VERSION 5.8 ;
BUSBITCHARS "[]" ;
DIVIDERCHAR "/" ;
UNITS
    DATABASE MICRONS 1000 ;
END UNITS

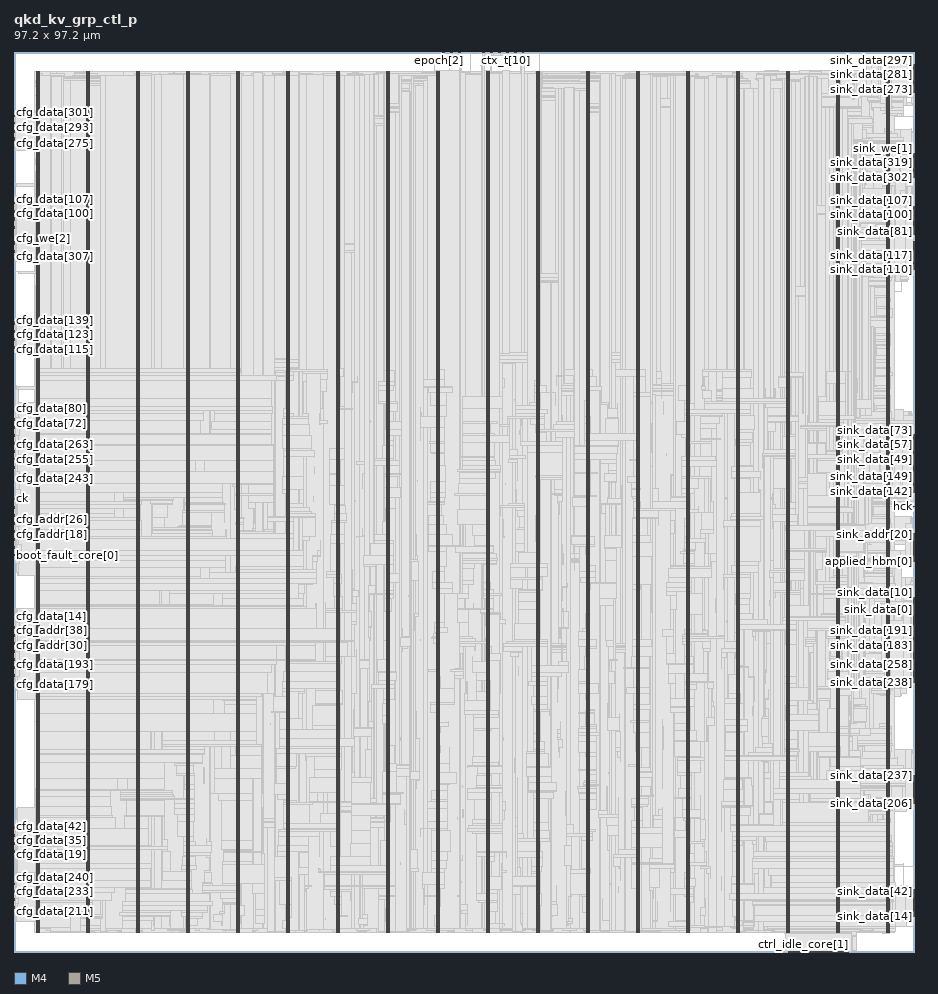
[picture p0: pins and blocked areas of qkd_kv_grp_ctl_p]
MACRO qkd_kv_grp_ctl_p
  FOREIGN qkd_kv_grp_ctl_p 0 0 ;
  CLASS BLOCK ;
  SIZE 97.2 BY 97.2 ;
  PIN applied_hbm[0]
    DIRECTION OUTPUT ;
    USE SIGNAL ;
    PORT
      LAYER M4 ;
        RECT  97.116 42.192 97.2 42.216 ;
    END
  END applied_hbm[0]
  PIN applied_hbm[1]
    DIRECTION OUTPUT ;
    USE SIGNAL ;
    PORT
      LAYER M4 ;
        RECT  97.116 42.288 97.2 42.312 ;
    END
  END applied_hbm[1]
  PIN applied_hbm[2]
    DIRECTION OUTPUT ;
    USE SIGNAL ;
    PORT
      LAYER M4 ;
        RECT  97.116 42.384 97.2 42.408 ;
    END
  END applied_hbm[2]
  PIN applied_hbm[3]
    DIRECTION OUTPUT ;
    USE SIGNAL ;
    PORT
      LAYER M4 ;
        RECT  97.116 42.48 97.2 42.504 ;
    END
  END applied_hbm[3]
  PIN applied_hbm[4]
    DIRECTION OUTPUT ;
    USE SIGNAL ;
    PORT
      LAYER M4 ;
        RECT  97.116 42.576 97.2 42.6 ;
    END
  END applied_hbm[4]
  PIN boot_fault_core[0]
    DIRECTION OUTPUT ;
    USE SIGNAL ;
    PORT
      LAYER M4 ;
        RECT  0 42.864 0.084 42.888 ;
    END
  END boot_fault_core[0]
  PIN boot_fault_core[1]
    DIRECTION OUTPUT ;
    USE SIGNAL ;
    PORT
      LAYER M4 ;
        RECT  0 42.96 0.084 42.984 ;
    END
  END boot_fault_core[1]
  PIN boot_fault_core[2]
    DIRECTION OUTPUT ;
    USE SIGNAL ;
    PORT
      LAYER M4 ;
        RECT  0 43.056 0.084 43.08 ;
    END
  END boot_fault_core[2]
  PIN boot_fault_core[3]
    DIRECTION OUTPUT ;
    USE SIGNAL ;
    PORT
      LAYER M4 ;
        RECT  0 43.152 0.084 43.176 ;
    END
  END boot_fault_core[3]
  PIN boot_fault_core[4]
    DIRECTION OUTPUT ;
    USE SIGNAL ;
    PORT
      LAYER M4 ;
        RECT  0 43.248 0.084 43.272 ;
    END
  END boot_fault_core[4]
  PIN boot_fault_hbm[0]
    DIRECTION OUTPUT ;
    USE SIGNAL ;
    PORT
      LAYER M4 ;
        RECT  97.116 42.672 97.2 42.696 ;
    END
  END boot_fault_hbm[0]
  PIN boot_fault_hbm[1]
    DIRECTION OUTPUT ;
    USE SIGNAL ;
    PORT
      LAYER M4 ;
        RECT  97.116 42.768 97.2 42.792 ;
    END
  END boot_fault_hbm[1]
  PIN boot_fault_hbm[2]
    DIRECTION OUTPUT ;
    USE SIGNAL ;
    PORT
      LAYER M4 ;
        RECT  97.116 42.864 97.2 42.888 ;
    END
  END boot_fault_hbm[2]
  PIN boot_fault_hbm[3]
    DIRECTION OUTPUT ;
    USE SIGNAL ;
    PORT
      LAYER M4 ;
        RECT  97.116 42.96 97.2 42.984 ;
    END
  END boot_fault_hbm[3]
  PIN boot_fault_hbm[4]
    DIRECTION OUTPUT ;
    USE SIGNAL ;
    PORT
      LAYER M4 ;
        RECT  97.116 43.056 97.2 43.08 ;
    END
  END boot_fault_hbm[4]
  PIN cfg_addr[0]
    DIRECTION INPUT ;
    USE SIGNAL ;
    PORT
      LAYER M4 ;
        RECT  0 43.344 0.084 43.368 ;
    END
  END cfg_addr[0]
  PIN cfg_addr[10]
    DIRECTION INPUT ;
    USE SIGNAL ;
    PORT
      LAYER M4 ;
        RECT  0 44.304 0.084 44.328 ;
    END
  END cfg_addr[10]
  PIN cfg_addr[11]
    DIRECTION INPUT ;
    USE SIGNAL ;
    PORT
      LAYER M4 ;
        RECT  0 44.4 0.084 44.424 ;
    END
  END cfg_addr[11]
  PIN cfg_addr[12]
    DIRECTION INPUT ;
    USE SIGNAL ;
    PORT
      LAYER M4 ;
        RECT  0 44.496 0.084 44.52 ;
    END
  END cfg_addr[12]
  PIN cfg_addr[13]
    DIRECTION INPUT ;
    USE SIGNAL ;
    PORT
      LAYER M4 ;
        RECT  0 44.592 0.084 44.616 ;
    END
  END cfg_addr[13]
  PIN cfg_addr[14]
    DIRECTION INPUT ;
    USE SIGNAL ;
    PORT
      LAYER M4 ;
        RECT  0 44.688 0.084 44.712 ;
    END
  END cfg_addr[14]
  PIN cfg_addr[15]
    DIRECTION INPUT ;
    USE SIGNAL ;
    PORT
      LAYER M4 ;
        RECT  0 44.784 0.084 44.808 ;
    END
  END cfg_addr[15]
  PIN cfg_addr[16]
    DIRECTION INPUT ;
    USE SIGNAL ;
    PORT
      LAYER M4 ;
        RECT  0 44.88 0.084 44.904 ;
    END
  END cfg_addr[16]
  PIN cfg_addr[17]
    DIRECTION INPUT ;
    USE SIGNAL ;
    PORT
      LAYER M4 ;
        RECT  0 44.976 0.084 45 ;
    END
  END cfg_addr[17]
  PIN cfg_addr[18]
    DIRECTION INPUT ;
    USE SIGNAL ;
    PORT
      LAYER M4 ;
        RECT  0 45.072 0.084 45.096 ;
    END
  END cfg_addr[18]
  PIN cfg_addr[19]
    DIRECTION INPUT ;
    USE SIGNAL ;
    PORT
      LAYER M4 ;
        RECT  0 45.168 0.084 45.192 ;
    END
  END cfg_addr[19]
  PIN cfg_addr[1]
    DIRECTION INPUT ;
    USE SIGNAL ;
    PORT
      LAYER M4 ;
        RECT  0 43.44 0.084 43.464 ;
    END
  END cfg_addr[1]
  PIN cfg_addr[20]
    DIRECTION INPUT ;
    USE SIGNAL ;
    PORT
      LAYER M4 ;
        RECT  0 45.264 0.084 45.288 ;
    END
  END cfg_addr[20]
  PIN cfg_addr[21]
    DIRECTION INPUT ;
    USE SIGNAL ;
    PORT
      LAYER M4 ;
        RECT  0 45.36 0.084 45.384 ;
    END
  END cfg_addr[21]
  PIN cfg_addr[22]
    DIRECTION INPUT ;
    USE SIGNAL ;
    PORT
      LAYER M4 ;
        RECT  0 45.456 0.084 45.48 ;
    END
  END cfg_addr[22]
  PIN cfg_addr[23]
    DIRECTION INPUT ;
    USE SIGNAL ;
    PORT
      LAYER M4 ;
        RECT  0 45.552 0.084 45.576 ;
    END
  END cfg_addr[23]
  PIN cfg_addr[24]
    DIRECTION INPUT ;
    USE SIGNAL ;
    PORT
      LAYER M4 ;
        RECT  0 45.648 0.084 45.672 ;
    END
  END cfg_addr[24]
  PIN cfg_addr[25]
    DIRECTION INPUT ;
    USE SIGNAL ;
    PORT
      LAYER M4 ;
        RECT  0 45.744 0.084 45.768 ;
    END
  END cfg_addr[25]
  PIN cfg_addr[26]
    DIRECTION INPUT ;
    USE SIGNAL ;
    PORT
      LAYER M4 ;
        RECT  0 45.84 0.084 45.864 ;
    END
  END cfg_addr[26]
  PIN cfg_addr[27]
    DIRECTION INPUT ;
    USE SIGNAL ;
    PORT
      LAYER M4 ;
        RECT  0 32.784 0.084 32.808 ;
    END
  END cfg_addr[27]
  PIN cfg_addr[28]
    DIRECTION INPUT ;
    USE SIGNAL ;
    PORT
      LAYER M4 ;
        RECT  0 32.88 0.084 32.904 ;
    END
  END cfg_addr[28]
  PIN cfg_addr[29]
    DIRECTION INPUT ;
    USE SIGNAL ;
    PORT
      LAYER M4 ;
        RECT  0 32.976 0.084 33 ;
    END
  END cfg_addr[29]
  PIN cfg_addr[2]
    DIRECTION INPUT ;
    USE SIGNAL ;
    PORT
      LAYER M4 ;
        RECT  0 43.536 0.084 43.56 ;
    END
  END cfg_addr[2]
  PIN cfg_addr[30]
    DIRECTION INPUT ;
    USE SIGNAL ;
    PORT
      LAYER M4 ;
        RECT  0 33.072 0.084 33.096 ;
    END
  END cfg_addr[30]
  PIN cfg_addr[31]
    DIRECTION INPUT ;
    USE SIGNAL ;
    PORT
      LAYER M4 ;
        RECT  0 33.168 0.084 33.192 ;
    END
  END cfg_addr[31]
  PIN cfg_addr[32]
    DIRECTION INPUT ;
    USE SIGNAL ;
    PORT
      LAYER M4 ;
        RECT  0 33.264 0.084 33.288 ;
    END
  END cfg_addr[32]
  PIN cfg_addr[33]
    DIRECTION INPUT ;
    USE SIGNAL ;
    PORT
      LAYER M4 ;
        RECT  0 33.36 0.084 33.384 ;
    END
  END cfg_addr[33]
  PIN cfg_addr[34]
    DIRECTION INPUT ;
    USE SIGNAL ;
    PORT
      LAYER M4 ;
        RECT  0 33.456 0.084 33.48 ;
    END
  END cfg_addr[34]
  PIN cfg_addr[35]
    DIRECTION INPUT ;
    USE SIGNAL ;
    PORT
      LAYER M4 ;
        RECT  0 33.552 0.084 33.576 ;
    END
  END cfg_addr[35]
  PIN cfg_addr[36]
    DIRECTION INPUT ;
    USE SIGNAL ;
    PORT
      LAYER M4 ;
        RECT  0 33.648 0.084 33.672 ;
    END
  END cfg_addr[36]
  PIN cfg_addr[37]
    DIRECTION INPUT ;
    USE SIGNAL ;
    PORT
      LAYER M4 ;
        RECT  0 33.744 0.084 33.768 ;
    END
  END cfg_addr[37]
  PIN cfg_addr[38]
    DIRECTION INPUT ;
    USE SIGNAL ;
    PORT
      LAYER M4 ;
        RECT  0 33.84 0.084 33.864 ;
    END
  END cfg_addr[38]
  PIN cfg_addr[39]
    DIRECTION INPUT ;
    USE SIGNAL ;
    PORT
      LAYER M4 ;
        RECT  0 33.936 0.084 33.96 ;
    END
  END cfg_addr[39]
  PIN cfg_addr[3]
    DIRECTION INPUT ;
    USE SIGNAL ;
    PORT
      LAYER M4 ;
        RECT  0 43.632 0.084 43.656 ;
    END
  END cfg_addr[3]
  PIN cfg_addr[4]
    DIRECTION INPUT ;
    USE SIGNAL ;
    PORT
      LAYER M4 ;
        RECT  0 43.728 0.084 43.752 ;
    END
  END cfg_addr[4]
  PIN cfg_addr[5]
    DIRECTION INPUT ;
    USE SIGNAL ;
    PORT
      LAYER M4 ;
        RECT  0 43.824 0.084 43.848 ;
    END
  END cfg_addr[5]
  PIN cfg_addr[6]
    DIRECTION INPUT ;
    USE SIGNAL ;
    PORT
      LAYER M4 ;
        RECT  0 43.92 0.084 43.944 ;
    END
  END cfg_addr[6]
  PIN cfg_addr[7]
    DIRECTION INPUT ;
    USE SIGNAL ;
    PORT
      LAYER M4 ;
        RECT  0 44.016 0.084 44.04 ;
    END
  END cfg_addr[7]
  PIN cfg_addr[8]
    DIRECTION INPUT ;
    USE SIGNAL ;
    PORT
      LAYER M4 ;
        RECT  0 44.112 0.084 44.136 ;
    END
  END cfg_addr[8]
  PIN cfg_addr[9]
    DIRECTION INPUT ;
    USE SIGNAL ;
    PORT
      LAYER M4 ;
        RECT  0 44.208 0.084 44.232 ;
    END
  END cfg_addr[9]
  PIN cfg_data[0]
    DIRECTION INPUT ;
    USE SIGNAL ;
    PORT
      LAYER M4 ;
        RECT  0 34.032 0.084 34.056 ;
    END
  END cfg_data[0]
  PIN cfg_data[100]
    DIRECTION INPUT ;
    USE SIGNAL ;
    PORT
      LAYER M4 ;
        RECT  0 79.728 0.084 79.752 ;
    END
  END cfg_data[100]
  PIN cfg_data[101]
    DIRECTION INPUT ;
    USE SIGNAL ;
    PORT
      LAYER M4 ;
        RECT  0 79.824 0.084 79.848 ;
    END
  END cfg_data[101]
  PIN cfg_data[102]
    DIRECTION INPUT ;
    USE SIGNAL ;
    PORT
      LAYER M4 ;
        RECT  0 79.92 0.084 79.944 ;
    END
  END cfg_data[102]
  PIN cfg_data[103]
    DIRECTION INPUT ;
    USE SIGNAL ;
    PORT
      LAYER M4 ;
        RECT  0 80.016 0.084 80.04 ;
    END
  END cfg_data[103]
  PIN cfg_data[104]
    DIRECTION INPUT ;
    USE SIGNAL ;
    PORT
      LAYER M4 ;
        RECT  0 80.112 0.084 80.136 ;
    END
  END cfg_data[104]
  PIN cfg_data[105]
    DIRECTION INPUT ;
    USE SIGNAL ;
    PORT
      LAYER M4 ;
        RECT  0 80.208 0.084 80.232 ;
    END
  END cfg_data[105]
  PIN cfg_data[106]
    DIRECTION INPUT ;
    USE SIGNAL ;
    PORT
      LAYER M4 ;
        RECT  0 80.304 0.084 80.328 ;
    END
  END cfg_data[106]
  PIN cfg_data[107]
    DIRECTION INPUT ;
    USE SIGNAL ;
    PORT
      LAYER M4 ;
        RECT  0 80.4 0.084 80.424 ;
    END
  END cfg_data[107]
  PIN cfg_data[108]
    DIRECTION INPUT ;
    USE SIGNAL ;
    PORT
      LAYER M4 ;
        RECT  0 80.496 0.084 80.52 ;
    END
  END cfg_data[108]
  PIN cfg_data[109]
    DIRECTION INPUT ;
    USE SIGNAL ;
    PORT
      LAYER M4 ;
        RECT  0 80.592 0.084 80.616 ;
    END
  END cfg_data[109]
  PIN cfg_data[10]
    DIRECTION INPUT ;
    USE SIGNAL ;
    PORT
      LAYER M4 ;
        RECT  0 34.992 0.084 35.016 ;
    END
  END cfg_data[10]
  PIN cfg_data[110]
    DIRECTION INPUT ;
    USE SIGNAL ;
    PORT
      LAYER M4 ;
        RECT  0 80.688 0.084 80.712 ;
    END
  END cfg_data[110]
  PIN cfg_data[111]
    DIRECTION INPUT ;
    USE SIGNAL ;
    PORT
      LAYER M4 ;
        RECT  0 80.784 0.084 80.808 ;
    END
  END cfg_data[111]
  PIN cfg_data[112]
    DIRECTION INPUT ;
    USE SIGNAL ;
    PORT
      LAYER M4 ;
        RECT  0 80.88 0.084 80.904 ;
    END
  END cfg_data[112]
  PIN cfg_data[113]
    DIRECTION INPUT ;
    USE SIGNAL ;
    PORT
      LAYER M4 ;
        RECT  0 80.976 0.084 81 ;
    END
  END cfg_data[113]
  PIN cfg_data[114]
    DIRECTION INPUT ;
    USE SIGNAL ;
    PORT
      LAYER M4 ;
        RECT  0 81.072 0.084 81.096 ;
    END
  END cfg_data[114]
  PIN cfg_data[115]
    DIRECTION INPUT ;
    USE SIGNAL ;
    PORT
      LAYER M4 ;
        RECT  0 65.04 0.084 65.064 ;
    END
  END cfg_data[115]
  PIN cfg_data[116]
    DIRECTION INPUT ;
    USE SIGNAL ;
    PORT
      LAYER M4 ;
        RECT  0 65.136 0.084 65.16 ;
    END
  END cfg_data[116]
  PIN cfg_data[117]
    DIRECTION INPUT ;
    USE SIGNAL ;
    PORT
      LAYER M4 ;
        RECT  0 65.232 0.084 65.256 ;
    END
  END cfg_data[117]
  PIN cfg_data[118]
    DIRECTION INPUT ;
    USE SIGNAL ;
    PORT
      LAYER M4 ;
        RECT  0 65.328 0.084 65.352 ;
    END
  END cfg_data[118]
  PIN cfg_data[119]
    DIRECTION INPUT ;
    USE SIGNAL ;
    PORT
      LAYER M4 ;
        RECT  0 65.424 0.084 65.448 ;
    END
  END cfg_data[119]
  PIN cfg_data[11]
    DIRECTION INPUT ;
    USE SIGNAL ;
    PORT
      LAYER M4 ;
        RECT  0 35.088 0.084 35.112 ;
    END
  END cfg_data[11]
  PIN cfg_data[120]
    DIRECTION INPUT ;
    USE SIGNAL ;
    PORT
      LAYER M4 ;
        RECT  0 65.52 0.084 65.544 ;
    END
  END cfg_data[120]
  PIN cfg_data[121]
    DIRECTION INPUT ;
    USE SIGNAL ;
    PORT
      LAYER M4 ;
        RECT  0 65.616 0.084 65.64 ;
    END
  END cfg_data[121]
  PIN cfg_data[122]
    DIRECTION INPUT ;
    USE SIGNAL ;
    PORT
      LAYER M4 ;
        RECT  0 65.712 0.084 65.736 ;
    END
  END cfg_data[122]
  PIN cfg_data[123]
    DIRECTION INPUT ;
    USE SIGNAL ;
    PORT
      LAYER M4 ;
        RECT  0 65.808 0.084 65.832 ;
    END
  END cfg_data[123]
  PIN cfg_data[124]
    DIRECTION INPUT ;
    USE SIGNAL ;
    PORT
      LAYER M4 ;
        RECT  0 65.904 0.084 65.928 ;
    END
  END cfg_data[124]
  PIN cfg_data[125]
    DIRECTION INPUT ;
    USE SIGNAL ;
    PORT
      LAYER M4 ;
        RECT  0 66 0.084 66.024 ;
    END
  END cfg_data[125]
  PIN cfg_data[126]
    DIRECTION INPUT ;
    USE SIGNAL ;
    PORT
      LAYER M4 ;
        RECT  0 66.096 0.084 66.12 ;
    END
  END cfg_data[126]
  PIN cfg_data[127]
    DIRECTION INPUT ;
    USE SIGNAL ;
    PORT
      LAYER M4 ;
        RECT  0 66.192 0.084 66.216 ;
    END
  END cfg_data[127]
  PIN cfg_data[128]
    DIRECTION INPUT ;
    USE SIGNAL ;
    PORT
      LAYER M4 ;
        RECT  0 66.288 0.084 66.312 ;
    END
  END cfg_data[128]
  PIN cfg_data[129]
    DIRECTION INPUT ;
    USE SIGNAL ;
    PORT
      LAYER M4 ;
        RECT  0 66.384 0.084 66.408 ;
    END
  END cfg_data[129]
  PIN cfg_data[12]
    DIRECTION INPUT ;
    USE SIGNAL ;
    PORT
      LAYER M4 ;
        RECT  0 35.184 0.084 35.208 ;
    END
  END cfg_data[12]
  PIN cfg_data[130]
    DIRECTION INPUT ;
    USE SIGNAL ;
    PORT
      LAYER M4 ;
        RECT  0 66.48 0.084 66.504 ;
    END
  END cfg_data[130]
  PIN cfg_data[131]
    DIRECTION INPUT ;
    USE SIGNAL ;
    PORT
      LAYER M4 ;
        RECT  0 66.576 0.084 66.6 ;
    END
  END cfg_data[131]
  PIN cfg_data[132]
    DIRECTION INPUT ;
    USE SIGNAL ;
    PORT
      LAYER M4 ;
        RECT  0 66.672 0.084 66.696 ;
    END
  END cfg_data[132]
  PIN cfg_data[133]
    DIRECTION INPUT ;
    USE SIGNAL ;
    PORT
      LAYER M4 ;
        RECT  0 66.768 0.084 66.792 ;
    END
  END cfg_data[133]
  PIN cfg_data[134]
    DIRECTION INPUT ;
    USE SIGNAL ;
    PORT
      LAYER M4 ;
        RECT  0 66.864 0.084 66.888 ;
    END
  END cfg_data[134]
  PIN cfg_data[135]
    DIRECTION INPUT ;
    USE SIGNAL ;
    PORT
      LAYER M4 ;
        RECT  0 66.96 0.084 66.984 ;
    END
  END cfg_data[135]
  PIN cfg_data[136]
    DIRECTION INPUT ;
    USE SIGNAL ;
    PORT
      LAYER M4 ;
        RECT  0 67.056 0.084 67.08 ;
    END
  END cfg_data[136]
  PIN cfg_data[137]
    DIRECTION INPUT ;
    USE SIGNAL ;
    PORT
      LAYER M4 ;
        RECT  0 67.152 0.084 67.176 ;
    END
  END cfg_data[137]
  PIN cfg_data[138]
    DIRECTION INPUT ;
    USE SIGNAL ;
    PORT
      LAYER M4 ;
        RECT  0 67.248 0.084 67.272 ;
    END
  END cfg_data[138]
  PIN cfg_data[139]
    DIRECTION INPUT ;
    USE SIGNAL ;
    PORT
      LAYER M4 ;
        RECT  0 67.344 0.084 67.368 ;
    END
  END cfg_data[139]
  PIN cfg_data[13]
    DIRECTION INPUT ;
    USE SIGNAL ;
    PORT
      LAYER M4 ;
        RECT  0 35.28 0.084 35.304 ;
    END
  END cfg_data[13]
  PIN cfg_data[140]
    DIRECTION INPUT ;
    USE SIGNAL ;
    PORT
      LAYER M4 ;
        RECT  0 67.44 0.084 67.464 ;
    END
  END cfg_data[140]
  PIN cfg_data[141]
    DIRECTION INPUT ;
    USE SIGNAL ;
    PORT
      LAYER M4 ;
        RECT  0 67.536 0.084 67.56 ;
    END
  END cfg_data[141]
  PIN cfg_data[142]
    DIRECTION INPUT ;
    USE SIGNAL ;
    PORT
      LAYER M4 ;
        RECT  0 67.632 0.084 67.656 ;
    END
  END cfg_data[142]
  PIN cfg_data[143]
    DIRECTION INPUT ;
    USE SIGNAL ;
    PORT
      LAYER M4 ;
        RECT  0 67.728 0.084 67.752 ;
    END
  END cfg_data[143]
  PIN cfg_data[144]
    DIRECTION INPUT ;
    USE SIGNAL ;
    PORT
      LAYER M4 ;
        RECT  0 67.824 0.084 67.848 ;
    END
  END cfg_data[144]
  PIN cfg_data[145]
    DIRECTION INPUT ;
    USE SIGNAL ;
    PORT
      LAYER M4 ;
        RECT  0 67.92 0.084 67.944 ;
    END
  END cfg_data[145]
  PIN cfg_data[146]
    DIRECTION INPUT ;
    USE SIGNAL ;
    PORT
      LAYER M4 ;
        RECT  0 68.016 0.084 68.04 ;
    END
  END cfg_data[146]
  PIN cfg_data[147]
    DIRECTION INPUT ;
    USE SIGNAL ;
    PORT
      LAYER M4 ;
        RECT  0 45.936 0.084 45.96 ;
    END
  END cfg_data[147]
  PIN cfg_data[148]
    DIRECTION INPUT ;
    USE SIGNAL ;
    PORT
      LAYER M4 ;
        RECT  0 46.032 0.084 46.056 ;
    END
  END cfg_data[148]
  PIN cfg_data[149]
    DIRECTION INPUT ;
    USE SIGNAL ;
    PORT
      LAYER M4 ;
        RECT  0 46.128 0.084 46.152 ;
    END
  END cfg_data[149]
  PIN cfg_data[14]
    DIRECTION INPUT ;
    USE SIGNAL ;
    PORT
      LAYER M4 ;
        RECT  0 35.376 0.084 35.4 ;
    END
  END cfg_data[14]
  PIN cfg_data[150]
    DIRECTION INPUT ;
    USE SIGNAL ;
    PORT
      LAYER M4 ;
        RECT  0 46.224 0.084 46.248 ;
    END
  END cfg_data[150]
  PIN cfg_data[151]
    DIRECTION INPUT ;
    USE SIGNAL ;
    PORT
      LAYER M4 ;
        RECT  0 46.32 0.084 46.344 ;
    END
  END cfg_data[151]
  PIN cfg_data[152]
    DIRECTION INPUT ;
    USE SIGNAL ;
    PORT
      LAYER M4 ;
        RECT  0 46.416 0.084 46.44 ;
    END
  END cfg_data[152]
  PIN cfg_data[153]
    DIRECTION INPUT ;
    USE SIGNAL ;
    PORT
      LAYER M4 ;
        RECT  0 46.512 0.084 46.536 ;
    END
  END cfg_data[153]
  PIN cfg_data[154]
    DIRECTION INPUT ;
    USE SIGNAL ;
    PORT
      LAYER M4 ;
        RECT  0 46.608 0.084 46.632 ;
    END
  END cfg_data[154]
  PIN cfg_data[155]
    DIRECTION INPUT ;
    USE SIGNAL ;
    PORT
      LAYER M4 ;
        RECT  0 46.704 0.084 46.728 ;
    END
  END cfg_data[155]
  PIN cfg_data[156]
    DIRECTION INPUT ;
    USE SIGNAL ;
    PORT
      LAYER M4 ;
        RECT  0 46.8 0.084 46.824 ;
    END
  END cfg_data[156]
  PIN cfg_data[157]
    DIRECTION INPUT ;
    USE SIGNAL ;
    PORT
      LAYER M4 ;
        RECT  0 46.896 0.084 46.92 ;
    END
  END cfg_data[157]
  PIN cfg_data[158]
    DIRECTION INPUT ;
    USE SIGNAL ;
    PORT
      LAYER M4 ;
        RECT  0 46.992 0.084 47.016 ;
    END
  END cfg_data[158]
  PIN cfg_data[159]
    DIRECTION INPUT ;
    USE SIGNAL ;
    PORT
      LAYER M4 ;
        RECT  0 47.088 0.084 47.112 ;
    END
  END cfg_data[159]
  PIN cfg_data[15]
    DIRECTION INPUT ;
    USE SIGNAL ;
    PORT
      LAYER M4 ;
        RECT  0 35.472 0.084 35.496 ;
    END
  END cfg_data[15]
  PIN cfg_data[160]
    DIRECTION INPUT ;
    USE SIGNAL ;
    PORT
      LAYER M4 ;
        RECT  0 47.184 0.084 47.208 ;
    END
  END cfg_data[160]
  PIN cfg_data[161]
    DIRECTION INPUT ;
    USE SIGNAL ;
    PORT
      LAYER M4 ;
        RECT  0 47.28 0.084 47.304 ;
    END
  END cfg_data[161]
  PIN cfg_data[162]
    DIRECTION INPUT ;
    USE SIGNAL ;
    PORT
      LAYER M4 ;
        RECT  0 47.376 0.084 47.4 ;
    END
  END cfg_data[162]
  PIN cfg_data[163]
    DIRECTION INPUT ;
    USE SIGNAL ;
    PORT
      LAYER M4 ;
        RECT  0 47.472 0.084 47.496 ;
    END
  END cfg_data[163]
  PIN cfg_data[164]
    DIRECTION INPUT ;
    USE SIGNAL ;
    PORT
      LAYER M4 ;
        RECT  0 47.568 0.084 47.592 ;
    END
  END cfg_data[164]
  PIN cfg_data[165]
    DIRECTION INPUT ;
    USE SIGNAL ;
    PORT
      LAYER M4 ;
        RECT  0 47.664 0.084 47.688 ;
    END
  END cfg_data[165]
  PIN cfg_data[166]
    DIRECTION INPUT ;
    USE SIGNAL ;
    PORT
      LAYER M4 ;
        RECT  0 47.76 0.084 47.784 ;
    END
  END cfg_data[166]
  PIN cfg_data[167]
    DIRECTION INPUT ;
    USE SIGNAL ;
    PORT
      LAYER M4 ;
        RECT  0 47.856 0.084 47.88 ;
    END
  END cfg_data[167]
  PIN cfg_data[168]
    DIRECTION INPUT ;
    USE SIGNAL ;
    PORT
      LAYER M4 ;
        RECT  0 47.952 0.084 47.976 ;
    END
  END cfg_data[168]
  PIN cfg_data[169]
    DIRECTION INPUT ;
    USE SIGNAL ;
    PORT
      LAYER M4 ;
        RECT  0 48.048 0.084 48.072 ;
    END
  END cfg_data[169]
  PIN cfg_data[16]
    DIRECTION INPUT ;
    USE SIGNAL ;
    PORT
      LAYER M4 ;
        RECT  0 35.568 0.084 35.592 ;
    END
  END cfg_data[16]
  PIN cfg_data[170]
    DIRECTION INPUT ;
    USE SIGNAL ;
    PORT
      LAYER M4 ;
        RECT  0 48.144 0.084 48.168 ;
    END
  END cfg_data[170]
  PIN cfg_data[171]
    DIRECTION INPUT ;
    USE SIGNAL ;
    PORT
      LAYER M4 ;
        RECT  0 48.24 0.084 48.264 ;
    END
  END cfg_data[171]
  PIN cfg_data[172]
    DIRECTION INPUT ;
    USE SIGNAL ;
    PORT
      LAYER M4 ;
        RECT  0 48.336 0.084 48.36 ;
    END
  END cfg_data[172]
  PIN cfg_data[173]
    DIRECTION INPUT ;
    USE SIGNAL ;
    PORT
      LAYER M4 ;
        RECT  0 48.432 0.084 48.456 ;
    END
  END cfg_data[173]
  PIN cfg_data[174]
    DIRECTION INPUT ;
    USE SIGNAL ;
    PORT
      LAYER M4 ;
        RECT  0 48.528 0.084 48.552 ;
    END
  END cfg_data[174]
  PIN cfg_data[175]
    DIRECTION INPUT ;
    USE SIGNAL ;
    PORT
      LAYER M4 ;
        RECT  0 48.624 0.084 48.648 ;
    END
  END cfg_data[175]
  PIN cfg_data[176]
    DIRECTION INPUT ;
    USE SIGNAL ;
    PORT
      LAYER M4 ;
        RECT  0 48.72 0.084 48.744 ;
    END
  END cfg_data[176]
  PIN cfg_data[177]
    DIRECTION INPUT ;
    USE SIGNAL ;
    PORT
      LAYER M4 ;
        RECT  0 48.816 0.084 48.84 ;
    END
  END cfg_data[177]
  PIN cfg_data[178]
    DIRECTION INPUT ;
    USE SIGNAL ;
    PORT
      LAYER M4 ;
        RECT  0 48.912 0.084 48.936 ;
    END
  END cfg_data[178]
  PIN cfg_data[179]
    DIRECTION INPUT ;
    USE SIGNAL ;
    PORT
      LAYER M4 ;
        RECT  0 29.712 0.084 29.736 ;
    END
  END cfg_data[179]
  PIN cfg_data[17]
    DIRECTION INPUT ;
    USE SIGNAL ;
    PORT
      LAYER M4 ;
        RECT  0 35.664 0.084 35.688 ;
    END
  END cfg_data[17]
  PIN cfg_data[180]
    DIRECTION INPUT ;
    USE SIGNAL ;
    PORT
      LAYER M4 ;
        RECT  0 29.808 0.084 29.832 ;
    END
  END cfg_data[180]
  PIN cfg_data[181]
    DIRECTION INPUT ;
    USE SIGNAL ;
    PORT
      LAYER M4 ;
        RECT  0 29.904 0.084 29.928 ;
    END
  END cfg_data[181]
  PIN cfg_data[182]
    DIRECTION INPUT ;
    USE SIGNAL ;
    PORT
      LAYER M4 ;
        RECT  0 30 0.084 30.024 ;
    END
  END cfg_data[182]
  PIN cfg_data[183]
    DIRECTION INPUT ;
    USE SIGNAL ;
    PORT
      LAYER M4 ;
        RECT  0 30.096 0.084 30.12 ;
    END
  END cfg_data[183]
  PIN cfg_data[184]
    DIRECTION INPUT ;
    USE SIGNAL ;
    PORT
      LAYER M4 ;
        RECT  0 30.192 0.084 30.216 ;
    END
  END cfg_data[184]
  PIN cfg_data[185]
    DIRECTION INPUT ;
    USE SIGNAL ;
    PORT
      LAYER M4 ;
        RECT  0 30.288 0.084 30.312 ;
    END
  END cfg_data[185]
  PIN cfg_data[186]
    DIRECTION INPUT ;
    USE SIGNAL ;
    PORT
      LAYER M4 ;
        RECT  0 30.384 0.084 30.408 ;
    END
  END cfg_data[186]
  PIN cfg_data[187]
    DIRECTION INPUT ;
    USE SIGNAL ;
    PORT
      LAYER M4 ;
        RECT  0 30.48 0.084 30.504 ;
    END
  END cfg_data[187]
  PIN cfg_data[188]
    DIRECTION INPUT ;
    USE SIGNAL ;
    PORT
      LAYER M4 ;
        RECT  0 30.576 0.084 30.6 ;
    END
  END cfg_data[188]
  PIN cfg_data[189]
    DIRECTION INPUT ;
    USE SIGNAL ;
    PORT
      LAYER M4 ;
        RECT  0 30.672 0.084 30.696 ;
    END
  END cfg_data[189]
  PIN cfg_data[18]
    DIRECTION INPUT ;
    USE SIGNAL ;
    PORT
      LAYER M4 ;
        RECT  0 35.76 0.084 35.784 ;
    END
  END cfg_data[18]
  PIN cfg_data[190]
    DIRECTION INPUT ;
    USE SIGNAL ;
    PORT
      LAYER M4 ;
        RECT  0 30.768 0.084 30.792 ;
    END
  END cfg_data[190]
  PIN cfg_data[191]
    DIRECTION INPUT ;
    USE SIGNAL ;
    PORT
      LAYER M4 ;
        RECT  0 30.864 0.084 30.888 ;
    END
  END cfg_data[191]
  PIN cfg_data[192]
    DIRECTION INPUT ;
    USE SIGNAL ;
    PORT
      LAYER M4 ;
        RECT  0 30.96 0.084 30.984 ;
    END
  END cfg_data[192]
  PIN cfg_data[193]
    DIRECTION INPUT ;
    USE SIGNAL ;
    PORT
      LAYER M4 ;
        RECT  0 31.056 0.084 31.08 ;
    END
  END cfg_data[193]
  PIN cfg_data[194]
    DIRECTION INPUT ;
    USE SIGNAL ;
    PORT
      LAYER M4 ;
        RECT  0 31.152 0.084 31.176 ;
    END
  END cfg_data[194]
  PIN cfg_data[195]
    DIRECTION INPUT ;
    USE SIGNAL ;
    PORT
      LAYER M4 ;
        RECT  0 31.248 0.084 31.272 ;
    END
  END cfg_data[195]
  PIN cfg_data[196]
    DIRECTION INPUT ;
    USE SIGNAL ;
    PORT
      LAYER M4 ;
        RECT  0 31.344 0.084 31.368 ;
    END
  END cfg_data[196]
  PIN cfg_data[197]
    DIRECTION INPUT ;
    USE SIGNAL ;
    PORT
      LAYER M4 ;
        RECT  0 31.44 0.084 31.464 ;
    END
  END cfg_data[197]
  PIN cfg_data[198]
    DIRECTION INPUT ;
    USE SIGNAL ;
    PORT
      LAYER M4 ;
        RECT  0 31.536 0.084 31.56 ;
    END
  END cfg_data[198]
  PIN cfg_data[199]
    DIRECTION INPUT ;
    USE SIGNAL ;
    PORT
      LAYER M4 ;
        RECT  0 31.632 0.084 31.656 ;
    END
  END cfg_data[199]
  PIN cfg_data[19]
    DIRECTION INPUT ;
    USE SIGNAL ;
    PORT
      LAYER M4 ;
        RECT  0 10.512 0.084 10.536 ;
    END
  END cfg_data[19]
  PIN cfg_data[1]
    DIRECTION INPUT ;
    USE SIGNAL ;
    PORT
      LAYER M4 ;
        RECT  0 34.128 0.084 34.152 ;
    END
  END cfg_data[1]
  PIN cfg_data[200]
    DIRECTION INPUT ;
    USE SIGNAL ;
    PORT
      LAYER M4 ;
        RECT  0 31.728 0.084 31.752 ;
    END
  END cfg_data[200]
  PIN cfg_data[201]
    DIRECTION INPUT ;
    USE SIGNAL ;
    PORT
      LAYER M4 ;
        RECT  0 31.824 0.084 31.848 ;
    END
  END cfg_data[201]
  PIN cfg_data[202]
    DIRECTION INPUT ;
    USE SIGNAL ;
    PORT
      LAYER M4 ;
        RECT  0 31.92 0.084 31.944 ;
    END
  END cfg_data[202]
  PIN cfg_data[203]
    DIRECTION INPUT ;
    USE SIGNAL ;
    PORT
      LAYER M4 ;
        RECT  0 32.016 0.084 32.04 ;
    END
  END cfg_data[203]
  PIN cfg_data[204]
    DIRECTION INPUT ;
    USE SIGNAL ;
    PORT
      LAYER M4 ;
        RECT  0 32.112 0.084 32.136 ;
    END
  END cfg_data[204]
  PIN cfg_data[205]
    DIRECTION INPUT ;
    USE SIGNAL ;
    PORT
      LAYER M4 ;
        RECT  0 32.208 0.084 32.232 ;
    END
  END cfg_data[205]
  PIN cfg_data[206]
    DIRECTION INPUT ;
    USE SIGNAL ;
    PORT
      LAYER M4 ;
        RECT  0 32.304 0.084 32.328 ;
    END
  END cfg_data[206]
  PIN cfg_data[207]
    DIRECTION INPUT ;
    USE SIGNAL ;
    PORT
      LAYER M4 ;
        RECT  0 32.4 0.084 32.424 ;
    END
  END cfg_data[207]
  PIN cfg_data[208]
    DIRECTION INPUT ;
    USE SIGNAL ;
    PORT
      LAYER M4 ;
        RECT  0 32.496 0.084 32.52 ;
    END
  END cfg_data[208]
  PIN cfg_data[209]
    DIRECTION INPUT ;
    USE SIGNAL ;
    PORT
      LAYER M4 ;
        RECT  0 32.592 0.084 32.616 ;
    END
  END cfg_data[209]
  PIN cfg_data[20]
    DIRECTION INPUT ;
    USE SIGNAL ;
    PORT
      LAYER M4 ;
        RECT  0 10.608 0.084 10.632 ;
    END
  END cfg_data[20]
  PIN cfg_data[210]
    DIRECTION INPUT ;
    USE SIGNAL ;
    PORT
      LAYER M4 ;
        RECT  0 32.688 0.084 32.712 ;
    END
  END cfg_data[210]
  PIN cfg_data[211]
    DIRECTION INPUT ;
    USE SIGNAL ;
    PORT
      LAYER M4 ;
        RECT  0 4.368 0.084 4.392 ;
    END
  END cfg_data[211]
  PIN cfg_data[212]
    DIRECTION INPUT ;
    USE SIGNAL ;
    PORT
      LAYER M4 ;
        RECT  0 4.464 0.084 4.488 ;
    END
  END cfg_data[212]
  PIN cfg_data[213]
    DIRECTION INPUT ;
    USE SIGNAL ;
    PORT
      LAYER M4 ;
        RECT  0 4.56 0.084 4.584 ;
    END
  END cfg_data[213]
  PIN cfg_data[214]
    DIRECTION INPUT ;
    USE SIGNAL ;
    PORT
      LAYER M4 ;
        RECT  0 4.656 0.084 4.68 ;
    END
  END cfg_data[214]
  PIN cfg_data[215]
    DIRECTION INPUT ;
    USE SIGNAL ;
    PORT
      LAYER M4 ;
        RECT  0 4.752 0.084 4.776 ;
    END
  END cfg_data[215]
  PIN cfg_data[216]
    DIRECTION INPUT ;
    USE SIGNAL ;
    PORT
      LAYER M4 ;
        RECT  0 4.848 0.084 4.872 ;
    END
  END cfg_data[216]
  PIN cfg_data[217]
    DIRECTION INPUT ;
    USE SIGNAL ;
    PORT
      LAYER M4 ;
        RECT  0 4.944 0.084 4.968 ;
    END
  END cfg_data[217]
  PIN cfg_data[218]
    DIRECTION INPUT ;
    USE SIGNAL ;
    PORT
      LAYER M4 ;
        RECT  0 5.04 0.084 5.064 ;
    END
  END cfg_data[218]
  PIN cfg_data[219]
    DIRECTION INPUT ;
    USE SIGNAL ;
    PORT
      LAYER M4 ;
        RECT  0 5.136 0.084 5.16 ;
    END
  END cfg_data[219]
  PIN cfg_data[21]
    DIRECTION INPUT ;
    USE SIGNAL ;
    PORT
      LAYER M4 ;
        RECT  0 10.704 0.084 10.728 ;
    END
  END cfg_data[21]
  PIN cfg_data[220]
    DIRECTION INPUT ;
    USE SIGNAL ;
    PORT
      LAYER M4 ;
        RECT  0 5.232 0.084 5.256 ;
    END
  END cfg_data[220]
  PIN cfg_data[221]
    DIRECTION INPUT ;
    USE SIGNAL ;
    PORT
      LAYER M4 ;
        RECT  0 5.328 0.084 5.352 ;
    END
  END cfg_data[221]
  PIN cfg_data[222]
    DIRECTION INPUT ;
    USE SIGNAL ;
    PORT
      LAYER M4 ;
        RECT  0 5.424 0.084 5.448 ;
    END
  END cfg_data[222]
  PIN cfg_data[223]
    DIRECTION INPUT ;
    USE SIGNAL ;
    PORT
      LAYER M4 ;
        RECT  0 5.52 0.084 5.544 ;
    END
  END cfg_data[223]
  PIN cfg_data[224]
    DIRECTION INPUT ;
    USE SIGNAL ;
    PORT
      LAYER M4 ;
        RECT  0 5.616 0.084 5.64 ;
    END
  END cfg_data[224]
  PIN cfg_data[225]
    DIRECTION INPUT ;
    USE SIGNAL ;
    PORT
      LAYER M4 ;
        RECT  0 5.712 0.084 5.736 ;
    END
  END cfg_data[225]
  PIN cfg_data[226]
    DIRECTION INPUT ;
    USE SIGNAL ;
    PORT
      LAYER M4 ;
        RECT  0 5.808 0.084 5.832 ;
    END
  END cfg_data[226]
  PIN cfg_data[227]
    DIRECTION INPUT ;
    USE SIGNAL ;
    PORT
      LAYER M4 ;
        RECT  0 5.904 0.084 5.928 ;
    END
  END cfg_data[227]
  PIN cfg_data[228]
    DIRECTION INPUT ;
    USE SIGNAL ;
    PORT
      LAYER M4 ;
        RECT  0 6 0.084 6.024 ;
    END
  END cfg_data[228]
  PIN cfg_data[229]
    DIRECTION INPUT ;
    USE SIGNAL ;
    PORT
      LAYER M4 ;
        RECT  0 6.096 0.084 6.12 ;
    END
  END cfg_data[229]
  PIN cfg_data[22]
    DIRECTION INPUT ;
    USE SIGNAL ;
    PORT
      LAYER M4 ;
        RECT  0 10.8 0.084 10.824 ;
    END
  END cfg_data[22]
  PIN cfg_data[230]
    DIRECTION INPUT ;
    USE SIGNAL ;
    PORT
      LAYER M4 ;
        RECT  0 6.192 0.084 6.216 ;
    END
  END cfg_data[230]
  PIN cfg_data[231]
    DIRECTION INPUT ;
    USE SIGNAL ;
    PORT
      LAYER M4 ;
        RECT  0 6.288 0.084 6.312 ;
    END
  END cfg_data[231]
  PIN cfg_data[232]
    DIRECTION INPUT ;
    USE SIGNAL ;
    PORT
      LAYER M4 ;
        RECT  0 6.384 0.084 6.408 ;
    END
  END cfg_data[232]
  PIN cfg_data[233]
    DIRECTION INPUT ;
    USE SIGNAL ;
    PORT
      LAYER M4 ;
        RECT  0 6.48 0.084 6.504 ;
    END
  END cfg_data[233]
  PIN cfg_data[234]
    DIRECTION INPUT ;
    USE SIGNAL ;
    PORT
      LAYER M4 ;
        RECT  0 6.576 0.084 6.6 ;
    END
  END cfg_data[234]
  PIN cfg_data[235]
    DIRECTION INPUT ;
    USE SIGNAL ;
    PORT
      LAYER M4 ;
        RECT  0 6.672 0.084 6.696 ;
    END
  END cfg_data[235]
  PIN cfg_data[236]
    DIRECTION INPUT ;
    USE SIGNAL ;
    PORT
      LAYER M4 ;
        RECT  0 6.768 0.084 6.792 ;
    END
  END cfg_data[236]
  PIN cfg_data[237]
    DIRECTION INPUT ;
    USE SIGNAL ;
    PORT
      LAYER M4 ;
        RECT  0 6.864 0.084 6.888 ;
    END
  END cfg_data[237]
  PIN cfg_data[238]
    DIRECTION INPUT ;
    USE SIGNAL ;
    PORT
      LAYER M4 ;
        RECT  0 6.96 0.084 6.984 ;
    END
  END cfg_data[238]
  PIN cfg_data[239]
    DIRECTION INPUT ;
    USE SIGNAL ;
    PORT
      LAYER M4 ;
        RECT  0 7.056 0.084 7.08 ;
    END
  END cfg_data[239]
  PIN cfg_data[23]
    DIRECTION INPUT ;
    USE SIGNAL ;
    PORT
      LAYER M4 ;
        RECT  0 10.896 0.084 10.92 ;
    END
  END cfg_data[23]
  PIN cfg_data[240]
    DIRECTION INPUT ;
    USE SIGNAL ;
    PORT
      LAYER M4 ;
        RECT  0 7.152 0.084 7.176 ;
    END
  END cfg_data[240]
  PIN cfg_data[241]
    DIRECTION INPUT ;
    USE SIGNAL ;
    PORT
      LAYER M4 ;
        RECT  0 7.248 0.084 7.272 ;
    END
  END cfg_data[241]
  PIN cfg_data[242]
    DIRECTION INPUT ;
    USE SIGNAL ;
    PORT
      LAYER M4 ;
        RECT  0 7.344 0.084 7.368 ;
    END
  END cfg_data[242]
  PIN cfg_data[243]
    DIRECTION INPUT ;
    USE SIGNAL ;
    PORT
      LAYER M4 ;
        RECT  0 51.984 0.084 52.008 ;
    END
  END cfg_data[243]
  PIN cfg_data[244]
    DIRECTION INPUT ;
    USE SIGNAL ;
    PORT
      LAYER M4 ;
        RECT  0 52.08 0.084 52.104 ;
    END
  END cfg_data[244]
  PIN cfg_data[245]
    DIRECTION INPUT ;
    USE SIGNAL ;
    PORT
      LAYER M4 ;
        RECT  0 52.176 0.084 52.2 ;
    END
  END cfg_data[245]
  PIN cfg_data[246]
    DIRECTION INPUT ;
    USE SIGNAL ;
    PORT
      LAYER M4 ;
        RECT  0 52.272 0.084 52.296 ;
    END
  END cfg_data[246]
  PIN cfg_data[247]
    DIRECTION INPUT ;
    USE SIGNAL ;
    PORT
      LAYER M4 ;
        RECT  0 52.368 0.084 52.392 ;
    END
  END cfg_data[247]
  PIN cfg_data[248]
    DIRECTION INPUT ;
    USE SIGNAL ;
    PORT
      LAYER M4 ;
        RECT  0 52.464 0.084 52.488 ;
    END
  END cfg_data[248]
  PIN cfg_data[249]
    DIRECTION INPUT ;
    USE SIGNAL ;
    PORT
      LAYER M4 ;
        RECT  0 52.56 0.084 52.584 ;
    END
  END cfg_data[249]
  PIN cfg_data[24]
    DIRECTION INPUT ;
    USE SIGNAL ;
    PORT
      LAYER M4 ;
        RECT  0 10.992 0.084 11.016 ;
    END
  END cfg_data[24]
  PIN cfg_data[250]
    DIRECTION INPUT ;
    USE SIGNAL ;
    PORT
      LAYER M4 ;
        RECT  0 52.656 0.084 52.68 ;
    END
  END cfg_data[250]
  PIN cfg_data[251]
    DIRECTION INPUT ;
    USE SIGNAL ;
    PORT
      LAYER M4 ;
        RECT  0 52.752 0.084 52.776 ;
    END
  END cfg_data[251]
  PIN cfg_data[252]
    DIRECTION INPUT ;
    USE SIGNAL ;
    PORT
      LAYER M4 ;
        RECT  0 52.848 0.084 52.872 ;
    END
  END cfg_data[252]
  PIN cfg_data[253]
    DIRECTION INPUT ;
    USE SIGNAL ;
    PORT
      LAYER M4 ;
        RECT  0 52.944 0.084 52.968 ;
    END
  END cfg_data[253]
  PIN cfg_data[254]
    DIRECTION INPUT ;
    USE SIGNAL ;
    PORT
      LAYER M4 ;
        RECT  0 53.04 0.084 53.064 ;
    END
  END cfg_data[254]
  PIN cfg_data[255]
    DIRECTION INPUT ;
    USE SIGNAL ;
    PORT
      LAYER M4 ;
        RECT  0 53.136 0.084 53.16 ;
    END
  END cfg_data[255]
  PIN cfg_data[256]
    DIRECTION INPUT ;
    USE SIGNAL ;
    PORT
      LAYER M4 ;
        RECT  0 53.232 0.084 53.256 ;
    END
  END cfg_data[256]
  PIN cfg_data[257]
    DIRECTION INPUT ;
    USE SIGNAL ;
    PORT
      LAYER M4 ;
        RECT  0 53.328 0.084 53.352 ;
    END
  END cfg_data[257]
  PIN cfg_data[258]
    DIRECTION INPUT ;
    USE SIGNAL ;
    PORT
      LAYER M4 ;
        RECT  0 53.424 0.084 53.448 ;
    END
  END cfg_data[258]
  PIN cfg_data[259]
    DIRECTION INPUT ;
    USE SIGNAL ;
    PORT
      LAYER M4 ;
        RECT  0 53.52 0.084 53.544 ;
    END
  END cfg_data[259]
  PIN cfg_data[25]
    DIRECTION INPUT ;
    USE SIGNAL ;
    PORT
      LAYER M4 ;
        RECT  0 11.088 0.084 11.112 ;
    END
  END cfg_data[25]
  PIN cfg_data[260]
    DIRECTION INPUT ;
    USE SIGNAL ;
    PORT
      LAYER M4 ;
        RECT  0 53.616 0.084 53.64 ;
    END
  END cfg_data[260]
  PIN cfg_data[261]
    DIRECTION INPUT ;
    USE SIGNAL ;
    PORT
      LAYER M4 ;
        RECT  0 53.712 0.084 53.736 ;
    END
  END cfg_data[261]
  PIN cfg_data[262]
    DIRECTION INPUT ;
    USE SIGNAL ;
    PORT
      LAYER M4 ;
        RECT  0 53.808 0.084 53.832 ;
    END
  END cfg_data[262]
  PIN cfg_data[263]
    DIRECTION INPUT ;
    USE SIGNAL ;
    PORT
      LAYER M4 ;
        RECT  0 53.904 0.084 53.928 ;
    END
  END cfg_data[263]
  PIN cfg_data[264]
    DIRECTION INPUT ;
    USE SIGNAL ;
    PORT
      LAYER M4 ;
        RECT  0 54 0.084 54.024 ;
    END
  END cfg_data[264]
  PIN cfg_data[265]
    DIRECTION INPUT ;
    USE SIGNAL ;
    PORT
      LAYER M4 ;
        RECT  0 54.096 0.084 54.12 ;
    END
  END cfg_data[265]
  PIN cfg_data[266]
    DIRECTION INPUT ;
    USE SIGNAL ;
    PORT
      LAYER M4 ;
        RECT  0 54.192 0.084 54.216 ;
    END
  END cfg_data[266]
  PIN cfg_data[267]
    DIRECTION INPUT ;
    USE SIGNAL ;
    PORT
      LAYER M4 ;
        RECT  0 54.288 0.084 54.312 ;
    END
  END cfg_data[267]
  PIN cfg_data[268]
    DIRECTION INPUT ;
    USE SIGNAL ;
    PORT
      LAYER M4 ;
        RECT  0 54.384 0.084 54.408 ;
    END
  END cfg_data[268]
  PIN cfg_data[269]
    DIRECTION INPUT ;
    USE SIGNAL ;
    PORT
      LAYER M4 ;
        RECT  0 54.48 0.084 54.504 ;
    END
  END cfg_data[269]
  PIN cfg_data[26]
    DIRECTION INPUT ;
    USE SIGNAL ;
    PORT
      LAYER M4 ;
        RECT  0 11.184 0.084 11.208 ;
    END
  END cfg_data[26]
  PIN cfg_data[270]
    DIRECTION INPUT ;
    USE SIGNAL ;
    PORT
      LAYER M4 ;
        RECT  0 54.576 0.084 54.6 ;
    END
  END cfg_data[270]
  PIN cfg_data[271]
    DIRECTION INPUT ;
    USE SIGNAL ;
    PORT
      LAYER M4 ;
        RECT  0 54.672 0.084 54.696 ;
    END
  END cfg_data[271]
  PIN cfg_data[272]
    DIRECTION INPUT ;
    USE SIGNAL ;
    PORT
      LAYER M4 ;
        RECT  0 54.768 0.084 54.792 ;
    END
  END cfg_data[272]
  PIN cfg_data[273]
    DIRECTION INPUT ;
    USE SIGNAL ;
    PORT
      LAYER M4 ;
        RECT  0 54.864 0.084 54.888 ;
    END
  END cfg_data[273]
  PIN cfg_data[274]
    DIRECTION INPUT ;
    USE SIGNAL ;
    PORT
      LAYER M4 ;
        RECT  0 54.96 0.084 54.984 ;
    END
  END cfg_data[274]
  PIN cfg_data[275]
    DIRECTION INPUT ;
    USE SIGNAL ;
    PORT
      LAYER M4 ;
        RECT  0 87.312 0.084 87.336 ;
    END
  END cfg_data[275]
  PIN cfg_data[276]
    DIRECTION INPUT ;
    USE SIGNAL ;
    PORT
      LAYER M4 ;
        RECT  0 87.408 0.084 87.432 ;
    END
  END cfg_data[276]
  PIN cfg_data[277]
    DIRECTION INPUT ;
    USE SIGNAL ;
    PORT
      LAYER M4 ;
        RECT  0 87.504 0.084 87.528 ;
    END
  END cfg_data[277]
  PIN cfg_data[278]
    DIRECTION INPUT ;
    USE SIGNAL ;
    PORT
      LAYER M4 ;
        RECT  0 87.6 0.084 87.624 ;
    END
  END cfg_data[278]
  PIN cfg_data[279]
    DIRECTION INPUT ;
    USE SIGNAL ;
    PORT
      LAYER M4 ;
        RECT  0 87.696 0.084 87.72 ;
    END
  END cfg_data[279]
  PIN cfg_data[27]
    DIRECTION INPUT ;
    USE SIGNAL ;
    PORT
      LAYER M4 ;
        RECT  0 11.28 0.084 11.304 ;
    END
  END cfg_data[27]
  PIN cfg_data[280]
    DIRECTION INPUT ;
    USE SIGNAL ;
    PORT
      LAYER M4 ;
        RECT  0 87.792 0.084 87.816 ;
    END
  END cfg_data[280]
  PIN cfg_data[281]
    DIRECTION INPUT ;
    USE SIGNAL ;
    PORT
      LAYER M4 ;
        RECT  0 87.888 0.084 87.912 ;
    END
  END cfg_data[281]
  PIN cfg_data[282]
    DIRECTION INPUT ;
    USE SIGNAL ;
    PORT
      LAYER M4 ;
        RECT  0 87.984 0.084 88.008 ;
    END
  END cfg_data[282]
  PIN cfg_data[283]
    DIRECTION INPUT ;
    USE SIGNAL ;
    PORT
      LAYER M4 ;
        RECT  0 88.08 0.084 88.104 ;
    END
  END cfg_data[283]
  PIN cfg_data[284]
    DIRECTION INPUT ;
    USE SIGNAL ;
    PORT
      LAYER M4 ;
        RECT  0 88.176 0.084 88.2 ;
    END
  END cfg_data[284]
  PIN cfg_data[285]
    DIRECTION INPUT ;
    USE SIGNAL ;
    PORT
      LAYER M4 ;
        RECT  0 88.272 0.084 88.296 ;
    END
  END cfg_data[285]
  PIN cfg_data[286]
    DIRECTION INPUT ;
    USE SIGNAL ;
    PORT
      LAYER M4 ;
        RECT  0 88.368 0.084 88.392 ;
    END
  END cfg_data[286]
  PIN cfg_data[287]
    DIRECTION INPUT ;
    USE SIGNAL ;
    PORT
      LAYER M4 ;
        RECT  0 88.464 0.084 88.488 ;
    END
  END cfg_data[287]
  PIN cfg_data[288]
    DIRECTION INPUT ;
    USE SIGNAL ;
    PORT
      LAYER M4 ;
        RECT  0 88.56 0.084 88.584 ;
    END
  END cfg_data[288]
  PIN cfg_data[289]
    DIRECTION INPUT ;
    USE SIGNAL ;
    PORT
      LAYER M4 ;
        RECT  0 88.656 0.084 88.68 ;
    END
  END cfg_data[289]
  PIN cfg_data[28]
    DIRECTION INPUT ;
    USE SIGNAL ;
    PORT
      LAYER M4 ;
        RECT  0 11.376 0.084 11.4 ;
    END
  END cfg_data[28]
  PIN cfg_data[290]
    DIRECTION INPUT ;
    USE SIGNAL ;
    PORT
      LAYER M4 ;
        RECT  0 88.752 0.084 88.776 ;
    END
  END cfg_data[290]
  PIN cfg_data[291]
    DIRECTION INPUT ;
    USE SIGNAL ;
    PORT
      LAYER M4 ;
        RECT  0 88.848 0.084 88.872 ;
    END
  END cfg_data[291]
  PIN cfg_data[292]
    DIRECTION INPUT ;
    USE SIGNAL ;
    PORT
      LAYER M4 ;
        RECT  0 88.944 0.084 88.968 ;
    END
  END cfg_data[292]
  PIN cfg_data[293]
    DIRECTION INPUT ;
    USE SIGNAL ;
    PORT
      LAYER M4 ;
        RECT  0 89.04 0.084 89.064 ;
    END
  END cfg_data[293]
  PIN cfg_data[294]
    DIRECTION INPUT ;
    USE SIGNAL ;
    PORT
      LAYER M4 ;
        RECT  0 89.136 0.084 89.16 ;
    END
  END cfg_data[294]
  PIN cfg_data[295]
    DIRECTION INPUT ;
    USE SIGNAL ;
    PORT
      LAYER M4 ;
        RECT  0 89.232 0.084 89.256 ;
    END
  END cfg_data[295]
  PIN cfg_data[296]
    DIRECTION INPUT ;
    USE SIGNAL ;
    PORT
      LAYER M4 ;
        RECT  0 89.328 0.084 89.352 ;
    END
  END cfg_data[296]
  PIN cfg_data[297]
    DIRECTION INPUT ;
    USE SIGNAL ;
    PORT
      LAYER M4 ;
        RECT  0 89.424 0.084 89.448 ;
    END
  END cfg_data[297]
  PIN cfg_data[298]
    DIRECTION INPUT ;
    USE SIGNAL ;
    PORT
      LAYER M4 ;
        RECT  0 89.52 0.084 89.544 ;
    END
  END cfg_data[298]
  PIN cfg_data[299]
    DIRECTION INPUT ;
    USE SIGNAL ;
    PORT
      LAYER M4 ;
        RECT  0 89.616 0.084 89.64 ;
    END
  END cfg_data[299]
  PIN cfg_data[29]
    DIRECTION INPUT ;
    USE SIGNAL ;
    PORT
      LAYER M4 ;
        RECT  0 11.472 0.084 11.496 ;
    END
  END cfg_data[29]
  PIN cfg_data[2]
    DIRECTION INPUT ;
    USE SIGNAL ;
    PORT
      LAYER M4 ;
        RECT  0 34.224 0.084 34.248 ;
    END
  END cfg_data[2]
  PIN cfg_data[300]
    DIRECTION INPUT ;
    USE SIGNAL ;
    PORT
      LAYER M4 ;
        RECT  0 89.712 0.084 89.736 ;
    END
  END cfg_data[300]
  PIN cfg_data[301]
    DIRECTION INPUT ;
    USE SIGNAL ;
    PORT
      LAYER M4 ;
        RECT  0 89.808 0.084 89.832 ;
    END
  END cfg_data[301]
  PIN cfg_data[302]
    DIRECTION INPUT ;
    USE SIGNAL ;
    PORT
      LAYER M4 ;
        RECT  0 89.904 0.084 89.928 ;
    END
  END cfg_data[302]
  PIN cfg_data[303]
    DIRECTION INPUT ;
    USE SIGNAL ;
    PORT
      LAYER M4 ;
        RECT  0 90 0.084 90.024 ;
    END
  END cfg_data[303]
  PIN cfg_data[304]
    DIRECTION INPUT ;
    USE SIGNAL ;
    PORT
      LAYER M4 ;
        RECT  0 90.096 0.084 90.12 ;
    END
  END cfg_data[304]
  PIN cfg_data[305]
    DIRECTION INPUT ;
    USE SIGNAL ;
    PORT
      LAYER M4 ;
        RECT  0 90.192 0.084 90.216 ;
    END
  END cfg_data[305]
  PIN cfg_data[306]
    DIRECTION INPUT ;
    USE SIGNAL ;
    PORT
      LAYER M4 ;
        RECT  0 90.288 0.084 90.312 ;
    END
  END cfg_data[306]
  PIN cfg_data[307]
    DIRECTION INPUT ;
    USE SIGNAL ;
    PORT
      LAYER M4 ;
        RECT  0 75.12 0.084 75.144 ;
    END
  END cfg_data[307]
  PIN cfg_data[308]
    DIRECTION INPUT ;
    USE SIGNAL ;
    PORT
      LAYER M4 ;
        RECT  0 75.216 0.084 75.24 ;
    END
  END cfg_data[308]
  PIN cfg_data[309]
    DIRECTION INPUT ;
    USE SIGNAL ;
    PORT
      LAYER M4 ;
        RECT  0 75.312 0.084 75.336 ;
    END
  END cfg_data[309]
  PIN cfg_data[30]
    DIRECTION INPUT ;
    USE SIGNAL ;
    PORT
      LAYER M4 ;
        RECT  0 11.568 0.084 11.592 ;
    END
  END cfg_data[30]
  PIN cfg_data[310]
    DIRECTION INPUT ;
    USE SIGNAL ;
    PORT
      LAYER M4 ;
        RECT  0 75.408 0.084 75.432 ;
    END
  END cfg_data[310]
  PIN cfg_data[311]
    DIRECTION INPUT ;
    USE SIGNAL ;
    PORT
      LAYER M4 ;
        RECT  0 75.504 0.084 75.528 ;
    END
  END cfg_data[311]
  PIN cfg_data[312]
    DIRECTION INPUT ;
    USE SIGNAL ;
    PORT
      LAYER M4 ;
        RECT  0 75.6 0.084 75.624 ;
    END
  END cfg_data[312]
  PIN cfg_data[313]
    DIRECTION INPUT ;
    USE SIGNAL ;
    PORT
      LAYER M4 ;
        RECT  0 75.696 0.084 75.72 ;
    END
  END cfg_data[313]
  PIN cfg_data[314]
    DIRECTION INPUT ;
    USE SIGNAL ;
    PORT
      LAYER M4 ;
        RECT  0 75.792 0.084 75.816 ;
    END
  END cfg_data[314]
  PIN cfg_data[315]
    DIRECTION INPUT ;
    USE SIGNAL ;
    PORT
      LAYER M4 ;
        RECT  0 75.888 0.084 75.912 ;
    END
  END cfg_data[315]
  PIN cfg_data[316]
    DIRECTION INPUT ;
    USE SIGNAL ;
    PORT
      LAYER M4 ;
        RECT  0 75.984 0.084 76.008 ;
    END
  END cfg_data[316]
  PIN cfg_data[317]
    DIRECTION INPUT ;
    USE SIGNAL ;
    PORT
      LAYER M4 ;
        RECT  0 76.08 0.084 76.104 ;
    END
  END cfg_data[317]
  PIN cfg_data[318]
    DIRECTION INPUT ;
    USE SIGNAL ;
    PORT
      LAYER M4 ;
        RECT  0 76.176 0.084 76.2 ;
    END
  END cfg_data[318]
  PIN cfg_data[319]
    DIRECTION INPUT ;
    USE SIGNAL ;
    PORT
      LAYER M4 ;
        RECT  0 76.272 0.084 76.296 ;
    END
  END cfg_data[319]
  PIN cfg_data[31]
    DIRECTION INPUT ;
    USE SIGNAL ;
    PORT
      LAYER M4 ;
        RECT  0 11.664 0.084 11.688 ;
    END
  END cfg_data[31]
  PIN cfg_data[32]
    DIRECTION INPUT ;
    USE SIGNAL ;
    PORT
      LAYER M4 ;
        RECT  0 11.76 0.084 11.784 ;
    END
  END cfg_data[32]
  PIN cfg_data[33]
    DIRECTION INPUT ;
    USE SIGNAL ;
    PORT
      LAYER M4 ;
        RECT  0 11.856 0.084 11.88 ;
    END
  END cfg_data[33]
  PIN cfg_data[34]
    DIRECTION INPUT ;
    USE SIGNAL ;
    PORT
      LAYER M4 ;
        RECT  0 11.952 0.084 11.976 ;
    END
  END cfg_data[34]
  PIN cfg_data[35]
    DIRECTION INPUT ;
    USE SIGNAL ;
    PORT
      LAYER M4 ;
        RECT  0 12.048 0.084 12.072 ;
    END
  END cfg_data[35]
  PIN cfg_data[36]
    DIRECTION INPUT ;
    USE SIGNAL ;
    PORT
      LAYER M4 ;
        RECT  0 12.144 0.084 12.168 ;
    END
  END cfg_data[36]
  PIN cfg_data[37]
    DIRECTION INPUT ;
    USE SIGNAL ;
    PORT
      LAYER M4 ;
        RECT  0 12.24 0.084 12.264 ;
    END
  END cfg_data[37]
  PIN cfg_data[38]
    DIRECTION INPUT ;
    USE SIGNAL ;
    PORT
      LAYER M4 ;
        RECT  0 12.336 0.084 12.36 ;
    END
  END cfg_data[38]
  PIN cfg_data[39]
    DIRECTION INPUT ;
    USE SIGNAL ;
    PORT
      LAYER M4 ;
        RECT  0 12.432 0.084 12.456 ;
    END
  END cfg_data[39]
  PIN cfg_data[3]
    DIRECTION INPUT ;
    USE SIGNAL ;
    PORT
      LAYER M4 ;
        RECT  0 34.32 0.084 34.344 ;
    END
  END cfg_data[3]
  PIN cfg_data[40]
    DIRECTION INPUT ;
    USE SIGNAL ;
    PORT
      LAYER M4 ;
        RECT  0 12.528 0.084 12.552 ;
    END
  END cfg_data[40]
  PIN cfg_data[41]
    DIRECTION INPUT ;
    USE SIGNAL ;
    PORT
      LAYER M4 ;
        RECT  0 12.624 0.084 12.648 ;
    END
  END cfg_data[41]
  PIN cfg_data[42]
    DIRECTION INPUT ;
    USE SIGNAL ;
    PORT
      LAYER M4 ;
        RECT  0 12.72 0.084 12.744 ;
    END
  END cfg_data[42]
  PIN cfg_data[43]
    DIRECTION INPUT ;
    USE SIGNAL ;
    PORT
      LAYER M4 ;
        RECT  0 12.816 0.084 12.84 ;
    END
  END cfg_data[43]
  PIN cfg_data[44]
    DIRECTION INPUT ;
    USE SIGNAL ;
    PORT
      LAYER M4 ;
        RECT  0 12.912 0.084 12.936 ;
    END
  END cfg_data[44]
  PIN cfg_data[45]
    DIRECTION INPUT ;
    USE SIGNAL ;
    PORT
      LAYER M4 ;
        RECT  0 13.008 0.084 13.032 ;
    END
  END cfg_data[45]
  PIN cfg_data[46]
    DIRECTION INPUT ;
    USE SIGNAL ;
    PORT
      LAYER M4 ;
        RECT  0 13.104 0.084 13.128 ;
    END
  END cfg_data[46]
  PIN cfg_data[47]
    DIRECTION INPUT ;
    USE SIGNAL ;
    PORT
      LAYER M4 ;
        RECT  0 13.2 0.084 13.224 ;
    END
  END cfg_data[47]
  PIN cfg_data[48]
    DIRECTION INPUT ;
    USE SIGNAL ;
    PORT
      LAYER M4 ;
        RECT  0 13.296 0.084 13.32 ;
    END
  END cfg_data[48]
  PIN cfg_data[49]
    DIRECTION INPUT ;
    USE SIGNAL ;
    PORT
      LAYER M4 ;
        RECT  0 13.392 0.084 13.416 ;
    END
  END cfg_data[49]
  PIN cfg_data[4]
    DIRECTION INPUT ;
    USE SIGNAL ;
    PORT
      LAYER M4 ;
        RECT  0 34.416 0.084 34.44 ;
    END
  END cfg_data[4]
  PIN cfg_data[50]
    DIRECTION INPUT ;
    USE SIGNAL ;
    PORT
      LAYER M4 ;
        RECT  0 13.488 0.084 13.512 ;
    END
  END cfg_data[50]
  PIN cfg_data[51]
    DIRECTION INPUT ;
    USE SIGNAL ;
    PORT
      LAYER M4 ;
        RECT  0 55.056 0.084 55.08 ;
    END
  END cfg_data[51]
  PIN cfg_data[52]
    DIRECTION INPUT ;
    USE SIGNAL ;
    PORT
      LAYER M4 ;
        RECT  0 55.152 0.084 55.176 ;
    END
  END cfg_data[52]
  PIN cfg_data[53]
    DIRECTION INPUT ;
    USE SIGNAL ;
    PORT
      LAYER M4 ;
        RECT  0 55.248 0.084 55.272 ;
    END
  END cfg_data[53]
  PIN cfg_data[54]
    DIRECTION INPUT ;
    USE SIGNAL ;
    PORT
      LAYER M4 ;
        RECT  0 55.344 0.084 55.368 ;
    END
  END cfg_data[54]
  PIN cfg_data[55]
    DIRECTION INPUT ;
    USE SIGNAL ;
    PORT
      LAYER M4 ;
        RECT  0 55.44 0.084 55.464 ;
    END
  END cfg_data[55]
  PIN cfg_data[56]
    DIRECTION INPUT ;
    USE SIGNAL ;
    PORT
      LAYER M4 ;
        RECT  0 55.536 0.084 55.56 ;
    END
  END cfg_data[56]
  PIN cfg_data[57]
    DIRECTION INPUT ;
    USE SIGNAL ;
    PORT
      LAYER M4 ;
        RECT  0 55.632 0.084 55.656 ;
    END
  END cfg_data[57]
  PIN cfg_data[58]
    DIRECTION INPUT ;
    USE SIGNAL ;
    PORT
      LAYER M4 ;
        RECT  0 55.728 0.084 55.752 ;
    END
  END cfg_data[58]
  PIN cfg_data[59]
    DIRECTION INPUT ;
    USE SIGNAL ;
    PORT
      LAYER M4 ;
        RECT  0 55.824 0.084 55.848 ;
    END
  END cfg_data[59]
  PIN cfg_data[5]
    DIRECTION INPUT ;
    USE SIGNAL ;
    PORT
      LAYER M4 ;
        RECT  0 34.512 0.084 34.536 ;
    END
  END cfg_data[5]
  PIN cfg_data[60]
    DIRECTION INPUT ;
    USE SIGNAL ;
    PORT
      LAYER M4 ;
        RECT  0 55.92 0.084 55.944 ;
    END
  END cfg_data[60]
  PIN cfg_data[61]
    DIRECTION INPUT ;
    USE SIGNAL ;
    PORT
      LAYER M4 ;
        RECT  0 56.016 0.084 56.04 ;
    END
  END cfg_data[61]
  PIN cfg_data[62]
    DIRECTION INPUT ;
    USE SIGNAL ;
    PORT
      LAYER M4 ;
        RECT  0 56.112 0.084 56.136 ;
    END
  END cfg_data[62]
  PIN cfg_data[63]
    DIRECTION INPUT ;
    USE SIGNAL ;
    PORT
      LAYER M4 ;
        RECT  0 56.208 0.084 56.232 ;
    END
  END cfg_data[63]
  PIN cfg_data[64]
    DIRECTION INPUT ;
    USE SIGNAL ;
    PORT
      LAYER M4 ;
        RECT  0 56.304 0.084 56.328 ;
    END
  END cfg_data[64]
  PIN cfg_data[65]
    DIRECTION INPUT ;
    USE SIGNAL ;
    PORT
      LAYER M4 ;
        RECT  0 56.4 0.084 56.424 ;
    END
  END cfg_data[65]
  PIN cfg_data[66]
    DIRECTION INPUT ;
    USE SIGNAL ;
    PORT
      LAYER M4 ;
        RECT  0 56.496 0.084 56.52 ;
    END
  END cfg_data[66]
  PIN cfg_data[67]
    DIRECTION INPUT ;
    USE SIGNAL ;
    PORT
      LAYER M4 ;
        RECT  0 56.592 0.084 56.616 ;
    END
  END cfg_data[67]
  PIN cfg_data[68]
    DIRECTION INPUT ;
    USE SIGNAL ;
    PORT
      LAYER M4 ;
        RECT  0 56.688 0.084 56.712 ;
    END
  END cfg_data[68]
  PIN cfg_data[69]
    DIRECTION INPUT ;
    USE SIGNAL ;
    PORT
      LAYER M4 ;
        RECT  0 56.784 0.084 56.808 ;
    END
  END cfg_data[69]
  PIN cfg_data[6]
    DIRECTION INPUT ;
    USE SIGNAL ;
    PORT
      LAYER M4 ;
        RECT  0 34.608 0.084 34.632 ;
    END
  END cfg_data[6]
  PIN cfg_data[70]
    DIRECTION INPUT ;
    USE SIGNAL ;
    PORT
      LAYER M4 ;
        RECT  0 56.88 0.084 56.904 ;
    END
  END cfg_data[70]
  PIN cfg_data[71]
    DIRECTION INPUT ;
    USE SIGNAL ;
    PORT
      LAYER M4 ;
        RECT  0 56.976 0.084 57 ;
    END
  END cfg_data[71]
  PIN cfg_data[72]
    DIRECTION INPUT ;
    USE SIGNAL ;
    PORT
      LAYER M4 ;
        RECT  0 57.072 0.084 57.096 ;
    END
  END cfg_data[72]
  PIN cfg_data[73]
    DIRECTION INPUT ;
    USE SIGNAL ;
    PORT
      LAYER M4 ;
        RECT  0 57.168 0.084 57.192 ;
    END
  END cfg_data[73]
  PIN cfg_data[74]
    DIRECTION INPUT ;
    USE SIGNAL ;
    PORT
      LAYER M4 ;
        RECT  0 57.264 0.084 57.288 ;
    END
  END cfg_data[74]
  PIN cfg_data[75]
    DIRECTION INPUT ;
    USE SIGNAL ;
    PORT
      LAYER M4 ;
        RECT  0 57.36 0.084 57.384 ;
    END
  END cfg_data[75]
  PIN cfg_data[76]
    DIRECTION INPUT ;
    USE SIGNAL ;
    PORT
      LAYER M4 ;
        RECT  0 57.456 0.084 57.48 ;
    END
  END cfg_data[76]
  PIN cfg_data[77]
    DIRECTION INPUT ;
    USE SIGNAL ;
    PORT
      LAYER M4 ;
        RECT  0 57.552 0.084 57.576 ;
    END
  END cfg_data[77]
  PIN cfg_data[78]
    DIRECTION INPUT ;
    USE SIGNAL ;
    PORT
      LAYER M4 ;
        RECT  0 57.648 0.084 57.672 ;
    END
  END cfg_data[78]
  PIN cfg_data[79]
    DIRECTION INPUT ;
    USE SIGNAL ;
    PORT
      LAYER M4 ;
        RECT  0 57.744 0.084 57.768 ;
    END
  END cfg_data[79]
  PIN cfg_data[7]
    DIRECTION INPUT ;
    USE SIGNAL ;
    PORT
      LAYER M4 ;
        RECT  0 34.704 0.084 34.728 ;
    END
  END cfg_data[7]
  PIN cfg_data[80]
    DIRECTION INPUT ;
    USE SIGNAL ;
    PORT
      LAYER M4 ;
        RECT  0 57.84 0.084 57.864 ;
    END
  END cfg_data[80]
  PIN cfg_data[81]
    DIRECTION INPUT ;
    USE SIGNAL ;
    PORT
      LAYER M4 ;
        RECT  0 57.936 0.084 57.96 ;
    END
  END cfg_data[81]
  PIN cfg_data[82]
    DIRECTION INPUT ;
    USE SIGNAL ;
    PORT
      LAYER M4 ;
        RECT  0 58.032 0.084 58.056 ;
    END
  END cfg_data[82]
  PIN cfg_data[83]
    DIRECTION INPUT ;
    USE SIGNAL ;
    PORT
      LAYER M4 ;
        RECT  0 78.096 0.084 78.12 ;
    END
  END cfg_data[83]
  PIN cfg_data[84]
    DIRECTION INPUT ;
    USE SIGNAL ;
    PORT
      LAYER M4 ;
        RECT  0 78.192 0.084 78.216 ;
    END
  END cfg_data[84]
  PIN cfg_data[85]
    DIRECTION INPUT ;
    USE SIGNAL ;
    PORT
      LAYER M4 ;
        RECT  0 78.288 0.084 78.312 ;
    END
  END cfg_data[85]
  PIN cfg_data[86]
    DIRECTION INPUT ;
    USE SIGNAL ;
    PORT
      LAYER M4 ;
        RECT  0 78.384 0.084 78.408 ;
    END
  END cfg_data[86]
  PIN cfg_data[87]
    DIRECTION INPUT ;
    USE SIGNAL ;
    PORT
      LAYER M4 ;
        RECT  0 78.48 0.084 78.504 ;
    END
  END cfg_data[87]
  PIN cfg_data[88]
    DIRECTION INPUT ;
    USE SIGNAL ;
    PORT
      LAYER M4 ;
        RECT  0 78.576 0.084 78.6 ;
    END
  END cfg_data[88]
  PIN cfg_data[89]
    DIRECTION INPUT ;
    USE SIGNAL ;
    PORT
      LAYER M4 ;
        RECT  0 78.672 0.084 78.696 ;
    END
  END cfg_data[89]
  PIN cfg_data[8]
    DIRECTION INPUT ;
    USE SIGNAL ;
    PORT
      LAYER M4 ;
        RECT  0 34.8 0.084 34.824 ;
    END
  END cfg_data[8]
  PIN cfg_data[90]
    DIRECTION INPUT ;
    USE SIGNAL ;
    PORT
      LAYER M4 ;
        RECT  0 78.768 0.084 78.792 ;
    END
  END cfg_data[90]
  PIN cfg_data[91]
    DIRECTION INPUT ;
    USE SIGNAL ;
    PORT
      LAYER M4 ;
        RECT  0 78.864 0.084 78.888 ;
    END
  END cfg_data[91]
  PIN cfg_data[92]
    DIRECTION INPUT ;
    USE SIGNAL ;
    PORT
      LAYER M4 ;
        RECT  0 78.96 0.084 78.984 ;
    END
  END cfg_data[92]
  PIN cfg_data[93]
    DIRECTION INPUT ;
    USE SIGNAL ;
    PORT
      LAYER M4 ;
        RECT  0 79.056 0.084 79.08 ;
    END
  END cfg_data[93]
  PIN cfg_data[94]
    DIRECTION INPUT ;
    USE SIGNAL ;
    PORT
      LAYER M4 ;
        RECT  0 79.152 0.084 79.176 ;
    END
  END cfg_data[94]
  PIN cfg_data[95]
    DIRECTION INPUT ;
    USE SIGNAL ;
    PORT
      LAYER M4 ;
        RECT  0 79.248 0.084 79.272 ;
    END
  END cfg_data[95]
  PIN cfg_data[96]
    DIRECTION INPUT ;
    USE SIGNAL ;
    PORT
      LAYER M4 ;
        RECT  0 79.344 0.084 79.368 ;
    END
  END cfg_data[96]
  PIN cfg_data[97]
    DIRECTION INPUT ;
    USE SIGNAL ;
    PORT
      LAYER M4 ;
        RECT  0 79.44 0.084 79.464 ;
    END
  END cfg_data[97]
  PIN cfg_data[98]
    DIRECTION INPUT ;
    USE SIGNAL ;
    PORT
      LAYER M4 ;
        RECT  0 79.536 0.084 79.56 ;
    END
  END cfg_data[98]
  PIN cfg_data[99]
    DIRECTION INPUT ;
    USE SIGNAL ;
    PORT
      LAYER M4 ;
        RECT  0 79.632 0.084 79.656 ;
    END
  END cfg_data[99]
  PIN cfg_data[9]
    DIRECTION INPUT ;
    USE SIGNAL ;
    PORT
      LAYER M4 ;
        RECT  0 34.896 0.084 34.92 ;
    END
  END cfg_data[9]
  PIN cfg_last[0]
    DIRECTION INPUT ;
    USE SIGNAL ;
    PORT
      LAYER M4 ;
        RECT  0 76.368 0.084 76.392 ;
    END
  END cfg_last[0]
  PIN cfg_last[1]
    DIRECTION INPUT ;
    USE SIGNAL ;
    PORT
      LAYER M4 ;
        RECT  0 76.464 0.084 76.488 ;
    END
  END cfg_last[1]
  PIN cfg_last[2]
    DIRECTION INPUT ;
    USE SIGNAL ;
    PORT
      LAYER M4 ;
        RECT  0 76.56 0.084 76.584 ;
    END
  END cfg_last[2]
  PIN cfg_last[3]
    DIRECTION INPUT ;
    USE SIGNAL ;
    PORT
      LAYER M4 ;
        RECT  0 76.656 0.084 76.68 ;
    END
  END cfg_last[3]
  PIN cfg_last[4]
    DIRECTION INPUT ;
    USE SIGNAL ;
    PORT
      LAYER M4 ;
        RECT  0 76.752 0.084 76.776 ;
    END
  END cfg_last[4]
  PIN cfg_we[0]
    DIRECTION INPUT ;
    USE SIGNAL ;
    PORT
      LAYER M4 ;
        RECT  0 76.848 0.084 76.872 ;
    END
  END cfg_we[0]
  PIN cfg_we[1]
    DIRECTION INPUT ;
    USE SIGNAL ;
    PORT
      LAYER M4 ;
        RECT  0 76.944 0.084 76.968 ;
    END
  END cfg_we[1]
  PIN cfg_we[2]
    DIRECTION INPUT ;
    USE SIGNAL ;
    PORT
      LAYER M4 ;
        RECT  0 77.04 0.084 77.064 ;
    END
  END cfg_we[2]
  PIN cfg_we[3]
    DIRECTION INPUT ;
    USE SIGNAL ;
    PORT
      LAYER M4 ;
        RECT  0 77.136 0.084 77.16 ;
    END
  END cfg_we[3]
  PIN cfg_we[4]
    DIRECTION INPUT ;
    USE SIGNAL ;
    PORT
      LAYER M4 ;
        RECT  0 77.232 0.084 77.256 ;
    END
  END cfg_we[4]
  PIN ck
    DIRECTION INPUT ;
    USE SIGNAL ;
    PORT
      LAYER M4 ;
        RECT  0 49.008 0.084 49.032 ;
    END
  END ck
  PIN ctrl_calendar_fault_hbm[0]
    DIRECTION INPUT ;
    USE SIGNAL ;
    PORT
      LAYER M5 ;
        RECT  83.664 0 83.688 0.084 ;
    END
  END ctrl_calendar_fault_hbm[0]
  PIN ctrl_calendar_fault_hbm[1]
    DIRECTION INPUT ;
    USE SIGNAL ;
    PORT
      LAYER M5 ;
        RECT  83.76 0 83.784 0.084 ;
    END
  END ctrl_calendar_fault_hbm[1]
  PIN ctrl_calendar_fault_hbm[2]
    DIRECTION INPUT ;
    USE SIGNAL ;
    PORT
      LAYER M5 ;
        RECT  83.856 0 83.88 0.084 ;
    END
  END ctrl_calendar_fault_hbm[2]
  PIN ctrl_calendar_fault_hbm[3]
    DIRECTION INPUT ;
    USE SIGNAL ;
    PORT
      LAYER M5 ;
        RECT  83.952 0 83.976 0.084 ;
    END
  END ctrl_calendar_fault_hbm[3]
  PIN ctrl_completion_fault_core[0]
    DIRECTION INPUT ;
    USE SIGNAL ;
    PORT
      LAYER M5 ;
        RECT  84.048 0 84.072 0.084 ;
    END
  END ctrl_completion_fault_core[0]
  PIN ctrl_completion_fault_core[1]
    DIRECTION INPUT ;
    USE SIGNAL ;
    PORT
      LAYER M5 ;
        RECT  84.144 0 84.168 0.084 ;
    END
  END ctrl_completion_fault_core[1]
  PIN ctrl_completion_fault_core[2]
    DIRECTION INPUT ;
    USE SIGNAL ;
    PORT
      LAYER M5 ;
        RECT  84.24 0 84.264 0.084 ;
    END
  END ctrl_completion_fault_core[2]
  PIN ctrl_completion_fault_core[3]
    DIRECTION INPUT ;
    USE SIGNAL ;
    PORT
      LAYER M5 ;
        RECT  84.336 0 84.36 0.084 ;
    END
  END ctrl_completion_fault_core[3]
  PIN ctrl_fault_core[0]
    DIRECTION INPUT ;
    USE SIGNAL ;
    PORT
      LAYER M5 ;
        RECT  84.432 0 84.456 0.084 ;
    END
  END ctrl_fault_core[0]
  PIN ctrl_fault_core[1]
    DIRECTION INPUT ;
    USE SIGNAL ;
    PORT
      LAYER M5 ;
        RECT  84.528 0 84.552 0.084 ;
    END
  END ctrl_fault_core[1]
  PIN ctrl_fault_core[2]
    DIRECTION INPUT ;
    USE SIGNAL ;
    PORT
      LAYER M5 ;
        RECT  84.624 0 84.648 0.084 ;
    END
  END ctrl_fault_core[2]
  PIN ctrl_fault_core[3]
    DIRECTION INPUT ;
    USE SIGNAL ;
    PORT
      LAYER M5 ;
        RECT  84.72 0 84.744 0.084 ;
    END
  END ctrl_fault_core[3]
  PIN ctrl_fault_hbm[0]
    DIRECTION INPUT ;
    USE SIGNAL ;
    PORT
      LAYER M5 ;
        RECT  84.816 0 84.84 0.084 ;
    END
  END ctrl_fault_hbm[0]
  PIN ctrl_fault_hbm[1]
    DIRECTION INPUT ;
    USE SIGNAL ;
    PORT
      LAYER M5 ;
        RECT  84.912 0 84.936 0.084 ;
    END
  END ctrl_fault_hbm[1]
  PIN ctrl_fault_hbm[2]
    DIRECTION INPUT ;
    USE SIGNAL ;
    PORT
      LAYER M5 ;
        RECT  85.008 0 85.032 0.084 ;
    END
  END ctrl_fault_hbm[2]
  PIN ctrl_fault_hbm[3]
    DIRECTION INPUT ;
    USE SIGNAL ;
    PORT
      LAYER M5 ;
        RECT  85.104 0 85.128 0.084 ;
    END
  END ctrl_fault_hbm[3]
  PIN ctrl_go
    DIRECTION INPUT ;
    USE SIGNAL ;
    PORT
      LAYER M5 ;
        RECT  51.984 97.116 52.008 97.2 ;
    END
  END ctrl_go
  PIN ctrl_go_h
    DIRECTION OUTPUT ;
    USE SIGNAL ;
    PORT
      LAYER M5 ;
        RECT  52.08 97.116 52.104 97.2 ;
    END
  END ctrl_go_h
  PIN ctrl_idle_core[0]
    DIRECTION INPUT ;
    USE SIGNAL ;
    PORT
      LAYER M5 ;
        RECT  85.2 0 85.224 0.084 ;
    END
  END ctrl_idle_core[0]
  PIN ctrl_idle_core[1]
    DIRECTION INPUT ;
    USE SIGNAL ;
    PORT
      LAYER M5 ;
        RECT  85.296 0 85.32 0.084 ;
    END
  END ctrl_idle_core[1]
  PIN ctrl_idle_core[2]
    DIRECTION INPUT ;
    USE SIGNAL ;
    PORT
      LAYER M5 ;
        RECT  85.392 0 85.416 0.084 ;
    END
  END ctrl_idle_core[2]
  PIN ctrl_idle_core[3]
    DIRECTION INPUT ;
    USE SIGNAL ;
    PORT
      LAYER M5 ;
        RECT  85.488 0 85.512 0.084 ;
    END
  END ctrl_idle_core[3]
  PIN ctrl_idle_hbm[0]
    DIRECTION INPUT ;
    USE SIGNAL ;
    PORT
      LAYER M5 ;
        RECT  85.584 0 85.608 0.084 ;
    END
  END ctrl_idle_hbm[0]
  PIN ctrl_idle_hbm[1]
    DIRECTION INPUT ;
    USE SIGNAL ;
    PORT
      LAYER M5 ;
        RECT  85.68 0 85.704 0.084 ;
    END
  END ctrl_idle_hbm[1]
  PIN ctrl_idle_hbm[2]
    DIRECTION INPUT ;
    USE SIGNAL ;
    PORT
      LAYER M5 ;
        RECT  85.776 0 85.8 0.084 ;
    END
  END ctrl_idle_hbm[2]
  PIN ctrl_idle_hbm[3]
    DIRECTION INPUT ;
    USE SIGNAL ;
    PORT
      LAYER M5 ;
        RECT  85.872 0 85.896 0.084 ;
    END
  END ctrl_idle_hbm[3]
  PIN ctrl_intake_fault_core[0]
    DIRECTION INPUT ;
    USE SIGNAL ;
    PORT
      LAYER M5 ;
        RECT  85.968 0 85.992 0.084 ;
    END
  END ctrl_intake_fault_core[0]
  PIN ctrl_intake_fault_core[1]
    DIRECTION INPUT ;
    USE SIGNAL ;
    PORT
      LAYER M5 ;
        RECT  86.064 0 86.088 0.084 ;
    END
  END ctrl_intake_fault_core[1]
  PIN ctrl_intake_fault_core[2]
    DIRECTION INPUT ;
    USE SIGNAL ;
    PORT
      LAYER M5 ;
        RECT  86.16 0 86.184 0.084 ;
    END
  END ctrl_intake_fault_core[2]
  PIN ctrl_intake_fault_core[3]
    DIRECTION INPUT ;
    USE SIGNAL ;
    PORT
      LAYER M5 ;
        RECT  86.256 0 86.28 0.084 ;
    END
  END ctrl_intake_fault_core[3]
  PIN ctrl_output_fault_hbm[0]
    DIRECTION INPUT ;
    USE SIGNAL ;
    PORT
      LAYER M5 ;
        RECT  86.352 0 86.376 0.084 ;
    END
  END ctrl_output_fault_hbm[0]
  PIN ctrl_output_fault_hbm[1]
    DIRECTION INPUT ;
    USE SIGNAL ;
    PORT
      LAYER M5 ;
        RECT  86.448 0 86.472 0.084 ;
    END
  END ctrl_output_fault_hbm[1]
  PIN ctrl_output_fault_hbm[2]
    DIRECTION INPUT ;
    USE SIGNAL ;
    PORT
      LAYER M5 ;
        RECT  86.544 0 86.568 0.084 ;
    END
  END ctrl_output_fault_hbm[2]
  PIN ctrl_output_fault_hbm[3]
    DIRECTION INPUT ;
    USE SIGNAL ;
    PORT
      LAYER M5 ;
        RECT  86.64 0 86.664 0.084 ;
    END
  END ctrl_output_fault_hbm[3]
  PIN ctx_t[0]
    DIRECTION INPUT ;
    USE SIGNAL ;
    PORT
      LAYER M5 ;
        RECT  52.176 97.116 52.2 97.2 ;
    END
  END ctx_t[0]
  PIN ctx_t[10]
    DIRECTION INPUT ;
    USE SIGNAL ;
    PORT
      LAYER M5 ;
        RECT  53.136 97.116 53.16 97.2 ;
    END
  END ctx_t[10]
  PIN ctx_t[11]
    DIRECTION INPUT ;
    USE SIGNAL ;
    PORT
      LAYER M5 ;
        RECT  53.232 97.116 53.256 97.2 ;
    END
  END ctx_t[11]
  PIN ctx_t[12]
    DIRECTION INPUT ;
    USE SIGNAL ;
    PORT
      LAYER M5 ;
        RECT  53.328 97.116 53.352 97.2 ;
    END
  END ctx_t[12]
  PIN ctx_t[13]
    DIRECTION INPUT ;
    USE SIGNAL ;
    PORT
      LAYER M5 ;
        RECT  53.424 97.116 53.448 97.2 ;
    END
  END ctx_t[13]
  PIN ctx_t[1]
    DIRECTION INPUT ;
    USE SIGNAL ;
    PORT
      LAYER M5 ;
        RECT  52.272 97.116 52.296 97.2 ;
    END
  END ctx_t[1]
  PIN ctx_t[2]
    DIRECTION INPUT ;
    USE SIGNAL ;
    PORT
      LAYER M5 ;
        RECT  52.368 97.116 52.392 97.2 ;
    END
  END ctx_t[2]
  PIN ctx_t[3]
    DIRECTION INPUT ;
    USE SIGNAL ;
    PORT
      LAYER M5 ;
        RECT  52.464 97.116 52.488 97.2 ;
    END
  END ctx_t[3]
  PIN ctx_t[4]
    DIRECTION INPUT ;
    USE SIGNAL ;
    PORT
      LAYER M5 ;
        RECT  52.56 97.116 52.584 97.2 ;
    END
  END ctx_t[4]
  PIN ctx_t[5]
    DIRECTION INPUT ;
    USE SIGNAL ;
    PORT
      LAYER M5 ;
        RECT  52.656 97.116 52.68 97.2 ;
    END
  END ctx_t[5]
  PIN ctx_t[6]
    DIRECTION INPUT ;
    USE SIGNAL ;
    PORT
      LAYER M5 ;
        RECT  52.752 97.116 52.776 97.2 ;
    END
  END ctx_t[6]
  PIN ctx_t[7]
    DIRECTION INPUT ;
    USE SIGNAL ;
    PORT
      LAYER M5 ;
        RECT  52.848 97.116 52.872 97.2 ;
    END
  END ctx_t[7]
  PIN ctx_t[8]
    DIRECTION INPUT ;
    USE SIGNAL ;
    PORT
      LAYER M5 ;
        RECT  52.944 97.116 52.968 97.2 ;
    END
  END ctx_t[8]
  PIN ctx_t[9]
    DIRECTION INPUT ;
    USE SIGNAL ;
    PORT
      LAYER M5 ;
        RECT  53.04 97.116 53.064 97.2 ;
    END
  END ctx_t[9]
  PIN ctx_t_h[0]
    DIRECTION OUTPUT ;
    USE SIGNAL ;
    PORT
      LAYER M5 ;
        RECT  53.52 97.116 53.544 97.2 ;
    END
  END ctx_t_h[0]
  PIN ctx_t_h[10]
    DIRECTION OUTPUT ;
    USE SIGNAL ;
    PORT
      LAYER M5 ;
        RECT  54.48 97.116 54.504 97.2 ;
    END
  END ctx_t_h[10]
  PIN ctx_t_h[11]
    DIRECTION OUTPUT ;
    USE SIGNAL ;
    PORT
      LAYER M5 ;
        RECT  54.576 97.116 54.6 97.2 ;
    END
  END ctx_t_h[11]
  PIN ctx_t_h[12]
    DIRECTION OUTPUT ;
    USE SIGNAL ;
    PORT
      LAYER M5 ;
        RECT  54.672 97.116 54.696 97.2 ;
    END
  END ctx_t_h[12]
  PIN ctx_t_h[13]
    DIRECTION OUTPUT ;
    USE SIGNAL ;
    PORT
      LAYER M5 ;
        RECT  54.768 97.116 54.792 97.2 ;
    END
  END ctx_t_h[13]
  PIN ctx_t_h[1]
    DIRECTION OUTPUT ;
    USE SIGNAL ;
    PORT
      LAYER M5 ;
        RECT  53.616 97.116 53.64 97.2 ;
    END
  END ctx_t_h[1]
  PIN ctx_t_h[2]
    DIRECTION OUTPUT ;
    USE SIGNAL ;
    PORT
      LAYER M5 ;
        RECT  53.712 97.116 53.736 97.2 ;
    END
  END ctx_t_h[2]
  PIN ctx_t_h[3]
    DIRECTION OUTPUT ;
    USE SIGNAL ;
    PORT
      LAYER M5 ;
        RECT  53.808 97.116 53.832 97.2 ;
    END
  END ctx_t_h[3]
  PIN ctx_t_h[4]
    DIRECTION OUTPUT ;
    USE SIGNAL ;
    PORT
      LAYER M5 ;
        RECT  53.904 97.116 53.928 97.2 ;
    END
  END ctx_t_h[4]
  PIN ctx_t_h[5]
    DIRECTION OUTPUT ;
    USE SIGNAL ;
    PORT
      LAYER M5 ;
        RECT  54 97.116 54.024 97.2 ;
    END
  END ctx_t_h[5]
  PIN ctx_t_h[6]
    DIRECTION OUTPUT ;
    USE SIGNAL ;
    PORT
      LAYER M5 ;
        RECT  54.096 97.116 54.12 97.2 ;
    END
  END ctx_t_h[6]
  PIN ctx_t_h[7]
    DIRECTION OUTPUT ;
    USE SIGNAL ;
    PORT
      LAYER M5 ;
        RECT  54.192 97.116 54.216 97.2 ;
    END
  END ctx_t_h[7]
  PIN ctx_t_h[8]
    DIRECTION OUTPUT ;
    USE SIGNAL ;
    PORT
      LAYER M5 ;
        RECT  54.288 97.116 54.312 97.2 ;
    END
  END ctx_t_h[8]
  PIN ctx_t_h[9]
    DIRECTION OUTPUT ;
    USE SIGNAL ;
    PORT
      LAYER M5 ;
        RECT  54.384 97.116 54.408 97.2 ;
    END
  END ctx_t_h[9]
  PIN drain_fault
    DIRECTION OUTPUT ;
    USE SIGNAL ;
    PORT
      LAYER M5 ;
        RECT  86.736 0 86.76 0.084 ;
    END
  END drain_fault
  PIN drained
    DIRECTION OUTPUT ;
    USE SIGNAL ;
    PORT
      LAYER M5 ;
        RECT  86.832 0 86.856 0.084 ;
    END
  END drained
  PIN epoch[0]
    DIRECTION INPUT ;
    USE SIGNAL ;
    PORT
      LAYER M5 ;
        RECT  54.864 97.116 54.888 97.2 ;
    END
  END epoch[0]
  PIN epoch[10]
    DIRECTION INPUT ;
    USE SIGNAL ;
    PORT
      LAYER M5 ;
        RECT  46.608 97.116 46.632 97.2 ;
    END
  END epoch[10]
  PIN epoch[11]
    DIRECTION INPUT ;
    USE SIGNAL ;
    PORT
      LAYER M5 ;
        RECT  46.704 97.116 46.728 97.2 ;
    END
  END epoch[11]
  PIN epoch[12]
    DIRECTION INPUT ;
    USE SIGNAL ;
    PORT
      LAYER M5 ;
        RECT  46.8 97.116 46.824 97.2 ;
    END
  END epoch[12]
  PIN epoch[13]
    DIRECTION INPUT ;
    USE SIGNAL ;
    PORT
      LAYER M5 ;
        RECT  46.896 97.116 46.92 97.2 ;
    END
  END epoch[13]
  PIN epoch[14]
    DIRECTION INPUT ;
    USE SIGNAL ;
    PORT
      LAYER M5 ;
        RECT  46.992 97.116 47.016 97.2 ;
    END
  END epoch[14]
  PIN epoch[15]
    DIRECTION INPUT ;
    USE SIGNAL ;
    PORT
      LAYER M5 ;
        RECT  47.088 97.116 47.112 97.2 ;
    END
  END epoch[15]
  PIN epoch[1]
    DIRECTION INPUT ;
    USE SIGNAL ;
    PORT
      LAYER M5 ;
        RECT  54.96 97.116 54.984 97.2 ;
    END
  END epoch[1]
  PIN epoch[2]
    DIRECTION INPUT ;
    USE SIGNAL ;
    PORT
      LAYER M5 ;
        RECT  45.84 97.116 45.864 97.2 ;
    END
  END epoch[2]
  PIN epoch[3]
    DIRECTION INPUT ;
    USE SIGNAL ;
    PORT
      LAYER M5 ;
        RECT  45.936 97.116 45.96 97.2 ;
    END
  END epoch[3]
  PIN epoch[4]
    DIRECTION INPUT ;
    USE SIGNAL ;
    PORT
      LAYER M5 ;
        RECT  46.032 97.116 46.056 97.2 ;
    END
  END epoch[4]
  PIN epoch[5]
    DIRECTION INPUT ;
    USE SIGNAL ;
    PORT
      LAYER M5 ;
        RECT  46.128 97.116 46.152 97.2 ;
    END
  END epoch[5]
  PIN epoch[6]
    DIRECTION INPUT ;
    USE SIGNAL ;
    PORT
      LAYER M5 ;
        RECT  46.224 97.116 46.248 97.2 ;
    END
  END epoch[6]
  PIN epoch[7]
    DIRECTION INPUT ;
    USE SIGNAL ;
    PORT
      LAYER M5 ;
        RECT  46.32 97.116 46.344 97.2 ;
    END
  END epoch[7]
  PIN epoch[8]
    DIRECTION INPUT ;
    USE SIGNAL ;
    PORT
      LAYER M5 ;
        RECT  46.416 97.116 46.44 97.2 ;
    END
  END epoch[8]
  PIN epoch[9]
    DIRECTION INPUT ;
    USE SIGNAL ;
    PORT
      LAYER M5 ;
        RECT  46.512 97.116 46.536 97.2 ;
    END
  END epoch[9]
  PIN epoch_h[0]
    DIRECTION OUTPUT ;
    USE SIGNAL ;
    PORT
      LAYER M5 ;
        RECT  47.184 97.116 47.208 97.2 ;
    END
  END epoch_h[0]
  PIN epoch_h[10]
    DIRECTION OUTPUT ;
    USE SIGNAL ;
    PORT
      LAYER M5 ;
        RECT  48.144 97.116 48.168 97.2 ;
    END
  END epoch_h[10]
  PIN epoch_h[11]
    DIRECTION OUTPUT ;
    USE SIGNAL ;
    PORT
      LAYER M5 ;
        RECT  48.24 97.116 48.264 97.2 ;
    END
  END epoch_h[11]
  PIN epoch_h[12]
    DIRECTION OUTPUT ;
    USE SIGNAL ;
    PORT
      LAYER M5 ;
        RECT  48.336 97.116 48.36 97.2 ;
    END
  END epoch_h[12]
  PIN epoch_h[13]
    DIRECTION OUTPUT ;
    USE SIGNAL ;
    PORT
      LAYER M5 ;
        RECT  48.432 97.116 48.456 97.2 ;
    END
  END epoch_h[13]
  PIN epoch_h[14]
    DIRECTION OUTPUT ;
    USE SIGNAL ;
    PORT
      LAYER M5 ;
        RECT  48.528 97.116 48.552 97.2 ;
    END
  END epoch_h[14]
  PIN epoch_h[15]
    DIRECTION OUTPUT ;
    USE SIGNAL ;
    PORT
      LAYER M5 ;
        RECT  48.624 97.116 48.648 97.2 ;
    END
  END epoch_h[15]
  PIN epoch_h[1]
    DIRECTION OUTPUT ;
    USE SIGNAL ;
    PORT
      LAYER M5 ;
        RECT  47.28 97.116 47.304 97.2 ;
    END
  END epoch_h[1]
  PIN epoch_h[2]
    DIRECTION OUTPUT ;
    USE SIGNAL ;
    PORT
      LAYER M5 ;
        RECT  47.376 97.116 47.4 97.2 ;
    END
  END epoch_h[2]
  PIN epoch_h[3]
    DIRECTION OUTPUT ;
    USE SIGNAL ;
    PORT
      LAYER M5 ;
        RECT  47.472 97.116 47.496 97.2 ;
    END
  END epoch_h[3]
  PIN epoch_h[4]
    DIRECTION OUTPUT ;
    USE SIGNAL ;
    PORT
      LAYER M5 ;
        RECT  47.568 97.116 47.592 97.2 ;
    END
  END epoch_h[4]
  PIN epoch_h[5]
    DIRECTION OUTPUT ;
    USE SIGNAL ;
    PORT
      LAYER M5 ;
        RECT  47.664 97.116 47.688 97.2 ;
    END
  END epoch_h[5]
  PIN epoch_h[6]
    DIRECTION OUTPUT ;
    USE SIGNAL ;
    PORT
      LAYER M5 ;
        RECT  47.76 97.116 47.784 97.2 ;
    END
  END epoch_h[6]
  PIN epoch_h[7]
    DIRECTION OUTPUT ;
    USE SIGNAL ;
    PORT
      LAYER M5 ;
        RECT  47.856 97.116 47.88 97.2 ;
    END
  END epoch_h[7]
  PIN epoch_h[8]
    DIRECTION OUTPUT ;
    USE SIGNAL ;
    PORT
      LAYER M5 ;
        RECT  47.952 97.116 47.976 97.2 ;
    END
  END epoch_h[8]
  PIN epoch_h[9]
    DIRECTION OUTPUT ;
    USE SIGNAL ;
    PORT
      LAYER M5 ;
        RECT  48.048 97.116 48.072 97.2 ;
    END
  END epoch_h[9]
  PIN front_fault_go_hbm[0]
    DIRECTION INPUT ;
    USE SIGNAL ;
    PORT
      LAYER M5 ;
        RECT  86.928 0 86.952 0.084 ;
    END
  END front_fault_go_hbm[0]
  PIN front_fault_go_hbm[1]
    DIRECTION INPUT ;
    USE SIGNAL ;
    PORT
      LAYER M5 ;
        RECT  87.024 0 87.048 0.084 ;
    END
  END front_fault_go_hbm[1]
  PIN front_fault_go_hbm[2]
    DIRECTION INPUT ;
    USE SIGNAL ;
    PORT
      LAYER M5 ;
        RECT  87.12 0 87.144 0.084 ;
    END
  END front_fault_go_hbm[2]
  PIN front_fault_go_hbm[3]
    DIRECTION INPUT ;
    USE SIGNAL ;
    PORT
      LAYER M5 ;
        RECT  87.216 0 87.24 0.084 ;
    END
  END front_fault_go_hbm[3]
  PIN front_fault_overflow_hbm[0]
    DIRECTION INPUT ;
    USE SIGNAL ;
    PORT
      LAYER M5 ;
        RECT  87.312 0 87.336 0.084 ;
    END
  END front_fault_overflow_hbm[0]
  PIN front_fault_overflow_hbm[1]
    DIRECTION INPUT ;
    USE SIGNAL ;
    PORT
      LAYER M5 ;
        RECT  87.408 0 87.432 0.084 ;
    END
  END front_fault_overflow_hbm[1]
  PIN front_fault_overflow_hbm[2]
    DIRECTION INPUT ;
    USE SIGNAL ;
    PORT
      LAYER M5 ;
        RECT  87.504 0 87.528 0.084 ;
    END
  END front_fault_overflow_hbm[2]
  PIN front_fault_overflow_hbm[3]
    DIRECTION INPUT ;
    USE SIGNAL ;
    PORT
      LAYER M5 ;
        RECT  87.6 0 87.624 0.084 ;
    END
  END front_fault_overflow_hbm[3]
  PIN front_hold_hbm[0]
    DIRECTION INPUT ;
    USE SIGNAL ;
    PORT
      LAYER M5 ;
        RECT  87.696 0 87.72 0.084 ;
    END
  END front_hold_hbm[0]
  PIN front_hold_hbm[1]
    DIRECTION INPUT ;
    USE SIGNAL ;
    PORT
      LAYER M5 ;
        RECT  87.792 0 87.816 0.084 ;
    END
  END front_hold_hbm[1]
  PIN front_hold_hbm[2]
    DIRECTION INPUT ;
    USE SIGNAL ;
    PORT
      LAYER M5 ;
        RECT  87.888 0 87.912 0.084 ;
    END
  END front_hold_hbm[2]
  PIN front_hold_hbm[3]
    DIRECTION INPUT ;
    USE SIGNAL ;
    PORT
      LAYER M5 ;
        RECT  87.984 0 88.008 0.084 ;
    END
  END front_hold_hbm[3]
  PIN front_idle_hbm[0]
    DIRECTION INPUT ;
    USE SIGNAL ;
    PORT
      LAYER M5 ;
        RECT  88.08 0 88.104 0.084 ;
    END
  END front_idle_hbm[0]
  PIN front_idle_hbm[1]
    DIRECTION INPUT ;
    USE SIGNAL ;
    PORT
      LAYER M5 ;
        RECT  88.176 0 88.2 0.084 ;
    END
  END front_idle_hbm[1]
  PIN front_idle_hbm[2]
    DIRECTION INPUT ;
    USE SIGNAL ;
    PORT
      LAYER M5 ;
        RECT  88.272 0 88.296 0.084 ;
    END
  END front_idle_hbm[2]
  PIN front_idle_hbm[3]
    DIRECTION INPUT ;
    USE SIGNAL ;
    PORT
      LAYER M5 ;
        RECT  88.368 0 88.392 0.084 ;
    END
  END front_idle_hbm[3]
  PIN hck
    DIRECTION INPUT ;
    USE SIGNAL ;
    PORT
      LAYER M4 ;
        RECT  97.116 48.144 97.2 48.168 ;
    END
  END hck
  PIN hrst_n
    DIRECTION INPUT ;
    USE SIGNAL ;
    PORT
      LAYER M4 ;
        RECT  97.116 49.68 97.2 49.704 ;
    END
  END hrst_n
  PIN kgo
    DIRECTION INPUT ;
    USE SIGNAL ;
    PORT
      LAYER M5 ;
        RECT  48.72 97.116 48.744 97.2 ;
    END
  END kgo
  PIN kgo_h
    DIRECTION OUTPUT ;
    USE SIGNAL ;
    PORT
      LAYER M5 ;
        RECT  48.816 97.116 48.84 97.2 ;
    END
  END kgo_h
  PIN layer[0]
    DIRECTION INPUT ;
    USE SIGNAL ;
    PORT
      LAYER M5 ;
        RECT  50.256 97.116 50.28 97.2 ;
    END
  END layer[0]
  PIN layer[1]
    DIRECTION INPUT ;
    USE SIGNAL ;
    PORT
      LAYER M5 ;
        RECT  50.352 97.116 50.376 97.2 ;
    END
  END layer[1]
  PIN layer[2]
    DIRECTION INPUT ;
    USE SIGNAL ;
    PORT
      LAYER M5 ;
        RECT  50.448 97.116 50.472 97.2 ;
    END
  END layer[2]
  PIN layer[3]
    DIRECTION INPUT ;
    USE SIGNAL ;
    PORT
      LAYER M5 ;
        RECT  50.544 97.116 50.568 97.2 ;
    END
  END layer[3]
  PIN layer[4]
    DIRECTION INPUT ;
    USE SIGNAL ;
    PORT
      LAYER M5 ;
        RECT  50.64 97.116 50.664 97.2 ;
    END
  END layer[4]
  PIN layer[5]
    DIRECTION INPUT ;
    USE SIGNAL ;
    PORT
      LAYER M5 ;
        RECT  50.736 97.116 50.76 97.2 ;
    END
  END layer[5]
  PIN layer_h[0]
    DIRECTION OUTPUT ;
    USE SIGNAL ;
    PORT
      LAYER M5 ;
        RECT  50.832 97.116 50.856 97.2 ;
    END
  END layer_h[0]
  PIN layer_h[1]
    DIRECTION OUTPUT ;
    USE SIGNAL ;
    PORT
      LAYER M5 ;
        RECT  50.928 97.116 50.952 97.2 ;
    END
  END layer_h[1]
  PIN layer_h[2]
    DIRECTION OUTPUT ;
    USE SIGNAL ;
    PORT
      LAYER M5 ;
        RECT  51.024 97.116 51.048 97.2 ;
    END
  END layer_h[2]
  PIN layer_h[3]
    DIRECTION OUTPUT ;
    USE SIGNAL ;
    PORT
      LAYER M5 ;
        RECT  51.12 97.116 51.144 97.2 ;
    END
  END layer_h[3]
  PIN layer_h[4]
    DIRECTION OUTPUT ;
    USE SIGNAL ;
    PORT
      LAYER M5 ;
        RECT  51.216 97.116 51.24 97.2 ;
    END
  END layer_h[4]
  PIN layer_h[5]
    DIRECTION OUTPUT ;
    USE SIGNAL ;
    PORT
      LAYER M5 ;
        RECT  51.312 97.116 51.336 97.2 ;
    END
  END layer_h[5]
  PIN ph_fault_core
    DIRECTION OUTPUT ;
    USE SIGNAL ;
    PORT
      LAYER M5 ;
        RECT  51.408 97.116 51.432 97.2 ;
    END
  END ph_fault_core
  PIN ph_fault_hbm
    DIRECTION OUTPUT ;
    USE SIGNAL ;
    PORT
      LAYER M5 ;
        RECT  51.504 97.116 51.528 97.2 ;
    END
  END ph_fault_hbm
  PIN ph_idle_core
    DIRECTION OUTPUT ;
    USE SIGNAL ;
    PORT
      LAYER M5 ;
        RECT  51.6 97.116 51.624 97.2 ;
    END
  END ph_idle_core
  PIN ph_idle_hbm
    DIRECTION OUTPUT ;
    USE SIGNAL ;
    PORT
      LAYER M5 ;
        RECT  51.696 97.116 51.72 97.2 ;
    END
  END ph_idle_hbm
  PIN ring_fault_core[0]
    DIRECTION INPUT ;
    USE SIGNAL ;
    PORT
      LAYER M5 ;
        RECT  88.464 0 88.488 0.084 ;
    END
  END ring_fault_core[0]
  PIN ring_fault_core[1]
    DIRECTION INPUT ;
    USE SIGNAL ;
    PORT
      LAYER M5 ;
        RECT  88.56 0 88.584 0.084 ;
    END
  END ring_fault_core[1]
  PIN ring_fault_core[2]
    DIRECTION INPUT ;
    USE SIGNAL ;
    PORT
      LAYER M5 ;
        RECT  88.656 0 88.68 0.084 ;
    END
  END ring_fault_core[2]
  PIN ring_fault_core[3]
    DIRECTION INPUT ;
    USE SIGNAL ;
    PORT
      LAYER M5 ;
        RECT  88.752 0 88.776 0.084 ;
    END
  END ring_fault_core[3]
  PIN ring_fault_hbm[0]
    DIRECTION INPUT ;
    USE SIGNAL ;
    PORT
      LAYER M5 ;
        RECT  88.848 0 88.872 0.084 ;
    END
  END ring_fault_hbm[0]
  PIN ring_fault_hbm[1]
    DIRECTION INPUT ;
    USE SIGNAL ;
    PORT
      LAYER M5 ;
        RECT  88.944 0 88.968 0.084 ;
    END
  END ring_fault_hbm[1]
  PIN ring_fault_hbm[2]
    DIRECTION INPUT ;
    USE SIGNAL ;
    PORT
      LAYER M5 ;
        RECT  89.04 0 89.064 0.084 ;
    END
  END ring_fault_hbm[2]
  PIN ring_fault_hbm[3]
    DIRECTION INPUT ;
    USE SIGNAL ;
    PORT
      LAYER M5 ;
        RECT  89.136 0 89.16 0.084 ;
    END
  END ring_fault_hbm[3]
  PIN ring_idle_core[0]
    DIRECTION INPUT ;
    USE SIGNAL ;
    PORT
      LAYER M5 ;
        RECT  89.232 0 89.256 0.084 ;
    END
  END ring_idle_core[0]
  PIN ring_idle_core[1]
    DIRECTION INPUT ;
    USE SIGNAL ;
    PORT
      LAYER M5 ;
        RECT  89.328 0 89.352 0.084 ;
    END
  END ring_idle_core[1]
  PIN ring_idle_core[2]
    DIRECTION INPUT ;
    USE SIGNAL ;
    PORT
      LAYER M5 ;
        RECT  89.424 0 89.448 0.084 ;
    END
  END ring_idle_core[2]
  PIN ring_idle_core[3]
    DIRECTION INPUT ;
    USE SIGNAL ;
    PORT
      LAYER M5 ;
        RECT  89.52 0 89.544 0.084 ;
    END
  END ring_idle_core[3]
  PIN ring_idle_hbm[0]
    DIRECTION INPUT ;
    USE SIGNAL ;
    PORT
      LAYER M5 ;
        RECT  89.616 0 89.64 0.084 ;
    END
  END ring_idle_hbm[0]
  PIN ring_idle_hbm[1]
    DIRECTION INPUT ;
    USE SIGNAL ;
    PORT
      LAYER M5 ;
        RECT  89.712 0 89.736 0.084 ;
    END
  END ring_idle_hbm[1]
  PIN ring_idle_hbm[2]
    DIRECTION INPUT ;
    USE SIGNAL ;
    PORT
      LAYER M5 ;
        RECT  89.808 0 89.832 0.084 ;
    END
  END ring_idle_hbm[2]
  PIN ring_idle_hbm[3]
    DIRECTION INPUT ;
    USE SIGNAL ;
    PORT
      LAYER M5 ;
        RECT  89.904 0 89.928 0.084 ;
    END
  END ring_idle_hbm[3]
  PIN rst_n
    DIRECTION INPUT ;
    USE SIGNAL ;
    PORT
      LAYER M4 ;
        RECT  0 50.352 0.084 50.376 ;
    END
  END rst_n
  PIN sink_addr[0]
    DIRECTION OUTPUT ;
    USE SIGNAL ;
    PORT
      LAYER M4 ;
        RECT  97.116 43.152 97.2 43.176 ;
    END
  END sink_addr[0]
  PIN sink_addr[10]
    DIRECTION OUTPUT ;
    USE SIGNAL ;
    PORT
      LAYER M4 ;
        RECT  97.116 44.112 97.2 44.136 ;
    END
  END sink_addr[10]
  PIN sink_addr[11]
    DIRECTION OUTPUT ;
    USE SIGNAL ;
    PORT
      LAYER M4 ;
        RECT  97.116 44.208 97.2 44.232 ;
    END
  END sink_addr[11]
  PIN sink_addr[12]
    DIRECTION OUTPUT ;
    USE SIGNAL ;
    PORT
      LAYER M4 ;
        RECT  97.116 44.304 97.2 44.328 ;
    END
  END sink_addr[12]
  PIN sink_addr[13]
    DIRECTION OUTPUT ;
    USE SIGNAL ;
    PORT
      LAYER M4 ;
        RECT  97.116 44.4 97.2 44.424 ;
    END
  END sink_addr[13]
  PIN sink_addr[14]
    DIRECTION OUTPUT ;
    USE SIGNAL ;
    PORT
      LAYER M4 ;
        RECT  97.116 44.496 97.2 44.52 ;
    END
  END sink_addr[14]
  PIN sink_addr[15]
    DIRECTION OUTPUT ;
    USE SIGNAL ;
    PORT
      LAYER M4 ;
        RECT  97.116 44.592 97.2 44.616 ;
    END
  END sink_addr[15]
  PIN sink_addr[16]
    DIRECTION OUTPUT ;
    USE SIGNAL ;
    PORT
      LAYER M4 ;
        RECT  97.116 44.688 97.2 44.712 ;
    END
  END sink_addr[16]
  PIN sink_addr[17]
    DIRECTION OUTPUT ;
    USE SIGNAL ;
    PORT
      LAYER M4 ;
        RECT  97.116 44.784 97.2 44.808 ;
    END
  END sink_addr[17]
  PIN sink_addr[18]
    DIRECTION OUTPUT ;
    USE SIGNAL ;
    PORT
      LAYER M4 ;
        RECT  97.116 44.88 97.2 44.904 ;
    END
  END sink_addr[18]
  PIN sink_addr[19]
    DIRECTION OUTPUT ;
    USE SIGNAL ;
    PORT
      LAYER M4 ;
        RECT  97.116 44.976 97.2 45 ;
    END
  END sink_addr[19]
  PIN sink_addr[1]
    DIRECTION OUTPUT ;
    USE SIGNAL ;
    PORT
      LAYER M4 ;
        RECT  97.116 43.248 97.2 43.272 ;
    END
  END sink_addr[1]
  PIN sink_addr[20]
    DIRECTION OUTPUT ;
    USE SIGNAL ;
    PORT
      LAYER M4 ;
        RECT  97.116 45.072 97.2 45.096 ;
    END
  END sink_addr[20]
  PIN sink_addr[21]
    DIRECTION OUTPUT ;
    USE SIGNAL ;
    PORT
      LAYER M4 ;
        RECT  97.116 45.168 97.2 45.192 ;
    END
  END sink_addr[21]
  PIN sink_addr[22]
    DIRECTION OUTPUT ;
    USE SIGNAL ;
    PORT
      LAYER M4 ;
        RECT  97.116 35.28 97.2 35.304 ;
    END
  END sink_addr[22]
  PIN sink_addr[23]
    DIRECTION OUTPUT ;
    USE SIGNAL ;
    PORT
      LAYER M4 ;
        RECT  97.116 35.376 97.2 35.4 ;
    END
  END sink_addr[23]
  PIN sink_addr[24]
    DIRECTION OUTPUT ;
    USE SIGNAL ;
    PORT
      LAYER M4 ;
        RECT  97.116 35.472 97.2 35.496 ;
    END
  END sink_addr[24]
  PIN sink_addr[25]
    DIRECTION OUTPUT ;
    USE SIGNAL ;
    PORT
      LAYER M4 ;
        RECT  97.116 35.568 97.2 35.592 ;
    END
  END sink_addr[25]
  PIN sink_addr[26]
    DIRECTION OUTPUT ;
    USE SIGNAL ;
    PORT
      LAYER M4 ;
        RECT  97.116 35.664 97.2 35.688 ;
    END
  END sink_addr[26]
  PIN sink_addr[27]
    DIRECTION OUTPUT ;
    USE SIGNAL ;
    PORT
      LAYER M4 ;
        RECT  97.116 35.76 97.2 35.784 ;
    END
  END sink_addr[27]
  PIN sink_addr[28]
    DIRECTION OUTPUT ;
    USE SIGNAL ;
    PORT
      LAYER M4 ;
        RECT  97.116 35.856 97.2 35.88 ;
    END
  END sink_addr[28]
  PIN sink_addr[29]
    DIRECTION OUTPUT ;
    USE SIGNAL ;
    PORT
      LAYER M4 ;
        RECT  97.116 35.952 97.2 35.976 ;
    END
  END sink_addr[29]
  PIN sink_addr[2]
    DIRECTION OUTPUT ;
    USE SIGNAL ;
    PORT
      LAYER M4 ;
        RECT  97.116 43.344 97.2 43.368 ;
    END
  END sink_addr[2]
  PIN sink_addr[30]
    DIRECTION OUTPUT ;
    USE SIGNAL ;
    PORT
      LAYER M4 ;
        RECT  97.116 36.048 97.2 36.072 ;
    END
  END sink_addr[30]
  PIN sink_addr[31]
    DIRECTION OUTPUT ;
    USE SIGNAL ;
    PORT
      LAYER M4 ;
        RECT  97.116 36.144 97.2 36.168 ;
    END
  END sink_addr[31]
  PIN sink_addr[32]
    DIRECTION OUTPUT ;
    USE SIGNAL ;
    PORT
      LAYER M4 ;
        RECT  97.116 36.24 97.2 36.264 ;
    END
  END sink_addr[32]
  PIN sink_addr[33]
    DIRECTION OUTPUT ;
    USE SIGNAL ;
    PORT
      LAYER M4 ;
        RECT  97.116 36.336 97.2 36.36 ;
    END
  END sink_addr[33]
  PIN sink_addr[34]
    DIRECTION OUTPUT ;
    USE SIGNAL ;
    PORT
      LAYER M4 ;
        RECT  97.116 36.432 97.2 36.456 ;
    END
  END sink_addr[34]
  PIN sink_addr[35]
    DIRECTION OUTPUT ;
    USE SIGNAL ;
    PORT
      LAYER M4 ;
        RECT  97.116 36.528 97.2 36.552 ;
    END
  END sink_addr[35]
  PIN sink_addr[36]
    DIRECTION OUTPUT ;
    USE SIGNAL ;
    PORT
      LAYER M4 ;
        RECT  97.116 36.624 97.2 36.648 ;
    END
  END sink_addr[36]
  PIN sink_addr[37]
    DIRECTION OUTPUT ;
    USE SIGNAL ;
    PORT
      LAYER M4 ;
        RECT  97.116 36.72 97.2 36.744 ;
    END
  END sink_addr[37]
  PIN sink_addr[38]
    DIRECTION OUTPUT ;
    USE SIGNAL ;
    PORT
      LAYER M4 ;
        RECT  97.116 36.816 97.2 36.84 ;
    END
  END sink_addr[38]
  PIN sink_addr[39]
    DIRECTION OUTPUT ;
    USE SIGNAL ;
    PORT
      LAYER M4 ;
        RECT  97.116 36.912 97.2 36.936 ;
    END
  END sink_addr[39]
  PIN sink_addr[3]
    DIRECTION OUTPUT ;
    USE SIGNAL ;
    PORT
      LAYER M4 ;
        RECT  97.116 43.44 97.2 43.464 ;
    END
  END sink_addr[3]
  PIN sink_addr[4]
    DIRECTION OUTPUT ;
    USE SIGNAL ;
    PORT
      LAYER M4 ;
        RECT  97.116 43.536 97.2 43.56 ;
    END
  END sink_addr[4]
  PIN sink_addr[5]
    DIRECTION OUTPUT ;
    USE SIGNAL ;
    PORT
      LAYER M4 ;
        RECT  97.116 43.632 97.2 43.656 ;
    END
  END sink_addr[5]
  PIN sink_addr[6]
    DIRECTION OUTPUT ;
    USE SIGNAL ;
    PORT
      LAYER M4 ;
        RECT  97.116 43.728 97.2 43.752 ;
    END
  END sink_addr[6]
  PIN sink_addr[7]
    DIRECTION OUTPUT ;
    USE SIGNAL ;
    PORT
      LAYER M4 ;
        RECT  97.116 43.824 97.2 43.848 ;
    END
  END sink_addr[7]
  PIN sink_addr[8]
    DIRECTION OUTPUT ;
    USE SIGNAL ;
    PORT
      LAYER M4 ;
        RECT  97.116 43.92 97.2 43.944 ;
    END
  END sink_addr[8]
  PIN sink_addr[9]
    DIRECTION OUTPUT ;
    USE SIGNAL ;
    PORT
      LAYER M4 ;
        RECT  97.116 44.016 97.2 44.04 ;
    END
  END sink_addr[9]
  PIN sink_data[0]
    DIRECTION OUTPUT ;
    USE SIGNAL ;
    PORT
      LAYER M4 ;
        RECT  97.116 37.008 97.2 37.032 ;
    END
  END sink_data[0]
  PIN sink_data[100]
    DIRECTION OUTPUT ;
    USE SIGNAL ;
    PORT
      LAYER M4 ;
        RECT  97.116 79.632 97.2 79.656 ;
    END
  END sink_data[100]
  PIN sink_data[101]
    DIRECTION OUTPUT ;
    USE SIGNAL ;
    PORT
      LAYER M4 ;
        RECT  97.116 79.728 97.2 79.752 ;
    END
  END sink_data[101]
  PIN sink_data[102]
    DIRECTION OUTPUT ;
    USE SIGNAL ;
    PORT
      LAYER M4 ;
        RECT  97.116 79.824 97.2 79.848 ;
    END
  END sink_data[102]
  PIN sink_data[103]
    DIRECTION OUTPUT ;
    USE SIGNAL ;
    PORT
      LAYER M4 ;
        RECT  97.116 79.92 97.2 79.944 ;
    END
  END sink_data[103]
  PIN sink_data[104]
    DIRECTION OUTPUT ;
    USE SIGNAL ;
    PORT
      LAYER M4 ;
        RECT  97.116 80.016 97.2 80.04 ;
    END
  END sink_data[104]
  PIN sink_data[105]
    DIRECTION OUTPUT ;
    USE SIGNAL ;
    PORT
      LAYER M4 ;
        RECT  97.116 80.112 97.2 80.136 ;
    END
  END sink_data[105]
  PIN sink_data[106]
    DIRECTION OUTPUT ;
    USE SIGNAL ;
    PORT
      LAYER M4 ;
        RECT  97.116 80.208 97.2 80.232 ;
    END
  END sink_data[106]
  PIN sink_data[107]
    DIRECTION OUTPUT ;
    USE SIGNAL ;
    PORT
      LAYER M4 ;
        RECT  97.116 80.304 97.2 80.328 ;
    END
  END sink_data[107]
  PIN sink_data[108]
    DIRECTION OUTPUT ;
    USE SIGNAL ;
    PORT
      LAYER M4 ;
        RECT  97.116 80.4 97.2 80.424 ;
    END
  END sink_data[108]
  PIN sink_data[109]
    DIRECTION OUTPUT ;
    USE SIGNAL ;
    PORT
      LAYER M4 ;
        RECT  97.116 80.496 97.2 80.52 ;
    END
  END sink_data[109]
  PIN sink_data[10]
    DIRECTION OUTPUT ;
    USE SIGNAL ;
    PORT
      LAYER M4 ;
        RECT  97.116 37.968 97.2 37.992 ;
    END
  END sink_data[10]
  PIN sink_data[110]
    DIRECTION OUTPUT ;
    USE SIGNAL ;
    PORT
      LAYER M4 ;
        RECT  97.116 73.68 97.2 73.704 ;
    END
  END sink_data[110]
  PIN sink_data[111]
    DIRECTION OUTPUT ;
    USE SIGNAL ;
    PORT
      LAYER M4 ;
        RECT  97.116 73.776 97.2 73.8 ;
    END
  END sink_data[111]
  PIN sink_data[112]
    DIRECTION OUTPUT ;
    USE SIGNAL ;
    PORT
      LAYER M4 ;
        RECT  97.116 73.872 97.2 73.896 ;
    END
  END sink_data[112]
  PIN sink_data[113]
    DIRECTION OUTPUT ;
    USE SIGNAL ;
    PORT
      LAYER M4 ;
        RECT  97.116 73.968 97.2 73.992 ;
    END
  END sink_data[113]
  PIN sink_data[114]
    DIRECTION OUTPUT ;
    USE SIGNAL ;
    PORT
      LAYER M4 ;
        RECT  97.116 74.064 97.2 74.088 ;
    END
  END sink_data[114]
  PIN sink_data[115]
    DIRECTION OUTPUT ;
    USE SIGNAL ;
    PORT
      LAYER M4 ;
        RECT  97.116 74.16 97.2 74.184 ;
    END
  END sink_data[115]
  PIN sink_data[116]
    DIRECTION OUTPUT ;
    USE SIGNAL ;
    PORT
      LAYER M4 ;
        RECT  97.116 74.256 97.2 74.28 ;
    END
  END sink_data[116]
  PIN sink_data[117]
    DIRECTION OUTPUT ;
    USE SIGNAL ;
    PORT
      LAYER M4 ;
        RECT  97.116 74.352 97.2 74.376 ;
    END
  END sink_data[117]
  PIN sink_data[118]
    DIRECTION OUTPUT ;
    USE SIGNAL ;
    PORT
      LAYER M4 ;
        RECT  97.116 74.448 97.2 74.472 ;
    END
  END sink_data[118]
  PIN sink_data[119]
    DIRECTION OUTPUT ;
    USE SIGNAL ;
    PORT
      LAYER M4 ;
        RECT  97.116 74.544 97.2 74.568 ;
    END
  END sink_data[119]
  PIN sink_data[11]
    DIRECTION OUTPUT ;
    USE SIGNAL ;
    PORT
      LAYER M4 ;
        RECT  97.116 38.064 97.2 38.088 ;
    END
  END sink_data[11]
  PIN sink_data[120]
    DIRECTION OUTPUT ;
    USE SIGNAL ;
    PORT
      LAYER M4 ;
        RECT  97.116 74.64 97.2 74.664 ;
    END
  END sink_data[120]
  PIN sink_data[121]
    DIRECTION OUTPUT ;
    USE SIGNAL ;
    PORT
      LAYER M4 ;
        RECT  97.116 74.736 97.2 74.76 ;
    END
  END sink_data[121]
  PIN sink_data[122]
    DIRECTION OUTPUT ;
    USE SIGNAL ;
    PORT
      LAYER M4 ;
        RECT  97.116 74.832 97.2 74.856 ;
    END
  END sink_data[122]
  PIN sink_data[123]
    DIRECTION OUTPUT ;
    USE SIGNAL ;
    PORT
      LAYER M4 ;
        RECT  97.116 74.928 97.2 74.952 ;
    END
  END sink_data[123]
  PIN sink_data[124]
    DIRECTION OUTPUT ;
    USE SIGNAL ;
    PORT
      LAYER M4 ;
        RECT  97.116 75.024 97.2 75.048 ;
    END
  END sink_data[124]
  PIN sink_data[125]
    DIRECTION OUTPUT ;
    USE SIGNAL ;
    PORT
      LAYER M4 ;
        RECT  97.116 75.12 97.2 75.144 ;
    END
  END sink_data[125]
  PIN sink_data[126]
    DIRECTION OUTPUT ;
    USE SIGNAL ;
    PORT
      LAYER M4 ;
        RECT  97.116 75.216 97.2 75.24 ;
    END
  END sink_data[126]
  PIN sink_data[127]
    DIRECTION OUTPUT ;
    USE SIGNAL ;
    PORT
      LAYER M4 ;
        RECT  97.116 75.312 97.2 75.336 ;
    END
  END sink_data[127]
  PIN sink_data[128]
    DIRECTION OUTPUT ;
    USE SIGNAL ;
    PORT
      LAYER M4 ;
        RECT  97.116 75.408 97.2 75.432 ;
    END
  END sink_data[128]
  PIN sink_data[129]
    DIRECTION OUTPUT ;
    USE SIGNAL ;
    PORT
      LAYER M4 ;
        RECT  97.116 75.504 97.2 75.528 ;
    END
  END sink_data[129]
  PIN sink_data[12]
    DIRECTION OUTPUT ;
    USE SIGNAL ;
    PORT
      LAYER M4 ;
        RECT  97.116 38.16 97.2 38.184 ;
    END
  END sink_data[12]
  PIN sink_data[130]
    DIRECTION OUTPUT ;
    USE SIGNAL ;
    PORT
      LAYER M4 ;
        RECT  97.116 75.6 97.2 75.624 ;
    END
  END sink_data[130]
  PIN sink_data[131]
    DIRECTION OUTPUT ;
    USE SIGNAL ;
    PORT
      LAYER M4 ;
        RECT  97.116 75.696 97.2 75.72 ;
    END
  END sink_data[131]
  PIN sink_data[132]
    DIRECTION OUTPUT ;
    USE SIGNAL ;
    PORT
      LAYER M4 ;
        RECT  97.116 75.792 97.2 75.816 ;
    END
  END sink_data[132]
  PIN sink_data[133]
    DIRECTION OUTPUT ;
    USE SIGNAL ;
    PORT
      LAYER M4 ;
        RECT  97.116 75.888 97.2 75.912 ;
    END
  END sink_data[133]
  PIN sink_data[134]
    DIRECTION OUTPUT ;
    USE SIGNAL ;
    PORT
      LAYER M4 ;
        RECT  97.116 75.984 97.2 76.008 ;
    END
  END sink_data[134]
  PIN sink_data[135]
    DIRECTION OUTPUT ;
    USE SIGNAL ;
    PORT
      LAYER M4 ;
        RECT  97.116 76.08 97.2 76.104 ;
    END
  END sink_data[135]
  PIN sink_data[136]
    DIRECTION OUTPUT ;
    USE SIGNAL ;
    PORT
      LAYER M4 ;
        RECT  97.116 76.176 97.2 76.2 ;
    END
  END sink_data[136]
  PIN sink_data[137]
    DIRECTION OUTPUT ;
    USE SIGNAL ;
    PORT
      LAYER M4 ;
        RECT  97.116 76.272 97.2 76.296 ;
    END
  END sink_data[137]
  PIN sink_data[138]
    DIRECTION OUTPUT ;
    USE SIGNAL ;
    PORT
      LAYER M4 ;
        RECT  97.116 76.368 97.2 76.392 ;
    END
  END sink_data[138]
  PIN sink_data[139]
    DIRECTION OUTPUT ;
    USE SIGNAL ;
    PORT
      LAYER M4 ;
        RECT  97.116 76.464 97.2 76.488 ;
    END
  END sink_data[139]
  PIN sink_data[13]
    DIRECTION OUTPUT ;
    USE SIGNAL ;
    PORT
      LAYER M4 ;
        RECT  97.116 38.256 97.2 38.28 ;
    END
  END sink_data[13]
  PIN sink_data[140]
    DIRECTION OUTPUT ;
    USE SIGNAL ;
    PORT
      LAYER M4 ;
        RECT  97.116 76.56 97.2 76.584 ;
    END
  END sink_data[140]
  PIN sink_data[141]
    DIRECTION OUTPUT ;
    USE SIGNAL ;
    PORT
      LAYER M4 ;
        RECT  97.116 76.656 97.2 76.68 ;
    END
  END sink_data[141]
  PIN sink_data[142]
    DIRECTION OUTPUT ;
    USE SIGNAL ;
    PORT
      LAYER M4 ;
        RECT  97.116 49.776 97.2 49.8 ;
    END
  END sink_data[142]
  PIN sink_data[143]
    DIRECTION OUTPUT ;
    USE SIGNAL ;
    PORT
      LAYER M4 ;
        RECT  97.116 49.872 97.2 49.896 ;
    END
  END sink_data[143]
  PIN sink_data[144]
    DIRECTION OUTPUT ;
    USE SIGNAL ;
    PORT
      LAYER M4 ;
        RECT  97.116 49.968 97.2 49.992 ;
    END
  END sink_data[144]
  PIN sink_data[145]
    DIRECTION OUTPUT ;
    USE SIGNAL ;
    PORT
      LAYER M4 ;
        RECT  97.116 50.064 97.2 50.088 ;
    END
  END sink_data[145]
  PIN sink_data[146]
    DIRECTION OUTPUT ;
    USE SIGNAL ;
    PORT
      LAYER M4 ;
        RECT  97.116 50.16 97.2 50.184 ;
    END
  END sink_data[146]
  PIN sink_data[147]
    DIRECTION OUTPUT ;
    USE SIGNAL ;
    PORT
      LAYER M4 ;
        RECT  97.116 50.256 97.2 50.28 ;
    END
  END sink_data[147]
  PIN sink_data[148]
    DIRECTION OUTPUT ;
    USE SIGNAL ;
    PORT
      LAYER M4 ;
        RECT  97.116 50.352 97.2 50.376 ;
    END
  END sink_data[148]
  PIN sink_data[149]
    DIRECTION OUTPUT ;
    USE SIGNAL ;
    PORT
      LAYER M4 ;
        RECT  97.116 50.448 97.2 50.472 ;
    END
  END sink_data[149]
  PIN sink_data[14]
    DIRECTION OUTPUT ;
    USE SIGNAL ;
    PORT
      LAYER M4 ;
        RECT  97.116 3.792 97.2 3.816 ;
    END
  END sink_data[14]
  PIN sink_data[150]
    DIRECTION OUTPUT ;
    USE SIGNAL ;
    PORT
      LAYER M4 ;
        RECT  97.116 50.544 97.2 50.568 ;
    END
  END sink_data[150]
  PIN sink_data[151]
    DIRECTION OUTPUT ;
    USE SIGNAL ;
    PORT
      LAYER M4 ;
        RECT  97.116 50.64 97.2 50.664 ;
    END
  END sink_data[151]
  PIN sink_data[152]
    DIRECTION OUTPUT ;
    USE SIGNAL ;
    PORT
      LAYER M4 ;
        RECT  97.116 50.736 97.2 50.76 ;
    END
  END sink_data[152]
  PIN sink_data[153]
    DIRECTION OUTPUT ;
    USE SIGNAL ;
    PORT
      LAYER M4 ;
        RECT  97.116 50.832 97.2 50.856 ;
    END
  END sink_data[153]
  PIN sink_data[154]
    DIRECTION OUTPUT ;
    USE SIGNAL ;
    PORT
      LAYER M4 ;
        RECT  97.116 50.928 97.2 50.952 ;
    END
  END sink_data[154]
  PIN sink_data[155]
    DIRECTION OUTPUT ;
    USE SIGNAL ;
    PORT
      LAYER M4 ;
        RECT  97.116 51.024 97.2 51.048 ;
    END
  END sink_data[155]
  PIN sink_data[156]
    DIRECTION OUTPUT ;
    USE SIGNAL ;
    PORT
      LAYER M4 ;
        RECT  97.116 51.12 97.2 51.144 ;
    END
  END sink_data[156]
  PIN sink_data[157]
    DIRECTION OUTPUT ;
    USE SIGNAL ;
    PORT
      LAYER M4 ;
        RECT  97.116 51.216 97.2 51.24 ;
    END
  END sink_data[157]
  PIN sink_data[158]
    DIRECTION OUTPUT ;
    USE SIGNAL ;
    PORT
      LAYER M4 ;
        RECT  97.116 51.312 97.2 51.336 ;
    END
  END sink_data[158]
  PIN sink_data[159]
    DIRECTION OUTPUT ;
    USE SIGNAL ;
    PORT
      LAYER M4 ;
        RECT  97.116 51.408 97.2 51.432 ;
    END
  END sink_data[159]
  PIN sink_data[15]
    DIRECTION OUTPUT ;
    USE SIGNAL ;
    PORT
      LAYER M4 ;
        RECT  97.116 3.888 97.2 3.912 ;
    END
  END sink_data[15]
  PIN sink_data[160]
    DIRECTION OUTPUT ;
    USE SIGNAL ;
    PORT
      LAYER M4 ;
        RECT  97.116 51.504 97.2 51.528 ;
    END
  END sink_data[160]
  PIN sink_data[161]
    DIRECTION OUTPUT ;
    USE SIGNAL ;
    PORT
      LAYER M4 ;
        RECT  97.116 51.6 97.2 51.624 ;
    END
  END sink_data[161]
  PIN sink_data[162]
    DIRECTION OUTPUT ;
    USE SIGNAL ;
    PORT
      LAYER M4 ;
        RECT  97.116 51.696 97.2 51.72 ;
    END
  END sink_data[162]
  PIN sink_data[163]
    DIRECTION OUTPUT ;
    USE SIGNAL ;
    PORT
      LAYER M4 ;
        RECT  97.116 51.792 97.2 51.816 ;
    END
  END sink_data[163]
  PIN sink_data[164]
    DIRECTION OUTPUT ;
    USE SIGNAL ;
    PORT
      LAYER M4 ;
        RECT  97.116 51.888 97.2 51.912 ;
    END
  END sink_data[164]
  PIN sink_data[165]
    DIRECTION OUTPUT ;
    USE SIGNAL ;
    PORT
      LAYER M4 ;
        RECT  97.116 51.984 97.2 52.008 ;
    END
  END sink_data[165]
  PIN sink_data[166]
    DIRECTION OUTPUT ;
    USE SIGNAL ;
    PORT
      LAYER M4 ;
        RECT  97.116 52.08 97.2 52.104 ;
    END
  END sink_data[166]
  PIN sink_data[167]
    DIRECTION OUTPUT ;
    USE SIGNAL ;
    PORT
      LAYER M4 ;
        RECT  97.116 52.176 97.2 52.2 ;
    END
  END sink_data[167]
  PIN sink_data[168]
    DIRECTION OUTPUT ;
    USE SIGNAL ;
    PORT
      LAYER M4 ;
        RECT  97.116 52.272 97.2 52.296 ;
    END
  END sink_data[168]
  PIN sink_data[169]
    DIRECTION OUTPUT ;
    USE SIGNAL ;
    PORT
      LAYER M4 ;
        RECT  97.116 52.368 97.2 52.392 ;
    END
  END sink_data[169]
  PIN sink_data[16]
    DIRECTION OUTPUT ;
    USE SIGNAL ;
    PORT
      LAYER M4 ;
        RECT  97.116 3.984 97.2 4.008 ;
    END
  END sink_data[16]
  PIN sink_data[170]
    DIRECTION OUTPUT ;
    USE SIGNAL ;
    PORT
      LAYER M4 ;
        RECT  97.116 52.464 97.2 52.488 ;
    END
  END sink_data[170]
  PIN sink_data[171]
    DIRECTION OUTPUT ;
    USE SIGNAL ;
    PORT
      LAYER M4 ;
        RECT  97.116 52.56 97.2 52.584 ;
    END
  END sink_data[171]
  PIN sink_data[172]
    DIRECTION OUTPUT ;
    USE SIGNAL ;
    PORT
      LAYER M4 ;
        RECT  97.116 52.656 97.2 52.68 ;
    END
  END sink_data[172]
  PIN sink_data[173]
    DIRECTION OUTPUT ;
    USE SIGNAL ;
    PORT
      LAYER M4 ;
        RECT  97.116 52.752 97.2 52.776 ;
    END
  END sink_data[173]
  PIN sink_data[174]
    DIRECTION OUTPUT ;
    USE SIGNAL ;
    PORT
      LAYER M4 ;
        RECT  97.116 32.208 97.2 32.232 ;
    END
  END sink_data[174]
  PIN sink_data[175]
    DIRECTION OUTPUT ;
    USE SIGNAL ;
    PORT
      LAYER M4 ;
        RECT  97.116 32.304 97.2 32.328 ;
    END
  END sink_data[175]
  PIN sink_data[176]
    DIRECTION OUTPUT ;
    USE SIGNAL ;
    PORT
      LAYER M4 ;
        RECT  97.116 32.4 97.2 32.424 ;
    END
  END sink_data[176]
  PIN sink_data[177]
    DIRECTION OUTPUT ;
    USE SIGNAL ;
    PORT
      LAYER M4 ;
        RECT  97.116 32.496 97.2 32.52 ;
    END
  END sink_data[177]
  PIN sink_data[178]
    DIRECTION OUTPUT ;
    USE SIGNAL ;
    PORT
      LAYER M4 ;
        RECT  97.116 32.592 97.2 32.616 ;
    END
  END sink_data[178]
  PIN sink_data[179]
    DIRECTION OUTPUT ;
    USE SIGNAL ;
    PORT
      LAYER M4 ;
        RECT  97.116 32.688 97.2 32.712 ;
    END
  END sink_data[179]
  PIN sink_data[17]
    DIRECTION OUTPUT ;
    USE SIGNAL ;
    PORT
      LAYER M4 ;
        RECT  97.116 4.08 97.2 4.104 ;
    END
  END sink_data[17]
  PIN sink_data[180]
    DIRECTION OUTPUT ;
    USE SIGNAL ;
    PORT
      LAYER M4 ;
        RECT  97.116 32.784 97.2 32.808 ;
    END
  END sink_data[180]
  PIN sink_data[181]
    DIRECTION OUTPUT ;
    USE SIGNAL ;
    PORT
      LAYER M4 ;
        RECT  97.116 32.88 97.2 32.904 ;
    END
  END sink_data[181]
  PIN sink_data[182]
    DIRECTION OUTPUT ;
    USE SIGNAL ;
    PORT
      LAYER M4 ;
        RECT  97.116 32.976 97.2 33 ;
    END
  END sink_data[182]
  PIN sink_data[183]
    DIRECTION OUTPUT ;
    USE SIGNAL ;
    PORT
      LAYER M4 ;
        RECT  97.116 33.072 97.2 33.096 ;
    END
  END sink_data[183]
  PIN sink_data[184]
    DIRECTION OUTPUT ;
    USE SIGNAL ;
    PORT
      LAYER M4 ;
        RECT  97.116 33.168 97.2 33.192 ;
    END
  END sink_data[184]
  PIN sink_data[185]
    DIRECTION OUTPUT ;
    USE SIGNAL ;
    PORT
      LAYER M4 ;
        RECT  97.116 33.264 97.2 33.288 ;
    END
  END sink_data[185]
  PIN sink_data[186]
    DIRECTION OUTPUT ;
    USE SIGNAL ;
    PORT
      LAYER M4 ;
        RECT  97.116 33.36 97.2 33.384 ;
    END
  END sink_data[186]
  PIN sink_data[187]
    DIRECTION OUTPUT ;
    USE SIGNAL ;
    PORT
      LAYER M4 ;
        RECT  97.116 33.456 97.2 33.48 ;
    END
  END sink_data[187]
  PIN sink_data[188]
    DIRECTION OUTPUT ;
    USE SIGNAL ;
    PORT
      LAYER M4 ;
        RECT  97.116 33.552 97.2 33.576 ;
    END
  END sink_data[188]
  PIN sink_data[189]
    DIRECTION OUTPUT ;
    USE SIGNAL ;
    PORT
      LAYER M4 ;
        RECT  97.116 33.648 97.2 33.672 ;
    END
  END sink_data[189]
  PIN sink_data[18]
    DIRECTION OUTPUT ;
    USE SIGNAL ;
    PORT
      LAYER M4 ;
        RECT  97.116 4.176 97.2 4.2 ;
    END
  END sink_data[18]
  PIN sink_data[190]
    DIRECTION OUTPUT ;
    USE SIGNAL ;
    PORT
      LAYER M4 ;
        RECT  97.116 33.744 97.2 33.768 ;
    END
  END sink_data[190]
  PIN sink_data[191]
    DIRECTION OUTPUT ;
    USE SIGNAL ;
    PORT
      LAYER M4 ;
        RECT  97.116 33.84 97.2 33.864 ;
    END
  END sink_data[191]
  PIN sink_data[192]
    DIRECTION OUTPUT ;
    USE SIGNAL ;
    PORT
      LAYER M4 ;
        RECT  97.116 33.936 97.2 33.96 ;
    END
  END sink_data[192]
  PIN sink_data[193]
    DIRECTION OUTPUT ;
    USE SIGNAL ;
    PORT
      LAYER M4 ;
        RECT  97.116 34.032 97.2 34.056 ;
    END
  END sink_data[193]
  PIN sink_data[194]
    DIRECTION OUTPUT ;
    USE SIGNAL ;
    PORT
      LAYER M4 ;
        RECT  97.116 34.128 97.2 34.152 ;
    END
  END sink_data[194]
  PIN sink_data[195]
    DIRECTION OUTPUT ;
    USE SIGNAL ;
    PORT
      LAYER M4 ;
        RECT  97.116 34.224 97.2 34.248 ;
    END
  END sink_data[195]
  PIN sink_data[196]
    DIRECTION OUTPUT ;
    USE SIGNAL ;
    PORT
      LAYER M4 ;
        RECT  97.116 34.32 97.2 34.344 ;
    END
  END sink_data[196]
  PIN sink_data[197]
    DIRECTION OUTPUT ;
    USE SIGNAL ;
    PORT
      LAYER M4 ;
        RECT  97.116 34.416 97.2 34.44 ;
    END
  END sink_data[197]
  PIN sink_data[198]
    DIRECTION OUTPUT ;
    USE SIGNAL ;
    PORT
      LAYER M4 ;
        RECT  97.116 34.512 97.2 34.536 ;
    END
  END sink_data[198]
  PIN sink_data[199]
    DIRECTION OUTPUT ;
    USE SIGNAL ;
    PORT
      LAYER M4 ;
        RECT  97.116 34.608 97.2 34.632 ;
    END
  END sink_data[199]
  PIN sink_data[19]
    DIRECTION OUTPUT ;
    USE SIGNAL ;
    PORT
      LAYER M4 ;
        RECT  97.116 4.272 97.2 4.296 ;
    END
  END sink_data[19]
  PIN sink_data[1]
    DIRECTION OUTPUT ;
    USE SIGNAL ;
    PORT
      LAYER M4 ;
        RECT  97.116 37.104 97.2 37.128 ;
    END
  END sink_data[1]
  PIN sink_data[200]
    DIRECTION OUTPUT ;
    USE SIGNAL ;
    PORT
      LAYER M4 ;
        RECT  97.116 34.704 97.2 34.728 ;
    END
  END sink_data[200]
  PIN sink_data[201]
    DIRECTION OUTPUT ;
    USE SIGNAL ;
    PORT
      LAYER M4 ;
        RECT  97.116 34.8 97.2 34.824 ;
    END
  END sink_data[201]
  PIN sink_data[202]
    DIRECTION OUTPUT ;
    USE SIGNAL ;
    PORT
      LAYER M4 ;
        RECT  97.116 34.896 97.2 34.92 ;
    END
  END sink_data[202]
  PIN sink_data[203]
    DIRECTION OUTPUT ;
    USE SIGNAL ;
    PORT
      LAYER M4 ;
        RECT  97.116 34.992 97.2 35.016 ;
    END
  END sink_data[203]
  PIN sink_data[204]
    DIRECTION OUTPUT ;
    USE SIGNAL ;
    PORT
      LAYER M4 ;
        RECT  97.116 35.088 97.2 35.112 ;
    END
  END sink_data[204]
  PIN sink_data[205]
    DIRECTION OUTPUT ;
    USE SIGNAL ;
    PORT
      LAYER M4 ;
        RECT  97.116 35.184 97.2 35.208 ;
    END
  END sink_data[205]
  PIN sink_data[206]
    DIRECTION OUTPUT ;
    USE SIGNAL ;
    PORT
      LAYER M4 ;
        RECT  97.116 16.08 97.2 16.104 ;
    END
  END sink_data[206]
  PIN sink_data[207]
    DIRECTION OUTPUT ;
    USE SIGNAL ;
    PORT
      LAYER M4 ;
        RECT  97.116 16.176 97.2 16.2 ;
    END
  END sink_data[207]
  PIN sink_data[208]
    DIRECTION OUTPUT ;
    USE SIGNAL ;
    PORT
      LAYER M4 ;
        RECT  97.116 16.272 97.2 16.296 ;
    END
  END sink_data[208]
  PIN sink_data[209]
    DIRECTION OUTPUT ;
    USE SIGNAL ;
    PORT
      LAYER M4 ;
        RECT  97.116 16.368 97.2 16.392 ;
    END
  END sink_data[209]
  PIN sink_data[20]
    DIRECTION OUTPUT ;
    USE SIGNAL ;
    PORT
      LAYER M4 ;
        RECT  97.116 4.368 97.2 4.392 ;
    END
  END sink_data[20]
  PIN sink_data[210]
    DIRECTION OUTPUT ;
    USE SIGNAL ;
    PORT
      LAYER M4 ;
        RECT  97.116 16.464 97.2 16.488 ;
    END
  END sink_data[210]
  PIN sink_data[211]
    DIRECTION OUTPUT ;
    USE SIGNAL ;
    PORT
      LAYER M4 ;
        RECT  97.116 16.56 97.2 16.584 ;
    END
  END sink_data[211]
  PIN sink_data[212]
    DIRECTION OUTPUT ;
    USE SIGNAL ;
    PORT
      LAYER M4 ;
        RECT  97.116 16.656 97.2 16.68 ;
    END
  END sink_data[212]
  PIN sink_data[213]
    DIRECTION OUTPUT ;
    USE SIGNAL ;
    PORT
      LAYER M4 ;
        RECT  97.116 16.752 97.2 16.776 ;
    END
  END sink_data[213]
  PIN sink_data[214]
    DIRECTION OUTPUT ;
    USE SIGNAL ;
    PORT
      LAYER M4 ;
        RECT  97.116 16.848 97.2 16.872 ;
    END
  END sink_data[214]
  PIN sink_data[215]
    DIRECTION OUTPUT ;
    USE SIGNAL ;
    PORT
      LAYER M4 ;
        RECT  97.116 16.944 97.2 16.968 ;
    END
  END sink_data[215]
  PIN sink_data[216]
    DIRECTION OUTPUT ;
    USE SIGNAL ;
    PORT
      LAYER M4 ;
        RECT  97.116 17.04 97.2 17.064 ;
    END
  END sink_data[216]
  PIN sink_data[217]
    DIRECTION OUTPUT ;
    USE SIGNAL ;
    PORT
      LAYER M4 ;
        RECT  97.116 17.136 97.2 17.16 ;
    END
  END sink_data[217]
  PIN sink_data[218]
    DIRECTION OUTPUT ;
    USE SIGNAL ;
    PORT
      LAYER M4 ;
        RECT  97.116 17.232 97.2 17.256 ;
    END
  END sink_data[218]
  PIN sink_data[219]
    DIRECTION OUTPUT ;
    USE SIGNAL ;
    PORT
      LAYER M4 ;
        RECT  97.116 17.328 97.2 17.352 ;
    END
  END sink_data[219]
  PIN sink_data[21]
    DIRECTION OUTPUT ;
    USE SIGNAL ;
    PORT
      LAYER M4 ;
        RECT  97.116 4.464 97.2 4.488 ;
    END
  END sink_data[21]
  PIN sink_data[220]
    DIRECTION OUTPUT ;
    USE SIGNAL ;
    PORT
      LAYER M4 ;
        RECT  97.116 17.424 97.2 17.448 ;
    END
  END sink_data[220]
  PIN sink_data[221]
    DIRECTION OUTPUT ;
    USE SIGNAL ;
    PORT
      LAYER M4 ;
        RECT  97.116 17.52 97.2 17.544 ;
    END
  END sink_data[221]
  PIN sink_data[222]
    DIRECTION OUTPUT ;
    USE SIGNAL ;
    PORT
      LAYER M4 ;
        RECT  97.116 17.616 97.2 17.64 ;
    END
  END sink_data[222]
  PIN sink_data[223]
    DIRECTION OUTPUT ;
    USE SIGNAL ;
    PORT
      LAYER M4 ;
        RECT  97.116 17.712 97.2 17.736 ;
    END
  END sink_data[223]
  PIN sink_data[224]
    DIRECTION OUTPUT ;
    USE SIGNAL ;
    PORT
      LAYER M4 ;
        RECT  97.116 17.808 97.2 17.832 ;
    END
  END sink_data[224]
  PIN sink_data[225]
    DIRECTION OUTPUT ;
    USE SIGNAL ;
    PORT
      LAYER M4 ;
        RECT  97.116 17.904 97.2 17.928 ;
    END
  END sink_data[225]
  PIN sink_data[226]
    DIRECTION OUTPUT ;
    USE SIGNAL ;
    PORT
      LAYER M4 ;
        RECT  97.116 18 97.2 18.024 ;
    END
  END sink_data[226]
  PIN sink_data[227]
    DIRECTION OUTPUT ;
    USE SIGNAL ;
    PORT
      LAYER M4 ;
        RECT  97.116 18.096 97.2 18.12 ;
    END
  END sink_data[227]
  PIN sink_data[228]
    DIRECTION OUTPUT ;
    USE SIGNAL ;
    PORT
      LAYER M4 ;
        RECT  97.116 18.192 97.2 18.216 ;
    END
  END sink_data[228]
  PIN sink_data[229]
    DIRECTION OUTPUT ;
    USE SIGNAL ;
    PORT
      LAYER M4 ;
        RECT  97.116 18.288 97.2 18.312 ;
    END
  END sink_data[229]
  PIN sink_data[22]
    DIRECTION OUTPUT ;
    USE SIGNAL ;
    PORT
      LAYER M4 ;
        RECT  97.116 4.56 97.2 4.584 ;
    END
  END sink_data[22]
  PIN sink_data[230]
    DIRECTION OUTPUT ;
    USE SIGNAL ;
    PORT
      LAYER M4 ;
        RECT  97.116 18.384 97.2 18.408 ;
    END
  END sink_data[230]
  PIN sink_data[231]
    DIRECTION OUTPUT ;
    USE SIGNAL ;
    PORT
      LAYER M4 ;
        RECT  97.116 18.48 97.2 18.504 ;
    END
  END sink_data[231]
  PIN sink_data[232]
    DIRECTION OUTPUT ;
    USE SIGNAL ;
    PORT
      LAYER M4 ;
        RECT  97.116 18.576 97.2 18.6 ;
    END
  END sink_data[232]
  PIN sink_data[233]
    DIRECTION OUTPUT ;
    USE SIGNAL ;
    PORT
      LAYER M4 ;
        RECT  97.116 18.672 97.2 18.696 ;
    END
  END sink_data[233]
  PIN sink_data[234]
    DIRECTION OUTPUT ;
    USE SIGNAL ;
    PORT
      LAYER M4 ;
        RECT  97.116 18.768 97.2 18.792 ;
    END
  END sink_data[234]
  PIN sink_data[235]
    DIRECTION OUTPUT ;
    USE SIGNAL ;
    PORT
      LAYER M4 ;
        RECT  97.116 18.864 97.2 18.888 ;
    END
  END sink_data[235]
  PIN sink_data[236]
    DIRECTION OUTPUT ;
    USE SIGNAL ;
    PORT
      LAYER M4 ;
        RECT  97.116 18.96 97.2 18.984 ;
    END
  END sink_data[236]
  PIN sink_data[237]
    DIRECTION OUTPUT ;
    USE SIGNAL ;
    PORT
      LAYER M4 ;
        RECT  97.116 19.056 97.2 19.08 ;
    END
  END sink_data[237]
  PIN sink_data[238]
    DIRECTION OUTPUT ;
    USE SIGNAL ;
    PORT
      LAYER M4 ;
        RECT  97.116 29.136 97.2 29.16 ;
    END
  END sink_data[238]
  PIN sink_data[239]
    DIRECTION OUTPUT ;
    USE SIGNAL ;
    PORT
      LAYER M4 ;
        RECT  97.116 29.232 97.2 29.256 ;
    END
  END sink_data[239]
  PIN sink_data[23]
    DIRECTION OUTPUT ;
    USE SIGNAL ;
    PORT
      LAYER M4 ;
        RECT  97.116 4.656 97.2 4.68 ;
    END
  END sink_data[23]
  PIN sink_data[240]
    DIRECTION OUTPUT ;
    USE SIGNAL ;
    PORT
      LAYER M4 ;
        RECT  97.116 29.328 97.2 29.352 ;
    END
  END sink_data[240]
  PIN sink_data[241]
    DIRECTION OUTPUT ;
    USE SIGNAL ;
    PORT
      LAYER M4 ;
        RECT  97.116 29.424 97.2 29.448 ;
    END
  END sink_data[241]
  PIN sink_data[242]
    DIRECTION OUTPUT ;
    USE SIGNAL ;
    PORT
      LAYER M4 ;
        RECT  97.116 29.52 97.2 29.544 ;
    END
  END sink_data[242]
  PIN sink_data[243]
    DIRECTION OUTPUT ;
    USE SIGNAL ;
    PORT
      LAYER M4 ;
        RECT  97.116 29.616 97.2 29.64 ;
    END
  END sink_data[243]
  PIN sink_data[244]
    DIRECTION OUTPUT ;
    USE SIGNAL ;
    PORT
      LAYER M4 ;
        RECT  97.116 29.712 97.2 29.736 ;
    END
  END sink_data[244]
  PIN sink_data[245]
    DIRECTION OUTPUT ;
    USE SIGNAL ;
    PORT
      LAYER M4 ;
        RECT  97.116 29.808 97.2 29.832 ;
    END
  END sink_data[245]
  PIN sink_data[246]
    DIRECTION OUTPUT ;
    USE SIGNAL ;
    PORT
      LAYER M4 ;
        RECT  97.116 29.904 97.2 29.928 ;
    END
  END sink_data[246]
  PIN sink_data[247]
    DIRECTION OUTPUT ;
    USE SIGNAL ;
    PORT
      LAYER M4 ;
        RECT  97.116 30 97.2 30.024 ;
    END
  END sink_data[247]
  PIN sink_data[248]
    DIRECTION OUTPUT ;
    USE SIGNAL ;
    PORT
      LAYER M4 ;
        RECT  97.116 30.096 97.2 30.12 ;
    END
  END sink_data[248]
  PIN sink_data[249]
    DIRECTION OUTPUT ;
    USE SIGNAL ;
    PORT
      LAYER M4 ;
        RECT  97.116 30.192 97.2 30.216 ;
    END
  END sink_data[249]
  PIN sink_data[24]
    DIRECTION OUTPUT ;
    USE SIGNAL ;
    PORT
      LAYER M4 ;
        RECT  97.116 4.752 97.2 4.776 ;
    END
  END sink_data[24]
  PIN sink_data[250]
    DIRECTION OUTPUT ;
    USE SIGNAL ;
    PORT
      LAYER M4 ;
        RECT  97.116 30.288 97.2 30.312 ;
    END
  END sink_data[250]
  PIN sink_data[251]
    DIRECTION OUTPUT ;
    USE SIGNAL ;
    PORT
      LAYER M4 ;
        RECT  97.116 30.384 97.2 30.408 ;
    END
  END sink_data[251]
  PIN sink_data[252]
    DIRECTION OUTPUT ;
    USE SIGNAL ;
    PORT
      LAYER M4 ;
        RECT  97.116 30.48 97.2 30.504 ;
    END
  END sink_data[252]
  PIN sink_data[253]
    DIRECTION OUTPUT ;
    USE SIGNAL ;
    PORT
      LAYER M4 ;
        RECT  97.116 30.576 97.2 30.6 ;
    END
  END sink_data[253]
  PIN sink_data[254]
    DIRECTION OUTPUT ;
    USE SIGNAL ;
    PORT
      LAYER M4 ;
        RECT  97.116 30.672 97.2 30.696 ;
    END
  END sink_data[254]
  PIN sink_data[255]
    DIRECTION OUTPUT ;
    USE SIGNAL ;
    PORT
      LAYER M4 ;
        RECT  97.116 30.768 97.2 30.792 ;
    END
  END sink_data[255]
  PIN sink_data[256]
    DIRECTION OUTPUT ;
    USE SIGNAL ;
    PORT
      LAYER M4 ;
        RECT  97.116 30.864 97.2 30.888 ;
    END
  END sink_data[256]
  PIN sink_data[257]
    DIRECTION OUTPUT ;
    USE SIGNAL ;
    PORT
      LAYER M4 ;
        RECT  97.116 30.96 97.2 30.984 ;
    END
  END sink_data[257]
  PIN sink_data[258]
    DIRECTION OUTPUT ;
    USE SIGNAL ;
    PORT
      LAYER M4 ;
        RECT  97.116 31.056 97.2 31.08 ;
    END
  END sink_data[258]
  PIN sink_data[259]
    DIRECTION OUTPUT ;
    USE SIGNAL ;
    PORT
      LAYER M4 ;
        RECT  97.116 31.152 97.2 31.176 ;
    END
  END sink_data[259]
  PIN sink_data[25]
    DIRECTION OUTPUT ;
    USE SIGNAL ;
    PORT
      LAYER M4 ;
        RECT  97.116 4.848 97.2 4.872 ;
    END
  END sink_data[25]
  PIN sink_data[260]
    DIRECTION OUTPUT ;
    USE SIGNAL ;
    PORT
      LAYER M4 ;
        RECT  97.116 31.248 97.2 31.272 ;
    END
  END sink_data[260]
  PIN sink_data[261]
    DIRECTION OUTPUT ;
    USE SIGNAL ;
    PORT
      LAYER M4 ;
        RECT  97.116 31.344 97.2 31.368 ;
    END
  END sink_data[261]
  PIN sink_data[262]
    DIRECTION OUTPUT ;
    USE SIGNAL ;
    PORT
      LAYER M4 ;
        RECT  97.116 31.44 97.2 31.464 ;
    END
  END sink_data[262]
  PIN sink_data[263]
    DIRECTION OUTPUT ;
    USE SIGNAL ;
    PORT
      LAYER M4 ;
        RECT  97.116 31.536 97.2 31.56 ;
    END
  END sink_data[263]
  PIN sink_data[264]
    DIRECTION OUTPUT ;
    USE SIGNAL ;
    PORT
      LAYER M4 ;
        RECT  97.116 31.632 97.2 31.656 ;
    END
  END sink_data[264]
  PIN sink_data[265]
    DIRECTION OUTPUT ;
    USE SIGNAL ;
    PORT
      LAYER M4 ;
        RECT  97.116 31.728 97.2 31.752 ;
    END
  END sink_data[265]
  PIN sink_data[266]
    DIRECTION OUTPUT ;
    USE SIGNAL ;
    PORT
      LAYER M4 ;
        RECT  97.116 31.824 97.2 31.848 ;
    END
  END sink_data[266]
  PIN sink_data[267]
    DIRECTION OUTPUT ;
    USE SIGNAL ;
    PORT
      LAYER M4 ;
        RECT  97.116 31.92 97.2 31.944 ;
    END
  END sink_data[267]
  PIN sink_data[268]
    DIRECTION OUTPUT ;
    USE SIGNAL ;
    PORT
      LAYER M4 ;
        RECT  97.116 32.016 97.2 32.04 ;
    END
  END sink_data[268]
  PIN sink_data[269]
    DIRECTION OUTPUT ;
    USE SIGNAL ;
    PORT
      LAYER M4 ;
        RECT  97.116 32.112 97.2 32.136 ;
    END
  END sink_data[269]
  PIN sink_data[26]
    DIRECTION OUTPUT ;
    USE SIGNAL ;
    PORT
      LAYER M4 ;
        RECT  97.116 4.944 97.2 4.968 ;
    END
  END sink_data[26]
  PIN sink_data[270]
    DIRECTION OUTPUT ;
    USE SIGNAL ;
    PORT
      LAYER M4 ;
        RECT  97.116 92.88 97.2 92.904 ;
    END
  END sink_data[270]
  PIN sink_data[271]
    DIRECTION OUTPUT ;
    USE SIGNAL ;
    PORT
      LAYER M4 ;
        RECT  97.116 92.976 97.2 93 ;
    END
  END sink_data[271]
  PIN sink_data[272]
    DIRECTION OUTPUT ;
    USE SIGNAL ;
    PORT
      LAYER M4 ;
        RECT  97.116 93.072 97.2 93.096 ;
    END
  END sink_data[272]
  PIN sink_data[273]
    DIRECTION OUTPUT ;
    USE SIGNAL ;
    PORT
      LAYER M4 ;
        RECT  97.116 93.168 97.2 93.192 ;
    END
  END sink_data[273]
  PIN sink_data[274]
    DIRECTION OUTPUT ;
    USE SIGNAL ;
    PORT
      LAYER M4 ;
        RECT  97.116 93.264 97.2 93.288 ;
    END
  END sink_data[274]
  PIN sink_data[275]
    DIRECTION OUTPUT ;
    USE SIGNAL ;
    PORT
      LAYER M4 ;
        RECT  97.116 93.36 97.2 93.384 ;
    END
  END sink_data[275]
  PIN sink_data[276]
    DIRECTION OUTPUT ;
    USE SIGNAL ;
    PORT
      LAYER M4 ;
        RECT  97.116 93.456 97.2 93.48 ;
    END
  END sink_data[276]
  PIN sink_data[277]
    DIRECTION OUTPUT ;
    USE SIGNAL ;
    PORT
      LAYER M4 ;
        RECT  97.116 93.552 97.2 93.576 ;
    END
  END sink_data[277]
  PIN sink_data[278]
    DIRECTION OUTPUT ;
    USE SIGNAL ;
    PORT
      LAYER M4 ;
        RECT  97.116 93.648 97.2 93.672 ;
    END
  END sink_data[278]
  PIN sink_data[279]
    DIRECTION OUTPUT ;
    USE SIGNAL ;
    PORT
      LAYER M4 ;
        RECT  97.116 93.744 97.2 93.768 ;
    END
  END sink_data[279]
  PIN sink_data[27]
    DIRECTION OUTPUT ;
    USE SIGNAL ;
    PORT
      LAYER M4 ;
        RECT  97.116 5.04 97.2 5.064 ;
    END
  END sink_data[27]
  PIN sink_data[280]
    DIRECTION OUTPUT ;
    USE SIGNAL ;
    PORT
      LAYER M4 ;
        RECT  97.116 93.84 97.2 93.864 ;
    END
  END sink_data[280]
  PIN sink_data[281]
    DIRECTION OUTPUT ;
    USE SIGNAL ;
    PORT
      LAYER M4 ;
        RECT  97.116 93.936 97.2 93.96 ;
    END
  END sink_data[281]
  PIN sink_data[282]
    DIRECTION OUTPUT ;
    USE SIGNAL ;
    PORT
      LAYER M4 ;
        RECT  97.116 94.032 97.2 94.056 ;
    END
  END sink_data[282]
  PIN sink_data[283]
    DIRECTION OUTPUT ;
    USE SIGNAL ;
    PORT
      LAYER M4 ;
        RECT  97.116 94.128 97.2 94.152 ;
    END
  END sink_data[283]
  PIN sink_data[284]
    DIRECTION OUTPUT ;
    USE SIGNAL ;
    PORT
      LAYER M4 ;
        RECT  97.116 94.224 97.2 94.248 ;
    END
  END sink_data[284]
  PIN sink_data[285]
    DIRECTION OUTPUT ;
    USE SIGNAL ;
    PORT
      LAYER M4 ;
        RECT  97.116 94.32 97.2 94.344 ;
    END
  END sink_data[285]
  PIN sink_data[286]
    DIRECTION OUTPUT ;
    USE SIGNAL ;
    PORT
      LAYER M4 ;
        RECT  97.116 94.416 97.2 94.44 ;
    END
  END sink_data[286]
  PIN sink_data[287]
    DIRECTION OUTPUT ;
    USE SIGNAL ;
    PORT
      LAYER M4 ;
        RECT  97.116 94.512 97.2 94.536 ;
    END
  END sink_data[287]
  PIN sink_data[288]
    DIRECTION OUTPUT ;
    USE SIGNAL ;
    PORT
      LAYER M4 ;
        RECT  97.116 94.608 97.2 94.632 ;
    END
  END sink_data[288]
  PIN sink_data[289]
    DIRECTION OUTPUT ;
    USE SIGNAL ;
    PORT
      LAYER M4 ;
        RECT  97.116 94.704 97.2 94.728 ;
    END
  END sink_data[289]
  PIN sink_data[28]
    DIRECTION OUTPUT ;
    USE SIGNAL ;
    PORT
      LAYER M4 ;
        RECT  97.116 5.136 97.2 5.16 ;
    END
  END sink_data[28]
  PIN sink_data[290]
    DIRECTION OUTPUT ;
    USE SIGNAL ;
    PORT
      LAYER M4 ;
        RECT  97.116 94.8 97.2 94.824 ;
    END
  END sink_data[290]
  PIN sink_data[291]
    DIRECTION OUTPUT ;
    USE SIGNAL ;
    PORT
      LAYER M4 ;
        RECT  97.116 94.896 97.2 94.92 ;
    END
  END sink_data[291]
  PIN sink_data[292]
    DIRECTION OUTPUT ;
    USE SIGNAL ;
    PORT
      LAYER M4 ;
        RECT  97.116 94.992 97.2 95.016 ;
    END
  END sink_data[292]
  PIN sink_data[293]
    DIRECTION OUTPUT ;
    USE SIGNAL ;
    PORT
      LAYER M4 ;
        RECT  97.116 95.088 97.2 95.112 ;
    END
  END sink_data[293]
  PIN sink_data[294]
    DIRECTION OUTPUT ;
    USE SIGNAL ;
    PORT
      LAYER M4 ;
        RECT  97.116 95.184 97.2 95.208 ;
    END
  END sink_data[294]
  PIN sink_data[295]
    DIRECTION OUTPUT ;
    USE SIGNAL ;
    PORT
      LAYER M4 ;
        RECT  97.116 95.28 97.2 95.304 ;
    END
  END sink_data[295]
  PIN sink_data[296]
    DIRECTION OUTPUT ;
    USE SIGNAL ;
    PORT
      LAYER M4 ;
        RECT  97.116 95.376 97.2 95.4 ;
    END
  END sink_data[296]
  PIN sink_data[297]
    DIRECTION OUTPUT ;
    USE SIGNAL ;
    PORT
      LAYER M4 ;
        RECT  97.116 95.472 97.2 95.496 ;
    END
  END sink_data[297]
  PIN sink_data[298]
    DIRECTION OUTPUT ;
    USE SIGNAL ;
    PORT
      LAYER M4 ;
        RECT  97.116 95.568 97.2 95.592 ;
    END
  END sink_data[298]
  PIN sink_data[299]
    DIRECTION OUTPUT ;
    USE SIGNAL ;
    PORT
      LAYER M4 ;
        RECT  97.116 95.664 97.2 95.688 ;
    END
  END sink_data[299]
  PIN sink_data[29]
    DIRECTION OUTPUT ;
    USE SIGNAL ;
    PORT
      LAYER M4 ;
        RECT  97.116 5.232 97.2 5.256 ;
    END
  END sink_data[29]
  PIN sink_data[2]
    DIRECTION OUTPUT ;
    USE SIGNAL ;
    PORT
      LAYER M4 ;
        RECT  97.116 37.2 97.2 37.224 ;
    END
  END sink_data[2]
  PIN sink_data[300]
    DIRECTION OUTPUT ;
    USE SIGNAL ;
    PORT
      LAYER M4 ;
        RECT  97.116 95.76 97.2 95.784 ;
    END
  END sink_data[300]
  PIN sink_data[301]
    DIRECTION OUTPUT ;
    USE SIGNAL ;
    PORT
      LAYER M4 ;
        RECT  97.116 95.856 97.2 95.88 ;
    END
  END sink_data[301]
  PIN sink_data[302]
    DIRECTION OUTPUT ;
    USE SIGNAL ;
    PORT
      LAYER M4 ;
        RECT  97.116 83.664 97.2 83.688 ;
    END
  END sink_data[302]
  PIN sink_data[303]
    DIRECTION OUTPUT ;
    USE SIGNAL ;
    PORT
      LAYER M4 ;
        RECT  97.116 83.76 97.2 83.784 ;
    END
  END sink_data[303]
  PIN sink_data[304]
    DIRECTION OUTPUT ;
    USE SIGNAL ;
    PORT
      LAYER M4 ;
        RECT  97.116 83.856 97.2 83.88 ;
    END
  END sink_data[304]
  PIN sink_data[305]
    DIRECTION OUTPUT ;
    USE SIGNAL ;
    PORT
      LAYER M4 ;
        RECT  97.116 83.952 97.2 83.976 ;
    END
  END sink_data[305]
  PIN sink_data[306]
    DIRECTION OUTPUT ;
    USE SIGNAL ;
    PORT
      LAYER M4 ;
        RECT  97.116 84.048 97.2 84.072 ;
    END
  END sink_data[306]
  PIN sink_data[307]
    DIRECTION OUTPUT ;
    USE SIGNAL ;
    PORT
      LAYER M4 ;
        RECT  97.116 84.144 97.2 84.168 ;
    END
  END sink_data[307]
  PIN sink_data[308]
    DIRECTION OUTPUT ;
    USE SIGNAL ;
    PORT
      LAYER M4 ;
        RECT  97.116 84.24 97.2 84.264 ;
    END
  END sink_data[308]
  PIN sink_data[309]
    DIRECTION OUTPUT ;
    USE SIGNAL ;
    PORT
      LAYER M4 ;
        RECT  97.116 84.336 97.2 84.36 ;
    END
  END sink_data[309]
  PIN sink_data[30]
    DIRECTION OUTPUT ;
    USE SIGNAL ;
    PORT
      LAYER M4 ;
        RECT  97.116 5.328 97.2 5.352 ;
    END
  END sink_data[30]
  PIN sink_data[310]
    DIRECTION OUTPUT ;
    USE SIGNAL ;
    PORT
      LAYER M4 ;
        RECT  97.116 84.432 97.2 84.456 ;
    END
  END sink_data[310]
  PIN sink_data[311]
    DIRECTION OUTPUT ;
    USE SIGNAL ;
    PORT
      LAYER M4 ;
        RECT  97.116 84.528 97.2 84.552 ;
    END
  END sink_data[311]
  PIN sink_data[312]
    DIRECTION OUTPUT ;
    USE SIGNAL ;
    PORT
      LAYER M4 ;
        RECT  97.116 84.624 97.2 84.648 ;
    END
  END sink_data[312]
  PIN sink_data[313]
    DIRECTION OUTPUT ;
    USE SIGNAL ;
    PORT
      LAYER M4 ;
        RECT  97.116 84.72 97.2 84.744 ;
    END
  END sink_data[313]
  PIN sink_data[314]
    DIRECTION OUTPUT ;
    USE SIGNAL ;
    PORT
      LAYER M4 ;
        RECT  97.116 84.816 97.2 84.84 ;
    END
  END sink_data[314]
  PIN sink_data[315]
    DIRECTION OUTPUT ;
    USE SIGNAL ;
    PORT
      LAYER M4 ;
        RECT  97.116 84.912 97.2 84.936 ;
    END
  END sink_data[315]
  PIN sink_data[316]
    DIRECTION OUTPUT ;
    USE SIGNAL ;
    PORT
      LAYER M4 ;
        RECT  97.116 85.008 97.2 85.032 ;
    END
  END sink_data[316]
  PIN sink_data[317]
    DIRECTION OUTPUT ;
    USE SIGNAL ;
    PORT
      LAYER M4 ;
        RECT  97.116 85.104 97.2 85.128 ;
    END
  END sink_data[317]
  PIN sink_data[318]
    DIRECTION OUTPUT ;
    USE SIGNAL ;
    PORT
      LAYER M4 ;
        RECT  97.116 85.2 97.2 85.224 ;
    END
  END sink_data[318]
  PIN sink_data[319]
    DIRECTION OUTPUT ;
    USE SIGNAL ;
    PORT
      LAYER M4 ;
        RECT  97.116 85.296 97.2 85.32 ;
    END
  END sink_data[319]
  PIN sink_data[31]
    DIRECTION OUTPUT ;
    USE SIGNAL ;
    PORT
      LAYER M4 ;
        RECT  97.116 5.424 97.2 5.448 ;
    END
  END sink_data[31]
  PIN sink_data[32]
    DIRECTION OUTPUT ;
    USE SIGNAL ;
    PORT
      LAYER M4 ;
        RECT  97.116 5.52 97.2 5.544 ;
    END
  END sink_data[32]
  PIN sink_data[33]
    DIRECTION OUTPUT ;
    USE SIGNAL ;
    PORT
      LAYER M4 ;
        RECT  97.116 5.616 97.2 5.64 ;
    END
  END sink_data[33]
  PIN sink_data[34]
    DIRECTION OUTPUT ;
    USE SIGNAL ;
    PORT
      LAYER M4 ;
        RECT  97.116 5.712 97.2 5.736 ;
    END
  END sink_data[34]
  PIN sink_data[35]
    DIRECTION OUTPUT ;
    USE SIGNAL ;
    PORT
      LAYER M4 ;
        RECT  97.116 5.808 97.2 5.832 ;
    END
  END sink_data[35]
  PIN sink_data[36]
    DIRECTION OUTPUT ;
    USE SIGNAL ;
    PORT
      LAYER M4 ;
        RECT  97.116 5.904 97.2 5.928 ;
    END
  END sink_data[36]
  PIN sink_data[37]
    DIRECTION OUTPUT ;
    USE SIGNAL ;
    PORT
      LAYER M4 ;
        RECT  97.116 6 97.2 6.024 ;
    END
  END sink_data[37]
  PIN sink_data[38]
    DIRECTION OUTPUT ;
    USE SIGNAL ;
    PORT
      LAYER M4 ;
        RECT  97.116 6.096 97.2 6.12 ;
    END
  END sink_data[38]
  PIN sink_data[39]
    DIRECTION OUTPUT ;
    USE SIGNAL ;
    PORT
      LAYER M4 ;
        RECT  97.116 6.192 97.2 6.216 ;
    END
  END sink_data[39]
  PIN sink_data[3]
    DIRECTION OUTPUT ;
    USE SIGNAL ;
    PORT
      LAYER M4 ;
        RECT  97.116 37.296 97.2 37.32 ;
    END
  END sink_data[3]
  PIN sink_data[40]
    DIRECTION OUTPUT ;
    USE SIGNAL ;
    PORT
      LAYER M4 ;
        RECT  97.116 6.288 97.2 6.312 ;
    END
  END sink_data[40]
  PIN sink_data[41]
    DIRECTION OUTPUT ;
    USE SIGNAL ;
    PORT
      LAYER M4 ;
        RECT  97.116 6.384 97.2 6.408 ;
    END
  END sink_data[41]
  PIN sink_data[42]
    DIRECTION OUTPUT ;
    USE SIGNAL ;
    PORT
      LAYER M4 ;
        RECT  97.116 6.48 97.2 6.504 ;
    END
  END sink_data[42]
  PIN sink_data[43]
    DIRECTION OUTPUT ;
    USE SIGNAL ;
    PORT
      LAYER M4 ;
        RECT  97.116 6.576 97.2 6.6 ;
    END
  END sink_data[43]
  PIN sink_data[44]
    DIRECTION OUTPUT ;
    USE SIGNAL ;
    PORT
      LAYER M4 ;
        RECT  97.116 6.672 97.2 6.696 ;
    END
  END sink_data[44]
  PIN sink_data[45]
    DIRECTION OUTPUT ;
    USE SIGNAL ;
    PORT
      LAYER M4 ;
        RECT  97.116 6.768 97.2 6.792 ;
    END
  END sink_data[45]
  PIN sink_data[46]
    DIRECTION OUTPUT ;
    USE SIGNAL ;
    PORT
      LAYER M4 ;
        RECT  97.116 52.848 97.2 52.872 ;
    END
  END sink_data[46]
  PIN sink_data[47]
    DIRECTION OUTPUT ;
    USE SIGNAL ;
    PORT
      LAYER M4 ;
        RECT  97.116 52.944 97.2 52.968 ;
    END
  END sink_data[47]
  PIN sink_data[48]
    DIRECTION OUTPUT ;
    USE SIGNAL ;
    PORT
      LAYER M4 ;
        RECT  97.116 53.04 97.2 53.064 ;
    END
  END sink_data[48]
  PIN sink_data[49]
    DIRECTION OUTPUT ;
    USE SIGNAL ;
    PORT
      LAYER M4 ;
        RECT  97.116 53.136 97.2 53.16 ;
    END
  END sink_data[49]
  PIN sink_data[4]
    DIRECTION OUTPUT ;
    USE SIGNAL ;
    PORT
      LAYER M4 ;
        RECT  97.116 37.392 97.2 37.416 ;
    END
  END sink_data[4]
  PIN sink_data[50]
    DIRECTION OUTPUT ;
    USE SIGNAL ;
    PORT
      LAYER M4 ;
        RECT  97.116 53.232 97.2 53.256 ;
    END
  END sink_data[50]
  PIN sink_data[51]
    DIRECTION OUTPUT ;
    USE SIGNAL ;
    PORT
      LAYER M4 ;
        RECT  97.116 53.328 97.2 53.352 ;
    END
  END sink_data[51]
  PIN sink_data[52]
    DIRECTION OUTPUT ;
    USE SIGNAL ;
    PORT
      LAYER M4 ;
        RECT  97.116 53.424 97.2 53.448 ;
    END
  END sink_data[52]
  PIN sink_data[53]
    DIRECTION OUTPUT ;
    USE SIGNAL ;
    PORT
      LAYER M4 ;
        RECT  97.116 53.52 97.2 53.544 ;
    END
  END sink_data[53]
  PIN sink_data[54]
    DIRECTION OUTPUT ;
    USE SIGNAL ;
    PORT
      LAYER M4 ;
        RECT  97.116 53.616 97.2 53.64 ;
    END
  END sink_data[54]
  PIN sink_data[55]
    DIRECTION OUTPUT ;
    USE SIGNAL ;
    PORT
      LAYER M4 ;
        RECT  97.116 53.712 97.2 53.736 ;
    END
  END sink_data[55]
  PIN sink_data[56]
    DIRECTION OUTPUT ;
    USE SIGNAL ;
    PORT
      LAYER M4 ;
        RECT  97.116 53.808 97.2 53.832 ;
    END
  END sink_data[56]
  PIN sink_data[57]
    DIRECTION OUTPUT ;
    USE SIGNAL ;
    PORT
      LAYER M4 ;
        RECT  97.116 53.904 97.2 53.928 ;
    END
  END sink_data[57]
  PIN sink_data[58]
    DIRECTION OUTPUT ;
    USE SIGNAL ;
    PORT
      LAYER M4 ;
        RECT  97.116 54 97.2 54.024 ;
    END
  END sink_data[58]
  PIN sink_data[59]
    DIRECTION OUTPUT ;
    USE SIGNAL ;
    PORT
      LAYER M4 ;
        RECT  97.116 54.096 97.2 54.12 ;
    END
  END sink_data[59]
  PIN sink_data[5]
    DIRECTION OUTPUT ;
    USE SIGNAL ;
    PORT
      LAYER M4 ;
        RECT  97.116 37.488 97.2 37.512 ;
    END
  END sink_data[5]
  PIN sink_data[60]
    DIRECTION OUTPUT ;
    USE SIGNAL ;
    PORT
      LAYER M4 ;
        RECT  97.116 54.192 97.2 54.216 ;
    END
  END sink_data[60]
  PIN sink_data[61]
    DIRECTION OUTPUT ;
    USE SIGNAL ;
    PORT
      LAYER M4 ;
        RECT  97.116 54.288 97.2 54.312 ;
    END
  END sink_data[61]
  PIN sink_data[62]
    DIRECTION OUTPUT ;
    USE SIGNAL ;
    PORT
      LAYER M4 ;
        RECT  97.116 54.384 97.2 54.408 ;
    END
  END sink_data[62]
  PIN sink_data[63]
    DIRECTION OUTPUT ;
    USE SIGNAL ;
    PORT
      LAYER M4 ;
        RECT  97.116 54.48 97.2 54.504 ;
    END
  END sink_data[63]
  PIN sink_data[64]
    DIRECTION OUTPUT ;
    USE SIGNAL ;
    PORT
      LAYER M4 ;
        RECT  97.116 54.576 97.2 54.6 ;
    END
  END sink_data[64]
  PIN sink_data[65]
    DIRECTION OUTPUT ;
    USE SIGNAL ;
    PORT
      LAYER M4 ;
        RECT  97.116 54.672 97.2 54.696 ;
    END
  END sink_data[65]
  PIN sink_data[66]
    DIRECTION OUTPUT ;
    USE SIGNAL ;
    PORT
      LAYER M4 ;
        RECT  97.116 54.768 97.2 54.792 ;
    END
  END sink_data[66]
  PIN sink_data[67]
    DIRECTION OUTPUT ;
    USE SIGNAL ;
    PORT
      LAYER M4 ;
        RECT  97.116 54.864 97.2 54.888 ;
    END
  END sink_data[67]
  PIN sink_data[68]
    DIRECTION OUTPUT ;
    USE SIGNAL ;
    PORT
      LAYER M4 ;
        RECT  97.116 54.96 97.2 54.984 ;
    END
  END sink_data[68]
  PIN sink_data[69]
    DIRECTION OUTPUT ;
    USE SIGNAL ;
    PORT
      LAYER M4 ;
        RECT  97.116 55.056 97.2 55.08 ;
    END
  END sink_data[69]
  PIN sink_data[6]
    DIRECTION OUTPUT ;
    USE SIGNAL ;
    PORT
      LAYER M4 ;
        RECT  97.116 37.584 97.2 37.608 ;
    END
  END sink_data[6]
  PIN sink_data[70]
    DIRECTION OUTPUT ;
    USE SIGNAL ;
    PORT
      LAYER M4 ;
        RECT  97.116 55.152 97.2 55.176 ;
    END
  END sink_data[70]
  PIN sink_data[71]
    DIRECTION OUTPUT ;
    USE SIGNAL ;
    PORT
      LAYER M4 ;
        RECT  97.116 55.248 97.2 55.272 ;
    END
  END sink_data[71]
  PIN sink_data[72]
    DIRECTION OUTPUT ;
    USE SIGNAL ;
    PORT
      LAYER M4 ;
        RECT  97.116 55.344 97.2 55.368 ;
    END
  END sink_data[72]
  PIN sink_data[73]
    DIRECTION OUTPUT ;
    USE SIGNAL ;
    PORT
      LAYER M4 ;
        RECT  97.116 55.44 97.2 55.464 ;
    END
  END sink_data[73]
  PIN sink_data[74]
    DIRECTION OUTPUT ;
    USE SIGNAL ;
    PORT
      LAYER M4 ;
        RECT  97.116 55.536 97.2 55.56 ;
    END
  END sink_data[74]
  PIN sink_data[75]
    DIRECTION OUTPUT ;
    USE SIGNAL ;
    PORT
      LAYER M4 ;
        RECT  97.116 55.632 97.2 55.656 ;
    END
  END sink_data[75]
  PIN sink_data[76]
    DIRECTION OUTPUT ;
    USE SIGNAL ;
    PORT
      LAYER M4 ;
        RECT  97.116 55.728 97.2 55.752 ;
    END
  END sink_data[76]
  PIN sink_data[77]
    DIRECTION OUTPUT ;
    USE SIGNAL ;
    PORT
      LAYER M4 ;
        RECT  97.116 55.824 97.2 55.848 ;
    END
  END sink_data[77]
  PIN sink_data[78]
    DIRECTION OUTPUT ;
    USE SIGNAL ;
    PORT
      LAYER M4 ;
        RECT  97.116 77.52 97.2 77.544 ;
    END
  END sink_data[78]
  PIN sink_data[79]
    DIRECTION OUTPUT ;
    USE SIGNAL ;
    PORT
      LAYER M4 ;
        RECT  97.116 77.616 97.2 77.64 ;
    END
  END sink_data[79]
  PIN sink_data[7]
    DIRECTION OUTPUT ;
    USE SIGNAL ;
    PORT
      LAYER M4 ;
        RECT  97.116 37.68 97.2 37.704 ;
    END
  END sink_data[7]
  PIN sink_data[80]
    DIRECTION OUTPUT ;
    USE SIGNAL ;
    PORT
      LAYER M4 ;
        RECT  97.116 77.712 97.2 77.736 ;
    END
  END sink_data[80]
  PIN sink_data[81]
    DIRECTION OUTPUT ;
    USE SIGNAL ;
    PORT
      LAYER M4 ;
        RECT  97.116 77.808 97.2 77.832 ;
    END
  END sink_data[81]
  PIN sink_data[82]
    DIRECTION OUTPUT ;
    USE SIGNAL ;
    PORT
      LAYER M4 ;
        RECT  97.116 77.904 97.2 77.928 ;
    END
  END sink_data[82]
  PIN sink_data[83]
    DIRECTION OUTPUT ;
    USE SIGNAL ;
    PORT
      LAYER M4 ;
        RECT  97.116 78 97.2 78.024 ;
    END
  END sink_data[83]
  PIN sink_data[84]
    DIRECTION OUTPUT ;
    USE SIGNAL ;
    PORT
      LAYER M4 ;
        RECT  97.116 78.096 97.2 78.12 ;
    END
  END sink_data[84]
  PIN sink_data[85]
    DIRECTION OUTPUT ;
    USE SIGNAL ;
    PORT
      LAYER M4 ;
        RECT  97.116 78.192 97.2 78.216 ;
    END
  END sink_data[85]
  PIN sink_data[86]
    DIRECTION OUTPUT ;
    USE SIGNAL ;
    PORT
      LAYER M4 ;
        RECT  97.116 78.288 97.2 78.312 ;
    END
  END sink_data[86]
  PIN sink_data[87]
    DIRECTION OUTPUT ;
    USE SIGNAL ;
    PORT
      LAYER M4 ;
        RECT  97.116 78.384 97.2 78.408 ;
    END
  END sink_data[87]
  PIN sink_data[88]
    DIRECTION OUTPUT ;
    USE SIGNAL ;
    PORT
      LAYER M4 ;
        RECT  97.116 78.48 97.2 78.504 ;
    END
  END sink_data[88]
  PIN sink_data[89]
    DIRECTION OUTPUT ;
    USE SIGNAL ;
    PORT
      LAYER M4 ;
        RECT  97.116 78.576 97.2 78.6 ;
    END
  END sink_data[89]
  PIN sink_data[8]
    DIRECTION OUTPUT ;
    USE SIGNAL ;
    PORT
      LAYER M4 ;
        RECT  97.116 37.776 97.2 37.8 ;
    END
  END sink_data[8]
  PIN sink_data[90]
    DIRECTION OUTPUT ;
    USE SIGNAL ;
    PORT
      LAYER M4 ;
        RECT  97.116 78.672 97.2 78.696 ;
    END
  END sink_data[90]
  PIN sink_data[91]
    DIRECTION OUTPUT ;
    USE SIGNAL ;
    PORT
      LAYER M4 ;
        RECT  97.116 78.768 97.2 78.792 ;
    END
  END sink_data[91]
  PIN sink_data[92]
    DIRECTION OUTPUT ;
    USE SIGNAL ;
    PORT
      LAYER M4 ;
        RECT  97.116 78.864 97.2 78.888 ;
    END
  END sink_data[92]
  PIN sink_data[93]
    DIRECTION OUTPUT ;
    USE SIGNAL ;
    PORT
      LAYER M4 ;
        RECT  97.116 78.96 97.2 78.984 ;
    END
  END sink_data[93]
  PIN sink_data[94]
    DIRECTION OUTPUT ;
    USE SIGNAL ;
    PORT
      LAYER M4 ;
        RECT  97.116 79.056 97.2 79.08 ;
    END
  END sink_data[94]
  PIN sink_data[95]
    DIRECTION OUTPUT ;
    USE SIGNAL ;
    PORT
      LAYER M4 ;
        RECT  97.116 79.152 97.2 79.176 ;
    END
  END sink_data[95]
  PIN sink_data[96]
    DIRECTION OUTPUT ;
    USE SIGNAL ;
    PORT
      LAYER M4 ;
        RECT  97.116 79.248 97.2 79.272 ;
    END
  END sink_data[96]
  PIN sink_data[97]
    DIRECTION OUTPUT ;
    USE SIGNAL ;
    PORT
      LAYER M4 ;
        RECT  97.116 79.344 97.2 79.368 ;
    END
  END sink_data[97]
  PIN sink_data[98]
    DIRECTION OUTPUT ;
    USE SIGNAL ;
    PORT
      LAYER M4 ;
        RECT  97.116 79.44 97.2 79.464 ;
    END
  END sink_data[98]
  PIN sink_data[99]
    DIRECTION OUTPUT ;
    USE SIGNAL ;
    PORT
      LAYER M4 ;
        RECT  97.116 79.536 97.2 79.56 ;
    END
  END sink_data[99]
  PIN sink_data[9]
    DIRECTION OUTPUT ;
    USE SIGNAL ;
    PORT
      LAYER M4 ;
        RECT  97.116 37.872 97.2 37.896 ;
    END
  END sink_data[9]
  PIN sink_seal[0]
    DIRECTION OUTPUT ;
    USE SIGNAL ;
    PORT
      LAYER M4 ;
        RECT  97.116 85.392 97.2 85.416 ;
    END
  END sink_seal[0]
  PIN sink_seal[1]
    DIRECTION OUTPUT ;
    USE SIGNAL ;
    PORT
      LAYER M4 ;
        RECT  97.116 85.488 97.2 85.512 ;
    END
  END sink_seal[1]
  PIN sink_seal[2]
    DIRECTION OUTPUT ;
    USE SIGNAL ;
    PORT
      LAYER M4 ;
        RECT  97.116 85.584 97.2 85.608 ;
    END
  END sink_seal[2]
  PIN sink_seal[3]
    DIRECTION OUTPUT ;
    USE SIGNAL ;
    PORT
      LAYER M4 ;
        RECT  97.116 85.68 97.2 85.704 ;
    END
  END sink_seal[3]
  PIN sink_seal[4]
    DIRECTION OUTPUT ;
    USE SIGNAL ;
    PORT
      LAYER M4 ;
        RECT  97.116 85.776 97.2 85.8 ;
    END
  END sink_seal[4]
  PIN sink_we[0]
    DIRECTION OUTPUT ;
    USE SIGNAL ;
    PORT
      LAYER M4 ;
        RECT  97.116 85.872 97.2 85.896 ;
    END
  END sink_we[0]
  PIN sink_we[1]
    DIRECTION OUTPUT ;
    USE SIGNAL ;
    PORT
      LAYER M4 ;
        RECT  97.116 85.968 97.2 85.992 ;
    END
  END sink_we[1]
  PIN sink_we[2]
    DIRECTION OUTPUT ;
    USE SIGNAL ;
    PORT
      LAYER M4 ;
        RECT  97.116 86.064 97.2 86.088 ;
    END
  END sink_we[2]
  PIN sink_we[3]
    DIRECTION OUTPUT ;
    USE SIGNAL ;
    PORT
      LAYER M4 ;
        RECT  97.116 86.16 97.2 86.184 ;
    END
  END sink_we[3]
  PIN sink_we[4]
    DIRECTION OUTPUT ;
    USE SIGNAL ;
    PORT
      LAYER M4 ;
        RECT  97.116 86.256 97.2 86.28 ;
    END
  END sink_we[4]
  PIN upstream_fault
    DIRECTION INPUT ;
    USE SIGNAL ;
    PORT
      LAYER M5 ;
        RECT  90 0 90.024 0.084 ;
    END
  END upstream_fault
  PIN upstream_quiet
    DIRECTION INPUT ;
    USE SIGNAL ;
    PORT
      LAYER M5 ;
        RECT  90.096 0 90.12 0.084 ;
    END
  END upstream_quiet
  PIN vgo
    DIRECTION INPUT ;
    USE SIGNAL ;
    PORT
      LAYER M5 ;
        RECT  51.792 97.116 51.816 97.2 ;
    END
  END vgo
  PIN vgo_h
    DIRECTION OUTPUT ;
    USE SIGNAL ;
    PORT
      LAYER M5 ;
        RECT  51.888 97.116 51.912 97.2 ;
    END
  END vgo_h
  PIN VDD
    DIRECTION INOUT ;
    USE POWER ;
    PORT
      LAYER M5 ;
        RECT  94.392 2.151 94.512 95.049 ;
        RECT  88.992 2.151 89.112 95.049 ;
        RECT  83.592 2.151 83.712 95.049 ;
        RECT  78.192 2.151 78.312 95.049 ;
        RECT  72.792 2.151 72.912 95.049 ;
        RECT  67.392 2.151 67.512 95.049 ;
        RECT  61.992 2.151 62.112 95.049 ;
        RECT  56.592 2.151 56.712 95.049 ;
        RECT  51.192 2.151 51.312 95.049 ;
        RECT  45.792 2.151 45.912 95.049 ;
        RECT  40.392 2.151 40.512 95.049 ;
        RECT  34.992 2.151 35.112 95.049 ;
        RECT  29.592 2.151 29.712 95.049 ;
        RECT  24.192 2.151 24.312 95.049 ;
        RECT  18.792 2.151 18.912 95.049 ;
        RECT  13.392 2.151 13.512 95.049 ;
        RECT  7.992 2.151 8.112 95.049 ;
        RECT  2.592 2.151 2.712 95.049 ;
    END
  END VDD
  PIN VSS
    DIRECTION INOUT ;
    USE GROUND ;
    PORT
      LAYER M5 ;
        RECT  94.2 2.137 94.32 95.063 ;
        RECT  88.8 2.137 88.92 95.063 ;
        RECT  83.4 2.137 83.52 95.063 ;
        RECT  78 2.137 78.12 95.063 ;
        RECT  72.6 2.137 72.72 95.063 ;
        RECT  67.2 2.137 67.32 95.063 ;
        RECT  61.8 2.137 61.92 95.063 ;
        RECT  56.4 2.137 56.52 95.063 ;
        RECT  51 2.137 51.12 95.063 ;
        RECT  45.6 2.137 45.72 95.063 ;
        RECT  40.2 2.137 40.32 95.063 ;
        RECT  34.8 2.137 34.92 95.063 ;
        RECT  29.4 2.137 29.52 95.063 ;
        RECT  24 2.137 24.12 95.063 ;
        RECT  18.6 2.137 18.72 95.063 ;
        RECT  13.2 2.137 13.32 95.063 ;
        RECT  7.8 2.137 7.92 95.063 ;
        RECT  2.4 2.137 2.52 95.063 ;
    END
  END VSS
  OBS
    LAYER RVTN ;
     RECT  2.16 2.16 95.04 2.295 ;
     RECT  2.16 2.565 95.04 2.835 ;
     RECT  2.16 3.105 95.04 3.375 ;
     RECT  2.16 3.645 95.04 3.915 ;
     RECT  2.16 4.185 95.04 4.455 ;
     RECT  2.16 4.725 95.04 4.995 ;
     RECT  2.16 5.265 95.04 5.535 ;
     RECT  2.16 5.805 95.04 6.075 ;
     RECT  2.16 6.345 95.04 6.615 ;
     RECT  2.16 6.885 95.04 7.155 ;
     RECT  2.16 7.425 95.04 7.695 ;
     RECT  2.16 7.965 95.04 8.235 ;
     RECT  2.16 8.505 95.04 8.775 ;
     RECT  2.16 9.045 95.04 9.315 ;
     RECT  2.16 9.585 95.04 9.855 ;
     RECT  2.16 10.125 95.04 10.395 ;
     RECT  2.16 10.665 95.04 10.935 ;
     RECT  2.16 11.205 95.04 11.475 ;
     RECT  2.16 11.745 95.04 12.015 ;
     RECT  2.16 12.285 95.04 12.555 ;
     RECT  2.16 12.825 95.04 13.095 ;
     RECT  2.16 13.365 95.04 13.635 ;
     RECT  2.16 13.905 95.04 14.175 ;
     RECT  2.16 14.445 95.04 14.715 ;
     RECT  2.16 14.985 95.04 15.255 ;
     RECT  2.16 15.525 95.04 15.795 ;
     RECT  2.16 16.065 95.04 16.335 ;
     RECT  2.16 16.605 95.04 16.875 ;
     RECT  2.16 17.145 95.04 17.415 ;
     RECT  2.16 17.685 95.04 17.955 ;
     RECT  2.16 18.225 95.04 18.495 ;
     RECT  2.16 18.765 95.04 19.035 ;
     RECT  2.16 19.305 95.04 19.575 ;
     RECT  2.16 19.845 95.04 20.115 ;
     RECT  2.16 20.385 95.04 20.655 ;
     RECT  2.16 20.925 95.04 21.195 ;
     RECT  2.16 21.465 95.04 21.735 ;
     RECT  2.16 22.005 95.04 22.275 ;
     RECT  2.16 22.545 95.04 22.815 ;
     RECT  2.16 23.085 95.04 23.355 ;
     RECT  2.16 23.625 95.04 23.895 ;
     RECT  2.16 24.165 95.04 24.435 ;
     RECT  2.16 24.705 95.04 24.975 ;
     RECT  2.16 25.245 95.04 25.515 ;
     RECT  2.16 25.785 95.04 26.055 ;
     RECT  2.16 26.325 95.04 26.595 ;
     RECT  2.16 26.865 95.04 27.135 ;
     RECT  2.16 27.405 95.04 27.675 ;
     RECT  2.16 27.945 95.04 28.215 ;
     RECT  2.16 28.485 95.04 28.755 ;
     RECT  2.16 29.025 95.04 29.295 ;
     RECT  2.16 29.565 95.04 29.835 ;
     RECT  2.16 30.105 95.04 30.375 ;
     RECT  2.16 30.645 95.04 30.915 ;
     RECT  2.16 31.185 95.04 31.455 ;
     RECT  2.16 31.725 95.04 31.995 ;
     RECT  2.16 32.265 95.04 32.535 ;
     RECT  2.16 32.805 95.04 33.075 ;
     RECT  2.16 33.345 95.04 33.615 ;
     RECT  2.16 33.885 95.04 34.155 ;
     RECT  2.16 34.425 95.04 34.695 ;
     RECT  2.16 34.965 95.04 35.235 ;
     RECT  2.16 35.505 95.04 35.775 ;
     RECT  2.16 36.045 95.04 36.315 ;
     RECT  2.16 36.585 95.04 36.855 ;
     RECT  2.16 37.125 95.04 37.395 ;
     RECT  2.16 37.665 95.04 37.935 ;
     RECT  2.16 38.205 95.04 38.475 ;
     RECT  2.16 38.745 95.04 39.015 ;
     RECT  2.16 39.285 95.04 39.555 ;
     RECT  2.16 39.825 95.04 40.095 ;
     RECT  2.16 40.365 95.04 40.635 ;
     RECT  2.16 40.905 95.04 41.175 ;
     RECT  2.16 41.445 95.04 41.715 ;
     RECT  2.16 41.985 95.04 42.255 ;
     RECT  2.16 42.525 95.04 42.795 ;
     RECT  2.16 43.065 95.04 43.335 ;
     RECT  2.16 43.605 95.04 43.875 ;
     RECT  2.16 44.145 95.04 44.415 ;
     RECT  2.16 44.685 95.04 44.955 ;
     RECT  2.16 45.225 95.04 45.495 ;
     RECT  2.16 45.765 95.04 46.035 ;
     RECT  2.16 46.305 95.04 46.575 ;
     RECT  2.16 46.845 95.04 47.115 ;
     RECT  2.16 47.385 95.04 47.655 ;
     RECT  2.16 47.925 95.04 48.195 ;
     RECT  2.16 48.465 95.04 48.735 ;
     RECT  2.16 49.005 95.04 49.275 ;
     RECT  2.16 49.545 95.04 49.815 ;
     RECT  2.16 50.085 95.04 50.355 ;
     RECT  2.16 50.625 95.04 50.895 ;
     RECT  2.16 51.165 95.04 51.435 ;
     RECT  2.16 51.705 95.04 51.975 ;
     RECT  2.16 52.245 95.04 52.515 ;
     RECT  2.16 52.785 95.04 53.055 ;
     RECT  2.16 53.325 95.04 53.595 ;
     RECT  2.16 53.865 95.04 54.135 ;
     RECT  2.16 54.405 95.04 54.675 ;
     RECT  2.16 54.945 95.04 55.215 ;
     RECT  2.16 55.485 95.04 55.755 ;
     RECT  2.16 56.025 95.04 56.295 ;
     RECT  2.16 56.565 95.04 56.835 ;
     RECT  2.16 57.105 95.04 57.375 ;
     RECT  2.16 57.645 95.04 57.915 ;
     RECT  2.16 58.185 95.04 58.455 ;
     RECT  2.16 58.725 95.04 58.995 ;
     RECT  2.16 59.265 95.04 59.535 ;
     RECT  2.16 59.805 95.04 60.075 ;
     RECT  2.16 60.345 95.04 60.615 ;
     RECT  2.16 60.885 95.04 61.155 ;
     RECT  2.16 61.425 95.04 61.695 ;
     RECT  2.16 61.965 95.04 62.235 ;
     RECT  2.16 62.505 95.04 62.775 ;
     RECT  2.16 63.045 95.04 63.315 ;
     RECT  2.16 63.585 95.04 63.855 ;
     RECT  2.16 64.125 95.04 64.395 ;
     RECT  2.16 64.665 95.04 64.935 ;
     RECT  2.16 65.205 95.04 65.475 ;
     RECT  2.16 65.745 95.04 66.015 ;
     RECT  2.16 66.285 95.04 66.555 ;
     RECT  2.16 66.825 95.04 67.095 ;
     RECT  2.16 67.365 95.04 67.635 ;
     RECT  2.16 67.905 95.04 68.175 ;
     RECT  2.16 68.445 95.04 68.715 ;
     RECT  2.16 68.985 95.04 69.255 ;
     RECT  2.16 69.525 95.04 69.795 ;
     RECT  2.16 70.065 95.04 70.335 ;
     RECT  2.16 70.605 95.04 70.875 ;
     RECT  2.16 71.145 95.04 71.415 ;
     RECT  2.16 71.685 95.04 71.955 ;
     RECT  2.16 72.225 95.04 72.495 ;
     RECT  2.16 72.765 95.04 73.035 ;
     RECT  2.16 73.305 95.04 73.575 ;
     RECT  2.16 73.845 95.04 74.115 ;
     RECT  2.16 74.385 95.04 74.655 ;
     RECT  2.16 74.925 95.04 75.195 ;
     RECT  2.16 75.465 95.04 75.735 ;
     RECT  2.16 76.005 95.04 76.275 ;
     RECT  2.16 76.545 95.04 76.815 ;
     RECT  2.16 77.085 95.04 77.355 ;
     RECT  2.16 77.625 95.04 77.895 ;
     RECT  2.16 78.165 95.04 78.435 ;
     RECT  2.16 78.705 95.04 78.975 ;
     RECT  2.16 79.245 95.04 79.515 ;
     RECT  2.16 79.785 95.04 80.055 ;
     RECT  2.16 80.325 95.04 80.595 ;
     RECT  2.16 80.865 95.04 81.135 ;
     RECT  2.16 81.405 95.04 81.675 ;
     RECT  2.16 81.945 95.04 82.215 ;
     RECT  2.16 82.485 95.04 82.755 ;
     RECT  2.16 83.025 95.04 83.295 ;
     RECT  2.16 83.565 95.04 83.835 ;
     RECT  2.16 84.105 95.04 84.375 ;
     RECT  2.16 84.645 95.04 84.915 ;
     RECT  2.16 85.185 95.04 85.455 ;
     RECT  2.16 85.725 95.04 85.995 ;
     RECT  2.16 86.265 95.04 86.535 ;
     RECT  2.16 86.805 95.04 87.075 ;
     RECT  2.16 87.345 95.04 87.615 ;
     RECT  2.16 87.885 95.04 88.155 ;
     RECT  2.16 88.425 95.04 88.695 ;
     RECT  2.16 88.965 95.04 89.235 ;
     RECT  2.16 89.505 95.04 89.775 ;
     RECT  2.16 90.045 95.04 90.315 ;
     RECT  2.16 90.585 95.04 90.855 ;
     RECT  2.16 91.125 95.04 91.395 ;
     RECT  2.16 91.665 95.04 91.935 ;
     RECT  2.16 92.205 95.04 92.475 ;
     RECT  2.16 92.745 95.04 93.015 ;
     RECT  2.16 93.285 95.04 93.555 ;
     RECT  2.16 93.825 95.04 94.095 ;
     RECT  2.16 94.365 95.04 94.635 ;
     RECT  2.16 94.905 95.04 95.04 ;
    LAYER RVTP ;
     RECT  2.16 2.295 95.04 2.565 ;
     RECT  2.16 2.835 95.04 3.105 ;
     RECT  2.16 3.375 95.04 3.645 ;
     RECT  2.16 3.915 95.04 4.185 ;
     RECT  2.16 4.455 95.04 4.725 ;
     RECT  2.16 4.995 95.04 5.265 ;
     RECT  2.16 5.535 95.04 5.805 ;
     RECT  2.16 6.075 95.04 6.345 ;
     RECT  2.16 6.615 95.04 6.885 ;
     RECT  2.16 7.155 95.04 7.425 ;
     RECT  2.16 7.695 95.04 7.965 ;
     RECT  2.16 8.235 95.04 8.505 ;
     RECT  2.16 8.775 95.04 9.045 ;
     RECT  2.16 9.315 95.04 9.585 ;
     RECT  2.16 9.855 95.04 10.125 ;
     RECT  2.16 10.395 95.04 10.665 ;
     RECT  2.16 10.935 95.04 11.205 ;
     RECT  2.16 11.475 95.04 11.745 ;
     RECT  2.16 12.015 95.04 12.285 ;
     RECT  2.16 12.555 95.04 12.825 ;
     RECT  2.16 13.095 95.04 13.365 ;
     RECT  2.16 13.635 95.04 13.905 ;
     RECT  2.16 14.175 95.04 14.445 ;
     RECT  2.16 14.715 95.04 14.985 ;
     RECT  2.16 15.255 95.04 15.525 ;
     RECT  2.16 15.795 95.04 16.065 ;
     RECT  2.16 16.335 95.04 16.605 ;
     RECT  2.16 16.875 95.04 17.145 ;
     RECT  2.16 17.415 95.04 17.685 ;
     RECT  2.16 17.955 95.04 18.225 ;
     RECT  2.16 18.495 95.04 18.765 ;
     RECT  2.16 19.035 95.04 19.305 ;
     RECT  2.16 19.575 95.04 19.845 ;
     RECT  2.16 20.115 95.04 20.385 ;
     RECT  2.16 20.655 95.04 20.925 ;
     RECT  2.16 21.195 95.04 21.465 ;
     RECT  2.16 21.735 95.04 22.005 ;
     RECT  2.16 22.275 95.04 22.545 ;
     RECT  2.16 22.815 95.04 23.085 ;
     RECT  2.16 23.355 95.04 23.625 ;
     RECT  2.16 23.895 95.04 24.165 ;
     RECT  2.16 24.435 95.04 24.705 ;
     RECT  2.16 24.975 95.04 25.245 ;
     RECT  2.16 25.515 95.04 25.785 ;
     RECT  2.16 26.055 95.04 26.325 ;
     RECT  2.16 26.595 95.04 26.865 ;
     RECT  2.16 27.135 95.04 27.405 ;
     RECT  2.16 27.675 95.04 27.945 ;
     RECT  2.16 28.215 95.04 28.485 ;
     RECT  2.16 28.755 95.04 29.025 ;
     RECT  2.16 29.295 95.04 29.565 ;
     RECT  2.16 29.835 95.04 30.105 ;
     RECT  2.16 30.375 95.04 30.645 ;
     RECT  2.16 30.915 95.04 31.185 ;
     RECT  2.16 31.455 95.04 31.725 ;
     RECT  2.16 31.995 95.04 32.265 ;
     RECT  2.16 32.535 95.04 32.805 ;
     RECT  2.16 33.075 95.04 33.345 ;
     RECT  2.16 33.615 95.04 33.885 ;
     RECT  2.16 34.155 95.04 34.425 ;
     RECT  2.16 34.695 95.04 34.965 ;
     RECT  2.16 35.235 95.04 35.505 ;
     RECT  2.16 35.775 95.04 36.045 ;
     RECT  2.16 36.315 95.04 36.585 ;
     RECT  2.16 36.855 95.04 37.125 ;
     RECT  2.16 37.395 95.04 37.665 ;
     RECT  2.16 37.935 95.04 38.205 ;
     RECT  2.16 38.475 95.04 38.745 ;
     RECT  2.16 39.015 95.04 39.285 ;
     RECT  2.16 39.555 95.04 39.825 ;
     RECT  2.16 40.095 95.04 40.365 ;
     RECT  2.16 40.635 95.04 40.905 ;
     RECT  2.16 41.175 95.04 41.445 ;
     RECT  2.16 41.715 95.04 41.985 ;
     RECT  2.16 42.255 95.04 42.525 ;
     RECT  2.16 42.795 95.04 43.065 ;
     RECT  2.16 43.335 95.04 43.605 ;
     RECT  2.16 43.875 95.04 44.145 ;
     RECT  2.16 44.415 95.04 44.685 ;
     RECT  2.16 44.955 95.04 45.225 ;
     RECT  2.16 45.495 95.04 45.765 ;
     RECT  2.16 46.035 95.04 46.305 ;
     RECT  2.16 46.575 95.04 46.845 ;
     RECT  2.16 47.115 95.04 47.385 ;
     RECT  2.16 47.655 95.04 47.925 ;
     RECT  2.16 48.195 95.04 48.465 ;
     RECT  2.16 48.735 95.04 49.005 ;
     RECT  2.16 49.275 95.04 49.545 ;
     RECT  2.16 49.815 95.04 50.085 ;
     RECT  2.16 50.355 95.04 50.625 ;
     RECT  2.16 50.895 95.04 51.165 ;
     RECT  2.16 51.435 95.04 51.705 ;
     RECT  2.16 51.975 95.04 52.245 ;
     RECT  2.16 52.515 95.04 52.785 ;
     RECT  2.16 53.055 95.04 53.325 ;
     RECT  2.16 53.595 95.04 53.865 ;
     RECT  2.16 54.135 95.04 54.405 ;
     RECT  2.16 54.675 95.04 54.945 ;
     RECT  2.16 55.215 95.04 55.485 ;
     RECT  2.16 55.755 95.04 56.025 ;
     RECT  2.16 56.295 95.04 56.565 ;
     RECT  2.16 56.835 95.04 57.105 ;
     RECT  2.16 57.375 95.04 57.645 ;
     RECT  2.16 57.915 95.04 58.185 ;
     RECT  2.16 58.455 95.04 58.725 ;
     RECT  2.16 58.995 95.04 59.265 ;
     RECT  2.16 59.535 95.04 59.805 ;
     RECT  2.16 60.075 95.04 60.345 ;
     RECT  2.16 60.615 95.04 60.885 ;
     RECT  2.16 61.155 95.04 61.425 ;
     RECT  2.16 61.695 95.04 61.965 ;
     RECT  2.16 62.235 95.04 62.505 ;
     RECT  2.16 62.775 95.04 63.045 ;
     RECT  2.16 63.315 95.04 63.585 ;
     RECT  2.16 63.855 95.04 64.125 ;
     RECT  2.16 64.395 95.04 64.665 ;
     RECT  2.16 64.935 95.04 65.205 ;
     RECT  2.16 65.475 95.04 65.745 ;
     RECT  2.16 66.015 95.04 66.285 ;
     RECT  2.16 66.555 95.04 66.825 ;
     RECT  2.16 67.095 95.04 67.365 ;
     RECT  2.16 67.635 95.04 67.905 ;
     RECT  2.16 68.175 95.04 68.445 ;
     RECT  2.16 68.715 95.04 68.985 ;
     RECT  2.16 69.255 95.04 69.525 ;
     RECT  2.16 69.795 95.04 70.065 ;
     RECT  2.16 70.335 95.04 70.605 ;
     RECT  2.16 70.875 95.04 71.145 ;
     RECT  2.16 71.415 95.04 71.685 ;
     RECT  2.16 71.955 95.04 72.225 ;
     RECT  2.16 72.495 95.04 72.765 ;
     RECT  2.16 73.035 95.04 73.305 ;
     RECT  2.16 73.575 95.04 73.845 ;
     RECT  2.16 74.115 95.04 74.385 ;
     RECT  2.16 74.655 95.04 74.925 ;
     RECT  2.16 75.195 95.04 75.465 ;
     RECT  2.16 75.735 95.04 76.005 ;
     RECT  2.16 76.275 95.04 76.545 ;
     RECT  2.16 76.815 95.04 77.085 ;
     RECT  2.16 77.355 95.04 77.625 ;
     RECT  2.16 77.895 95.04 78.165 ;
     RECT  2.16 78.435 95.04 78.705 ;
     RECT  2.16 78.975 95.04 79.245 ;
     RECT  2.16 79.515 95.04 79.785 ;
     RECT  2.16 80.055 95.04 80.325 ;
     RECT  2.16 80.595 95.04 80.865 ;
     RECT  2.16 81.135 95.04 81.405 ;
     RECT  2.16 81.675 95.04 81.945 ;
     RECT  2.16 82.215 95.04 82.485 ;
     RECT  2.16 82.755 95.04 83.025 ;
     RECT  2.16 83.295 95.04 83.565 ;
     RECT  2.16 83.835 95.04 84.105 ;
     RECT  2.16 84.375 95.04 84.645 ;
     RECT  2.16 84.915 95.04 85.185 ;
     RECT  2.16 85.455 95.04 85.725 ;
     RECT  2.16 85.995 95.04 86.265 ;
     RECT  2.16 86.535 95.04 86.805 ;
     RECT  2.16 87.075 95.04 87.345 ;
     RECT  2.16 87.615 95.04 87.885 ;
     RECT  2.16 88.155 95.04 88.425 ;
     RECT  2.16 88.695 95.04 88.965 ;
     RECT  2.16 89.235 95.04 89.505 ;
     RECT  2.16 89.775 95.04 90.045 ;
     RECT  2.16 90.315 95.04 90.585 ;
     RECT  2.16 90.855 95.04 91.125 ;
     RECT  2.16 91.395 95.04 91.665 ;
     RECT  2.16 91.935 95.04 92.205 ;
     RECT  2.16 92.475 95.04 92.745 ;
     RECT  2.16 93.015 95.04 93.285 ;
     RECT  2.16 93.555 95.04 93.825 ;
     RECT  2.16 94.095 95.04 94.365 ;
     RECT  2.16 94.635 95.04 94.905 ;
    LAYER M1 ;
     RECT  2.16 2.151 95.04 95.049 ;
    LAYER M2 ;
     RECT  0.103 53.874 0.139 53.892 ;
     RECT  0.103 64.872 0.139 64.89 ;
     RECT  0.103 42.732 0.175 42.75 ;
     RECT  0.139 57.654 0.175 57.672 ;
     RECT  0.103 30.726 0.203 30.834 ;
     RECT  0.139 53.64 0.211 53.892 ;
     RECT  0.103 55.53 0.211 55.548 ;
     RECT  0.103 76.554 0.211 76.572 ;
     RECT  0.211 53.64 0.239 54.234 ;
     RECT  0.211 55.53 0.239 55.746 ;
     RECT  0.175 57.654 0.275 57.978 ;
     RECT  0.239 53.874 0.347 54.234 ;
     RECT  0.211 76.401 0.347 76.572 ;
     RECT  0.103 34.596 0.383 34.614 ;
     RECT  0.239 55.728 0.383 55.746 ;
     RECT  0.103 7.434 0.571 7.452 ;
     RECT  0.571 7.434 0.599 8.19 ;
     RECT  0.571 58.932 1.723 58.95 ;
     RECT  1.975 48.51 1.977 48.528 ;
     RECT  0.599 8.172 2.16 8.19 ;
     RECT  0.103 10.17 2.16 10.188 ;
     RECT  0.103 29.34 2.16 29.358 ;
     RECT  0.203 30.816 2.16 30.834 ;
     RECT  1.723 36.522 2.16 36.54 ;
     RECT  0.175 42.732 2.16 43.128 ;
     RECT  1.977 48.507 2.16 48.531 ;
     RECT  1.723 58.392 2.16 58.95 ;
     RECT  0.139 64.71 2.16 64.89 ;
     RECT  0.103 75.132 2.16 75.15 ;
     RECT  0.103 87.39 2.16 87.408 ;
     RECT  2.16 2.151 3.955 95.049 ;
     RECT  3.955 2.151 4.595 95.094 ;
     RECT  4.595 2.151 39.163 95.049 ;
     RECT  39.163 2.151 40.055 95.094 ;
     RECT  40.055 2.151 80.383 95.049 ;
     RECT  80.383 2.151 81.103 95.094 ;
     RECT  81.103 2.151 82.571 95.166 ;
     RECT  82.571 2.151 84.847 95.13 ;
     RECT  84.847 2.151 91.535 95.166 ;
     RECT  91.535 2.151 92.399 95.13 ;
     RECT  92.399 2.151 92.831 95.094 ;
     RECT  92.831 2.151 95.04 95.049 ;
     RECT  95.04 2.736 95.135 3.978 ;
     RECT  95.04 72.468 95.135 83.79 ;
     RECT  95.135 72.468 95.207 83.52 ;
     RECT  95.04 90.216 95.207 94.554 ;
     RECT  95.207 90.216 95.387 93.744 ;
     RECT  95.04 7.056 95.747 7.182 ;
     RECT  95.04 53.838 95.747 54.774 ;
     RECT  95.04 85.356 95.747 88.884 ;
     RECT  95.04 27.576 95.783 34.416 ;
     RECT  95.783 27.756 95.819 34.416 ;
     RECT  95.04 35.28 95.819 43.164 ;
     RECT  95.04 71.316 95.819 71.334 ;
     RECT  95.387 90.216 95.855 93.654 ;
     RECT  95.819 41.382 95.891 43.164 ;
     RECT  95.819 27.918 95.927 34.416 ;
     RECT  95.891 41.688 95.927 43.164 ;
     RECT  95.04 9.216 96.035 9.504 ;
     RECT  95.04 55.728 96.035 58.554 ;
     RECT  95.855 90.216 96.071 90.576 ;
     RECT  95.207 76.986 96.251 83.52 ;
     RECT  95.04 5.076 96.287 6.264 ;
     RECT  96.251 76.986 96.287 78.894 ;
     RECT  95.747 85.356 96.287 85.914 ;
     RECT  96.287 5.076 96.323 6.066 ;
     RECT  95.04 17.856 96.323 21.924 ;
     RECT  95.819 35.28 96.323 40.464 ;
     RECT  95.04 44.046 96.323 44.604 ;
     RECT  95.207 72.468 96.323 76.194 ;
     RECT  96.287 76.986 96.323 78.354 ;
     RECT  96.251 79.686 96.323 83.52 ;
     RECT  96.287 85.356 96.323 85.374 ;
     RECT  95.207 94.536 96.323 94.554 ;
     RECT  96.323 5.076 96.359 5.094 ;
     RECT  95.927 27.918 96.359 27.936 ;
     RECT  95.927 28.836 96.359 34.416 ;
     RECT  95.927 41.958 96.359 43.164 ;
     RECT  95.747 53.838 96.359 53.856 ;
     RECT  95.747 54.756 96.359 54.774 ;
     RECT  96.323 72.468 96.359 76.068 ;
     RECT  96.323 77.094 96.359 77.922 ;
     RECT  95.855 91.44 96.359 93.654 ;
     RECT  95.04 15.228 96.395 17.1 ;
     RECT  96.359 28.836 96.395 32.832 ;
     RECT  96.359 93.06 96.395 93.654 ;
     RECT  95.135 2.736 96.431 3.744 ;
     RECT  96.395 28.926 96.431 32.832 ;
     RECT  96.359 72.468 96.431 75.726 ;
     RECT  96.323 79.794 96.431 83.52 ;
     RECT  96.395 93.366 96.431 93.654 ;
     RECT  96.431 3.546 96.467 3.744 ;
     RECT  96.359 42.156 96.467 43.164 ;
     RECT  96.431 75.168 96.467 75.726 ;
     RECT  96.395 15.426 96.503 16.524 ;
     RECT  95.04 48.366 96.503 52.848 ;
     RECT  96.431 79.794 96.503 83.214 ;
     RECT  96.431 28.998 96.539 32.49 ;
     RECT  96.431 72.468 96.539 74.106 ;
     RECT  96.539 28.998 96.575 29.754 ;
     RECT  96.467 42.498 96.575 43.164 ;
     RECT  96.539 72.666 96.575 74.106 ;
     RECT  96.575 29.466 96.611 29.754 ;
     RECT  96.503 48.708 96.611 52.848 ;
     RECT  96.611 48.708 96.647 50.004 ;
     RECT  96.035 55.728 96.655 58.374 ;
     RECT  96.647 49.896 96.683 50.004 ;
     RECT  96.611 50.751 96.719 52.848 ;
     RECT  96.655 55.656 96.755 58.374 ;
     RECT  95.04 45.468 96.863 47.034 ;
     RECT  96.755 57.114 96.863 58.374 ;
     RECT  96.323 35.514 96.899 40.464 ;
     RECT  95.747 86.706 96.899 88.884 ;
     RECT  96.899 35.514 96.935 38.736 ;
     RECT  96.863 57.15 96.935 58.374 ;
     RECT  96.503 79.794 96.935 83.052 ;
     RECT  96.899 86.706 96.935 88.614 ;
     RECT  96.323 18.504 96.971 21.924 ;
     RECT  96.935 35.514 96.971 36.072 ;
     RECT  96.863 45.702 96.971 47.034 ;
     RECT  96.935 57.15 96.971 58.104 ;
     RECT  96.935 79.794 96.971 81.162 ;
     RECT  96.971 18.504 97.007 19.134 ;
     RECT  96.971 35.514 97.007 35.802 ;
     RECT  96.899 39.906 97.007 40.464 ;
     RECT  96.971 45.702 97.007 46.944 ;
     RECT  96.971 57.15 97.007 57.204 ;
     RECT  96.971 79.794 97.007 80.964 ;
     RECT  96.935 87.516 97.007 88.614 ;
     RECT  96.503 16.506 97.043 16.524 ;
     RECT  96.971 20.556 97.043 21.924 ;
     RECT  96.359 33.66 97.043 34.416 ;
     RECT  97.007 35.55 97.043 35.802 ;
     RECT  97.007 45.702 97.043 46.764 ;
     RECT  96.719 51.516 97.043 52.848 ;
     RECT  96.755 55.728 97.043 55.944 ;
     RECT  96.575 72.936 97.043 74.106 ;
     RECT  97.007 79.866 97.043 80.964 ;
     RECT  97.007 87.516 97.043 88.524 ;
     RECT  96.359 91.44 97.043 91.764 ;
     RECT  96.323 6.048 97.051 6.066 ;
     RECT  95.747 7.164 97.051 7.182 ;
     RECT  97.043 33.93 97.051 34.416 ;
     RECT  97.051 6.048 97.079 7.182 ;
     RECT  96.503 15.426 97.079 15.714 ;
     RECT  97.043 21.006 97.079 21.924 ;
     RECT  96.611 29.466 97.079 29.628 ;
     RECT  96.539 30.654 97.079 32.49 ;
     RECT  97.043 35.55 97.079 35.604 ;
     RECT  96.935 36.828 97.079 38.736 ;
     RECT  97.043 46.746 97.079 46.764 ;
     RECT  96.647 48.708 97.079 48.96 ;
     RECT  97.043 52.326 97.079 52.848 ;
     RECT  97.007 57.15 97.079 57.168 ;
     RECT  97.043 72.936 97.079 72.954 ;
     RECT  97.043 79.866 97.079 80.352 ;
     RECT  96.935 82.116 97.079 83.052 ;
     RECT  96.935 86.706 97.079 86.724 ;
     RECT  96.431 93.636 97.079 93.654 ;
     RECT  96.979 54.306 97.087 54.324 ;
     RECT  97.015 95.256 97.087 95.274 ;
     RECT  96.467 3.726 97.115 3.744 ;
     RECT  97.079 6.696 97.115 7.182 ;
     RECT  97.079 15.426 97.115 15.444 ;
     RECT  97.007 18.504 97.115 18.864 ;
     RECT  97.079 21.006 97.115 21.024 ;
     RECT  97.079 29.61 97.115 29.628 ;
     RECT  97.079 30.654 97.115 30.672 ;
     RECT  97.079 31.896 97.115 32.49 ;
     RECT  97.051 33.93 97.115 34.794 ;
     RECT  97.079 35.55 97.115 35.568 ;
     RECT  97.007 40.14 97.115 40.464 ;
     RECT  96.575 43.146 97.115 43.164 ;
     RECT  97.043 45.702 97.115 45.72 ;
     RECT  97.079 48.708 97.115 48.726 ;
     RECT  97.043 51.516 97.115 51.534 ;
     RECT  97.079 52.83 97.115 52.848 ;
     RECT  97.087 54.306 97.115 54.63 ;
     RECT  97.043 55.728 97.115 55.746 ;
     RECT  97.043 74.088 97.115 74.106 ;
     RECT  96.467 75.708 97.115 75.726 ;
     RECT  96.359 77.706 97.115 77.922 ;
     RECT  97.079 79.866 97.115 79.884 ;
     RECT  97.079 82.296 97.115 83.052 ;
     RECT  97.043 87.516 97.115 87.534 ;
     RECT  97.043 91.746 97.115 91.764 ;
     RECT  97.087 95.256 97.115 95.472 ;
     RECT  97.115 34.056 97.151 34.794 ;
     RECT  97.079 36.828 97.151 37.998 ;
     RECT  96.683 49.986 97.151 50.004 ;
     RECT  96.719 50.751 97.151 50.769 ;
     RECT  96.431 2.736 97.187 2.754 ;
     RECT  97.087 4.851 97.187 4.869 ;
     RECT  97.115 6.696 97.187 6.714 ;
     RECT  96.035 9.216 97.187 9.234 ;
     RECT  97.115 18.504 97.187 18.522 ;
     RECT  97.079 21.906 97.187 21.924 ;
     RECT  97.151 34.056 97.187 34.074 ;
     RECT  97.151 36.828 97.187 36.846 ;
     RECT  97.151 37.98 97.187 37.998 ;
     RECT  97.115 40.14 97.187 40.158 ;
     RECT  97.115 54.612 97.187 54.63 ;
     RECT  96.971 58.086 97.187 58.104 ;
     RECT  97.051 85.626 97.187 85.644 ;
     RECT  97.043 88.506 97.187 88.524 ;
     RECT  96.071 90.216 97.187 90.234 ;
     RECT  97.115 95.454 97.187 95.472 ;
    LAYER M3 ;
     RECT  91.008 0.139 91.026 0.187 ;
     RECT  86.076 0.091 86.742 0.317 ;
     RECT  89.316 0.235 89.334 0.413 ;
     RECT  83.88 0.091 83.898 0.475 ;
     RECT  90.504 0.187 91.026 1.723 ;
     RECT  90.324 1.723 91.026 1.771 ;
     RECT  83.808 0.475 83.898 1.963 ;
     RECT  83.808 1.963 83.934 2.011 ;
     RECT  94.572 1.963 94.59 2.011 ;
     RECT  94.5 2.011 94.59 2.059 ;
     RECT  94.356 2.059 94.59 2.143 ;
     RECT  84.744 1.723 85.266 2.155 ;
     RECT  86.076 0.317 86.094 2.155 ;
     RECT  88.815 2.143 88.905 2.155 ;
     RECT  5.184 2.155 5.202 2.191 ;
     RECT  7.815 2.143 7.905 2.191 ;
     RECT  13.215 2.143 13.305 2.191 ;
     RECT  18.615 2.143 18.705 2.191 ;
     RECT  29.415 2.143 29.505 2.191 ;
     RECT  34.815 2.143 34.905 2.191 ;
     RECT  40.215 2.143 40.305 2.191 ;
     RECT  45.615 2.143 45.705 2.191 ;
     RECT  67.215 2.143 67.305 2.191 ;
     RECT  84.744 2.155 86.094 2.191 ;
     RECT  88.704 2.155 88.905 2.191 ;
     RECT  89.964 1.771 91.026 2.191 ;
     RECT  4.752 2.191 5.202 2.203 ;
     RECT  6.048 2.191 6.066 2.203 ;
     RECT  40.032 2.191 41.31 2.203 ;
     RECT  87.012 2.191 87.282 2.203 ;
     RECT  88.308 2.191 88.905 2.203 ;
     RECT  89.892 2.191 92.286 2.203 ;
     RECT  40.032 2.203 41.382 2.227 ;
     RECT  56.415 2.143 56.505 2.227 ;
     RECT  57.528 2.191 57.546 2.227 ;
     RECT  60.084 2.191 60.102 2.227 ;
     RECT  61.815 2.143 61.905 2.227 ;
     RECT  63.288 2.191 63.846 2.227 ;
     RECT  67.215 2.191 67.77 2.227 ;
     RECT  74.844 2.191 74.862 2.227 ;
     RECT  78.015 2.143 78.105 2.227 ;
     RECT  82.548 2.191 82.566 2.227 ;
     RECT  83.376 2.011 83.934 2.227 ;
     RECT  84.672 2.191 86.094 2.227 ;
     RECT  39.348 2.227 41.382 2.237 ;
     RECT  4.572 2.203 6.066 2.251 ;
     RECT  54.612 2.227 54.63 2.251 ;
     RECT  78.015 2.227 78.462 2.251 ;
     RECT  87.012 2.203 88.905 2.251 ;
     RECT  89.712 2.203 92.286 2.251 ;
     RECT  93.204 2.191 93.222 2.251 ;
     RECT  94.215 2.143 94.59 2.251 ;
     RECT  6.804 2.191 8.37 2.263 ;
     RECT  9.54 2.227 9.882 2.263 ;
     RECT  11.556 2.227 11.574 2.263 ;
     RECT  13.215 2.191 13.626 2.263 ;
     RECT  18.216 2.191 18.705 2.263 ;
     RECT  22.86 2.191 22.878 2.263 ;
     RECT  26.064 2.227 26.082 2.263 ;
     RECT  31.392 2.227 31.41 2.263 ;
     RECT  37.08 2.191 37.638 2.263 ;
     RECT  42.372 2.203 42.39 2.263 ;
     RECT  47.412 2.227 47.43 2.263 ;
     RECT  52.668 2.191 52.686 2.263 ;
     RECT  67.212 2.227 68.958 2.263 ;
     RECT  69.804 2.191 69.822 2.263 ;
     RECT  83.34 2.227 86.094 2.263 ;
     RECT  87.012 2.251 93.222 2.263 ;
     RECT  17.064 2.227 17.082 2.299 ;
     RECT  37.08 2.263 38.07 2.299 ;
     RECT  53.892 2.251 54.882 2.299 ;
     RECT  59.976 2.227 60.102 2.299 ;
     RECT  65.916 2.251 65.934 2.299 ;
     RECT  67.212 2.263 69.822 2.299 ;
     RECT  72.615 2.143 72.705 2.299 ;
     RECT  81 2.191 81.018 2.299 ;
     RECT  81.756 2.227 82.566 2.299 ;
     RECT  83.34 2.263 93.258 2.299 ;
     RECT  4.068 2.251 6.066 2.335 ;
     RECT  11.16 2.263 11.574 2.335 ;
     RECT  16.812 2.299 17.082 2.335 ;
     RECT  17.892 2.263 18.705 2.335 ;
     RECT  25.704 2.263 26.082 2.335 ;
     RECT  30.384 2.191 30.402 2.335 ;
     RECT  31.392 2.263 31.626 2.335 ;
     RECT  37.08 2.299 38.358 2.335 ;
     RECT  49.5 2.227 49.518 2.335 ;
     RECT  52.488 2.263 52.686 2.335 ;
     RECT  61.56 2.227 62.154 2.335 ;
     RECT  65.376 2.299 65.934 2.335 ;
     RECT  66.888 2.299 69.822 2.335 ;
     RECT  79.92 2.299 93.258 2.335 ;
     RECT  61.488 2.335 62.154 2.347 ;
     RECT  63.288 2.227 64.314 2.347 ;
     RECT  65.376 2.335 70.47 2.347 ;
     RECT  94.215 2.251 94.806 2.347 ;
     RECT  6.804 2.263 8.73 2.371 ;
     RECT  9.54 2.263 10.098 2.371 ;
     RECT  11.124 2.335 11.574 2.371 ;
     RECT  13.14 2.263 13.878 2.371 ;
     RECT  16.812 2.335 18.774 2.371 ;
     RECT  19.62 2.335 19.638 2.371 ;
     RECT  22.824 2.263 22.878 2.371 ;
     RECT  24.015 2.143 24.105 2.371 ;
     RECT  27.432 2.191 29.505 2.371 ;
     RECT  30.384 2.335 30.582 2.371 ;
     RECT  41.22 2.237 41.382 2.371 ;
     RECT  42.372 2.263 42.678 2.371 ;
     RECT  45.36 2.191 45.705 2.371 ;
     RECT  46.764 2.263 47.538 2.371 ;
     RECT  49.284 2.335 49.518 2.371 ;
     RECT  51.015 2.143 51.105 2.371 ;
     RECT  52.452 2.335 52.686 2.371 ;
     RECT  53.748 2.299 54.882 2.371 ;
     RECT  56.415 2.227 58.158 2.371 ;
     RECT  59.904 2.299 60.102 2.371 ;
     RECT  61.488 2.347 70.47 2.371 ;
     RECT  71.82 2.191 71.838 2.371 ;
     RECT  72.615 2.299 73.062 2.371 ;
     RECT  75.888 2.251 75.906 2.371 ;
     RECT  78.015 2.251 79.038 2.371 ;
     RECT  79.776 2.335 93.258 2.371 ;
     RECT  2.415 2.143 2.505 2.413 ;
     RECT  16.524 2.371 18.774 2.413 ;
     RECT  22.464 2.371 24.105 2.413 ;
     RECT  34.38 2.191 34.905 2.413 ;
     RECT  50.652 2.371 51.105 2.413 ;
     RECT  78.015 2.371 93.294 2.443 ;
     RECT  94.104 2.347 94.806 2.443 ;
     RECT  21.096 2.443 21.114 2.461 ;
     RECT  41.22 2.371 43.398 2.461 ;
     RECT  52.452 2.371 55.242 2.461 ;
     RECT  56.016 2.371 58.266 2.461 ;
     RECT  16.524 2.413 18.897 2.491 ;
     RECT  19.62 2.371 20.034 2.491 ;
     RECT  22.464 2.413 24.297 2.491 ;
     RECT  37.008 2.335 38.358 2.491 ;
     RECT  39.348 2.237 40.497 2.491 ;
     RECT  3.528 2.335 6.066 2.497 ;
     RECT  6.804 2.371 11.574 2.497 ;
     RECT  78.015 2.443 94.806 2.497 ;
     RECT  13.104 2.371 13.878 2.533 ;
     RECT  32.976 2.299 32.994 2.533 ;
     RECT  34.38 2.413 35.097 2.533 ;
     RECT  36.216 2.497 36.234 2.533 ;
     RECT  48.78 2.371 49.518 2.533 ;
     RECT  74.088 2.227 74.106 2.533 ;
     RECT  74.844 2.227 74.97 2.533 ;
     RECT  14.832 2.299 15.21 2.539 ;
     RECT  16.524 2.491 20.034 2.539 ;
     RECT  22.104 2.491 24.297 2.569 ;
     RECT  77.652 2.497 94.806 2.569 ;
     RECT  25.704 2.335 26.298 2.587 ;
     RECT  27.432 2.371 30.582 2.587 ;
     RECT  25.704 2.587 30.582 2.605 ;
     RECT  31.392 2.335 31.698 2.605 ;
     RECT  32.976 2.533 36.234 2.605 ;
     RECT  37.008 2.491 40.497 2.605 ;
     RECT  44.496 2.371 47.538 2.605 ;
     RECT  48.42 2.533 49.518 2.605 ;
     RECT  52.452 2.461 58.266 2.605 ;
     RECT  59.22 2.371 60.75 2.605 ;
     RECT  12.636 2.533 13.878 2.641 ;
     RECT  14.832 2.539 20.034 2.641 ;
     RECT  20.844 2.461 21.114 2.641 ;
     RECT  22.104 2.569 24.462 2.641 ;
     RECT  25.704 2.605 31.698 2.641 ;
     RECT  32.976 2.605 40.497 2.641 ;
     RECT  41.22 2.461 43.47 2.641 ;
     RECT  44.46 2.605 49.518 2.641 ;
     RECT  52.452 2.605 60.75 2.641 ;
     RECT  61.488 2.371 73.062 2.641 ;
     RECT  74.088 2.533 74.97 2.641 ;
     RECT  75.888 2.371 76.554 2.641 ;
     RECT  77.58 2.569 94.806 2.641 ;
     RECT  3.528 2.497 11.574 2.731 ;
     RECT  12.564 2.641 13.878 2.731 ;
     RECT  2.415 2.413 2.697 2.767 ;
     RECT  3.528 2.731 13.878 2.767 ;
     RECT  25.704 2.641 32.022 2.767 ;
     RECT  32.796 2.641 40.497 2.767 ;
     RECT  41.22 2.641 49.518 2.767 ;
     RECT  50.652 2.413 51.297 2.767 ;
     RECT  41.22 2.767 51.498 2.827 ;
     RECT  52.452 2.641 76.554 2.827 ;
     RECT  41.22 2.827 76.554 2.839 ;
     RECT  77.364 2.641 94.806 2.839 ;
     RECT  2.415 2.767 13.878 2.875 ;
     RECT  14.832 2.641 24.462 2.875 ;
     RECT  41.22 2.839 94.806 2.875 ;
     RECT  2.415 2.875 24.642 2.911 ;
     RECT  25.704 2.767 40.497 2.911 ;
     RECT  2.415 2.911 40.497 3.181 ;
     RECT  41.22 2.875 94.842 3.181 ;
     RECT  96.336 2.803 96.354 3.271 ;
     RECT  2.415 3.181 94.914 3.307 ;
     RECT  2.304 3.307 94.914 3.379 ;
     RECT  96.336 3.271 96.39 3.379 ;
     RECT  2.304 3.379 95.238 3.437 ;
     RECT  2.34 3.437 95.238 3.479 ;
     RECT  96.336 3.379 96.426 3.541 ;
     RECT  97.164 2.731 97.182 3.541 ;
     RECT  96.336 3.541 97.182 3.821 ;
     RECT  2.34 3.479 95.166 4.225 ;
     RECT  2.304 4.225 95.166 4.589 ;
     RECT  96.372 3.821 97.182 4.781 ;
     RECT  97.092 4.781 97.182 4.874 ;
     RECT  97.092 4.874 97.11 4.877 ;
     RECT  96.3 4.939 96.354 5.035 ;
     RECT  0.18 5.275 0.198 5.419 ;
     RECT  0.18 5.419 0.342 5.549 ;
     RECT  95.724 5.035 96.354 5.803 ;
     RECT  95.724 5.803 96.93 5.995 ;
     RECT  95.724 5.995 97.11 6.173 ;
     RECT  95.724 6.173 96.282 6.269 ;
     RECT  2.304 4.589 94.842 6.385 ;
     RECT  2.268 6.385 94.842 6.509 ;
     RECT  2.304 6.509 94.842 6.571 ;
     RECT  97.056 6.173 97.11 6.691 ;
     RECT  97.056 6.691 97.182 6.719 ;
     RECT  95.724 6.269 96.03 7.079 ;
     RECT  97.092 6.719 97.182 7.187 ;
     RECT  0.108 6.763 0.126 7.429 ;
     RECT  0.108 7.429 0.594 7.457 ;
     RECT  2.304 6.571 94.914 7.889 ;
     RECT  0.576 7.457 0.594 8.195 ;
     RECT  2.304 7.889 94.698 8.851 ;
     RECT  97.164 7.187 97.182 9.239 ;
     RECT  96.012 7.079 96.03 9.509 ;
     RECT  2.304 8.851 94.734 9.677 ;
     RECT  2.34 9.677 94.734 9.823 ;
     RECT  2.34 9.823 94.842 10.435 ;
     RECT  0.108 10.165 0.126 10.541 ;
     RECT  2.304 10.435 94.842 10.741 ;
     RECT  2.268 10.741 94.842 11.011 ;
     RECT  2.268 11.011 94.914 11.813 ;
     RECT  2.268 11.813 94.806 11.851 ;
     RECT  2.232 11.851 94.806 11.939 ;
     RECT  2.232 11.939 94.734 12.047 ;
     RECT  0.144 11.707 0.162 12.523 ;
     RECT  2.304 12.047 94.734 12.551 ;
     RECT  0.144 12.523 0.234 12.715 ;
     RECT  0.144 12.715 0.378 12.845 ;
     RECT  2.304 12.551 94.59 12.901 ;
     RECT  2.268 12.901 94.59 13.019 ;
     RECT  2.268 13.019 94.554 13.127 ;
     RECT  0.144 12.845 0.342 13.277 ;
     RECT  0.216 13.277 0.342 13.421 ;
     RECT  0.216 13.421 0.234 13.757 ;
     RECT  2.304 13.127 94.554 13.981 ;
     RECT  2.304 13.981 94.626 14.143 ;
     RECT  2.304 14.143 94.698 14.369 ;
     RECT  2.304 14.369 94.59 14.675 ;
     RECT  2.376 14.675 94.59 15.151 ;
     RECT  2.376 15.151 94.626 15.295 ;
     RECT  2.376 15.295 94.698 15.331 ;
     RECT  96.372 15.223 96.39 15.421 ;
     RECT  96.372 15.421 97.11 15.493 ;
     RECT  96.336 15.493 97.11 15.601 ;
     RECT  2.376 15.331 94.914 15.727 ;
     RECT  2.304 15.727 94.914 16.141 ;
     RECT  96.3 15.601 97.11 16.205 ;
     RECT  96.336 16.205 97.11 16.493 ;
     RECT  2.304 16.141 95.166 16.529 ;
     RECT  2.304 16.529 38.61 16.673 ;
     RECT  39.348 16.529 95.166 16.685 ;
     RECT  96.336 16.493 97.074 17.069 ;
     RECT  96.336 17.069 97.038 17.165 ;
     RECT  39.348 16.685 95.13 17.419 ;
     RECT  2.304 16.673 38.574 17.467 ;
     RECT  39.348 17.419 95.202 17.467 ;
     RECT  96.336 17.165 96.498 17.515 ;
     RECT  2.304 17.467 95.202 17.609 ;
     RECT  96.3 17.515 96.498 17.707 ;
     RECT  2.376 17.609 95.202 17.803 ;
     RECT  2.376 17.803 95.454 17.899 ;
     RECT  96.264 17.707 96.498 17.899 ;
     RECT  2.376 17.899 96.498 17.995 ;
     RECT  2.376 17.995 97.074 18.187 ;
     RECT  2.376 18.187 97.11 18.499 ;
     RECT  2.376 18.499 97.182 18.797 ;
     RECT  2.415 18.797 97.182 19.769 ;
     RECT  2.415 19.769 96.03 20.147 ;
     RECT  2.415 20.147 95.454 20.885 ;
     RECT  95.436 20.885 95.454 21.119 ;
     RECT  96.876 19.769 97.182 21.389 ;
     RECT  2.415 20.885 94.626 21.631 ;
     RECT  97.164 21.389 97.182 21.929 ;
     RECT  2.415 21.631 94.806 22.351 ;
     RECT  2.415 22.351 94.842 22.541 ;
     RECT  2.415 22.541 94.806 22.883 ;
     RECT  2.415 22.883 3.87 23.611 ;
     RECT  4.608 22.883 94.806 23.611 ;
     RECT  2.415 23.611 94.806 24.161 ;
     RECT  2.415 24.161 92.394 24.173 ;
     RECT  93.456 24.161 94.806 24.359 ;
     RECT  93.456 24.359 94.497 24.629 ;
     RECT  93.528 24.629 94.497 24.665 ;
     RECT  2.415 24.173 91.998 24.781 ;
     RECT  2.376 24.781 91.998 24.941 ;
     RECT  2.415 24.941 91.998 24.943 ;
     RECT  2.415 24.943 92.106 26.293 ;
     RECT  2.415 26.293 92.178 26.491 ;
     RECT  2.376 26.491 92.178 26.519 ;
     RECT  2.376 26.519 91.998 27.329 ;
     RECT  2.376 27.329 37.962 27.355 ;
     RECT  38.808 27.329 91.998 27.365 ;
     RECT  2.34 27.355 37.962 27.635 ;
     RECT  94.215 24.665 94.497 27.715 ;
     RECT  95.76 27.571 95.778 27.751 ;
     RECT  2.34 27.635 35.73 27.841 ;
     RECT  93.564 27.715 94.497 27.841 ;
     RECT  95.76 27.751 95.814 27.877 ;
     RECT  93.168 27.841 94.662 27.913 ;
     RECT  95.724 27.877 95.814 27.913 ;
     RECT  92.556 27.913 94.662 28.255 ;
     RECT  36.468 27.635 37.962 28.291 ;
     RECT  92.556 28.255 94.734 28.291 ;
     RECT  2.268 27.841 35.73 28.381 ;
     RECT  36.468 28.291 38.034 28.381 ;
     RECT  38.808 27.365 91.278 28.381 ;
     RECT  2.268 28.381 91.278 28.453 ;
     RECT  92.556 28.291 94.914 28.453 ;
     RECT  95.724 27.913 96.354 28.453 ;
     RECT  92.556 28.453 96.354 28.561 ;
     RECT  92.052 28.561 96.354 28.831 ;
     RECT  92.052 28.831 96.39 28.921 ;
     RECT  2.232 28.453 91.278 28.993 ;
     RECT  92.052 28.921 96.426 28.993 ;
     RECT  2.232 28.993 96.57 29.461 ;
     RECT  2.232 29.461 97.074 29.605 ;
     RECT  2.232 29.605 97.11 30.125 ;
     RECT  2.232 30.125 95.274 30.317 ;
     RECT  0.108 29.335 0.126 30.721 ;
     RECT  0.108 30.721 0.198 30.839 ;
     RECT  0.144 30.839 0.198 31.147 ;
     RECT  2.232 30.317 95.202 31.451 ;
     RECT  0.144 31.147 0.594 31.469 ;
     RECT  2.304 31.451 95.202 31.487 ;
     RECT  0.144 31.469 0.162 31.901 ;
     RECT  96.264 30.125 97.11 32.107 ;
     RECT  2.304 31.487 44.766 32.269 ;
     RECT  45.504 31.487 95.202 32.269 ;
     RECT  96.192 32.107 97.11 32.333 ;
     RECT  96.264 32.333 97.11 32.525 ;
     RECT  2.304 32.269 95.202 32.621 ;
     RECT  0.18 32.587 0.198 32.765 ;
     RECT  96.264 32.525 97.074 32.813 ;
     RECT  2.304 32.621 95.166 32.881 ;
     RECT  96.264 32.813 96.462 32.909 ;
     RECT  96.3 32.909 96.462 32.999 ;
     RECT  2.268 32.881 95.166 33.005 ;
     RECT  2.304 33.005 94.914 33.101 ;
     RECT  96.336 32.999 96.462 33.643 ;
     RECT  96.336 33.643 96.93 33.655 ;
     RECT  2.304 33.101 94.806 33.809 ;
     RECT  2.304 33.809 94.662 33.917 ;
     RECT  96.336 33.655 97.038 33.925 ;
     RECT  2.304 33.917 94.59 34.027 ;
     RECT  96.336 33.925 97.11 34.051 ;
     RECT  2.268 34.027 94.59 34.115 ;
     RECT  96.336 34.051 97.182 34.123 ;
     RECT  96.3 34.123 97.182 34.349 ;
     RECT  0.144 33.643 0.162 34.363 ;
     RECT  0.144 34.363 0.27 34.507 ;
     RECT  96.876 34.349 97.182 34.541 ;
     RECT  0.144 34.507 0.342 34.591 ;
     RECT  0.108 34.591 0.378 34.637 ;
     RECT  2.268 34.115 35.097 34.699 ;
     RECT  35.964 34.115 94.59 34.727 ;
     RECT  0.144 34.637 0.378 34.733 ;
     RECT  2.196 34.699 35.097 34.861 ;
     RECT  35.964 34.727 94.497 34.861 ;
     RECT  2.196 34.861 94.497 35.033 ;
     RECT  0.144 34.733 0.162 35.261 ;
     RECT  96.912 34.541 97.182 35.275 ;
     RECT  2.196 35.033 65.43 35.371 ;
     RECT  66.24 35.033 94.497 35.509 ;
     RECT  96.3 35.275 97.182 35.563 ;
     RECT  1.728 35.371 65.43 35.573 ;
     RECT  96.264 35.563 97.182 35.659 ;
     RECT  66.24 35.509 94.626 35.699 ;
     RECT  70.488 35.699 94.626 35.755 ;
     RECT  1.728 35.573 65.214 36.391 ;
     RECT  66.24 35.699 69.75 36.391 ;
     RECT  1.728 36.391 69.75 36.481 ;
     RECT  70.488 35.755 94.986 36.481 ;
     RECT  1.728 36.481 94.986 36.545 ;
     RECT  95.94 35.659 97.182 36.689 ;
     RECT  96.048 36.689 97.182 36.851 ;
     RECT  2.268 36.545 94.986 37.319 ;
     RECT  2.34 37.319 94.986 37.427 ;
     RECT  66.168 37.427 94.986 37.867 ;
     RECT  96.048 36.851 97.146 37.975 ;
     RECT  2.34 37.427 65.43 38.209 ;
     RECT  66.168 37.867 95.166 38.209 ;
     RECT  2.34 38.209 95.166 38.245 ;
     RECT  2.304 38.245 95.166 38.579 ;
     RECT  96.048 37.975 97.182 38.939 ;
     RECT  96.264 38.939 97.182 39.119 ;
     RECT  2.34 38.579 95.166 39.245 ;
     RECT  96.3 39.119 97.182 39.659 ;
     RECT  2.376 39.245 95.166 39.749 ;
     RECT  96.84 39.659 97.182 40.019 ;
     RECT  96.912 40.019 97.182 40.163 ;
     RECT  96.912 40.163 97.11 40.289 ;
     RECT  97.092 40.289 97.11 40.469 ;
     RECT  2.376 39.749 94.986 40.559 ;
     RECT  2.376 40.559 94.914 40.837 ;
     RECT  2.304 40.837 94.914 41.021 ;
     RECT  2.376 41.021 94.914 41.171 ;
     RECT  95.796 41.179 95.814 41.377 ;
     RECT  2.415 41.171 94.914 41.449 ;
     RECT  95.796 41.377 95.886 41.449 ;
     RECT  2.415 41.449 95.886 41.683 ;
     RECT  2.415 41.683 95.922 41.953 ;
     RECT  2.415 41.953 96.354 42.151 ;
     RECT  2.376 42.151 96.462 42.295 ;
     RECT  2.304 42.295 96.462 42.365 ;
     RECT  2.376 42.365 96.462 42.493 ;
     RECT  2.376 42.493 96.57 42.989 ;
     RECT  0.108 42.727 0.126 42.997 ;
     RECT  0.108 42.997 0.234 43.003 ;
     RECT  96.336 42.989 96.57 43.085 ;
     RECT  2.376 42.989 95.166 43.141 ;
     RECT  96.372 43.085 96.57 43.141 ;
     RECT  0.108 43.003 0.522 43.181 ;
     RECT  2.34 43.141 95.166 43.181 ;
     RECT  2.34 43.181 94.914 43.373 ;
     RECT  2.34 43.373 94.698 43.387 ;
     RECT  0.108 43.181 0.234 43.661 ;
     RECT  0.18 43.661 0.234 43.757 ;
     RECT  96.372 43.141 97.11 44.041 ;
     RECT  0.216 43.757 0.234 44.141 ;
     RECT  2.304 43.387 94.698 44.213 ;
     RECT  0.144 44.491 0.162 44.669 ;
     RECT  2.304 44.213 11.934 44.959 ;
     RECT  12.708 44.213 94.698 44.959 ;
     RECT  96.3 44.041 97.11 45.067 ;
     RECT  2.304 44.959 94.698 45.301 ;
     RECT  2.304 45.301 94.734 45.571 ;
     RECT  96.264 45.067 97.11 45.725 ;
     RECT  0.324 46.027 0.342 46.157 ;
     RECT  96.264 45.725 97.074 46.229 ;
     RECT  2.304 45.571 94.77 46.265 ;
     RECT  96.876 46.229 97.074 46.769 ;
     RECT  2.304 46.265 94.698 46.805 ;
     RECT  96.876 46.769 97.002 46.877 ;
     RECT  96.948 46.877 97.002 46.949 ;
     RECT  2.304 46.805 94.497 46.987 ;
     RECT  96.948 46.949 96.966 47.039 ;
     RECT  2.268 46.987 94.497 47.345 ;
     RECT  2.304 47.345 94.497 47.579 ;
     RECT  2.304 47.579 26.91 48.361 ;
     RECT  27.684 47.579 94.497 48.361 ;
     RECT  2.304 48.361 94.842 48.433 ;
     RECT  2.304 48.433 95.202 48.505 ;
     RECT  1.98 48.505 95.202 48.507 ;
     RECT  1.977 48.507 95.202 48.541 ;
     RECT  96.48 48.361 96.498 48.541 ;
     RECT  1.977 48.541 96.498 48.703 ;
     RECT  1.977 48.703 97.11 49.032 ;
     RECT  1.98 49.032 97.11 49.037 ;
     RECT  2.268 49.037 97.11 49.919 ;
     RECT  2.304 49.919 97.11 49.981 ;
     RECT  0.108 50.347 0.126 50.477 ;
     RECT  2.304 49.981 97.146 50.585 ;
     RECT  2.34 50.585 97.146 50.774 ;
     RECT  2.34 50.774 97.074 51.355 ;
     RECT  2.304 51.355 97.074 51.437 ;
     RECT  95.76 51.437 97.074 51.511 ;
     RECT  95.76 51.511 97.11 51.725 ;
     RECT  96.012 51.725 97.11 52.205 ;
     RECT  2.304 51.437 94.878 52.267 ;
     RECT  96.3 52.205 97.11 53.035 ;
     RECT  2.304 52.267 94.914 53.131 ;
     RECT  96.048 53.035 97.11 53.131 ;
     RECT  0.144 53.611 0.162 53.635 ;
     RECT  0.144 53.635 0.234 53.707 ;
     RECT  0.144 53.707 0.342 53.803 ;
     RECT  0.108 53.803 0.342 53.897 ;
     RECT  2.304 53.131 97.11 53.905 ;
     RECT  2.196 53.905 97.11 54.077 ;
     RECT  2.268 54.077 97.11 54.365 ;
     RECT  0.18 53.897 0.342 54.413 ;
     RECT  0.18 54.413 0.198 54.557 ;
     RECT  2.304 54.365 97.11 54.607 ;
     RECT  0.144 55.291 0.162 55.387 ;
     RECT  0.144 55.387 0.234 55.525 ;
     RECT  2.304 54.607 97.182 55.561 ;
     RECT  0.108 55.525 0.234 55.565 ;
     RECT  0.144 55.565 0.234 55.579 ;
     RECT  2.232 55.561 97.182 55.613 ;
     RECT  0.144 55.579 0.27 55.627 ;
     RECT  0.144 55.627 0.342 55.723 ;
     RECT  0.144 55.723 0.378 55.853 ;
     RECT  2.304 55.613 97.182 57.115 ;
     RECT  1.728 57.115 97.182 57.443 ;
     RECT  0.144 55.853 0.162 57.451 ;
     RECT  1.728 57.443 94.95 57.569 ;
     RECT  0.144 57.451 0.594 57.835 ;
     RECT  96.012 57.443 97.182 57.947 ;
     RECT  96.912 57.947 97.182 58.109 ;
     RECT  0.108 57.835 0.594 58.157 ;
     RECT  96.912 58.109 96.93 58.379 ;
     RECT  1.728 57.569 94.734 58.415 ;
     RECT  96.012 57.947 96.03 58.559 ;
     RECT  0.576 58.157 0.594 58.955 ;
     RECT  2.304 58.415 94.626 59.765 ;
     RECT  2.34 59.765 94.626 59.837 ;
     RECT  2.376 59.837 94.626 60.143 ;
     RECT  2.376 60.143 94.554 60.571 ;
     RECT  2.34 60.571 94.554 60.655 ;
     RECT  2.304 60.655 94.554 60.889 ;
     RECT  2.304 60.889 94.626 61.223 ;
     RECT  2.34 61.223 94.626 62.203 ;
     RECT  2.304 62.203 94.626 62.311 ;
     RECT  2.304 62.311 94.914 62.537 ;
     RECT  2.304 62.537 94.626 63.113 ;
     RECT  2.304 63.113 94.497 63.689 ;
     RECT  2.34 63.689 94.497 63.959 ;
     RECT  2.376 63.959 94.497 64.391 ;
     RECT  0.144 64.705 0.162 64.867 ;
     RECT  0.108 64.867 0.162 65.069 ;
     RECT  2.415 64.391 94.497 65.227 ;
     RECT  0.144 65.069 0.162 65.357 ;
     RECT  2.304 65.227 94.497 65.551 ;
     RECT  2.304 65.551 94.662 65.899 ;
     RECT  2.268 65.899 94.662 66.125 ;
     RECT  2.268 66.125 6.822 66.515 ;
     RECT  7.632 66.125 94.662 66.623 ;
     RECT  56.088 66.623 94.662 66.749 ;
     RECT  2.304 66.515 6.822 66.901 ;
     RECT  7.632 66.623 55.314 66.901 ;
     RECT  56.088 66.749 94.554 67.019 ;
     RECT  0.324 66.955 0.342 67.051 ;
     RECT  0.144 67.051 0.342 67.085 ;
     RECT  2.304 66.901 55.314 67.289 ;
     RECT  34.2 67.289 55.314 67.405 ;
     RECT  56.088 67.019 94.497 67.405 ;
     RECT  0.144 67.085 0.162 67.661 ;
     RECT  2.304 67.289 33.462 68.011 ;
     RECT  2.268 68.011 33.462 68.135 ;
     RECT  2.304 68.135 33.462 68.251 ;
     RECT  34.2 67.405 94.497 68.251 ;
     RECT  2.304 68.251 94.497 68.521 ;
     RECT  2.304 68.521 94.914 69.521 ;
     RECT  2.304 69.521 94.59 69.773 ;
     RECT  2.34 69.773 94.59 70.267 ;
     RECT  2.34 70.267 94.626 70.529 ;
     RECT  2.34 70.529 94.59 70.637 ;
     RECT  2.34 70.637 94.554 70.871 ;
     RECT  2.376 70.871 94.497 71.995 ;
     RECT  2.34 71.995 94.497 72.029 ;
     RECT  2.412 72.029 94.497 72.391 ;
     RECT  95.796 71.311 95.814 72.463 ;
     RECT  2.412 72.391 94.626 72.535 ;
     RECT  95.796 72.463 96.534 72.571 ;
     RECT  95.724 72.571 96.534 72.661 ;
     RECT  2.412 72.535 94.77 72.841 ;
     RECT  95.724 72.661 96.57 72.931 ;
     RECT  2.412 72.841 94.914 73.291 ;
     RECT  95.724 72.931 97.074 73.291 ;
     RECT  2.412 73.291 97.074 73.381 ;
     RECT  2.376 73.381 97.074 73.454 ;
     RECT  2.376 73.454 94.914 73.483 ;
     RECT  2.304 73.483 94.914 73.769 ;
     RECT  95.724 73.454 97.074 74.083 ;
     RECT  95.724 74.083 97.11 74.189 ;
     RECT  2.34 73.769 94.914 74.345 ;
     RECT  95.724 74.189 97.074 74.573 ;
     RECT  95.724 74.573 97.038 74.669 ;
     RECT  2.412 74.345 94.914 74.765 ;
     RECT  95.724 74.669 96.606 75.053 ;
     RECT  2.412 74.765 94.842 75.307 ;
     RECT  96.264 75.053 96.606 75.533 ;
     RECT  0.108 75.127 0.126 75.629 ;
     RECT  96.3 75.533 96.606 75.703 ;
     RECT  2.304 75.307 94.842 75.739 ;
     RECT  2.268 75.739 94.842 75.775 ;
     RECT  96.3 75.703 97.11 76.013 ;
     RECT  96.3 76.013 96.462 76.109 ;
     RECT  0.144 76.075 0.162 76.363 ;
     RECT  2.268 75.775 95.202 76.363 ;
     RECT  96.3 76.109 96.354 76.363 ;
     RECT  0.144 76.363 0.234 76.396 ;
     RECT  0.144 76.396 0.342 76.459 ;
     RECT  0.108 76.459 0.342 76.589 ;
     RECT  2.268 76.363 96.354 77.081 ;
     RECT  0.108 76.589 0.126 77.357 ;
     RECT  2.268 77.081 95.202 77.729 ;
     RECT  96.3 77.081 96.354 77.851 ;
     RECT  97.092 77.611 97.11 77.851 ;
     RECT  96.3 77.851 97.11 77.933 ;
     RECT  2.304 77.729 95.202 78.029 ;
     RECT  96.3 77.933 97.074 78.091 ;
     RECT  96.264 78.091 97.074 78.379 ;
     RECT  2.304 78.029 94.734 78.629 ;
     RECT  2.304 78.629 94.698 78.763 ;
     RECT  96.228 78.379 97.074 78.955 ;
     RECT  2.268 78.763 94.698 79.321 ;
     RECT  96.228 78.955 97.11 79.531 ;
     RECT  2.196 79.321 94.698 79.583 ;
     RECT  0.144 79.531 0.162 79.709 ;
     RECT  52.272 79.583 94.698 79.723 ;
     RECT  95.688 79.531 97.11 79.723 ;
     RECT  2.196 79.583 51.462 79.757 ;
     RECT  2.268 79.757 51.462 80.519 ;
     RECT  2.268 80.519 48.042 80.555 ;
     RECT  48.96 80.519 51.462 80.671 ;
     RECT  52.272 79.723 97.11 80.671 ;
     RECT  48.96 80.671 97.11 81.059 ;
     RECT  48.96 81.059 94.734 81.445 ;
     RECT  2.268 80.555 47.97 81.571 ;
     RECT  48.78 81.445 94.734 81.571 ;
     RECT  95.688 81.059 97.11 81.599 ;
     RECT  0.108 81.067 0.126 81.725 ;
     RECT  95.688 81.599 96.282 82.247 ;
     RECT  2.268 81.571 94.734 82.445 ;
     RECT  96.228 82.247 96.282 82.651 ;
     RECT  97.056 81.599 97.11 82.651 ;
     RECT  93.744 82.445 94.734 82.723 ;
     RECT  93.744 82.723 94.842 82.831 ;
     RECT  93.744 82.831 95.166 83.101 ;
     RECT  96.228 82.651 97.11 83.101 ;
     RECT  93.744 83.101 97.11 83.191 ;
     RECT  2.268 82.445 92.826 83.335 ;
     RECT  93.636 83.191 97.11 83.335 ;
     RECT  2.268 83.335 97.11 83.789 ;
     RECT  2.268 83.789 96.498 83.867 ;
     RECT  2.304 83.867 96.498 84.269 ;
     RECT  2.304 84.269 95.454 84.335 ;
     RECT  96.3 84.269 96.498 84.653 ;
     RECT  2.376 84.335 95.454 85.003 ;
     RECT  96.3 84.653 96.318 85.003 ;
     RECT  2.376 85.003 96.318 85.081 ;
     RECT  2.34 85.081 96.318 85.459 ;
     RECT  2.304 85.459 96.318 85.483 ;
     RECT  97.092 85.291 97.11 85.483 ;
     RECT  2.304 85.483 97.11 85.517 ;
     RECT  2.34 85.517 97.11 85.621 ;
     RECT  2.34 85.621 97.182 85.721 ;
     RECT  2.376 85.721 97.182 87.269 ;
     RECT  2.376 87.269 96.03 87.403 ;
     RECT  2.304 87.403 96.03 87.499 ;
     RECT  0.108 87.385 0.126 87.595 ;
     RECT  2.268 87.499 96.03 87.647 ;
     RECT  0.108 87.595 0.342 87.725 ;
     RECT  0.108 87.725 0.126 87.917 ;
     RECT  2.304 87.647 96.03 87.917 ;
     RECT  2.304 87.917 95.454 88.349 ;
     RECT  93.996 88.349 94.878 88.421 ;
     RECT  96.876 87.269 97.182 88.529 ;
     RECT  96.876 88.529 97.002 88.619 ;
     RECT  93.996 88.421 94.734 88.655 ;
     RECT  0.144 88.555 0.162 88.733 ;
     RECT  96.876 88.619 96.894 88.889 ;
     RECT  93.996 88.655 94.497 88.925 ;
     RECT  2.304 88.349 92.682 89.035 ;
     RECT  2.268 89.035 92.682 89.239 ;
     RECT  2.268 89.239 92.79 89.429 ;
     RECT  0.18 89.131 0.342 89.453 ;
     RECT  0.324 89.453 0.342 89.741 ;
     RECT  2.268 89.429 92.718 89.969 ;
     RECT  2.268 89.969 92.646 90.187 ;
     RECT  2.232 90.187 92.646 90.239 ;
     RECT  2.232 90.239 91.494 90.347 ;
     RECT  94.215 88.925 94.497 90.355 ;
     RECT  95.436 90.283 95.454 90.355 ;
     RECT  94.215 90.355 95.454 90.553 ;
     RECT  94.215 90.553 96.066 90.571 ;
     RECT  2.304 90.347 91.494 90.815 ;
     RECT  94.14 90.571 96.066 90.895 ;
     RECT  93.6 90.895 96.066 90.931 ;
     RECT  92.736 90.931 92.754 91.021 ;
     RECT  2.376 90.815 91.494 91.057 ;
     RECT  2.376 91.057 91.53 91.157 ;
     RECT  92.592 91.021 92.754 91.165 ;
     RECT  93.528 90.931 96.066 91.165 ;
     RECT  2.376 91.157 91.494 91.193 ;
     RECT  2.415 91.193 91.494 91.319 ;
     RECT  97.164 90.211 97.182 91.435 ;
     RECT  97.02 91.435 97.182 91.597 ;
     RECT  96.948 91.597 97.182 91.669 ;
     RECT  92.592 91.165 96.066 91.741 ;
     RECT  92.304 91.741 96.066 91.867 ;
     RECT  92.268 91.867 96.066 92.011 ;
     RECT  92.196 92.011 96.066 92.245 ;
     RECT  96.876 91.669 97.182 92.245 ;
     RECT  2.415 91.319 91.242 92.281 ;
     RECT  2.415 92.281 91.458 92.435 ;
     RECT  60.048 92.435 91.458 92.443 ;
     RECT  92.196 92.245 97.182 92.443 ;
     RECT  2.415 92.435 59.274 92.491 ;
     RECT  2.376 92.491 59.274 92.975 ;
     RECT  2.376 92.975 42.75 93.047 ;
     RECT  60.048 92.443 97.182 93.047 ;
     RECT  2.415 93.047 42.75 93.209 ;
     RECT  43.632 92.975 59.274 93.253 ;
     RECT  60.048 93.047 79.542 93.253 ;
     RECT  22.464 93.209 42.75 93.757 ;
     RECT  43.632 93.253 79.542 93.757 ;
     RECT  2.415 93.209 21.726 93.793 ;
     RECT  2.34 93.793 21.726 93.979 ;
     RECT  22.464 93.757 79.542 93.979 ;
     RECT  2.34 93.979 79.542 94.091 ;
     RECT  2.415 94.091 79.542 94.127 ;
     RECT  80.388 93.047 97.182 94.171 ;
     RECT  80.28 94.171 97.182 94.261 ;
     RECT  2.415 94.127 79.218 94.289 ;
     RECT  2.415 94.289 79.11 94.325 ;
     RECT  2.415 94.325 78.786 94.397 ;
     RECT  2.415 94.397 78.678 94.469 ;
     RECT  2.415 94.469 24.786 94.559 ;
     RECT  25.632 94.469 78.678 94.559 ;
     RECT  2.415 94.559 9.27 94.595 ;
     RECT  11.232 94.559 20.25 94.595 ;
     RECT  25.632 94.559 30.006 94.595 ;
     RECT  30.744 94.559 78.678 94.595 ;
     RECT  6.3 94.595 9.27 94.631 ;
     RECT  11.232 94.595 11.862 94.631 ;
     RECT  15.696 94.595 20.25 94.631 ;
     RECT  25.632 94.595 29.934 94.631 ;
     RECT  74.988 94.595 78.678 94.631 ;
     RECT  6.3 94.631 9.054 94.667 ;
     RECT  65.736 94.595 73.962 94.667 ;
     RECT  2.415 94.595 5.454 94.685 ;
     RECT  10.044 94.559 10.242 94.685 ;
     RECT  30.744 94.595 64.998 94.685 ;
     RECT  65.736 94.667 72.897 94.685 ;
     RECT  74.988 94.631 76.374 94.685 ;
     RECT  3.924 94.685 5.454 94.703 ;
     RECT  10.044 94.685 10.062 94.703 ;
     RECT  25.632 94.631 29.697 94.703 ;
     RECT  33.336 94.685 37.854 94.703 ;
     RECT  36.036 94.703 37.854 94.733 ;
     RECT  65.88 94.685 72.897 94.733 ;
     RECT  80.136 94.261 97.182 94.733 ;
     RECT  16.632 94.631 20.25 94.739 ;
     RECT  65.88 94.733 67.554 94.739 ;
     RECT  73.62 94.667 73.962 94.739 ;
     RECT  80.136 94.733 95.274 94.781 ;
     RECT  27.936 94.703 29.697 94.787 ;
     RECT  68.508 94.733 72.897 94.787 ;
     RECT  3.96 94.703 5.454 94.829 ;
     RECT  6.48 94.667 9.054 94.829 ;
     RECT  12.996 94.595 14.85 94.829 ;
     RECT  15.696 94.631 15.858 94.829 ;
     RECT  16.704 94.739 20.25 94.829 ;
     RECT  20.988 94.559 24.786 94.829 ;
     RECT  25.632 94.703 27.018 94.829 ;
     RECT  27.936 94.787 29.505 94.829 ;
     RECT  30.744 94.685 32.202 94.829 ;
     RECT  33.336 94.703 35.262 94.829 ;
     RECT  38.772 94.685 64.998 94.829 ;
     RECT  66.024 94.739 67.554 94.829 ;
     RECT  68.508 94.787 72.705 94.829 ;
     RECT  73.62 94.739 73.782 94.829 ;
     RECT  75.42 94.685 76.374 94.829 ;
     RECT  77.58 94.631 78.678 94.829 ;
     RECT  80.136 94.781 94.878 94.829 ;
     RECT  2.415 94.685 3.078 94.865 ;
     RECT  6.48 94.829 8.73 94.865 ;
     RECT  11.808 94.631 11.862 94.865 ;
     RECT  12.996 94.829 13.338 94.865 ;
     RECT  14.616 94.829 14.634 94.865 ;
     RECT  15.696 94.829 15.714 94.865 ;
     RECT  17.208 94.829 17.298 94.865 ;
     RECT  18.072 94.829 18.705 94.865 ;
     RECT  19.584 94.829 19.602 94.865 ;
     RECT  20.988 94.829 21.006 94.865 ;
     RECT  25.848 94.829 26.838 94.865 ;
     RECT  31.68 94.829 32.058 94.865 ;
     RECT  33.336 94.829 33.354 94.865 ;
     RECT  36.036 94.733 37.674 94.865 ;
     RECT  39.168 94.829 41.058 94.865 ;
     RECT  41.796 94.829 42.39 94.865 ;
     RECT  43.164 94.829 53.478 94.865 ;
     RECT  56.268 94.829 58.338 94.865 ;
     RECT  60.372 94.829 60.462 94.865 ;
     RECT  64.44 94.829 64.998 94.865 ;
     RECT  66.024 94.829 66.474 94.865 ;
     RECT  67.215 94.829 67.374 94.865 ;
     RECT  68.508 94.829 68.958 94.865 ;
     RECT  70.884 94.829 71.55 94.865 ;
     RECT  73.62 94.829 73.638 94.865 ;
     RECT  75.42 94.829 75.438 94.865 ;
     RECT  80.136 94.829 84.87 94.865 ;
     RECT  85.716 94.829 89.406 94.865 ;
     RECT  23.436 94.829 24.606 94.877 ;
     RECT  56.268 94.865 58.05 94.877 ;
     RECT  59.472 94.829 59.49 94.877 ;
     RECT  61.2 94.829 63.414 94.877 ;
     RECT  64.98 94.865 64.998 94.877 ;
     RECT  85.932 94.865 87.966 94.877 ;
     RECT  8.712 94.865 8.73 94.901 ;
     RECT  41.04 94.865 41.058 94.901 ;
     RECT  43.164 94.865 43.182 94.901 ;
     RECT  58.032 94.877 58.05 94.901 ;
     RECT  60.444 94.865 60.462 94.901 ;
     RECT  70.884 94.865 70.902 94.901 ;
     RECT  77.58 94.829 78.354 94.901 ;
     RECT  80.388 94.865 83.574 94.901 ;
     RECT  88.74 94.865 89.406 94.901 ;
     RECT  90.288 94.829 93.474 94.901 ;
     RECT  94.215 94.829 94.878 94.901 ;
     RECT  17.244 94.865 17.298 94.937 ;
     RECT  25.848 94.865 26.802 94.937 ;
     RECT  30.744 94.829 30.834 94.937 ;
     RECT  36.54 94.865 37.242 94.937 ;
     RECT  43.992 94.865 49.266 94.937 ;
     RECT  56.268 94.877 57.042 94.937 ;
     RECT  77.616 94.901 78.354 94.937 ;
     RECT  6.48 94.865 7.905 94.973 ;
     RECT  17.244 94.937 17.262 94.973 ;
     RECT  21.96 94.829 21.978 94.973 ;
     RECT  25.848 94.937 25.866 94.973 ;
     RECT  26.784 94.937 26.802 94.973 ;
     RECT  29.016 94.829 29.505 94.973 ;
     RECT  50.436 94.865 53.478 94.973 ;
     RECT  61.2 94.877 62.838 94.973 ;
     RECT  66.456 94.865 66.474 94.973 ;
     RECT  77.616 94.937 78.105 94.973 ;
     RECT  11.844 94.865 11.862 95.009 ;
     RECT  27.936 94.829 27.954 95.009 ;
     RECT  30.816 94.937 30.834 95.009 ;
     RECT  39.168 94.865 40.305 95.009 ;
     RECT  43.992 94.937 44.586 95.009 ;
     RECT  45.432 94.937 49.266 95.009 ;
     RECT  52.452 94.973 53.478 95.009 ;
     RECT  56.415 94.937 57.042 95.009 ;
     RECT  61.2 94.973 61.905 95.009 ;
     RECT  62.82 94.973 62.838 95.009 ;
     RECT  77.724 94.973 78.105 95.009 ;
     RECT  88.815 94.901 89.406 95.009 ;
     RECT  91.44 94.901 93.474 95.009 ;
     RECT  45.432 95.009 48.474 95.021 ;
     RECT  96.336 94.733 97.182 95.021 ;
     RECT  2.415 94.865 2.505 95.057 ;
     RECT  7.815 94.973 7.905 95.057 ;
     RECT  13.215 94.865 13.305 95.057 ;
     RECT  18.615 94.865 18.705 95.057 ;
     RECT  24.015 94.877 24.105 95.057 ;
     RECT  29.415 94.973 29.505 95.057 ;
     RECT  34.815 94.829 34.905 95.057 ;
     RECT  40.032 95.009 40.305 95.057 ;
     RECT  56.415 95.009 56.718 95.057 ;
     RECT  61.815 95.009 61.905 95.057 ;
     RECT  67.215 94.865 67.305 95.057 ;
     RECT  72.615 94.829 72.705 95.057 ;
     RECT  78.015 95.009 78.105 95.057 ;
     RECT  80.388 94.901 83.505 95.057 ;
     RECT  88.815 95.009 88.905 95.057 ;
     RECT  94.215 94.901 94.305 95.057 ;
     RECT  3.96 94.829 4.59 95.099 ;
     RECT  39.168 95.009 39.186 95.099 ;
     RECT  40.032 95.057 40.05 95.099 ;
     RECT  80.388 95.057 83.142 95.099 ;
     RECT  85.932 94.877 87.246 95.099 ;
     RECT  90.288 94.901 90.306 95.099 ;
     RECT  91.512 95.009 92.826 95.099 ;
     RECT  45.432 95.021 48.366 95.117 ;
     RECT  82.548 95.099 83.142 95.135 ;
     RECT  86.328 95.099 86.346 95.135 ;
     RECT  87.228 95.099 87.246 95.135 ;
     RECT  91.512 95.099 92.394 95.135 ;
     RECT  45.432 95.117 46.998 95.165 ;
     RECT  47.772 95.117 48.366 95.165 ;
     RECT  50.436 94.973 51.534 95.165 ;
     RECT  52.884 95.009 53.478 95.165 ;
     RECT  81.108 95.099 81.63 95.171 ;
     RECT  82.548 95.135 82.566 95.171 ;
     RECT  84.852 94.865 84.87 95.171 ;
     RECT  91.512 95.135 92.106 95.171 ;
     RECT  96.372 95.021 97.182 95.309 ;
     RECT  96.408 95.309 97.182 95.477 ;
     RECT  96.408 95.477 97.11 95.501 ;
     RECT  96.408 95.501 97.074 95.693 ;
     RECT  48.132 95.165 48.366 95.741 ;
     RECT  54.72 94.829 55.134 95.741 ;
     RECT  50.436 95.165 50.598 95.789 ;
     RECT  97.056 95.693 97.074 95.789 ;
     RECT  92.088 95.171 92.106 95.885 ;
     RECT  48.24 95.741 48.366 96.317 ;
     RECT  45.432 95.165 45.45 96.365 ;
     RECT  46.98 95.165 46.998 96.365 ;
     RECT  50.58 95.789 50.598 96.365 ;
     RECT  51.444 95.165 51.534 96.365 ;
     RECT  51.516 96.365 51.534 96.893 ;
     RECT  53.784 96.907 53.802 96.955 ;
     RECT  49.248 95.009 49.266 97.037 ;
     RECT  53.784 96.955 53.946 97.037 ;
     RECT  56.7 95.057 56.718 97.037 ;
     RECT  47.34 96.955 47.358 97.085 ;
     RECT  48.24 96.317 48.258 97.085 ;
     RECT  51.84 96.955 51.858 97.085 ;
     RECT  52.668 96.955 52.938 97.085 ;
     RECT  53.928 97.037 53.946 97.085 ;
     RECT  54.72 95.741 54.738 97.085 ;
    LAYER M4 ;
     RECT  0.06 50.352 0.097 50.376 ;
     RECT  0.06 51.984 0.097 58.056 ;
     RECT  0.06 75.12 0.097 81.096 ;
     RECT  0.06 4.368 0.133 7.368 ;
     RECT  0.06 10.512 0.133 13.512 ;
     RECT  0.06 29.712 0.133 35.784 ;
     RECT  0.06 42.864 0.133 49.032 ;
     RECT  0.097 50.352 0.133 50.472 ;
     RECT  0.097 51.984 0.133 58.152 ;
     RECT  0.06 87.312 0.133 90.312 ;
     RECT  0.06 65.04 0.137 68.04 ;
     RECT  0.133 3.408 0.181 7.368 ;
     RECT  0.133 8.544 0.181 8.568 ;
     RECT  0.133 9.648 0.181 14.28 ;
     RECT  0.133 29.712 0.181 36.552 ;
     RECT  0.133 42.72 0.181 58.152 ;
     RECT  0.097 75.12 0.181 81.72 ;
     RECT  0.181 74.592 0.227 81.72 ;
     RECT  0.181 3.312 0.229 7.368 ;
     RECT  0.181 8.544 0.229 14.28 ;
     RECT  0.133 28.464 0.229 28.488 ;
     RECT  0.181 29.616 0.229 37.128 ;
     RECT  0.133 60.768 0.229 60.792 ;
     RECT  0.137 65.136 0.229 68.04 ;
     RECT  0.181 82.944 0.229 82.968 ;
     RECT  0.229 8.544 0.277 15.24 ;
     RECT  0.229 28.464 0.277 37.128 ;
     RECT  0.277 8.544 0.325 15.48 ;
     RECT  0.229 40.944 0.325 40.968 ;
     RECT  0.181 41.952 0.325 58.728 ;
     RECT  0.277 28.272 0.373 37.128 ;
     RECT  0.325 40.944 0.373 59.304 ;
     RECT  0.373 40.848 0.421 59.304 ;
     RECT  0.133 73.488 0.517 73.512 ;
     RECT  0.229 82.704 2.257 82.968 ;
     RECT  0.229 3.312 2.293 7.464 ;
     RECT  0.325 8.544 2.293 15.576 ;
     RECT  0.373 27.312 2.293 37.128 ;
     RECT  0.421 40.656 2.293 59.304 ;
     RECT  0.229 60.768 2.293 61.128 ;
     RECT  0.229 65.136 2.293 68.424 ;
     RECT  0.517 73.296 2.293 73.512 ;
     RECT  0.227 74.592 2.293 81.624 ;
     RECT  2.257 82.704 2.293 83.304 ;
     RECT  2.293 3.312 2.329 15.768 ;
     RECT  2.293 16.8 2.329 16.824 ;
     RECT  2.293 27.264 2.329 37.128 ;
     RECT  2.293 40.56 2.329 61.128 ;
     RECT  2.329 3.312 2.365 16.824 ;
     RECT  2.293 70.8 2.365 70.824 ;
     RECT  2.293 72 2.365 72.024 ;
     RECT  2.293 85.488 2.365 85.512 ;
     RECT  2.329 40.56 2.401 61.704 ;
     RECT  2.365 70.8 2.401 72.024 ;
     RECT  2.293 73.296 2.401 81.624 ;
     RECT  0.133 86.592 2.401 90.648 ;
     RECT  2.365 3.312 2.408 17.64 ;
     RECT  2.365 24.912 2.408 24.936 ;
     RECT  2.329 27.264 2.408 37.416 ;
     RECT  2.401 39.792 2.408 61.704 ;
     RECT  2.293 63.264 2.408 63.816 ;
     RECT  2.293 65.136 2.408 69.768 ;
     RECT  2.401 70.8 2.408 81.624 ;
     RECT  2.293 82.704 2.408 83.832 ;
     RECT  2.365 85.392 2.408 85.512 ;
     RECT  2.401 86.544 2.408 90.648 ;
     RECT  2.365 92.496 2.408 92.52 ;
     RECT  2.293 93.504 2.408 93.528 ;
     RECT  2.408 2.148 2.512 95.052 ;
     RECT  2.512 2.418 2.704 94.782 ;
     RECT  2.704 2.592 3.925 94.68 ;
     RECT  3.925 2.208 4.025 94.68 ;
     RECT  4.025 2.208 5.173 94.584 ;
     RECT  5.173 2.16 5.321 94.584 ;
     RECT  5.321 2.16 6.131 94.104 ;
     RECT  6.131 2.208 7.808 94.104 ;
     RECT  7.808 2.148 7.912 95.052 ;
     RECT  7.912 2.418 8.104 94.782 ;
     RECT  8.104 2.592 9.313 93.624 ;
     RECT  8.104 94.656 9.313 94.68 ;
     RECT  9.313 2.592 9.349 94.68 ;
     RECT  9.349 2.256 9.893 94.68 ;
     RECT  9.893 2.592 13.208 94.68 ;
     RECT  13.208 2.148 13.312 95.052 ;
     RECT  13.312 2.418 13.504 94.782 ;
     RECT  13.504 2.592 14.821 94.68 ;
     RECT  14.821 2.304 15.221 94.824 ;
     RECT  15.221 2.544 15.905 94.824 ;
     RECT  15.905 2.592 18.349 94.824 ;
     RECT  18.349 2.496 18.608 94.824 ;
     RECT  18.608 2.148 18.712 95.052 ;
     RECT  18.712 2.418 18.904 94.824 ;
     RECT  18.904 2.496 21.085 94.824 ;
     RECT  21.085 2.448 21.197 94.824 ;
     RECT  21.197 2.448 23.425 94.68 ;
     RECT  23.425 2.448 24.008 94.872 ;
     RECT  24.008 2.148 24.112 95.052 ;
     RECT  24.112 2.418 24.304 94.872 ;
     RECT  24.304 2.496 24.617 94.872 ;
     RECT  24.617 2.496 25.837 94.68 ;
     RECT  25.837 2.496 26.813 94.968 ;
     RECT  26.813 2.496 26.921 94.68 ;
     RECT  26.921 2.496 27.421 13.464 ;
     RECT  27.421 2.208 28.141 13.464 ;
     RECT  26.921 14.448 28.141 94.68 ;
     RECT  28.141 2.208 28.181 94.68 ;
     RECT  28.181 2.208 28.217 62.856 ;
     RECT  28.217 62.784 28.307 62.856 ;
     RECT  28.217 2.208 29.269 61.752 ;
     RECT  28.307 62.832 29.269 62.856 ;
     RECT  29.269 2.208 29.408 62.856 ;
     RECT  28.181 64.128 29.408 94.68 ;
     RECT  29.408 2.148 29.512 95.052 ;
     RECT  29.512 2.352 29.704 94.782 ;
     RECT  29.704 2.352 30.769 63 ;
     RECT  29.704 64.032 30.769 94.68 ;
     RECT  30.769 2.352 30.805 94.68 ;
     RECT  30.805 2.352 30.841 94.728 ;
     RECT  30.841 2.352 31.637 94.776 ;
     RECT  31.637 2.448 33.473 94.776 ;
     RECT  33.473 2.448 34.808 94.68 ;
     RECT  34.808 2.148 34.912 95.052 ;
     RECT  34.912 2.418 35.104 94.782 ;
     RECT  35.104 16.08 35.267 94.68 ;
     RECT  35.267 16.272 35.741 94.68 ;
     RECT  35.104 2.496 36.421 15.048 ;
     RECT  35.741 16.272 36.421 75.528 ;
     RECT  36.421 2.496 36.781 75.528 ;
     RECT  35.741 76.56 36.781 94.68 ;
     RECT  36.781 2.496 37.361 94.68 ;
     RECT  37.361 2.496 37.379 30.648 ;
     RECT  37.379 2.496 37.433 15 ;
     RECT  37.361 31.632 37.825 94.68 ;
     RECT  37.379 15.984 38.195 30.648 ;
     RECT  38.195 16.608 38.437 30.648 ;
     RECT  37.825 31.632 38.437 94.728 ;
     RECT  38.437 16.608 38.773 94.728 ;
     RECT  38.773 16.608 38.909 94.776 ;
     RECT  37.433 14.496 39.013 15 ;
     RECT  39.013 14.496 39.157 15.432 ;
     RECT  38.909 16.608 39.157 89.256 ;
     RECT  37.433 2.496 39.337 13.464 ;
     RECT  38.909 90.336 39.373 94.776 ;
     RECT  39.157 14.496 39.913 89.256 ;
     RECT  39.373 90.336 39.913 94.872 ;
     RECT  39.337 2.256 39.973 13.464 ;
     RECT  39.913 14.496 39.973 94.872 ;
     RECT  39.973 2.256 40.208 94.872 ;
     RECT  40.208 2.148 40.312 95.052 ;
     RECT  40.312 2.208 40.504 94.872 ;
     RECT  40.504 2.208 41.249 90.696 ;
     RECT  40.504 91.68 41.507 94.872 ;
     RECT  41.249 20.208 41.641 90.696 ;
     RECT  41.507 91.68 41.641 94.68 ;
     RECT  41.641 20.208 41.891 94.68 ;
     RECT  41.249 2.208 42.401 18.984 ;
     RECT  42.401 2.496 42.757 18.984 ;
     RECT  41.891 20.208 42.757 92.904 ;
     RECT  42.757 2.496 42.797 92.904 ;
     RECT  42.797 2.544 42.937 92.904 ;
     RECT  41.891 94.272 42.937 94.68 ;
     RECT  42.937 2.544 43.187 94.68 ;
     RECT  43.187 94.656 43.193 94.68 ;
     RECT  43.187 2.544 43.409 93.576 ;
     RECT  43.409 2.592 44.245 93.576 ;
     RECT  44.245 2.592 44.629 94.152 ;
     RECT  44.629 2.592 45.608 94.68 ;
     RECT  45.608 2.148 45.712 95.052 ;
     RECT  45.421 96.336 45.875 96.36 ;
     RECT  45.712 2.418 45.904 95.052 ;
     RECT  45.904 2.592 45.925 95.052 ;
     RECT  46.969 96.336 47.125 96.36 ;
     RECT  47.125 96.336 47.219 97.032 ;
     RECT  47.219 96.96 47.329 97.032 ;
     RECT  45.925 2.592 48.121 95.16 ;
     RECT  48.121 2.592 48.179 95.736 ;
     RECT  47.329 96.96 48.275 97.08 ;
     RECT  48.275 96.96 48.325 97.032 ;
     RECT  48.325 96.288 48.377 97.032 ;
     RECT  48.179 2.592 48.755 95.016 ;
     RECT  48.377 97.008 49.277 97.032 ;
     RECT  48.755 2.592 50.437 94.776 ;
     RECT  50.425 95.76 50.437 95.784 ;
     RECT  50.437 2.592 50.569 95.784 ;
     RECT  50.245 97.008 50.569 97.032 ;
     RECT  50.569 2.592 50.867 97.032 ;
     RECT  50.867 2.592 51.005 95.16 ;
     RECT  51.005 2.592 51.008 95.052 ;
     RECT  51.008 2.148 51.112 95.052 ;
     RECT  51.112 2.418 51.304 94.92 ;
     RECT  50.867 96.336 51.539 97.032 ;
     RECT  51.539 96.864 51.781 97.032 ;
     RECT  51.304 2.592 52.451 94.92 ;
     RECT  51.781 96.864 52.549 97.08 ;
     RECT  52.451 64.608 52.741 94.92 ;
     RECT  52.451 2.592 52.769 63.624 ;
     RECT  52.549 96.816 53.029 97.08 ;
     RECT  52.741 64.608 53.489 95.16 ;
     RECT  52.769 2.592 53.881 63.528 ;
     RECT  53.029 96.72 54.131 97.08 ;
     RECT  53.881 2.256 54.133 63.528 ;
     RECT  54.131 97.008 54.749 97.08 ;
     RECT  53.489 64.704 54.757 94.92 ;
     RECT  54.133 2.256 54.893 63.72 ;
     RECT  54.757 64.704 55.145 95.736 ;
     RECT  54.893 2.592 55.429 63.72 ;
     RECT  55.145 64.704 55.429 94.92 ;
     RECT  55.429 2.592 56.408 94.92 ;
     RECT  56.408 2.148 56.512 95.052 ;
     RECT  54.749 97.008 56.729 97.032 ;
     RECT  56.512 2.304 56.873 94.92 ;
     RECT  56.873 73.296 56.963 94.92 ;
     RECT  56.963 93.216 57.053 94.92 ;
     RECT  57.053 94.656 57.521 94.872 ;
     RECT  56.873 2.304 57.953 72.312 ;
     RECT  57.953 2.592 58.025 72.312 ;
     RECT  57.053 93.216 58.313 93.336 ;
     RECT  56.963 73.296 58.453 91.992 ;
     RECT  58.313 93.216 58.453 93.24 ;
     RECT  58.025 33.312 58.813 72.312 ;
     RECT  58.453 73.296 58.813 93.24 ;
     RECT  58.813 33.312 59.177 93.24 ;
     RECT  59.177 61.152 59.321 93.24 ;
     RECT  59.321 61.44 59.461 93.24 ;
     RECT  57.521 94.848 59.501 94.872 ;
     RECT  58.025 2.592 59.677 32.328 ;
     RECT  59.177 33.312 59.677 60.12 ;
     RECT  59.677 2.592 60.113 60.12 ;
     RECT  60.113 43.056 60.397 60.12 ;
     RECT  59.461 61.44 60.397 93.384 ;
     RECT  60.397 43.056 60.545 93.384 ;
     RECT  60.113 2.592 61.117 42.072 ;
     RECT  60.545 43.056 61.117 93 ;
     RECT  61.117 2.592 61.808 93 ;
     RECT  61.045 94.032 61.808 94.296 ;
     RECT  61.808 2.148 61.912 95.052 ;
     RECT  61.912 2.352 62.104 94.782 ;
     RECT  62.104 2.352 63.241 90.648 ;
     RECT  62.104 91.632 63.241 94.056 ;
     RECT  63.241 2.352 63.385 94.056 ;
     RECT  63.385 2.352 64.285 94.872 ;
     RECT  64.285 2.256 64.355 94.872 ;
     RECT  64.355 2.352 64.541 94.872 ;
     RECT  64.541 2.352 64.937 63.624 ;
     RECT  64.541 64.704 65.009 94.872 ;
     RECT  64.937 33.36 65.545 63.624 ;
     RECT  65.009 64.704 65.545 94.68 ;
     RECT  65.545 33.36 65.765 94.68 ;
     RECT  64.937 2.352 65.905 32.328 ;
     RECT  65.905 2.256 66.013 32.328 ;
     RECT  65.765 33.36 66.013 94.344 ;
     RECT  66.013 2.256 67.208 94.344 ;
     RECT  67.208 2.148 67.312 95.052 ;
     RECT  67.312 2.352 67.504 94.782 ;
     RECT  67.504 2.352 67.745 42.072 ;
     RECT  67.745 2.592 68.725 42.072 ;
     RECT  67.504 43.056 68.725 94.728 ;
     RECT  68.725 2.592 69.005 94.728 ;
     RECT  69.005 2.592 69.329 60.168 ;
     RECT  69.005 61.248 69.395 94.536 ;
     RECT  69.395 61.44 69.779 94.536 ;
     RECT  69.779 92.208 70.549 94.536 ;
     RECT  69.779 61.44 70.873 91.176 ;
     RECT  70.549 92.208 70.873 94.632 ;
     RECT  69.329 2.592 71.197 60.12 ;
     RECT  70.873 61.44 71.197 94.632 ;
     RECT  71.197 2.592 71.413 94.632 ;
     RECT  71.413 2.304 72.608 94.632 ;
     RECT  72.608 2.148 72.712 95.052 ;
     RECT  72.712 2.304 72.904 94.782 ;
     RECT  72.904 2.304 73.073 94.584 ;
     RECT  73.073 2.832 73.505 94.584 ;
     RECT  73.505 2.832 74.581 94.296 ;
     RECT  74.581 2.784 74.977 94.344 ;
     RECT  74.977 2.784 75.827 94.68 ;
     RECT  75.827 2.784 75.877 94.488 ;
     RECT  75.877 2.256 75.881 94.488 ;
     RECT  75.881 2.256 75.923 59.592 ;
     RECT  75.923 2.784 76.745 59.592 ;
     RECT  75.881 60.72 76.993 94.488 ;
     RECT  76.745 18.576 77.065 59.592 ;
     RECT  76.993 60.624 77.065 94.488 ;
     RECT  76.745 2.784 77.845 17.496 ;
     RECT  77.065 18.576 77.845 94.488 ;
     RECT  77.845 2.784 78.008 94.488 ;
     RECT  78.008 2.148 78.112 95.052 ;
     RECT  78.112 2.256 78.304 94.782 ;
     RECT  78.304 2.256 78.803 93.24 ;
     RECT  78.803 3.312 78.869 93.24 ;
     RECT  78.803 2.256 79.049 2.28 ;
     RECT  78.869 3.408 79.873 93.24 ;
     RECT  79.873 2.304 80.377 93.24 ;
     RECT  80.125 94.272 80.377 94.296 ;
     RECT  80.377 2.304 80.989 94.296 ;
     RECT  80.989 2.304 81.065 94.68 ;
     RECT  81.065 2.4 81.683 94.68 ;
     RECT  81.683 2.4 82.069 93.24 ;
     RECT  81.683 94.272 82.361 94.68 ;
     RECT  82.069 2.256 82.825 93.24 ;
     RECT  82.825 2.256 83.041 93.288 ;
     RECT  82.361 94.272 83.041 94.344 ;
     RECT  83.041 2.256 83.173 94.344 ;
     RECT  83.173 2.064 83.221 94.344 ;
     RECT  83.221 1.968 83.408 94.344 ;
     RECT  83.408 1.968 83.512 95.052 ;
     RECT  83.512 1.968 83.704 94.782 ;
     RECT  83.269 0.096 83.797 0.12 ;
     RECT  83.797 0.096 83.833 0.504 ;
     RECT  83.833 0.096 83.909 0.6 ;
     RECT  83.704 1.968 83.945 94.152 ;
     RECT  83.909 0.48 83.987 0.6 ;
     RECT  83.987 0.48 84.371 0.504 ;
     RECT  83.945 1.968 84.377 94.056 ;
     RECT  84.377 1.968 84.709 70.776 ;
     RECT  84.709 1.728 84.773 70.776 ;
     RECT  84.377 71.856 84.913 94.056 ;
     RECT  84.901 0.144 85.091 0.264 ;
     RECT  85.091 0.24 85.139 0.264 ;
     RECT  84.773 1.728 85.277 50.088 ;
     RECT  84.913 71.856 85.417 94.344 ;
     RECT  84.773 51.216 85.489 70.776 ;
     RECT  85.417 71.856 85.489 94.584 ;
     RECT  85.277 2.16 85.763 50.088 ;
     RECT  85.489 51.216 85.849 94.584 ;
     RECT  85.763 2.256 85.907 50.088 ;
     RECT  85.849 51.216 85.961 94.68 ;
     RECT  85.907 2.304 86.029 50.088 ;
     RECT  86.029 2.304 86.389 50.232 ;
     RECT  85.961 51.216 86.389 94.584 ;
     RECT  86.053 0.096 86.437 0.12 ;
     RECT  86.389 2.304 86.681 94.584 ;
     RECT  86.681 80.592 86.753 94.584 ;
     RECT  86.437 0.096 86.771 0.36 ;
     RECT  86.681 2.304 86.825 79.608 ;
     RECT  86.771 0.336 86.915 0.36 ;
     RECT  86.825 2.304 86.969 27.192 ;
     RECT  86.969 2.304 87.001 27.144 ;
     RECT  86.753 80.592 87.257 94.392 ;
     RECT  86.825 28.656 87.685 79.608 ;
     RECT  87.257 80.592 87.685 91.176 ;
     RECT  87.877 0.144 87.925 0.168 ;
     RECT  87.257 92.736 87.937 94.392 ;
     RECT  87.685 28.656 88.081 91.176 ;
     RECT  87.001 2.208 88.117 27.144 ;
     RECT  88.117 2.16 88.261 27.144 ;
     RECT  88.261 2.16 88.477 27.384 ;
     RECT  88.081 28.56 88.477 91.176 ;
     RECT  87.925 0.144 88.693 0.264 ;
     RECT  88.477 2.16 88.765 91.176 ;
     RECT  88.765 2.16 88.808 91.656 ;
     RECT  87.937 92.736 88.808 94.872 ;
     RECT  88.808 2.148 88.912 95.052 ;
     RECT  88.693 0.144 88.933 0.312 ;
     RECT  88.912 2.148 89.029 94.872 ;
     RECT  89.029 1.728 89.104 94.872 ;
     RECT  88.933 0.144 89.125 0.456 ;
     RECT  89.125 0.144 89.221 0.552 ;
     RECT  89.104 92.784 89.237 94.872 ;
     RECT  89.221 0.096 89.315 0.552 ;
     RECT  89.315 0.096 89.363 0.456 ;
     RECT  89.104 28.752 89.489 91.128 ;
     RECT  89.489 29.04 90.029 91.128 ;
     RECT  89.104 1.728 90.169 23.4 ;
     RECT  89.104 24.384 90.169 27.72 ;
     RECT  90.029 29.04 90.173 89.928 ;
     RECT  90.169 1.728 90.281 27.72 ;
     RECT  90.281 1.728 90.323 23.736 ;
     RECT  90.323 1.728 90.353 23.4 ;
     RECT  90.281 24.72 90.457 27.72 ;
     RECT  90.173 29.04 90.457 89.448 ;
     RECT  89.363 0.096 90.467 0.216 ;
     RECT  90.029 91.104 90.497 91.128 ;
     RECT  89.237 93.024 90.529 94.872 ;
     RECT  90.467 0.144 90.533 0.216 ;
     RECT  90.529 92.112 90.641 94.872 ;
     RECT  90.457 24.72 90.677 89.448 ;
     RECT  90.677 26.4 90.713 27.048 ;
     RECT  90.677 28.56 90.713 89.448 ;
     RECT  90.713 26.4 90.749 26.76 ;
     RECT  90.713 28.56 90.821 86.76 ;
     RECT  90.641 92.112 90.821 94.728 ;
     RECT  90.821 54.624 90.929 86.76 ;
     RECT  90.677 24.72 91.001 24.744 ;
     RECT  90.821 28.56 91.001 53.4 ;
     RECT  90.821 93.024 91.001 94.728 ;
     RECT  90.533 0.144 91.037 0.168 ;
     RECT  90.929 57.696 91.037 86.76 ;
     RECT  90.353 2.256 91.109 23.4 ;
     RECT  91.001 29.04 91.181 53.4 ;
     RECT  91.109 2.256 91.187 22.2 ;
     RECT  91.187 2.256 91.253 19.992 ;
     RECT  91.181 39.888 91.253 53.4 ;
     RECT  91.109 23.376 91.285 23.4 ;
     RECT  91.037 59.712 91.289 86.76 ;
     RECT  91.253 2.256 91.325 17.592 ;
     RECT  91.253 18.576 91.325 19.992 ;
     RECT  91.325 2.256 91.331 17.4 ;
     RECT  91.181 29.04 91.361 38.76 ;
     RECT  91.037 57.696 91.361 58.68 ;
     RECT  91.289 59.712 91.361 78.648 ;
     RECT  91.331 2.352 91.433 17.4 ;
     RECT  90.749 26.64 91.433 26.76 ;
     RECT  91.361 77.856 91.433 78.648 ;
     RECT  91.361 57.84 91.469 58.68 ;
     RECT  91.289 79.776 91.475 86.76 ;
     RECT  91.361 59.712 91.577 76.872 ;
     RECT  91.187 21.072 91.613 22.2 ;
     RECT  91.325 18.624 91.649 19.992 ;
     RECT  90.713 87.792 91.649 89.448 ;
     RECT  91.577 59.712 91.667 73.416 ;
     RECT  91.475 79.776 91.685 83.4 ;
     RECT  91.475 84.384 91.685 86.376 ;
     RECT  91.649 87.792 91.685 88.872 ;
     RECT  91.577 74.4 91.715 75.864 ;
     RECT  91.433 15.36 91.757 17.4 ;
     RECT  90.929 54.624 91.763 56.472 ;
     RECT  91.685 81.408 91.763 81.432 ;
     RECT  91.649 18.72 91.793 19.992 ;
     RECT  91.361 29.04 91.793 38.664 ;
     RECT  91.685 79.776 91.793 80.28 ;
     RECT  91.433 26.736 91.829 26.76 ;
     RECT  91.253 39.888 91.829 52.728 ;
     RECT  91.793 79.776 91.829 79.8 ;
     RECT  91.685 85.872 91.829 86.376 ;
     RECT  91.757 15.36 91.865 17.352 ;
     RECT  91.613 21.648 91.865 22.2 ;
     RECT  91.793 29.376 91.865 38.664 ;
     RECT  91.829 39.888 91.865 50.136 ;
     RECT  91.715 74.4 91.865 75.432 ;
     RECT  91.763 54.624 91.897 55.752 ;
     RECT  91.865 74.4 91.901 74.616 ;
     RECT  91.685 82.512 91.901 83.4 ;
     RECT  91.865 45.936 91.937 50.136 ;
     RECT  91.469 57.936 91.937 58.68 ;
     RECT  91.901 82.848 91.937 83.4 ;
     RECT  91.829 85.92 91.937 86.376 ;
     RECT  91.865 29.376 91.973 38.232 ;
     RECT  91.685 84.384 91.973 84.84 ;
     RECT  91.865 40.992 92.003 44.856 ;
     RECT  91.973 29.376 92.009 31.176 ;
     RECT  91.937 45.936 92.009 49.608 ;
     RECT  92.005 90.048 92.051 90.072 ;
     RECT  91.901 74.592 92.081 74.616 ;
     RECT  91.937 82.848 92.081 83.208 ;
     RECT  91.685 87.888 92.081 88.872 ;
     RECT  91.001 93.072 92.113 94.728 ;
     RECT  92.077 95.856 92.113 95.88 ;
     RECT  92.081 87.888 92.117 88.776 ;
     RECT  92.003 40.992 92.153 44.232 ;
     RECT  91.973 84.384 92.189 84.408 ;
     RECT  91.793 19.44 92.225 19.464 ;
     RECT  91.865 15.36 92.261 17.064 ;
     RECT  92.009 46.176 92.261 49.608 ;
     RECT  91.667 59.712 92.297 72.984 ;
     RECT  92.261 15.36 92.333 17.016 ;
     RECT  92.153 44.016 92.369 44.232 ;
     RECT  91.829 51.36 92.401 52.728 ;
     RECT  91.973 32.208 92.441 38.232 ;
     RECT  91.433 2.352 92.473 14.328 ;
     RECT  92.333 16.032 92.477 17.016 ;
     RECT  91.285 23.376 92.477 24.168 ;
     RECT  92.081 83.184 92.513 83.208 ;
     RECT  92.477 16.032 92.549 16.536 ;
     RECT  92.297 59.712 92.549 71.832 ;
     RECT  91.937 57.984 92.581 58.68 ;
     RECT  92.549 59.712 92.581 67.56 ;
     RECT  92.261 46.272 92.621 49.608 ;
     RECT  92.581 57.984 92.621 67.56 ;
     RECT  91.433 78.24 92.653 78.648 ;
     RECT  92.113 93.072 92.653 95.88 ;
     RECT  92.369 44.016 92.657 44.04 ;
     RECT  92.117 87.888 92.693 87.912 ;
     RECT  92.473 2.352 92.725 14.904 ;
     RECT  92.009 30.288 92.729 31.176 ;
     RECT  91.865 39.888 92.729 39.912 ;
     RECT  92.621 47.136 92.765 49.608 ;
     RECT  92.153 40.992 92.801 42.216 ;
     RECT  92.297 72.96 92.801 72.984 ;
     RECT  92.801 42.192 92.837 42.216 ;
     RECT  92.621 58.368 92.837 67.56 ;
     RECT  92.765 47.136 92.873 48.168 ;
     RECT  92.765 49.584 92.873 49.608 ;
     RECT  92.801 40.992 92.909 41.016 ;
     RECT  92.837 58.368 92.915 59.208 ;
     RECT  92.441 32.304 92.945 38.232 ;
     RECT  92.837 61.056 92.981 67.416 ;
     RECT  92.549 68.688 92.981 71.832 ;
     RECT  92.981 62.256 93.017 67.416 ;
     RECT  92.653 77.856 93.017 78.648 ;
     RECT  93.017 64.416 93.059 67.416 ;
     RECT  93.059 66.672 93.089 67.416 ;
     RECT  92.981 68.688 93.125 70.728 ;
     RECT  92.915 58.56 93.197 59.064 ;
     RECT  92.981 61.056 93.197 61.08 ;
     RECT  93.059 64.416 93.197 65.592 ;
     RECT  92.725 2.256 93.301 14.904 ;
     RECT  92.653 92.4 93.337 95.88 ;
     RECT  92.401 51.36 93.481 52.824 ;
     RECT  91.897 53.952 93.481 55.752 ;
     RECT  91.577 76.848 93.481 76.872 ;
     RECT  93.017 77.856 93.481 78.6 ;
     RECT  93.337 92.16 93.553 95.88 ;
     RECT  93.481 51.36 93.625 55.752 ;
     RECT  92.729 31.152 93.661 31.176 ;
     RECT  92.945 32.304 93.661 37.608 ;
     RECT  93.301 2.064 93.829 14.904 ;
     RECT  93.829 2.016 93.925 14.904 ;
     RECT  93.949 29.04 94.069 29.064 ;
     RECT  93.781 90.576 94.165 90.6 ;
     RECT  93.553 91.632 94.165 95.88 ;
     RECT  93.925 1.968 94.208 14.904 ;
     RECT  91.865 21.648 94.208 21.672 ;
     RECT  92.477 24.144 94.208 24.168 ;
     RECT  94.069 29.04 94.208 29.88 ;
     RECT  93.661 31.152 94.208 37.608 ;
     RECT  92.873 47.28 94.208 48.168 ;
     RECT  93.625 50.832 94.208 55.752 ;
     RECT  93.197 58.656 94.208 59.064 ;
     RECT  93.017 62.256 94.208 63.048 ;
     RECT  93.197 64.416 94.208 64.44 ;
     RECT  93.197 65.568 94.208 65.592 ;
     RECT  93.089 66.768 94.208 67.416 ;
     RECT  93.125 68.688 94.208 68.712 ;
     RECT  93.125 69.696 94.208 70.728 ;
     RECT  92.981 71.808 94.208 71.832 ;
     RECT  93.985 73.296 94.208 73.32 ;
     RECT  93.481 76.848 94.208 78.6 ;
     RECT  91.937 86.016 94.208 86.04 ;
     RECT  94.165 90.576 94.208 95.88 ;
     RECT  94.208 1.968 94.504 95.88 ;
     RECT  94.504 1.968 94.601 2.28 ;
     RECT  94.504 57.12 94.637 57.144 ;
     RECT  94.504 27.984 94.691 28.008 ;
     RECT  94.504 3.888 94.709 8.52 ;
     RECT  94.504 82.992 94.709 84.936 ;
     RECT  94.504 11.424 94.745 11.496 ;
     RECT  94.504 15.552 94.781 17.832 ;
     RECT  94.745 11.424 94.817 11.448 ;
     RECT  94.504 91.152 94.817 95.88 ;
     RECT  94.709 3.888 94.925 7.656 ;
     RECT  94.504 49.776 94.925 55.848 ;
     RECT  94.817 91.152 94.931 91.368 ;
     RECT  94.504 10.32 95.027 10.344 ;
     RECT  94.931 91.344 95.033 91.368 ;
     RECT  94.504 73.296 95.105 78.456 ;
     RECT  94.601 2.256 95.171 2.28 ;
     RECT  94.925 3.888 95.171 7.464 ;
     RECT  94.504 79.728 95.677 79.752 ;
     RECT  94.709 83.856 95.677 84.936 ;
     RECT  95.677 79.536 95.713 79.752 ;
     RECT  95.677 83.856 95.713 85.224 ;
     RECT  94.504 42.288 95.749 43.368 ;
     RECT  94.925 49.776 95.749 51.72 ;
     RECT  95.713 83.856 95.749 86.184 ;
     RECT  94.781 16.368 96.001 17.832 ;
     RECT  95.749 49.68 96.001 51.72 ;
     RECT  94.925 53.136 96.001 55.848 ;
     RECT  94.504 29.136 96.037 35.784 ;
     RECT  94.504 36.816 96.037 37.896 ;
     RECT  95.713 79.536 96.181 80.04 ;
     RECT  94.504 44.4 96.253 44.424 ;
     RECT  96.001 16.368 96.289 17.928 ;
     RECT  95.713 19.056 96.289 19.08 ;
     RECT  95.749 42.192 96.289 43.368 ;
     RECT  96.253 44.4 96.289 45.096 ;
     RECT  95.171 3.888 96.325 6.792 ;
     RECT  96.289 16.176 96.325 19.08 ;
     RECT  95.105 73.68 96.325 78.456 ;
     RECT  96.181 79.536 96.325 80.52 ;
     RECT  96.037 29.136 96.829 37.896 ;
     RECT  96.289 42.192 96.865 45.096 ;
     RECT  95.749 83.664 96.865 86.184 ;
     RECT  96.829 29.136 96.901 38.184 ;
     RECT  96.325 3.792 97.164 6.792 ;
     RECT  96.325 16.08 97.164 19.08 ;
     RECT  96.901 29.136 97.164 38.28 ;
     RECT  96.865 42.192 97.164 45.192 ;
     RECT  94.504 48.144 97.164 48.168 ;
     RECT  96.001 49.68 97.164 55.848 ;
     RECT  96.325 73.68 97.164 80.52 ;
     RECT  96.865 83.664 97.164 86.28 ;
     RECT  94.817 92.88 97.164 95.88 ;
    LAYER M5 ;
     RECT  83.664 0.016 90.12 0.085 ;
     RECT  83.28 0.085 90.456 1.957 ;
     RECT  93.936 1.957 93.96 2.005 ;
     RECT  83.232 1.957 90.456 2.053 ;
     RECT  93.84 2.005 93.96 2.053 ;
     RECT  93.312 2.053 93.96 2.137 ;
     RECT  2.4 2.137 2.52 2.151 ;
     RECT  7.8 2.137 7.92 2.151 ;
     RECT  13.2 2.137 13.32 2.151 ;
     RECT  18.6 2.137 18.72 2.151 ;
     RECT  24 2.137 24.12 2.151 ;
     RECT  29.4 2.137 29.52 2.151 ;
     RECT  34.8 2.137 34.92 2.151 ;
     RECT  40.2 2.137 40.32 2.151 ;
     RECT  45.6 2.137 45.72 2.151 ;
     RECT  51 2.137 51.12 2.151 ;
     RECT  56.4 2.137 56.52 2.151 ;
     RECT  61.8 2.137 61.92 2.151 ;
     RECT  67.2 2.137 67.32 2.151 ;
     RECT  72.6 2.137 72.72 2.151 ;
     RECT  78 2.137 78.12 2.151 ;
     RECT  93.312 2.137 94.32 2.151 ;
     RECT  6.096 2.149 6.12 2.197 ;
     RECT  7.8 2.151 8.112 2.245 ;
     RECT  78 2.151 78.312 2.245 ;
     RECT  83.184 2.053 90.456 2.245 ;
     RECT  93.312 2.151 94.512 2.245 ;
     RECT  56.4 2.151 56.712 2.293 ;
     RECT  82.08 2.245 91.32 2.437 ;
     RECT  18.6 2.151 18.912 2.485 ;
     RECT  29.4 2.151 29.712 2.485 ;
     RECT  82.08 2.437 91.608 2.485 ;
     RECT  92.784 2.245 95.16 2.485 ;
     RECT  29.28 2.485 29.712 2.533 ;
     RECT  82.08 2.485 95.16 2.533 ;
     RECT  71.424 2.293 71.448 2.581 ;
     RECT  72.6 2.151 72.912 2.581 ;
     RECT  2.4 2.151 2.712 2.677 ;
     RECT  3.936 2.197 6.12 2.677 ;
     RECT  81.408 2.533 95.16 2.725 ;
     RECT  45.6 2.151 45.912 2.773 ;
     RECT  71.424 2.581 72.912 2.773 ;
     RECT  78 2.245 78.792 2.819 ;
     RECT  7.2 2.245 8.112 2.821 ;
     RECT  9.36 2.245 9.384 2.821 ;
     RECT  18.48 2.485 18.912 2.821 ;
     RECT  37.728 2.629 37.752 2.821 ;
     RECT  16.848 2.677 16.872 2.869 ;
     RECT  37.728 2.821 38.136 3.013 ;
     RECT  51 2.151 51.312 3.061 ;
     RECT  52.944 2.821 52.968 3.061 ;
     RECT  21.12 2.965 21.144 3.107 ;
     RECT  51 3.061 52.968 3.107 ;
     RECT  24 2.151 24.312 3.109 ;
     RECT  54.816 2.869 54.84 3.109 ;
     RECT  59.808 2.821 59.832 3.109 ;
     RECT  59.808 3.109 60.312 3.299 ;
     RECT  22.368 2.821 22.536 3.301 ;
     RECT  40.2 2.151 40.512 3.301 ;
     RECT  68.928 2.821 68.952 3.301 ;
     RECT  75.888 2.245 75.912 3.301 ;
     RECT  79.92 2.773 79.944 3.301 ;
     RECT  80.976 2.725 95.16 3.301 ;
     RECT  70.656 2.773 72.912 3.347 ;
     RECT  13.2 2.151 13.512 3.349 ;
     RECT  15.024 2.869 15.048 3.349 ;
     RECT  64.32 2.245 64.344 3.349 ;
     RECT  78 2.819 78.696 3.349 ;
     RECT  71.424 3.347 72.912 3.395 ;
     RECT  0.192 3.301 0.216 3.397 ;
     RECT  11.664 2.629 11.688 3.397 ;
     RECT  13.2 3.349 15.048 3.397 ;
     RECT  28.992 2.533 29.712 3.443 ;
     RECT  63.504 3.349 64.344 3.443 ;
     RECT  68.928 3.301 69.528 3.443 ;
     RECT  75.84 3.301 75.912 3.443 ;
     RECT  77.904 3.349 78.696 3.443 ;
     RECT  37.248 3.013 38.136 3.587 ;
     RECT  56.4 2.293 56.904 3.587 ;
     RECT  33.6 3.493 33.624 3.635 ;
     RECT  59.856 3.299 60.312 3.635 ;
     RECT  7.2 2.821 9.384 3.637 ;
     RECT  18.48 2.821 19.848 3.637 ;
     RECT  7.2 3.637 9.528 3.685 ;
     RECT  29.28 3.443 29.712 3.733 ;
     RECT  34.8 2.151 35.112 3.781 ;
     RECT  2.4 2.677 6.12 3.829 ;
     RECT  7.152 3.685 9.528 3.829 ;
     RECT  11.664 3.397 15.048 3.829 ;
     RECT  18.48 3.637 20.328 3.829 ;
     RECT  11.664 3.829 15.72 3.877 ;
     RECT  16.8 2.869 16.872 3.877 ;
     RECT  77.904 3.443 78.312 3.877 ;
     RECT  34.8 3.781 35.976 3.923 ;
     RECT  79.92 3.301 95.16 3.923 ;
     RECT  0.144 3.397 0.216 3.925 ;
     RECT  24 3.109 24.504 3.925 ;
     RECT  26.112 3.109 27.048 3.925 ;
     RECT  58.08 3.877 58.104 3.925 ;
     RECT  74.112 3.109 74.136 3.925 ;
     RECT  45.408 2.773 45.912 3.971 ;
     RECT  11.664 3.877 16.872 3.973 ;
     RECT  2.4 3.829 9.528 4.019 ;
     RECT  21.504 3.301 22.536 4.019 ;
     RECT  37.584 3.587 38.136 4.019 ;
     RECT  54.672 3.109 54.936 4.163 ;
     RECT  22.224 4.019 22.536 4.165 ;
     RECT  48.96 2.821 48.984 4.165 ;
     RECT  18.096 3.829 20.328 4.213 ;
     RECT  61.8 2.151 62.112 4.213 ;
     RECT  11.424 3.973 16.872 4.307 ;
     RECT  75.84 3.443 75.864 4.307 ;
     RECT  22.224 4.165 22.728 4.355 ;
     RECT  71.424 3.395 71.448 4.355 ;
     RECT  51 3.107 52.008 4.357 ;
     RECT  2.4 4.019 8.52 4.403 ;
     RECT  0.144 3.925 0.312 4.453 ;
     RECT  48.288 4.165 48.984 4.453 ;
     RECT  11.664 4.307 16.872 4.501 ;
     RECT  18.096 4.213 20.856 4.501 ;
     RECT  26.064 3.925 27.048 4.595 ;
     RECT  40.08 3.301 40.512 4.741 ;
     RECT  74.112 3.925 74.664 4.835 ;
     RECT  45.6 3.971 45.912 4.885 ;
     RECT  79.92 3.923 94.512 4.981 ;
     RECT  11.664 4.501 20.856 5.029 ;
     RECT  56.4 3.587 56.712 5.029 ;
     RECT  24 3.925 24.936 5.075 ;
     RECT  9.504 4.019 9.528 5.077 ;
     RECT  29.28 3.733 29.976 5.077 ;
     RECT  34.8 3.923 35.4 5.077 ;
     RECT  79.776 4.981 94.512 5.125 ;
     RECT  48.192 4.453 48.984 5.171 ;
     RECT  58.08 3.925 58.68 5.171 ;
     RECT  22.512 4.355 22.728 5.173 ;
     RECT  24 5.075 24.552 5.173 ;
     RECT  72.6 3.395 72.912 5.173 ;
     RECT  0.144 4.453 0.36 5.221 ;
     RECT  22.512 5.173 24.552 5.267 ;
     RECT  2.4 4.403 8.472 5.365 ;
     RECT  22.512 5.267 24.408 5.365 ;
     RECT  51 4.357 52.248 5.365 ;
     RECT  72.6 5.173 73.08 5.365 ;
     RECT  79.776 5.125 94.632 5.413 ;
     RECT  11.664 5.029 21.432 5.459 ;
     RECT  69.504 3.443 69.528 5.459 ;
     RECT  58.08 5.171 58.632 5.507 ;
     RECT  2.304 5.365 8.472 5.509 ;
     RECT  9.504 5.077 9.576 5.509 ;
     RECT  2.304 5.509 9.576 5.605 ;
     RECT  50.208 5.365 52.248 5.605 ;
     RECT  77.616 3.877 78.312 5.605 ;
     RECT  79.776 5.413 95.016 5.605 ;
     RECT  40.032 4.741 40.512 5.653 ;
     RECT  77.616 5.605 95.016 5.701 ;
     RECT  74.64 4.835 74.664 5.747 ;
     RECT  0.144 5.221 0.456 5.795 ;
     RECT  63.504 3.443 63.528 5.795 ;
     RECT  22.464 5.365 24.408 5.797 ;
     RECT  39.36 5.653 40.512 5.941 ;
     RECT  44.304 5.077 44.328 5.989 ;
     RECT  45.6 4.885 46.008 5.989 ;
     RECT  48.192 5.171 48.216 5.989 ;
     RECT  59.856 3.635 59.88 5.989 ;
     RECT  72.6 5.365 73.368 5.989 ;
     RECT  59.856 5.989 60.168 6.035 ;
     RECT  34.56 5.077 35.4 6.037 ;
     RECT  61.44 4.213 62.112 6.037 ;
     RECT  39.36 5.941 41.064 6.083 ;
     RECT  44.304 5.989 46.008 6.131 ;
     RECT  47.904 5.989 48.216 6.131 ;
     RECT  70.896 4.405 70.92 6.181 ;
     RECT  72.384 5.989 73.368 6.181 ;
     RECT  54.672 4.163 54.696 6.229 ;
     RECT  60.144 6.035 60.168 6.229 ;
     RECT  61.296 6.037 62.112 6.229 ;
     RECT  56.4 5.029 57 6.275 ;
     RECT  77.232 5.701 95.016 6.277 ;
     RECT  0.192 5.795 0.456 6.323 ;
     RECT  12.048 5.459 21.096 6.323 ;
     RECT  49.92 5.605 52.248 6.323 ;
     RECT  77.232 6.277 95.16 6.323 ;
     RECT  26.112 4.595 27.048 6.325 ;
     RECT  77.52 6.323 95.16 6.371 ;
     RECT  2.304 5.605 10.536 6.421 ;
     RECT  20.304 6.323 21.096 6.421 ;
     RECT  22.272 5.797 24.408 6.421 ;
     RECT  31.344 2.341 31.368 6.565 ;
     RECT  34.176 6.037 35.4 6.565 ;
     RECT  36.384 5.605 36.408 6.565 ;
     RECT  20.304 6.421 24.408 6.613 ;
     RECT  69.024 5.749 69.048 6.661 ;
     RECT  12.048 6.323 19.224 6.707 ;
     RECT  34.176 6.565 36.408 6.709 ;
     RECT  51 6.323 52.248 6.709 ;
     RECT  37.584 4.019 37.896 6.805 ;
     RECT  39.36 6.083 40.512 6.805 ;
     RECT  45.6 6.131 46.008 6.805 ;
     RECT  67.2 2.151 67.512 6.805 ;
     RECT  12.048 6.707 19.128 6.851 ;
     RECT  70.896 6.181 73.368 6.851 ;
     RECT  44.304 6.131 44.328 6.853 ;
     RECT  31.344 6.565 31.512 6.901 ;
     RECT  0.192 6.323 0.216 6.949 ;
     RECT  2.304 6.421 10.872 6.949 ;
     RECT  12.048 6.851 14.712 6.949 ;
     RECT  68.64 6.661 69.048 6.949 ;
     RECT  80.976 6.371 95.16 6.995 ;
     RECT  37.584 6.805 40.512 7.045 ;
     RECT  72.384 6.851 73.368 7.045 ;
     RECT  65.28 6.469 65.304 7.091 ;
     RECT  31.344 6.901 31.8 7.093 ;
     RECT  33.552 6.709 36.408 7.093 ;
     RECT  37.584 7.045 41.064 7.093 ;
     RECT  53.856 6.229 54.696 7.093 ;
     RECT  56.4 6.275 56.856 7.093 ;
     RECT  20.304 6.613 24.456 7.139 ;
     RECT  53.856 7.093 56.856 7.139 ;
     RECT  58.608 5.507 58.632 7.139 ;
     RECT  31.344 7.093 32.136 7.235 ;
     RECT  33.552 7.093 41.064 7.235 ;
     RECT  0.144 6.949 0.216 7.333 ;
     RECT  44.112 6.853 44.328 7.333 ;
     RECT  45.6 6.805 46.536 7.333 ;
     RECT  77.52 6.371 79.944 7.333 ;
     RECT  20.304 7.139 21.48 7.379 ;
     RECT  64.464 7.237 64.488 7.379 ;
     RECT  77.472 7.333 79.944 7.379 ;
     RECT  22.464 7.139 24.456 7.429 ;
     RECT  25.728 6.325 27.048 7.429 ;
     RECT  0.144 7.333 0.264 7.475 ;
     RECT  20.304 7.379 21.336 7.475 ;
     RECT  81.84 6.995 95.16 7.475 ;
     RECT  48.192 6.131 48.216 7.525 ;
     RECT  48.192 7.525 48.312 7.667 ;
     RECT  2.304 6.949 14.712 7.763 ;
     RECT  15.936 6.851 19.128 7.763 ;
     RECT  28.704 5.077 29.976 7.765 ;
     RECT  72.384 7.045 73.56 7.955 ;
     RECT  28.08 7.765 29.976 8.051 ;
     RECT  51 6.709 52.632 8.147 ;
     RECT  53.856 7.139 56.808 8.147 ;
     RECT  76.368 6.661 76.392 8.147 ;
     RECT  53.856 8.147 54.696 8.195 ;
     RECT  77.472 7.379 78.312 8.195 ;
     RECT  81.84 7.475 95.016 8.293 ;
     RECT  31.344 7.235 31.8 8.389 ;
     RECT  33.552 7.235 36.408 8.389 ;
     RECT  37.584 7.235 40.512 8.389 ;
     RECT  55.92 8.147 56.808 8.437 ;
     RECT  60.144 6.229 62.112 8.437 ;
     RECT  75.216 7.909 75.24 8.485 ;
     RECT  79.728 7.379 79.944 8.485 ;
     RECT  0.144 7.475 0.216 8.579 ;
     RECT  20.544 7.475 21.288 8.579 ;
     RECT  44.112 7.333 46.536 8.579 ;
     RECT  72.384 7.955 73.08 8.579 ;
     RECT  70.896 6.851 70.92 8.581 ;
     RECT  33.552 8.389 40.512 8.629 ;
     RECT  52.608 8.147 52.632 8.629 ;
     RECT  42.768 8.485 42.792 8.677 ;
     RECT  55.92 8.437 56.856 8.677 ;
     RECT  15.984 7.763 19.128 8.723 ;
     RECT  32.928 8.629 40.512 8.723 ;
     RECT  0.192 8.579 0.216 8.771 ;
     RECT  52.608 8.629 53.16 8.771 ;
     RECT  20.544 8.579 21.192 8.819 ;
     RECT  18.096 8.723 19.128 8.869 ;
     RECT  32.928 8.723 33.048 8.915 ;
     RECT  60.144 8.437 62.232 8.963 ;
     RECT  2.4 7.763 14.712 8.965 ;
     RECT  32.928 8.915 32.952 9.011 ;
     RECT  45.072 8.579 46.536 9.013 ;
     RECT  65.472 7.717 65.496 9.013 ;
     RECT  68.64 6.949 69.672 9.013 ;
     RECT  70.896 8.581 71.304 9.013 ;
     RECT  74.784 8.485 75.24 9.013 ;
     RECT  42.768 8.677 43.704 9.059 ;
     RECT  61.296 8.963 62.232 9.059 ;
     RECT  79.728 8.485 80.376 9.061 ;
     RECT  81.504 8.293 95.016 9.061 ;
     RECT  30.768 8.389 31.8 9.107 ;
     RECT  54.336 8.195 54.696 9.155 ;
     RECT  65.28 9.013 65.496 9.155 ;
     RECT  74.112 9.013 75.24 9.203 ;
     RECT  55.92 8.677 57 9.205 ;
     RECT  65.28 9.155 65.448 9.205 ;
     RECT  18.096 8.869 19.752 9.299 ;
     RECT  34.176 8.723 40.512 9.299 ;
     RECT  72.6 8.579 73.08 9.301 ;
     RECT  74.112 9.203 74.808 9.301 ;
     RECT  60.144 8.963 60.168 9.349 ;
     RECT  18.192 9.299 19.752 9.395 ;
     RECT  22.464 7.429 27.048 9.443 ;
     RECT  66.672 6.805 67.512 9.493 ;
     RECT  68.64 9.013 71.304 9.493 ;
     RECT  52.608 8.771 52.632 9.587 ;
     RECT  66.672 9.493 71.304 9.587 ;
     RECT  2.4 8.965 14.808 9.589 ;
     RECT  41.76 9.493 41.784 9.635 ;
     RECT  66.672 9.587 70.008 9.635 ;
     RECT  72.6 9.301 74.808 9.635 ;
     RECT  22.464 9.443 25.752 9.779 ;
     RECT  51 8.147 51.576 9.781 ;
     RECT  79.728 9.061 95.016 9.827 ;
     RECT  48.144 7.957 48.168 9.829 ;
     RECT  48.144 9.829 48.456 9.875 ;
     RECT  45.072 9.013 46.728 9.925 ;
     RECT  68.64 9.635 70.008 10.067 ;
     RECT  79.776 9.827 95.016 10.067 ;
     RECT  54.336 9.155 54.6 10.165 ;
     RECT  55.92 9.205 57.048 10.165 ;
     RECT  21.168 8.819 21.192 10.213 ;
     RECT  64.752 9.205 65.448 10.213 ;
     RECT  66.672 9.635 67.512 10.213 ;
     RECT  49.92 6.323 49.944 10.261 ;
     RECT  51 9.781 51.864 10.261 ;
     RECT  18.192 9.395 19.56 10.307 ;
     RECT  28.08 8.051 29.712 10.355 ;
     RECT  34.176 9.299 38.52 10.355 ;
     RECT  79.824 10.067 95.016 10.355 ;
     RECT  48.432 9.875 48.456 10.403 ;
     RECT  18.336 10.307 19.56 10.405 ;
     RECT  20.784 10.213 21.192 10.405 ;
     RECT  64.752 10.213 67.512 10.547 ;
     RECT  26.736 9.443 27.048 10.595 ;
     RECT  72.6 9.635 73.512 10.643 ;
     RECT  22.608 9.779 25.752 10.693 ;
     RECT  26.736 10.595 26.76 10.693 ;
     RECT  18.336 10.405 21.192 10.741 ;
     RECT  49.92 10.261 51.864 10.741 ;
     RECT  53.136 10.213 53.16 10.741 ;
     RECT  30.816 9.107 31.8 10.789 ;
     RECT  22.608 10.693 26.76 10.835 ;
     RECT  77.568 8.195 78.312 10.835 ;
     RECT  79.824 10.355 94.512 10.835 ;
     RECT  45.072 9.925 46.776 10.837 ;
     RECT  15.984 8.723 16.92 10.883 ;
     RECT  34.8 10.355 35.304 10.883 ;
     RECT  49.92 10.741 53.16 10.883 ;
     RECT  54.336 10.165 57.048 10.883 ;
     RECT  71.232 9.587 71.304 10.883 ;
     RECT  74.592 9.635 74.808 10.883 ;
     RECT  79.824 10.835 80.184 10.883 ;
     RECT  28.464 10.355 29.712 10.885 ;
     RECT  30.768 10.789 31.8 10.885 ;
     RECT  22.608 10.835 25.752 10.979 ;
     RECT  42.768 9.059 43.608 11.027 ;
     RECT  2.304 9.589 14.808 11.077 ;
     RECT  15.984 10.883 16.536 11.077 ;
     RECT  22.608 10.979 25.704 11.077 ;
     RECT  65.28 10.547 67.512 11.123 ;
     RECT  0.144 9.637 0.168 11.221 ;
     RECT  66.672 11.123 67.512 11.317 ;
     RECT  68.928 10.067 70.008 11.317 ;
     RECT  0.144 11.221 0.216 11.365 ;
     RECT  34.8 10.883 35.256 11.365 ;
     RECT  74.592 10.883 74.616 11.365 ;
     RECT  2.304 11.077 16.536 11.411 ;
     RECT  0.144 11.365 0.264 11.459 ;
     RECT  18.336 10.741 21.288 11.459 ;
     RECT  28.464 10.885 31.8 11.459 ;
     RECT  42.768 11.027 42.792 11.459 ;
     RECT  59.472 9.349 60.168 11.459 ;
     RECT  0.192 11.459 0.264 11.461 ;
     RECT  77.616 10.835 78.312 11.509 ;
     RECT  2.304 11.411 14.76 11.555 ;
     RECT  79.824 10.883 80.136 11.653 ;
     RECT  72.6 10.643 73.08 11.701 ;
     RECT  74.352 11.365 74.616 11.701 ;
     RECT  36.384 10.355 38.52 11.747 ;
     RECT  0.192 11.461 0.312 11.749 ;
     RECT  72.6 11.701 74.616 11.891 ;
     RECT  26.736 10.835 26.76 11.941 ;
     RECT  54.336 10.883 56.904 11.941 ;
     RECT  81.264 10.835 94.512 11.941 ;
     RECT  18.336 11.459 19.56 11.987 ;
     RECT  20.784 11.459 21.288 11.987 ;
     RECT  22.416 11.077 25.704 11.989 ;
     RECT  39.6 9.299 40.512 12.035 ;
     RECT  61.296 9.059 62.112 12.037 ;
     RECT  26.688 11.941 26.76 12.083 ;
     RECT  77.616 11.509 78.696 12.085 ;
     RECT  79.728 11.653 80.136 12.085 ;
     RECT  16.08 11.411 16.536 12.131 ;
     RECT  74.112 11.891 74.616 12.181 ;
     RECT  20.784 11.987 20.808 12.275 ;
     RECT  54.336 11.941 57.816 12.275 ;
     RECT  71.28 10.883 71.304 12.325 ;
     RECT  72.6 11.891 72.912 12.325 ;
     RECT  28.56 11.459 31.8 12.469 ;
     RECT  32.976 10.309 33 12.469 ;
     RECT  18.336 11.987 19.416 12.517 ;
     RECT  59.664 11.459 60.168 12.517 ;
     RECT  61.296 12.037 62.424 12.517 ;
     RECT  77.616 12.085 80.136 12.517 ;
     RECT  81.168 11.941 94.512 12.517 ;
     RECT  0.192 11.749 0.408 12.563 ;
     RECT  64.128 10.933 64.296 12.565 ;
     RECT  65.28 11.123 65.304 12.565 ;
     RECT  0.192 12.563 0.36 12.613 ;
     RECT  54.336 12.275 55.032 12.755 ;
     RECT  49.92 10.883 52.728 12.757 ;
     RECT  66.672 11.317 70.008 12.757 ;
     RECT  59.664 12.517 62.424 12.803 ;
     RECT  28.56 12.469 33 12.997 ;
     RECT  34.176 11.365 35.256 12.997 ;
     RECT  49.536 12.757 52.728 12.997 ;
     RECT  61.8 12.803 62.424 13.045 ;
     RECT  77.616 12.517 94.512 13.045 ;
     RECT  56.064 12.275 57.816 13.091 ;
     RECT  36.432 11.747 38.52 13.139 ;
     RECT  45.072 10.837 47.16 13.139 ;
     RECT  71.28 12.325 72.912 13.139 ;
     RECT  28.56 12.997 35.256 13.187 ;
     RECT  61.8 13.045 62.76 13.187 ;
     RECT  43.872 12.469 43.896 13.285 ;
     RECT  45.072 13.139 46.776 13.285 ;
     RECT  2.304 11.555 14.568 13.331 ;
     RECT  43.872 13.285 46.776 13.331 ;
     RECT  29.088 13.187 35.256 13.333 ;
     RECT  49.008 12.997 52.728 13.379 ;
     RECT  66.672 12.757 70.056 13.427 ;
     RECT  54.336 12.755 54.36 13.573 ;
     RECT  64.128 12.565 65.304 13.621 ;
     RECT  21.072 13.093 21.096 13.667 ;
     RECT  77.376 13.045 94.512 13.667 ;
     RECT  49.104 13.379 52.728 13.715 ;
     RECT  77.376 13.667 82.056 13.763 ;
     RECT  59.664 12.803 60.408 13.811 ;
     RECT  42.336 13.477 42.36 13.813 ;
     RECT  49.536 13.715 52.728 13.859 ;
     RECT  29.088 13.333 35.304 13.907 ;
     RECT  56.064 13.091 57.672 13.955 ;
     RECT  83.04 13.667 94.512 14.003 ;
     RECT  17.616 12.517 19.416 14.101 ;
     RECT  39.984 12.035 40.512 14.101 ;
     RECT  44.64 13.331 46.776 14.101 ;
     RECT  66.672 13.427 67.848 14.195 ;
     RECT  72.48 13.139 72.912 14.197 ;
     RECT  0.144 12.613 0.36 14.291 ;
     RECT  74.112 12.181 74.664 14.291 ;
     RECT  93.216 14.003 94.512 14.291 ;
     RECT  49.536 13.859 51.576 14.339 ;
     RECT  69.024 13.427 70.056 14.339 ;
     RECT  52.704 13.859 52.728 14.341 ;
     RECT  72.288 14.197 72.912 14.389 ;
     RECT  74.112 14.291 74.136 14.389 ;
     RECT  63.984 13.621 65.304 14.485 ;
     RECT  71.28 13.139 71.304 14.485 ;
     RECT  72.288 14.389 74.136 14.485 ;
     RECT  2.304 13.331 10.92 14.531 ;
     RECT  47.904 14.341 47.928 14.531 ;
     RECT  54.144 13.573 54.36 14.531 ;
     RECT  71.28 14.485 74.136 14.531 ;
     RECT  11.952 13.331 14.568 14.629 ;
     RECT  16.08 12.131 16.248 14.629 ;
     RECT  69.024 14.339 70.008 14.723 ;
     RECT  59.664 13.811 59.688 14.725 ;
     RECT  2.304 14.531 10.68 14.771 ;
     RECT  11.952 14.629 16.248 14.771 ;
     RECT  36.48 13.139 38.52 14.773 ;
     RECT  39.984 14.101 40.68 14.773 ;
     RECT  77.376 13.763 79.272 14.773 ;
     RECT  63.168 14.485 65.304 14.867 ;
     RECT  80.544 13.763 82.056 14.867 ;
     RECT  17.616 14.101 19.464 14.869 ;
     RECT  33.072 13.907 35.304 14.915 ;
     RECT  80.544 14.867 81.96 14.963 ;
     RECT  42.144 13.813 42.36 15.011 ;
     RECT  0.24 14.291 0.36 15.251 ;
     RECT  59.568 14.725 59.688 15.251 ;
     RECT  63.168 14.867 64.056 15.299 ;
     RECT  52.704 14.341 52.968 15.301 ;
     RECT  61.8 13.187 62.112 15.349 ;
     RECT  42.144 15.011 42.168 15.443 ;
     RECT  48.48 14.533 48.504 15.443 ;
     RECT  69.648 14.723 70.008 15.443 ;
     RECT  72.192 14.531 74.136 15.443 ;
     RECT  0.288 15.251 0.36 15.491 ;
     RECT  44.64 14.101 46.824 15.491 ;
     RECT  17.328 14.869 19.464 15.541 ;
     RECT  0.336 15.491 0.36 15.587 ;
     RECT  69.984 15.443 70.008 15.587 ;
     RECT  26.736 12.083 26.76 15.589 ;
     RECT  66.96 14.195 67.848 15.589 ;
     RECT  76.368 13.045 76.392 15.637 ;
     RECT  77.376 14.773 79.56 15.637 ;
     RECT  2.304 14.771 10.536 15.731 ;
     RECT  66.72 15.589 67.848 15.733 ;
     RECT  76.368 15.637 79.56 15.733 ;
     RECT  76.368 15.733 79.8 15.779 ;
     RECT  29.088 13.907 31.896 15.877 ;
     RECT  36.48 14.773 40.68 15.877 ;
     RECT  66.72 15.733 68.424 15.877 ;
     RECT  36.48 15.877 41.736 16.019 ;
     RECT  17.28 15.541 19.464 16.069 ;
     RECT  83.04 14.003 92.232 16.115 ;
     RECT  29.088 15.877 32.184 16.117 ;
     RECT  33.84 14.915 35.304 16.117 ;
     RECT  29.088 16.117 35.304 16.163 ;
     RECT  81.024 14.963 81.96 16.165 ;
     RECT  81.024 16.165 82.056 16.211 ;
     RECT  31.872 16.163 35.304 16.259 ;
     RECT  44.64 15.491 46.776 16.259 ;
     RECT  52.704 15.301 53.064 16.259 ;
     RECT  76.368 15.779 78.792 16.259 ;
     RECT  85.968 16.115 92.232 16.259 ;
     RECT  29.088 16.163 30.504 16.403 ;
     RECT  12.144 14.771 16.248 16.405 ;
     RECT  22.368 11.989 25.704 16.405 ;
     RECT  45.072 16.259 46.776 16.453 ;
     RECT  49.728 14.339 51.576 16.453 ;
     RECT  11.472 16.405 16.248 16.501 ;
     RECT  17.28 16.069 19.512 16.501 ;
     RECT  29.088 16.403 29.712 16.501 ;
     RECT  61.8 15.349 62.952 16.501 ;
     RECT  82.032 16.211 82.056 16.501 ;
     RECT  83.04 16.115 84.792 16.501 ;
     RECT  66.72 15.877 68.52 16.547 ;
     RECT  56.112 13.955 57.672 16.549 ;
     RECT  72.192 15.443 73.128 16.549 ;
     RECT  11.472 16.501 19.512 16.595 ;
     RECT  85.968 16.259 92.088 16.595 ;
     RECT  65.28 14.867 65.304 16.691 ;
     RECT  71.376 16.549 73.128 16.691 ;
     RECT  67.2 16.547 68.52 16.741 ;
     RECT  11.472 16.595 17.352 16.787 ;
     RECT  2.304 15.731 10.44 16.835 ;
     RECT  42.816 16.309 42.84 16.835 ;
     RECT  74.112 15.443 74.136 16.883 ;
     RECT  64.032 15.299 64.056 16.885 ;
     RECT  67.2 16.741 69.096 16.931 ;
     RECT  68.832 16.931 69.096 16.979 ;
     RECT  39.84 16.019 41.736 16.981 ;
     RECT  11.472 16.787 17.208 17.027 ;
     RECT  28.416 16.501 29.712 17.029 ;
     RECT  26.736 15.589 26.904 17.075 ;
     RECT  21.072 16.981 21.096 17.077 ;
     RECT  22.08 16.405 25.704 17.077 ;
     RECT  39.744 16.981 41.736 17.077 ;
     RECT  61.104 16.501 62.952 17.077 ;
     RECT  82.032 16.501 84.792 17.077 ;
     RECT  85.968 16.595 91.464 17.077 ;
     RECT  21.072 17.077 25.704 17.123 ;
     RECT  11.472 17.027 17.112 17.219 ;
     RECT  39.744 17.077 42.072 17.219 ;
     RECT  31.872 16.259 32.808 17.221 ;
     RECT  33.84 16.259 35.304 17.221 ;
     RECT  60.96 17.077 62.952 17.221 ;
     RECT  48.96 16.453 51.576 17.269 ;
     RECT  52.704 16.259 52.728 17.269 ;
     RECT  56.112 16.549 58.296 17.269 ;
     RECT  59.568 15.251 59.592 17.315 ;
     RECT  55.536 17.269 58.296 17.317 ;
     RECT  55.536 17.317 58.536 17.411 ;
     RECT  11.472 17.219 17.064 17.459 ;
     RECT  45.072 16.453 46.824 17.459 ;
     RECT  2.4 16.835 10.44 17.461 ;
     RECT  11.472 17.459 16.248 17.461 ;
     RECT  76.656 16.259 78.792 17.507 ;
     RECT  2.4 17.461 16.248 17.603 ;
     RECT  18.336 16.595 19.512 17.603 ;
     RECT  48.96 17.269 52.728 17.651 ;
     RECT  71.808 16.691 73.128 17.699 ;
     RECT  82.032 17.077 91.464 17.699 ;
     RECT  60.912 17.221 62.952 17.701 ;
     RECT  49.824 17.651 52.728 17.795 ;
     RECT  60.864 17.701 62.952 17.843 ;
     RECT  63.936 16.885 64.056 17.891 ;
     RECT  67.2 16.931 67.8 17.893 ;
     RECT  68.832 16.979 68.856 17.893 ;
     RECT  61.536 17.843 62.952 17.941 ;
     RECT  48.432 17.797 48.456 17.987 ;
     RECT  49.92 17.795 52.728 17.987 ;
     RECT  79.776 15.779 79.8 17.989 ;
     RECT  79.632 17.989 79.8 18.035 ;
     RECT  18.432 17.603 19.512 18.131 ;
     RECT  61.536 17.941 63.384 18.131 ;
     RECT  45.6 17.459 46.824 18.133 ;
     RECT  28.08 17.029 29.712 18.179 ;
     RECT  45.6 18.133 47.064 18.181 ;
     RECT  61.536 18.131 62.952 18.275 ;
     RECT  36.48 16.019 38.52 18.277 ;
     RECT  55.584 17.411 58.536 18.323 ;
     RECT  61.584 18.275 62.952 18.563 ;
     RECT  43.392 17.605 43.416 18.565 ;
     RECT  76.656 17.507 78.648 18.611 ;
     RECT  82.656 17.699 91.464 18.611 ;
     RECT  43.392 18.565 43.752 18.661 ;
     RECT  81.024 16.211 81.048 18.709 ;
     RECT  2.4 17.603 11.16 18.757 ;
     RECT  12.24 17.603 16.248 18.757 ;
     RECT  21.6 17.123 25.704 18.757 ;
     RECT  26.736 17.075 26.76 18.757 ;
     RECT  76.704 18.611 78.648 18.757 ;
     RECT  79.632 18.035 79.656 18.757 ;
     RECT  36.48 18.277 38.616 18.803 ;
     RECT  54.336 14.531 54.36 18.803 ;
     RECT  76.704 18.757 79.656 18.803 ;
     RECT  67.2 17.893 68.856 18.805 ;
     RECT  31.872 17.221 35.304 18.851 ;
     RECT  55.584 18.323 58.008 18.901 ;
     RECT  82.656 18.611 86.088 18.995 ;
     RECT  49.92 17.987 51.576 19.043 ;
     RECT  72 17.699 73.128 19.045 ;
     RECT  18.432 18.131 19.464 19.093 ;
     RECT  61.8 18.563 62.952 19.187 ;
     RECT  17.52 19.093 19.464 19.235 ;
     RECT  50.016 19.043 51.576 19.285 ;
     RECT  52.704 17.987 52.728 19.285 ;
     RECT  71.664 19.045 73.128 19.333 ;
     RECT  36.48 18.803 36.792 19.379 ;
     RECT  64.176 19.237 64.2 19.379 ;
     RECT  67.2 18.805 68.952 19.381 ;
     RECT  45.6 18.181 47.784 19.427 ;
     RECT  81.024 18.709 81.672 19.427 ;
     RECT  82.656 18.995 85.848 19.427 ;
     RECT  42.768 18.661 43.752 19.475 ;
     RECT  39.744 17.219 41.304 19.523 ;
     RECT  67.2 19.381 69 19.523 ;
     RECT  87.744 18.611 91.464 19.571 ;
     RECT  61.8 19.187 62.856 19.621 ;
     RECT  32.448 18.851 35.304 19.669 ;
     RECT  60.96 19.621 62.856 19.763 ;
     RECT  21.6 18.757 26.76 19.811 ;
     RECT  28.32 18.179 29.712 19.813 ;
     RECT  69.984 17.605 70.056 19.859 ;
     RECT  20.496 18.181 20.52 19.907 ;
     RECT  67.2 19.523 68.76 19.955 ;
     RECT  55.392 18.901 58.008 19.957 ;
     RECT  55.296 19.957 58.008 20.003 ;
     RECT  88.08 19.571 91.464 20.003 ;
     RECT  28.32 19.813 30.408 20.053 ;
     RECT  48.96 19.909 48.984 20.053 ;
     RECT  50.016 19.285 52.728 20.053 ;
     RECT  67.2 19.955 67.512 20.053 ;
     RECT  48.96 20.053 52.728 20.147 ;
     RECT  17.52 19.235 19.416 20.149 ;
     RECT  66.384 20.053 67.512 20.243 ;
     RECT  40.08 19.523 41.304 20.339 ;
     RECT  17.328 20.149 19.416 20.341 ;
     RECT  45.6 19.427 47.064 20.387 ;
     RECT  49.536 20.147 52.344 20.435 ;
     RECT  2.4 18.757 16.248 20.485 ;
     RECT  17.328 20.341 20.328 20.485 ;
     RECT  81.024 19.427 81.432 20.485 ;
     RECT  81.024 20.485 81.48 20.533 ;
     RECT  52.32 20.435 52.344 20.579 ;
     RECT  71.664 19.333 74.088 20.629 ;
     RECT  76.704 18.803 79.32 20.725 ;
     RECT  80.688 20.533 81.48 20.725 ;
     RECT  82.656 19.427 84.552 20.725 ;
     RECT  54.096 19.381 54.12 20.867 ;
     RECT  71.664 20.629 74.616 20.963 ;
     RECT  88.128 20.003 91.464 20.965 ;
     RECT  65.52 20.533 65.544 21.013 ;
     RECT  61.8 19.763 62.856 21.061 ;
     RECT  71.664 20.963 74.088 21.061 ;
     RECT  49.536 20.435 51.312 21.155 ;
     RECT  68.64 19.955 68.76 21.155 ;
     RECT  86.88 20.965 91.464 21.155 ;
     RECT  31.44 20.725 31.464 21.157 ;
     RECT  32.448 19.669 35.352 21.157 ;
     RECT  76.704 20.725 84.552 21.157 ;
     RECT  23.424 19.811 26.76 21.203 ;
     RECT  76.704 21.157 84.6 21.251 ;
     RECT  2.4 20.485 20.328 21.349 ;
     RECT  55.296 20.003 57.672 21.395 ;
     RECT  28.32 20.053 30.456 21.397 ;
     RECT  31.44 21.157 35.352 21.397 ;
     RECT  2.4 21.349 20.52 21.445 ;
     RECT  45.6 20.387 45.912 21.493 ;
     RECT  61.68 21.061 62.856 21.493 ;
     RECT  79.296 21.251 81.864 21.539 ;
     RECT  58.896 21.013 58.92 21.637 ;
     RECT  67.2 20.243 67.512 21.637 ;
     RECT  36.528 19.379 36.792 21.683 ;
     RECT  55.296 21.395 57.288 21.683 ;
     RECT  65.136 21.013 65.544 21.685 ;
     RECT  83.184 21.251 84.6 21.685 ;
     RECT  85.824 19.427 85.848 21.685 ;
     RECT  86.88 21.155 89.208 21.685 ;
     RECT  90.24 21.155 91.464 21.731 ;
     RECT  76.704 21.251 78.312 21.779 ;
     RECT  83.184 21.685 84.792 21.827 ;
     RECT  70.032 19.859 70.056 21.829 ;
     RECT  56.112 21.683 57.288 21.875 ;
     RECT  2.4 21.445 20.568 21.923 ;
     RECT  37.968 18.803 38.616 21.923 ;
     RECT  28.32 21.397 35.352 21.971 ;
     RECT  83.184 21.827 84.6 21.971 ;
     RECT  64.944 21.685 65.544 22.067 ;
     RECT  80.112 21.539 81.864 22.067 ;
     RECT  67.104 21.637 67.512 22.069 ;
     RECT  68.64 21.155 68.664 22.069 ;
     RECT  47.04 20.387 47.064 22.115 ;
     RECT  80.688 22.067 81.864 22.115 ;
     RECT  58.752 21.637 58.92 22.117 ;
     RECT  85.824 21.685 89.208 22.163 ;
     RECT  15.984 21.923 20.568 22.165 ;
     RECT  21.6 19.811 22.392 22.165 ;
     RECT  23.904 21.203 26.76 22.165 ;
     RECT  28.656 21.971 35.352 22.213 ;
     RECT  36.528 21.683 36.744 22.213 ;
     RECT  40.08 20.339 41.064 22.259 ;
     RECT  45.6 21.493 46.008 22.259 ;
     RECT  15.984 22.165 26.76 22.451 ;
     RECT  80.784 22.115 81.864 22.547 ;
     RECT  61.008 21.493 62.856 22.693 ;
     RECT  56.112 21.875 57.24 22.739 ;
     RECT  71.376 21.061 74.088 22.741 ;
     RECT  71.376 22.741 74.856 22.787 ;
     RECT  90.24 21.731 90.6 22.787 ;
     RECT  15.984 22.451 26.184 22.835 ;
     RECT  71.376 22.787 73.8 22.835 ;
     RECT  58.752 22.117 59.256 22.933 ;
     RECT  58.704 22.933 59.256 22.979 ;
     RECT  83.232 21.971 84.6 22.979 ;
     RECT  28.656 22.213 36.744 23.075 ;
     RECT  43.392 19.475 43.752 23.075 ;
     RECT  41.712 22.837 41.736 23.123 ;
     RECT  52.848 22.837 52.872 23.123 ;
     RECT  58.704 22.979 59.064 23.123 ;
     RECT  90.24 22.787 90.552 23.315 ;
     RECT  36.624 23.075 36.744 23.317 ;
     RECT  38.16 21.923 38.616 23.317 ;
     RECT  80.784 22.547 81.48 23.317 ;
     RECT  60.912 22.693 62.856 23.365 ;
     RECT  56.112 22.739 56.808 23.603 ;
     RECT  58.704 23.123 59.016 23.605 ;
     RECT  60.912 23.365 63.192 23.699 ;
     RECT  85.824 22.163 89.112 23.699 ;
     RECT  45.6 22.259 45.912 23.701 ;
     RECT  67.104 22.069 68.664 23.749 ;
     RECT  76.8 21.779 78.312 23.749 ;
     RECT  64.944 22.067 65.496 23.795 ;
     RECT  2.4 21.923 14.712 23.797 ;
     RECT  15.984 22.835 21.624 23.797 ;
     RECT  2.4 23.797 21.624 23.845 ;
     RECT  23.328 22.835 26.184 23.845 ;
     RECT  76.8 23.749 78.6 23.845 ;
     RECT  74.832 22.787 74.856 23.893 ;
     RECT  83.4 22.979 84.6 23.893 ;
     RECT  85.824 23.699 86.904 23.893 ;
     RECT  71.376 22.835 73.752 23.939 ;
     RECT  49.584 21.155 51.312 23.941 ;
     RECT  64.944 23.795 65.4 23.941 ;
     RECT  28.656 23.075 35.112 23.987 ;
     RECT  58.656 23.605 59.016 24.083 ;
     RECT  49.584 23.941 51.528 24.085 ;
     RECT  60.912 23.699 62.856 24.131 ;
     RECT  90.24 23.315 90.312 24.133 ;
     RECT  36.624 23.317 38.616 24.181 ;
     RECT  36.624 24.181 38.808 24.227 ;
     RECT  61.248 24.131 62.856 24.371 ;
     RECT  70.032 21.829 70.152 24.371 ;
     RECT  45.6 23.701 46.056 24.373 ;
     RECT  74.832 23.893 74.904 24.421 ;
     RECT  32.208 23.987 35.112 24.469 ;
     RECT  76.8 23.845 79.224 24.469 ;
     RECT  61.68 24.371 62.856 24.611 ;
     RECT  40.08 22.259 40.512 24.661 ;
     RECT  27.648 24.517 27.672 24.707 ;
     RECT  71.376 23.939 73.032 24.707 ;
     RECT  45.6 24.373 46.968 24.755 ;
     RECT  66.912 23.749 68.664 24.805 ;
     RECT  46.944 24.755 46.968 24.851 ;
     RECT  38.304 24.227 38.808 24.899 ;
     RECT  58.992 24.083 59.016 24.899 ;
     RECT  90.192 24.133 90.312 24.949 ;
     RECT  66.624 24.805 68.664 25.043 ;
     RECT  83.4 23.893 86.904 25.045 ;
     RECT  90.192 24.949 90.36 25.045 ;
     RECT  70.032 24.371 70.056 25.139 ;
     RECT  76.704 24.469 79.224 25.139 ;
     RECT  80.688 23.317 81.48 25.187 ;
     RECT  28.656 23.987 31.176 25.235 ;
     RECT  64.08 23.941 65.4 25.283 ;
     RECT  74.832 24.421 75.672 25.331 ;
     RECT  49.584 24.085 52.44 25.379 ;
     RECT  80.88 25.187 81.48 25.475 ;
     RECT  90.144 25.045 90.36 25.523 ;
     RECT  39.84 24.661 40.512 25.573 ;
     RECT  49.584 25.379 52.296 25.621 ;
     RECT  83.28 25.045 86.904 25.667 ;
     RECT  2.4 23.845 26.184 25.715 ;
     RECT  65.376 25.283 65.4 25.715 ;
     RECT  61.68 24.611 62.712 25.765 ;
     RECT  28.656 25.235 29.712 25.813 ;
     RECT  45.6 24.755 45.912 25.813 ;
     RECT  71.376 24.707 72.912 25.813 ;
     RECT  61.008 25.765 62.712 25.907 ;
     RECT  27.792 25.813 29.712 26.003 ;
     RECT  43.392 23.075 43.416 26.003 ;
     RECT  56.112 23.603 56.712 26.005 ;
     RECT  57.792 25.573 57.816 26.005 ;
     RECT  48.624 25.621 52.296 26.051 ;
     RECT  61.68 25.907 62.712 26.099 ;
     RECT  66.912 25.043 68.664 26.197 ;
     RECT  36.624 24.227 36.744 26.243 ;
     RECT  56.112 26.005 57.816 26.243 ;
     RECT  61.8 26.099 62.712 26.243 ;
     RECT  85.728 25.667 86.904 26.243 ;
     RECT  81.12 25.475 81.48 26.339 ;
     RECT  87.888 23.699 89.112 26.339 ;
     RECT  90.192 25.523 90.36 26.339 ;
     RECT  70.896 25.813 72.912 26.437 ;
     RECT  75.312 25.331 75.672 26.483 ;
     RECT  79.776 25.573 79.8 26.483 ;
     RECT  70.896 26.437 73.08 26.485 ;
     RECT  32.208 24.469 35.208 26.627 ;
     RECT  83.28 25.667 84.6 26.675 ;
     RECT  32.544 26.627 35.208 26.677 ;
     RECT  56.112 26.243 57.624 26.677 ;
     RECT  22.752 25.715 26.184 26.725 ;
     RECT  45.024 25.813 45.912 26.725 ;
     RECT  81.12 26.339 81.144 26.725 ;
     RECT  66.912 26.197 68.712 26.771 ;
     RECT  32.544 26.677 35.496 26.819 ;
     RECT  39.792 25.573 40.512 26.819 ;
     RECT  64.08 25.283 64.2 26.819 ;
     RECT  85.728 26.243 86.712 26.819 ;
     RECT  76.704 25.139 78.792 26.867 ;
     RECT  45.024 26.725 47.592 26.915 ;
     RECT  75.312 26.483 75.528 27.059 ;
     RECT  90.24 26.339 90.36 27.059 ;
     RECT  38.304 24.899 38.616 27.107 ;
     RECT  48.624 26.051 51.432 27.155 ;
     RECT  90.24 27.059 90.264 27.155 ;
     RECT  22.752 26.725 26.232 27.157 ;
     RECT  83.4 26.675 84.6 27.157 ;
     RECT  85.728 26.819 86.232 27.157 ;
     RECT  83.4 27.157 86.232 27.203 ;
     RECT  2.4 25.715 21.576 27.253 ;
     RECT  2.304 27.253 21.576 27.301 ;
     RECT  22.56 27.157 26.232 27.301 ;
     RECT  39.888 26.819 40.512 27.301 ;
     RECT  61.8 26.243 62.112 27.301 ;
     RECT  81.024 26.725 81.144 27.301 ;
     RECT  76.704 26.867 78.408 27.347 ;
     RECT  81.024 27.301 81.48 27.347 ;
     RECT  70.896 26.485 73.512 27.395 ;
     RECT  55.872 26.677 57.624 27.587 ;
     RECT  28.032 26.003 29.712 27.635 ;
     RECT  2.304 27.301 26.232 27.637 ;
     RECT  48.624 27.155 48.936 27.875 ;
     RECT  2.304 27.637 26.76 27.877 ;
     RECT  28.032 27.635 28.056 27.877 ;
     RECT  30.72 25.235 31.176 27.877 ;
     RECT  36.72 26.243 36.744 27.877 ;
     RECT  61.68 27.301 62.112 27.877 ;
     RECT  66.912 26.771 68.664 27.877 ;
     RECT  77.184 27.347 78.408 27.923 ;
     RECT  60.96 27.877 62.112 27.925 ;
     RECT  2.304 27.877 28.056 27.971 ;
     RECT  94.2 14.291 94.512 27.973 ;
     RECT  49.92 27.155 51.432 28.115 ;
     RECT  29.04 27.635 29.712 28.165 ;
     RECT  30.72 27.877 31.368 28.165 ;
     RECT  32.544 26.819 35.448 28.211 ;
     RECT  0.384 27.301 0.408 28.261 ;
     RECT  81.456 27.347 81.48 28.307 ;
     RECT  72.432 27.395 73.512 28.309 ;
     RECT  75.312 27.059 75.48 28.405 ;
     RECT  0.288 28.261 0.408 28.453 ;
     RECT  29.04 28.165 31.368 28.453 ;
     RECT  32.544 28.211 35.112 28.453 ;
     RECT  38.592 27.107 38.616 28.453 ;
     RECT  39.888 27.301 41.064 28.453 ;
     RECT  58.656 26.965 58.68 28.453 ;
     RECT  75.312 28.405 75.528 28.453 ;
     RECT  45.6 26.915 47.592 28.499 ;
     RECT  66.096 27.877 68.664 28.547 ;
     RECT  83.4 27.203 85.848 28.547 ;
     RECT  56.112 27.587 57.624 28.741 ;
     RECT  38.592 28.453 41.064 28.931 ;
     RECT  72.432 28.309 73.656 28.933 ;
     RECT  64.176 26.819 64.2 28.981 ;
     RECT  70.896 27.395 71.4 28.981 ;
     RECT  60.96 27.925 63.096 29.027 ;
     RECT  83.4 28.547 84.552 29.027 ;
     RECT  83.4 29.027 84.504 29.029 ;
     RECT  94.2 27.973 94.68 29.029 ;
     RECT  72.432 28.933 73.752 29.077 ;
     RECT  74.88 28.453 75.528 29.077 ;
     RECT  48.912 27.875 48.936 29.219 ;
     RECT  60.96 29.027 62.112 29.219 ;
     RECT  29.04 28.453 35.112 29.267 ;
     RECT  55.584 28.741 57.624 29.267 ;
     RECT  72.432 29.077 75.528 29.267 ;
     RECT  49.92 28.115 49.944 29.317 ;
     RECT  51 28.115 51.432 29.317 ;
     RECT  49.92 29.317 51.432 29.363 ;
     RECT  39.312 28.931 41.064 29.365 ;
     RECT  88.224 26.339 89.112 29.461 ;
     RECT  47.52 28.499 47.592 29.509 ;
     RECT  87.84 29.461 89.112 29.557 ;
     RECT  79.92 27.061 79.944 29.653 ;
     RECT  45.6 28.499 46.008 29.747 ;
     RECT  79.344 29.653 79.944 29.747 ;
     RECT  83.184 29.029 84.504 29.747 ;
     RECT  0.144 28.453 0.408 29.749 ;
     RECT  55.92 29.267 57.624 29.797 ;
     RECT  58.656 28.453 58.824 29.797 ;
     RECT  47.52 29.509 48.504 29.843 ;
     RECT  77.184 27.923 78.312 29.939 ;
     RECT  70.704 28.981 71.4 30.037 ;
     RECT  72.432 29.267 74.904 30.037 ;
     RECT  70.704 30.037 74.904 30.131 ;
     RECT  39.312 29.365 41.256 30.133 ;
     RECT  2.304 27.971 27.336 30.181 ;
     RECT  55.92 29.797 59.112 30.181 ;
     RECT  81.12 28.981 81.144 30.181 ;
     RECT  49.92 29.363 51.312 30.229 ;
     RECT  39.216 30.133 41.256 30.275 ;
     RECT  64.176 28.981 64.872 30.275 ;
     RECT  87.84 29.557 90.072 30.275 ;
     RECT  45.6 29.747 45.912 30.277 ;
     RECT  29.136 29.267 35.112 30.323 ;
     RECT  47.52 29.843 48.501 30.325 ;
     RECT  91.152 29.461 91.176 30.325 ;
     RECT  44.736 30.277 45.912 30.467 ;
     RECT  47.184 30.325 48.501 30.467 ;
     RECT  61.008 29.219 62.112 30.467 ;
     RECT  87.84 30.275 89.496 30.467 ;
     RECT  81.12 30.181 81.24 30.563 ;
     RECT  47.52 30.467 48.501 30.611 ;
     RECT  65.856 30.565 65.88 30.613 ;
     RECT  66.912 28.547 68.664 30.613 ;
     RECT  65.856 30.613 68.664 30.707 ;
     RECT  78 29.939 78.312 30.757 ;
     RECT  79.344 29.747 79.368 30.757 ;
     RECT  54.48 29.893 54.504 30.803 ;
     RECT  94.032 29.029 94.68 30.803 ;
     RECT  78 30.757 79.368 30.851 ;
     RECT  90.48 30.325 91.176 30.851 ;
     RECT  88.224 30.467 89.496 30.899 ;
     RECT  78 30.851 78.696 30.947 ;
     RECT  90.48 30.851 90.6 30.947 ;
     RECT  55.92 30.181 59.928 30.995 ;
     RECT  2.304 30.181 27.816 30.997 ;
     RECT  70.704 30.131 73.416 30.997 ;
     RECT  70.464 30.997 73.416 31.187 ;
     RECT  94.032 30.803 94.632 31.187 ;
     RECT  29.4 30.323 35.112 31.189 ;
     RECT  29.4 31.189 35.352 31.379 ;
     RECT  58.8 30.995 59.928 31.379 ;
     RECT  90.576 30.947 90.6 31.379 ;
     RECT  49.536 30.229 51.312 31.427 ;
     RECT  2.304 30.997 28.392 31.429 ;
     RECT  29.4 31.379 32.568 31.429 ;
     RECT  50.88 31.427 51.312 31.477 ;
     RECT  52.464 27.877 52.488 31.477 ;
     RECT  64.176 30.275 64.2 31.477 ;
     RECT  2.304 31.429 32.568 31.571 ;
     RECT  39.216 30.275 40.512 31.619 ;
     RECT  64.176 31.477 65.16 31.619 ;
     RECT  78 30.947 78.312 31.669 ;
     RECT  94.08 31.187 94.632 31.715 ;
     RECT  88.224 30.899 89.4 31.717 ;
     RECT  76.368 30.661 76.392 31.765 ;
     RECT  33.6 31.379 35.352 31.861 ;
     RECT  36.432 27.877 37.032 31.861 ;
     RECT  54.432 31.813 54.456 31.861 ;
     RECT  66.72 30.707 68.664 31.861 ;
     RECT  88.032 31.717 89.4 31.907 ;
     RECT  66.72 31.861 68.808 31.909 ;
     RECT  33.6 31.861 37.032 31.955 ;
     RECT  49.536 31.427 49.56 31.955 ;
     RECT  61.584 30.467 62.112 31.955 ;
     RECT  66.72 31.909 68.904 31.955 ;
     RECT  72.384 31.187 73.416 31.955 ;
     RECT  70.464 31.187 71.4 32.195 ;
     RECT  50.88 31.477 52.488 32.243 ;
     RECT  48.483 30.611 48.501 32.245 ;
     RECT  76.368 31.765 76.92 32.293 ;
     RECT  77.904 31.669 78.312 32.293 ;
     RECT  53.568 31.861 54.456 32.341 ;
     RECT  85.824 28.547 85.848 32.389 ;
     RECT  0.144 29.749 0.552 32.435 ;
     RECT  53.568 32.341 54.888 32.437 ;
     RECT  74.448 30.131 74.904 32.437 ;
     RECT  37.008 31.955 37.032 32.723 ;
     RECT  76.368 32.293 78.312 32.771 ;
     RECT  41.904 32.437 41.928 32.773 ;
     RECT  61.68 31.955 62.112 32.773 ;
     RECT  74.448 32.437 75.24 32.821 ;
     RECT  88.128 31.907 89.4 32.821 ;
     RECT  64.176 31.619 64.728 32.965 ;
     RECT  50.88 32.243 51.576 33.011 ;
     RECT  66.768 31.955 68.904 33.011 ;
     RECT  41.904 32.773 42.504 33.013 ;
     RECT  48.096 32.245 48.501 33.013 ;
     RECT  49.776 32.533 49.8 33.013 ;
     RECT  52.848 32.437 54.888 33.013 ;
     RECT  55.92 30.995 57.624 33.013 ;
     RECT  61.68 32.773 62.904 33.013 ;
     RECT  85.824 32.389 86.328 33.013 ;
     RECT  88.128 32.821 89.784 33.013 ;
     RECT  2.304 31.571 28.392 33.061 ;
     RECT  29.4 31.571 32.568 33.061 ;
     RECT  94.08 31.715 94.512 33.107 ;
     RECT  83.4 29.747 84.504 33.157 ;
     RECT  72.384 31.955 73.176 33.253 ;
     RECT  87.936 33.013 89.784 33.253 ;
     RECT  52.848 33.013 57.624 33.299 ;
     RECT  45.6 30.467 45.912 33.301 ;
     RECT  85.488 33.013 86.328 33.301 ;
     RECT  59.088 31.379 59.256 33.347 ;
     RECT  48.096 33.013 49.8 33.349 ;
     RECT  50.88 33.011 51.312 33.349 ;
     RECT  81.216 30.563 81.24 33.349 ;
     RECT  87.936 33.253 90.6 33.395 ;
     RECT  2.304 33.061 32.568 33.445 ;
     RECT  33.6 31.955 36.024 33.445 ;
     RECT  53.136 33.299 57.624 33.491 ;
     RECT  76.704 32.771 78.312 33.491 ;
     RECT  85.488 33.301 86.664 33.491 ;
     RECT  2.304 33.445 36.024 33.541 ;
     RECT  72.24 33.253 73.176 33.541 ;
     RECT  74.352 32.821 75.24 33.541 ;
     RECT  48.096 33.349 51.312 33.587 ;
     RECT  63.984 32.965 64.728 33.589 ;
     RECT  2.304 33.541 36.744 33.683 ;
     RECT  39.888 31.619 40.512 33.683 ;
     RECT  54.096 33.491 57.624 33.731 ;
     RECT  60.96 33.013 62.904 33.731 ;
     RECT  66.768 33.011 68.808 33.731 ;
     RECT  85.488 33.491 86.568 33.731 ;
     RECT  43.872 33.589 43.896 33.779 ;
     RECT  66.768 33.731 68.184 33.779 ;
     RECT  50.88 33.587 51.312 33.827 ;
     RECT  59.088 33.347 59.112 33.827 ;
     RECT  45.312 33.301 45.912 33.829 ;
     RECT  87.936 33.395 89.784 33.829 ;
     RECT  48.144 33.587 49.8 33.875 ;
     RECT  91.728 32.293 91.752 33.875 ;
     RECT  72.24 33.541 75.24 33.877 ;
     RECT  76.704 33.491 76.728 33.877 ;
     RECT  41.76 33.013 42.792 33.923 ;
     RECT  85.488 33.731 86.52 33.923 ;
     RECT  45.072 33.829 45.912 33.971 ;
     RECT  38.448 33.589 38.472 33.973 ;
     RECT  80.064 33.685 80.088 34.021 ;
     RECT  87.792 33.829 89.784 34.021 ;
     RECT  45.168 33.971 45.912 34.067 ;
     RECT  48.144 33.875 49.464 34.067 ;
     RECT  72.24 33.877 76.728 34.067 ;
     RECT  41.904 33.923 42.792 34.115 ;
     RECT  70.464 32.195 71.256 34.117 ;
     RECT  76.128 34.067 76.728 34.211 ;
     RECT  72.24 34.067 74.904 34.307 ;
     RECT  76.704 34.211 76.728 34.307 ;
     RECT  45.312 34.067 45.912 34.355 ;
     RECT  72.384 34.307 74.904 34.355 ;
     RECT  0.144 32.435 0.408 34.405 ;
     RECT  77.856 33.491 78.312 34.499 ;
     RECT  45.36 34.355 45.912 34.501 ;
     RECT  79.776 34.021 80.088 34.597 ;
     RECT  81.216 33.349 81.72 34.597 ;
     RECT  60.96 33.731 62.112 34.643 ;
     RECT  85.728 33.923 86.52 34.693 ;
     RECT  87.744 34.021 89.784 34.693 ;
     RECT  74.352 34.355 74.904 34.739 ;
     RECT  79.776 34.597 81.72 34.741 ;
     RECT  83.28 33.157 84.504 34.741 ;
     RECT  70.08 34.117 71.256 34.787 ;
     RECT  70.464 34.787 71.256 34.835 ;
     RECT  78 34.499 78.312 34.837 ;
     RECT  79.776 34.741 84.552 34.837 ;
     RECT  72.384 34.355 73.176 34.883 ;
     RECT  74.352 34.739 74.664 34.883 ;
     RECT  41.904 34.115 41.928 34.931 ;
     RECT  61.44 34.643 62.112 34.931 ;
     RECT  58.944 33.877 59.064 34.933 ;
     RECT  2.304 33.683 35.112 34.979 ;
     RECT  85.728 34.693 89.784 34.981 ;
     RECT  45.36 34.501 46.776 35.027 ;
     RECT  58.944 34.933 59.832 35.027 ;
     RECT  38.256 33.973 38.472 35.077 ;
     RECT  38.256 35.077 38.568 35.123 ;
     RECT  51 33.827 51.312 35.221 ;
     RECT  36.48 33.683 36.744 35.317 ;
     RECT  78 34.837 84.552 35.363 ;
     RECT  53.088 35.317 53.112 35.461 ;
     RECT  54.096 33.731 56.712 35.507 ;
     RECT  0.144 34.405 0.552 35.555 ;
     RECT  45.36 35.027 46.488 35.555 ;
     RECT  48.144 34.067 49.032 35.557 ;
     RECT  36.48 35.317 37.032 35.701 ;
     RECT  76.896 35.605 76.92 35.795 ;
     RECT  83.04 35.363 84.552 35.845 ;
     RECT  85.68 34.981 89.784 35.845 ;
     RECT  52.464 35.461 53.112 35.939 ;
     RECT  78 35.363 81.384 35.939 ;
     RECT  0.144 35.555 0.264 36.035 ;
     RECT  83.04 35.845 89.784 36.179 ;
     RECT  81.024 35.939 81.048 36.227 ;
     RECT  83.4 36.179 89.784 36.275 ;
     RECT  43.296 34.741 43.32 36.277 ;
     RECT  50.88 35.221 51.312 36.421 ;
     RECT  72.6 34.883 73.176 36.421 ;
     RECT  74.352 34.883 74.376 36.421 ;
     RECT  87.168 36.275 89.784 36.421 ;
     RECT  50.736 36.421 51.312 36.469 ;
     RECT  52.464 35.939 52.488 36.469 ;
     RECT  43.296 36.277 43.656 36.515 ;
     RECT  78 35.939 79.8 36.515 ;
     RECT  50.736 36.469 52.488 36.517 ;
     RECT  0.144 36.035 0.216 36.563 ;
     RECT  61.68 34.931 62.112 36.563 ;
     RECT  87.168 36.421 89.976 36.563 ;
     RECT  33.6 34.979 35.112 36.613 ;
     RECT  36.432 35.701 37.032 36.613 ;
     RECT  50.352 36.517 52.488 36.707 ;
     RECT  38.304 35.123 38.568 36.755 ;
     RECT  59.328 35.027 59.832 36.757 ;
     RECT  39.936 33.683 40.512 36.803 ;
     RECT  59.28 36.757 59.832 36.803 ;
     RECT  40.032 36.803 40.512 36.805 ;
     RECT  33.6 36.613 37.032 36.851 ;
     RECT  47.904 35.557 49.032 36.949 ;
     RECT  50.352 36.707 51.768 36.949 ;
     RECT  54.432 35.507 56.712 36.949 ;
     RECT  70.896 34.835 71.256 36.997 ;
     RECT  2.304 34.979 32.616 37.091 ;
     RECT  47.904 36.949 51.768 37.091 ;
     RECT  59.28 36.803 59.304 37.091 ;
     RECT  0.192 36.563 0.216 37.139 ;
     RECT  33.6 36.851 35.448 37.139 ;
     RECT  2.304 37.091 31.56 37.283 ;
     RECT  2.304 37.283 31.224 37.379 ;
     RECT  2.304 37.379 21.576 37.427 ;
     RECT  63.888 33.589 64.728 37.429 ;
     RECT  83.4 36.275 85.944 37.429 ;
     RECT  83.4 37.429 86.04 37.475 ;
     RECT  2.304 37.427 21.528 37.523 ;
     RECT  78 36.515 79.464 37.525 ;
     RECT  32.592 37.091 32.616 37.619 ;
     RECT  36.432 36.851 37.032 37.619 ;
     RECT  49.584 37.091 49.608 37.619 ;
     RECT  33.6 37.139 33.624 37.715 ;
     RECT  54.432 36.949 56.856 37.811 ;
     RECT  81.6 37.381 81.624 37.955 ;
     RECT  75.792 36.613 75.816 38.147 ;
     RECT  40.032 36.805 40.728 38.149 ;
     RECT  47.904 37.091 48.6 38.149 ;
     RECT  50.88 37.091 51.768 38.149 ;
     RECT  63.264 37.429 64.728 38.149 ;
     RECT  77.904 37.525 79.464 38.149 ;
     RECT  87.456 36.563 89.976 38.149 ;
     RECT  22.56 37.379 31.224 38.195 ;
     RECT  34.656 37.139 35.448 38.389 ;
     RECT  34.512 38.389 35.448 38.435 ;
     RECT  36.528 37.619 37.032 38.437 ;
     RECT  50.736 38.149 51.768 38.485 ;
     RECT  42.576 38.389 42.6 38.531 ;
     RECT  70.896 36.997 71.592 38.533 ;
     RECT  38.304 36.755 38.328 38.581 ;
     RECT  40.032 38.149 41.016 38.581 ;
     RECT  83.4 37.475 84.984 38.629 ;
     RECT  86.016 37.475 86.04 38.629 ;
     RECT  87.456 38.149 90.264 38.629 ;
     RECT  72.6 36.421 74.376 38.675 ;
     RECT  16.752 37.523 21.528 38.677 ;
     RECT  22.56 38.195 29.712 38.677 ;
     RECT  30.768 38.195 31.224 38.677 ;
     RECT  45.6 35.555 46.488 38.677 ;
     RECT  47.904 38.149 49.08 38.677 ;
     RECT  38.304 38.581 41.016 38.723 ;
     RECT  45.6 38.677 49.08 38.723 ;
     RECT  77.904 38.149 79.56 38.723 ;
     RECT  50.736 38.485 52.68 38.771 ;
     RECT  86.016 38.629 90.264 38.771 ;
     RECT  54.432 37.811 56.808 38.773 ;
     RECT  82.032 38.245 82.2 38.773 ;
     RECT  83.232 38.629 84.984 38.773 ;
     RECT  86.016 38.771 86.04 38.819 ;
     RECT  75.84 38.773 75.864 38.915 ;
     RECT  70.416 38.533 71.592 38.917 ;
     RECT  72.6 38.675 73.176 38.917 ;
     RECT  40.032 38.723 41.016 39.011 ;
     RECT  82.032 38.773 84.984 39.011 ;
     RECT  87.456 38.771 90.264 39.013 ;
     RECT  36.528 38.437 37.224 39.059 ;
     RECT  2.304 37.523 15.72 39.061 ;
     RECT  16.752 38.677 29.712 39.061 ;
     RECT  54.432 38.773 56.904 39.061 ;
     RECT  50.736 38.771 51.768 39.107 ;
     RECT  54.432 39.061 57.048 39.107 ;
     RECT  61.8 36.563 62.112 39.109 ;
     RECT  66.768 33.779 67.512 39.109 ;
     RECT  76.656 39.109 76.776 39.251 ;
     RECT  45.6 38.723 47.352 39.253 ;
     RECT  54.432 39.107 54.888 39.253 ;
     RECT  36.528 39.059 36.648 39.299 ;
     RECT  84.912 39.011 84.984 39.301 ;
     RECT  70.416 38.917 73.176 39.395 ;
     RECT  87.456 39.013 91.032 39.395 ;
     RECT  59.232 38.005 59.256 39.397 ;
     RECT  59.232 39.397 59.784 39.491 ;
     RECT  38.304 38.723 39.048 39.539 ;
     RECT  30.768 38.677 31.368 39.637 ;
     RECT  48.483 38.723 49.08 39.733 ;
     RECT  66.768 39.109 67.608 39.733 ;
     RECT  68.784 36.613 68.808 39.733 ;
     RECT  87.456 39.395 89.976 39.733 ;
     RECT  59.76 39.491 59.784 39.779 ;
     RECT  61.8 39.109 62.232 39.781 ;
     RECT  63.264 38.149 65.112 39.781 ;
     RECT  2.304 39.061 29.712 39.829 ;
     RECT  30.768 39.637 32.28 39.829 ;
     RECT  34.512 38.435 35.304 39.829 ;
     RECT  70.464 39.395 73.176 39.875 ;
     RECT  40.2 39.011 41.016 39.877 ;
     RECT  61.8 39.781 65.112 39.877 ;
     RECT  45.216 39.253 47.352 39.923 ;
     RECT  50.736 39.107 51.432 39.923 ;
     RECT  61.152 39.877 65.112 39.923 ;
     RECT  82.032 39.011 83.88 39.923 ;
     RECT  91.008 39.395 91.032 39.923 ;
     RECT  86.592 39.733 89.976 40.019 ;
     RECT  84.912 39.301 85.272 40.117 ;
     RECT  43.632 36.515 43.656 40.165 ;
     RECT  48.483 39.733 49.608 40.165 ;
     RECT  83.232 39.923 83.88 40.165 ;
     RECT  84.912 40.117 85.416 40.165 ;
     RECT  53.568 39.253 54.888 40.261 ;
     RECT  56.4 39.107 57.048 40.261 ;
     RECT  2.304 39.829 32.616 40.307 ;
     RECT  53.568 40.261 57.048 40.403 ;
     RECT  61.152 39.923 62.76 40.405 ;
     RECT  70.656 39.875 73.176 40.405 ;
     RECT  74.352 38.675 74.376 40.405 ;
     RECT  76.656 39.251 76.68 40.405 ;
     RECT  78 38.723 79.56 40.405 ;
     RECT  82.032 39.923 82.056 40.405 ;
     RECT  88.032 40.019 89.976 40.451 ;
     RECT  34.512 39.829 35.352 40.453 ;
     RECT  88.416 40.451 89.976 40.499 ;
     RECT  56.4 40.403 57.048 40.549 ;
     RECT  2.304 40.307 20.088 40.595 ;
     RECT  88.512 40.499 89.976 40.691 ;
     RECT  76.656 40.405 79.56 40.739 ;
     RECT  33.696 40.453 35.352 40.787 ;
     RECT  0.432 40.645 0.456 40.837 ;
     RECT  40.2 39.877 41.64 40.883 ;
     RECT  0.384 40.837 0.456 40.933 ;
     RECT  77.472 40.739 79.56 40.933 ;
     RECT  21.072 40.307 32.616 40.979 ;
     RECT  81.6 40.405 82.056 40.981 ;
     RECT  83.232 40.165 85.416 40.981 ;
     RECT  33.696 40.787 35.112 41.075 ;
     RECT  45.216 39.923 46.488 41.075 ;
     RECT  61.056 40.405 62.76 41.123 ;
     RECT  60.48 41.173 60.504 41.219 ;
     RECT  81.6 40.981 85.416 41.219 ;
     RECT  86.592 40.019 86.616 41.269 ;
     RECT  23.904 40.979 32.616 41.363 ;
     RECT  36.528 39.299 36.552 41.363 ;
     RECT  70.656 40.405 75.288 41.411 ;
     RECT  82.032 41.219 85.416 41.459 ;
     RECT  48.384 40.165 49.608 41.461 ;
     RECT  2.4 40.595 20.088 41.557 ;
     RECT  21.072 40.979 22.824 41.557 ;
     RECT  53.568 40.403 55.272 41.557 ;
     RECT  56.4 40.549 57.576 41.557 ;
     RECT  38.448 39.539 39.048 41.605 ;
     RECT  45.6 41.075 46.488 41.605 ;
     RECT  23.904 41.363 31.224 41.651 ;
     RECT  70.896 41.411 75.288 41.651 ;
     RECT  61.8 41.123 62.76 41.747 ;
     RECT  70.896 41.651 73.512 41.747 ;
     RECT  77.472 40.933 80.424 41.747 ;
     RECT  90.096 40.981 90.12 41.749 ;
     RECT  50.736 39.923 51.312 41.797 ;
     RECT  37.776 41.605 39.048 41.845 ;
     RECT  40.2 40.883 41.016 41.845 ;
     RECT  90.096 41.749 90.216 41.845 ;
     RECT  91.728 40.405 91.752 41.845 ;
     RECT  53.568 41.557 57.576 41.939 ;
     RECT  72.288 41.747 73.512 41.939 ;
     RECT  90.096 41.845 91.752 41.939 ;
     RECT  0.24 40.933 0.456 41.941 ;
     RECT  54.432 41.939 57.576 41.987 ;
     RECT  0.192 41.941 0.456 41.989 ;
     RECT  48.384 41.461 49.704 41.989 ;
     RECT  50.736 41.797 52.056 41.989 ;
     RECT  32.256 41.363 32.616 42.133 ;
     RECT  75.264 41.651 75.288 42.133 ;
     RECT  77.808 41.747 80.424 42.133 ;
     RECT  42.912 40.165 43.656 42.181 ;
     RECT  42.816 42.181 43.656 42.227 ;
     RECT  48.384 41.989 52.056 42.229 ;
     RECT  2.4 41.557 22.824 42.277 ;
     RECT  82.032 41.459 82.056 42.277 ;
     RECT  63.888 39.923 65.112 42.323 ;
     RECT  81.696 42.277 82.056 42.323 ;
     RECT  42.816 42.227 43.56 42.371 ;
     RECT  83.4 41.459 85.416 42.421 ;
     RECT  48.384 42.229 52.248 42.515 ;
     RECT  88.512 40.691 89.112 42.515 ;
     RECT  0.192 41.989 0.552 42.565 ;
     RECT  59.28 41.797 59.304 42.613 ;
     RECT  32.256 42.133 32.76 42.661 ;
     RECT  0.192 42.565 0.84 42.709 ;
     RECT  66.768 39.733 68.808 42.709 ;
     RECT  88.8 42.515 89.112 42.709 ;
     RECT  90.096 41.939 90.936 42.709 ;
     RECT  32.256 42.661 33.096 42.803 ;
     RECT  37.776 41.845 41.016 42.803 ;
     RECT  2.304 42.277 22.824 42.805 ;
     RECT  24 41.651 31.224 42.805 ;
     RECT  43.392 42.371 43.56 42.851 ;
     RECT  0.144 42.709 0.84 42.899 ;
     RECT  61.8 41.747 62.112 42.949 ;
     RECT  59.184 42.613 59.304 42.995 ;
     RECT  48.384 42.515 52.056 43.043 ;
     RECT  72.288 41.939 73.464 43.045 ;
     RECT  75.264 42.133 75.912 43.045 ;
     RECT  0.192 42.899 0.84 43.091 ;
     RECT  74.64 43.045 75.912 43.091 ;
     RECT  54.432 41.987 56.808 43.187 ;
     RECT  48.384 43.043 51.816 43.189 ;
     RECT  86.592 41.269 87.336 43.189 ;
     RECT  88.8 42.709 90.936 43.189 ;
     RECT  83.28 42.421 85.416 43.237 ;
     RECT  86.592 43.189 87.72 43.237 ;
     RECT  71.952 43.045 73.464 43.283 ;
     RECT  75.888 43.091 75.912 43.283 ;
     RECT  45.6 41.605 46.728 43.285 ;
     RECT  54.432 43.187 55.176 43.285 ;
     RECT  88.8 43.189 91.704 43.285 ;
     RECT  32.736 42.803 33.096 43.331 ;
     RECT  83.28 43.237 87.72 43.331 ;
     RECT  72.336 43.283 73.464 43.333 ;
     RECT  2.304 42.805 31.224 43.379 ;
     RECT  72.336 43.333 73.56 43.427 ;
     RECT  63.888 42.323 65.064 43.573 ;
     RECT  83.4 43.331 87.72 43.619 ;
     RECT  63.744 43.573 65.064 43.717 ;
     RECT  47.712 43.189 51.816 43.763 ;
     RECT  61.68 42.949 62.112 43.765 ;
     RECT  44.736 43.285 46.728 43.813 ;
     RECT  47.712 43.763 48.501 43.813 ;
     RECT  60.483 41.219 60.501 43.813 ;
     RECT  61.68 43.765 62.712 43.813 ;
     RECT  44.736 43.813 48.501 43.859 ;
     RECT  49.728 43.763 51.816 43.907 ;
     RECT  0.24 43.091 0.84 44.051 ;
     RECT  59.184 42.995 59.208 44.051 ;
     RECT  60.483 43.813 62.712 44.053 ;
     RECT  54.144 43.285 55.176 44.099 ;
     RECT  81.696 42.323 81.72 44.099 ;
     RECT  34.224 41.075 35.112 44.101 ;
     RECT  38.448 42.803 41.016 44.147 ;
     RECT  56.4 43.187 56.808 44.147 ;
     RECT  72.432 43.427 73.56 44.197 ;
     RECT  74.64 43.091 74.664 44.197 ;
     RECT  0.24 44.051 0.504 44.243 ;
     RECT  66.768 42.709 68.904 44.243 ;
     RECT  56.4 44.147 56.712 44.341 ;
     RECT  0.24 44.243 0.456 44.437 ;
     RECT  31.2 43.379 31.224 44.437 ;
     RECT  33.072 43.331 33.096 44.483 ;
     RECT  38.928 44.147 41.016 44.483 ;
     RECT  0.144 44.437 0.456 44.531 ;
     RECT  72.432 44.197 74.664 44.627 ;
     RECT  2.304 43.379 30.216 44.675 ;
     RECT  52.752 44.437 52.776 44.773 ;
     RECT  88.8 43.285 91.752 44.821 ;
     RECT  2.304 44.675 22.968 44.867 ;
     RECT  60.192 44.053 62.712 44.867 ;
     RECT  31.2 44.437 31.896 44.869 ;
     RECT  36.96 44.773 36.984 44.869 ;
     RECT  72.432 44.627 72.912 44.869 ;
     RECT  14.832 44.867 22.968 44.915 ;
     RECT  36.96 44.869 37.848 44.915 ;
     RECT  52.752 44.773 53.016 44.915 ;
     RECT  86.592 43.619 87.72 44.917 ;
     RECT  88.8 44.821 91.992 44.917 ;
     RECT  66.768 44.243 68.76 44.963 ;
     RECT  49.728 43.907 51.312 44.965 ;
     RECT  63.744 43.717 65.592 44.965 ;
     RECT  37.632 44.915 37.848 45.011 ;
     RECT  41.616 44.677 41.64 45.011 ;
     RECT  60.192 44.867 62.112 45.011 ;
     RECT  63.744 44.965 65.64 45.011 ;
     RECT  34.224 44.101 35.736 45.059 ;
     RECT  38.928 44.483 40.512 45.059 ;
     RECT  43.392 42.851 43.416 45.059 ;
     RECT  44.736 43.859 47.4 45.059 ;
     RECT  74.112 44.627 74.664 45.157 ;
     RECT  14.832 44.915 21.432 45.203 ;
     RECT  24 44.675 30.216 45.203 ;
     RECT  70.896 41.747 70.92 45.205 ;
     RECT  24 45.203 28.008 45.395 ;
     RECT  14.928 45.203 21.432 45.491 ;
     RECT  0.144 44.531 0.408 45.493 ;
     RECT  24 45.395 26.04 45.539 ;
     RECT  83.4 43.619 85.416 45.541 ;
     RECT  86.592 44.917 91.992 45.541 ;
     RECT  14.928 45.491 21.336 45.587 ;
     RECT  54.192 44.099 55.176 45.635 ;
     RECT  74.112 45.157 75.576 45.635 ;
     RECT  2.304 44.867 13.8 45.683 ;
     RECT  22.8 44.915 22.968 45.683 ;
     RECT  27.072 45.395 28.008 45.683 ;
     RECT  25.776 45.539 26.04 45.731 ;
     RECT  37.632 45.011 37.656 45.731 ;
     RECT  14.928 45.587 21.288 45.827 ;
     RECT  54.432 45.635 55.176 45.827 ;
     RECT  17.52 45.827 21.288 45.875 ;
     RECT  72.384 44.869 72.912 45.923 ;
     RECT  0.144 45.493 0.456 45.925 ;
     RECT  76.608 45.877 76.632 45.925 ;
     RECT  77.808 42.133 80.664 45.925 ;
     RECT  17.664 45.875 21.288 45.971 ;
     RECT  17.856 45.971 21.288 46.019 ;
     RECT  83.28 45.541 91.992 46.069 ;
     RECT  83.232 46.069 91.992 46.115 ;
     RECT  48.384 43.859 48.501 46.117 ;
     RECT  47.856 46.117 48.501 46.165 ;
     RECT  49.488 44.965 51.312 46.165 ;
     RECT  44.736 45.059 46.728 46.211 ;
     RECT  85.728 46.115 91.992 46.211 ;
     RECT  24 45.539 24.792 46.213 ;
     RECT  25.872 45.731 26.04 46.259 ;
     RECT  85.728 46.211 90.984 46.259 ;
     RECT  85.728 46.259 90.696 46.307 ;
     RECT  34.272 45.059 35.736 46.357 ;
     RECT  23.904 46.213 24.792 46.403 ;
     RECT  27.36 45.683 28.008 46.501 ;
     RECT  29.4 45.203 30.216 46.501 ;
     RECT  81.936 45.781 81.96 46.501 ;
     RECT  83.232 46.115 84.648 46.501 ;
     RECT  39.744 45.059 40.512 46.547 ;
     RECT  2.4 45.683 13.8 46.595 ;
     RECT  34.272 46.357 35.88 46.643 ;
     RECT  76.608 45.925 80.664 46.643 ;
     RECT  70.896 45.205 71.304 46.645 ;
     RECT  77.328 46.643 80.664 46.693 ;
     RECT  52.752 44.915 52.872 46.739 ;
     RECT  24 46.403 24.792 46.789 ;
     RECT  66.768 44.963 68.424 46.789 ;
     RECT  69.6 46.069 69.624 46.789 ;
     RECT  72.432 45.923 72.912 46.835 ;
     RECT  0.144 45.925 0.552 46.883 ;
     RECT  2.4 46.595 13.704 46.883 ;
     RECT  66.768 46.789 69.624 46.883 ;
     RECT  14.928 45.827 16.296 46.885 ;
     RECT  27.36 46.501 30.216 46.885 ;
     RECT  31.2 44.869 32.52 46.885 ;
     RECT  0.144 46.883 0.312 46.931 ;
     RECT  24 46.789 24.888 46.931 ;
     RECT  72.6 46.835 72.912 46.933 ;
     RECT  27.36 46.885 32.52 47.027 ;
     RECT  77.328 46.693 80.904 47.027 ;
     RECT  77.52 47.027 80.904 47.075 ;
     RECT  54.576 45.827 55.176 47.077 ;
     RECT  44.736 46.211 46.344 47.123 ;
     RECT  56.304 44.341 56.712 47.123 ;
     RECT  44.736 47.123 46.2 47.125 ;
     RECT  81.936 46.501 84.648 47.219 ;
     RECT  2.4 46.883 10.824 47.317 ;
     RECT  63.888 45.011 63.912 47.317 ;
     RECT  77.52 47.075 80.568 47.363 ;
     RECT  29.28 47.027 32.52 47.411 ;
     RECT  34.656 46.643 35.88 47.411 ;
     RECT  72.6 46.933 73.08 47.413 ;
     RECT  74.208 45.635 75.576 47.413 ;
     RECT  72.6 47.413 75.576 47.459 ;
     RECT  18.144 46.019 21.288 47.461 ;
     RECT  22.752 46.405 22.776 47.461 ;
     RECT  85.728 46.307 89.592 47.509 ;
     RECT  90.576 46.307 90.696 47.509 ;
     RECT  29.28 47.411 32.088 47.603 ;
     RECT  18.144 47.461 22.776 47.651 ;
     RECT  54.336 47.077 55.176 47.653 ;
     RECT  66.864 46.883 69.624 47.701 ;
     RECT  70.896 46.645 71.4 47.701 ;
     RECT  72.6 47.459 73.944 47.747 ;
     RECT  24 46.931 24.312 47.749 ;
     RECT  40.08 46.547 40.512 47.797 ;
     RECT  47.856 46.165 51.312 47.843 ;
     RECT  2.304 47.317 10.824 47.845 ;
     RECT  11.856 46.883 13.704 47.845 ;
     RECT  66.864 47.701 71.4 47.845 ;
     RECT  72.6 47.747 72.912 47.845 ;
     RECT  81.936 47.219 84.408 47.891 ;
     RECT  26.016 46.259 26.04 47.893 ;
     RECT  66.864 47.845 72.912 47.939 ;
     RECT  0.144 46.931 0.264 47.941 ;
     RECT  40.032 47.797 40.512 47.941 ;
     RECT  29.28 47.603 31.896 47.987 ;
     RECT  52.512 47.173 52.536 47.989 ;
     RECT  54.144 47.653 55.176 47.989 ;
     RECT  85.728 47.509 90.696 48.035 ;
     RECT  85.728 48.035 90.072 48.083 ;
     RECT  91.968 46.211 91.992 48.083 ;
     RECT  73.92 47.747 73.944 48.131 ;
     RECT  60.483 45.011 62.112 48.133 ;
     RECT  52.512 47.989 55.176 48.179 ;
     RECT  34.656 47.411 35.832 48.227 ;
     RECT  14.928 46.885 16.584 48.277 ;
     RECT  18.432 47.651 22.776 48.277 ;
     RECT  34.656 48.227 35.688 48.277 ;
     RECT  63.408 47.317 63.912 48.277 ;
     RECT  65.04 45.011 65.64 48.277 ;
     RECT  81.936 47.891 82.2 48.323 ;
     RECT  0.144 47.941 0.312 48.325 ;
     RECT  2.304 47.845 13.704 48.325 ;
     RECT  44.64 47.125 46.2 48.325 ;
     RECT  14.928 48.277 17.016 48.373 ;
     RECT  18.432 48.277 22.824 48.419 ;
     RECT  29.28 47.987 31.224 48.419 ;
     RECT  14.928 48.373 17.064 48.421 ;
     RECT  58.848 47.221 58.872 48.421 ;
     RECT  53.376 48.179 55.176 48.467 ;
     RECT  63.408 48.277 65.64 48.467 ;
     RECT  18.432 48.419 22.632 48.515 ;
     RECT  83.232 47.891 84.408 48.515 ;
     RECT  0.144 48.325 0.36 48.517 ;
     RECT  25.344 47.893 26.04 48.517 ;
     RECT  27.36 47.027 28.008 48.517 ;
     RECT  44.64 48.325 46.488 48.563 ;
     RECT  44.736 48.563 46.488 48.611 ;
     RECT  68.928 47.939 72.912 48.611 ;
     RECT  75.264 47.459 75.576 48.611 ;
     RECT  58.704 48.421 58.872 48.613 ;
     RECT  2.304 48.325 13.752 48.659 ;
     RECT  42.672 47.845 42.696 48.659 ;
     RECT  54.144 48.467 54.264 48.659 ;
     RECT  66.864 47.939 67.608 48.659 ;
     RECT  36.864 48.613 36.888 48.755 ;
     RECT  11.856 48.659 13.752 48.757 ;
     RECT  14.784 48.421 17.064 48.757 ;
     RECT  11.856 48.757 17.064 48.853 ;
     RECT  81.936 48.323 81.96 48.853 ;
     RECT  0.144 48.517 0.6 48.901 ;
     RECT  66.864 48.659 67.512 48.949 ;
     RECT  64.128 48.467 65.64 48.995 ;
     RECT  76.944 48.901 76.968 48.997 ;
     RECT  64.128 48.995 64.296 49.043 ;
     RECT  76.848 48.997 76.968 49.043 ;
     RECT  81.792 48.853 81.96 49.043 ;
     RECT  11.856 48.853 17.208 49.045 ;
     RECT  18.432 48.515 22.536 49.045 ;
     RECT  40.032 47.941 41.16 49.045 ;
     RECT  44.976 48.611 46.488 49.045 ;
     RECT  60.336 48.133 62.112 49.091 ;
     RECT  70.944 48.611 72.912 49.093 ;
     RECT  76.848 49.043 76.872 49.139 ;
     RECT  60.48 49.091 62.112 49.141 ;
     RECT  70.944 49.093 73.08 49.187 ;
     RECT  66.768 48.949 67.512 49.189 ;
     RECT  32.304 48.613 32.328 49.235 ;
     RECT  60.48 49.141 62.952 49.283 ;
     RECT  23.856 47.749 24.312 49.285 ;
     RECT  25.344 48.517 28.008 49.285 ;
     RECT  48.144 47.843 51.312 49.285 ;
     RECT  58.704 48.613 59.256 49.285 ;
     RECT  81.936 49.043 81.96 49.285 ;
     RECT  85.728 48.083 89.688 49.331 ;
     RECT  58.32 49.285 59.256 49.429 ;
     RECT  64.176 49.043 64.296 49.523 ;
     RECT  81.936 49.285 82.056 49.523 ;
     RECT  29.28 48.419 29.712 49.525 ;
     RECT  72.096 49.187 73.08 49.525 ;
     RECT  23.856 49.285 28.008 49.571 ;
     RECT  47.568 49.285 51.312 49.571 ;
     RECT  57.984 49.429 59.256 49.571 ;
     RECT  78 47.363 80.568 49.619 ;
     RECT  2.304 48.659 10.824 49.621 ;
     RECT  11.856 49.045 22.536 49.621 ;
     RECT  44.976 49.045 46.584 49.667 ;
     RECT  56.4 47.123 56.712 49.813 ;
     RECT  58.32 49.571 59.256 49.907 ;
     RECT  80.544 49.619 80.568 49.907 ;
     RECT  29.04 49.525 29.712 49.909 ;
     RECT  30.816 48.419 31.224 49.909 ;
     RECT  66.72 49.189 67.512 49.909 ;
     RECT  0.144 48.901 0.696 49.955 ;
     RECT  54.24 48.659 54.264 49.955 ;
     RECT  56.4 49.813 56.808 49.955 ;
     RECT  66.72 49.909 67.608 50.051 ;
     RECT  68.928 48.611 69.624 50.051 ;
     RECT  72.096 49.525 73.512 50.101 ;
     RECT  82.032 49.523 82.056 50.101 ;
     RECT  83.232 48.515 83.88 50.101 ;
     RECT  40.032 49.045 41.736 50.195 ;
     RECT  23.856 49.571 24.312 50.245 ;
     RECT  34.032 48.277 35.688 50.339 ;
     RECT  65.568 48.995 65.64 50.387 ;
     RECT  23.568 50.245 24.312 50.533 ;
     RECT  25.344 49.571 28.008 50.533 ;
     RECT  48.048 49.571 51.312 50.579 ;
     RECT  2.304 49.621 22.536 50.581 ;
     RECT  23.568 50.533 28.008 50.581 ;
     RECT  53.04 50.485 53.064 50.627 ;
     RECT  64.176 49.523 64.2 50.677 ;
     RECT  66.72 50.051 67.512 50.677 ;
     RECT  64.176 50.677 65.064 50.821 ;
     RECT  45.024 49.667 46.584 50.867 ;
     RECT  43.584 50.773 43.608 50.963 ;
     RECT  56.4 49.955 56.712 51.061 ;
     RECT  58.32 49.907 59.208 51.061 ;
     RECT  48.144 50.579 51.312 51.109 ;
     RECT  72.096 50.101 73.896 51.109 ;
     RECT  75.264 48.611 75.288 51.109 ;
     RECT  78 49.619 79.56 51.157 ;
     RECT  56.4 51.061 59.208 51.205 ;
     RECT  77.472 51.157 79.56 51.253 ;
     RECT  80.64 51.061 80.664 51.253 ;
     RECT  40.032 50.195 41.448 51.349 ;
     RECT  88.8 49.331 89.688 51.349 ;
     RECT  29.04 49.909 31.224 51.395 ;
     RECT  66.288 50.677 67.512 51.395 ;
     RECT  72.096 51.109 75.288 51.395 ;
     RECT  0.144 49.955 0.6 51.443 ;
     RECT  56.304 51.205 59.208 51.443 ;
     RECT  70.944 49.187 70.968 51.445 ;
     RECT  88.8 51.349 90.264 51.493 ;
     RECT  70.944 51.445 71.064 51.539 ;
     RECT  34.032 50.339 35.112 51.541 ;
     RECT  40.032 51.349 41.64 51.541 ;
     RECT  71.04 51.539 71.064 51.587 ;
     RECT  63.744 50.821 65.064 51.635 ;
     RECT  37.584 50.101 37.608 51.637 ;
     RECT  37.584 51.637 37.896 51.683 ;
     RECT  60.48 49.283 62.232 51.685 ;
     RECT  34.032 51.541 35.208 51.731 ;
     RECT  40.032 51.541 41.736 51.731 ;
     RECT  85.728 49.331 87.72 51.731 ;
     RECT  88.8 51.493 90.648 51.779 ;
     RECT  60.48 51.685 63 51.827 ;
     RECT  48.144 51.109 51.96 51.829 ;
     RECT  86.736 51.731 87.72 51.829 ;
     RECT  88.8 51.779 89.688 51.829 ;
     RECT  48.144 51.829 52.584 51.877 ;
     RECT  0.144 51.443 0.552 51.923 ;
     RECT  2.304 50.581 28.008 51.923 ;
     RECT  77.472 51.253 80.664 51.923 ;
     RECT  64.176 51.635 65.064 52.019 ;
     RECT  47.856 51.877 52.584 52.163 ;
     RECT  68.928 50.051 68.952 52.405 ;
     RECT  72.096 51.395 72.912 52.405 ;
     RECT  74.064 51.395 75.288 52.405 ;
     RECT  32.448 51.637 32.472 52.451 ;
     RECT  77.472 51.923 79.848 52.451 ;
     RECT  72.096 52.405 75.864 52.453 ;
     RECT  48.48 52.163 52.584 52.499 ;
     RECT  78 52.451 79.848 52.499 ;
     RECT  45.6 50.867 46.584 52.547 ;
     RECT  38.88 51.205 38.904 52.549 ;
     RECT  40.032 51.731 41.64 52.549 ;
     RECT  37.872 51.683 37.896 52.693 ;
     RECT  64.176 52.019 65.016 52.789 ;
     RECT  54.384 50.965 54.408 52.837 ;
     RECT  0.144 51.923 0.408 52.933 ;
     RECT  80.832 52.357 80.856 52.981 ;
     RECT  36.96 52.693 37.896 53.027 ;
     RECT  2.304 51.923 19.56 53.029 ;
     RECT  20.592 51.923 28.008 53.029 ;
     RECT  66.864 51.395 67.512 53.029 ;
     RECT  38.88 52.549 41.64 53.075 ;
     RECT  48.48 52.499 51.96 53.075 ;
     RECT  72.048 52.453 75.864 53.075 ;
     RECT  86.736 51.829 89.688 53.075 ;
     RECT  53.424 52.837 54.408 53.171 ;
     RECT  66.48 53.029 67.512 53.171 ;
     RECT  60.48 51.827 62.232 53.173 ;
     RECT  63.312 52.789 65.016 53.173 ;
     RECT  34.032 51.731 35.112 53.221 ;
     RECT  38.88 53.075 40.968 53.267 ;
     RECT  53.52 53.171 54.408 53.317 ;
     RECT  82.032 50.101 83.88 53.317 ;
     RECT  85.728 51.731 85.752 53.317 ;
     RECT  86.736 53.075 89.112 53.317 ;
     RECT  48.48 53.075 51.912 53.365 ;
     RECT  72.048 53.075 75.768 53.507 ;
     RECT  0.144 52.933 0.456 53.509 ;
     RECT  80.832 52.981 80.952 53.509 ;
     RECT  82.032 53.317 84.408 53.509 ;
     RECT  48.192 53.365 51.912 53.555 ;
     RECT  72.48 53.507 75.288 53.555 ;
     RECT  29.136 51.395 31.224 53.557 ;
     RECT  32.448 53.413 32.472 53.557 ;
     RECT  53.52 53.317 55.272 53.603 ;
     RECT  80.832 53.509 84.408 53.653 ;
     RECT  85.728 53.317 89.112 53.699 ;
     RECT  80.784 53.653 84.408 53.795 ;
     RECT  45.6 52.547 46.488 53.797 ;
     RECT  60.48 53.173 65.016 53.797 ;
     RECT  70.416 53.653 70.44 53.843 ;
     RECT  45.12 53.797 46.488 53.893 ;
     RECT  68.784 52.405 68.952 53.939 ;
     RECT  56.4 51.443 59.208 53.989 ;
     RECT  87.696 53.699 89.112 54.037 ;
     RECT  29.136 53.557 32.472 54.179 ;
     RECT  87.696 54.037 89.4 54.179 ;
     RECT  80.928 53.795 84.408 54.227 ;
     RECT  53.52 53.603 54.408 54.275 ;
     RECT  80.928 54.227 81.432 54.275 ;
     RECT  82.656 54.227 84.408 54.275 ;
     RECT  29.136 54.179 32.088 54.373 ;
     RECT  34.032 53.221 35.736 54.419 ;
     RECT  60.48 53.797 65.16 54.613 ;
     RECT  60.48 54.613 65.256 54.659 ;
     RECT  39.792 53.267 40.968 54.707 ;
     RECT  55.44 53.989 59.208 54.709 ;
     RECT  78 52.499 79.56 54.709 ;
     RECT  2.304 53.029 28.008 54.755 ;
     RECT  2.4 54.755 28.008 54.851 ;
     RECT  45.024 53.893 46.488 54.949 ;
     RECT  72.48 53.555 72.912 54.949 ;
     RECT  74.112 53.555 75.288 54.949 ;
     RECT  85.728 53.699 86.664 54.949 ;
     RECT  87.696 54.179 87.72 54.949 ;
     RECT  85.728 54.949 87.72 54.995 ;
     RECT  48.48 53.555 51.912 55.045 ;
     RECT  53.52 54.275 53.544 55.045 ;
     RECT  77.904 54.709 79.56 55.045 ;
     RECT  44.88 54.949 46.488 55.091 ;
     RECT  54.672 54.709 59.208 55.091 ;
     RECT  54.672 55.091 57.528 55.139 ;
     RECT  72.48 54.949 75.288 55.187 ;
     RECT  40.2 54.707 40.968 55.189 ;
     RECT  61.584 54.659 65.256 55.237 ;
     RECT  66.864 53.171 67.512 55.237 ;
     RECT  74.16 55.187 75.288 55.333 ;
     RECT  77.904 55.045 79.752 55.379 ;
     RECT  74.16 55.333 76.248 55.475 ;
     RECT  58.512 55.091 59.208 55.525 ;
     RECT  60.48 54.659 60.504 55.525 ;
     RECT  72.48 55.187 72.912 55.573 ;
     RECT  82.944 54.275 84.408 55.715 ;
     RECT  29.04 54.373 32.088 55.763 ;
     RECT  48.48 55.045 53.544 55.763 ;
     RECT  0.144 53.509 0.504 55.765 ;
     RECT  40.2 55.189 41.016 55.813 ;
     RECT  88.8 54.179 89.4 55.813 ;
     RECT  2.4 54.851 27.816 55.861 ;
     RECT  54.672 55.139 54.744 55.861 ;
     RECT  72.096 55.573 72.912 55.861 ;
     RECT  83.4 55.715 84.408 55.907 ;
     RECT  48.48 55.763 51.912 55.955 ;
     RECT  61.584 55.237 67.512 55.955 ;
     RECT  2.304 55.861 27.816 56.003 ;
     RECT  61.584 55.955 65.256 56.003 ;
     RECT  78 55.379 79.752 56.101 ;
     RECT  56.4 55.139 57.528 56.149 ;
     RECT  37.872 53.027 37.896 56.243 ;
     RECT  56.304 56.149 57.528 56.245 ;
     RECT  58.512 55.525 60.504 56.245 ;
     RECT  81.408 54.275 81.432 56.245 ;
     RECT  54.576 55.861 54.744 56.291 ;
     RECT  85.728 54.995 85.752 56.341 ;
     RECT  86.88 54.995 87.72 56.341 ;
     RECT  21.264 56.003 27.816 56.387 ;
     RECT  78 56.101 79.848 56.389 ;
     RECT  40.2 55.813 41.832 56.437 ;
     RECT  56.304 56.245 60.504 56.483 ;
     RECT  91.728 49.477 91.752 56.483 ;
     RECT  74.16 55.475 75.288 56.533 ;
     RECT  85.728 56.341 87.72 56.581 ;
     RECT  43.92 55.237 43.944 56.629 ;
     RECT  44.976 55.091 46.488 56.629 ;
     RECT  53.328 55.763 53.544 56.725 ;
     RECT  84.912 56.581 87.72 56.773 ;
     RECT  88.8 55.813 89.544 56.773 ;
     RECT  84.912 56.773 89.544 56.819 ;
     RECT  54.72 56.291 54.744 56.869 ;
     RECT  56.304 56.483 57.24 56.965 ;
     RECT  29.04 55.763 31.896 57.011 ;
     RECT  52.512 56.725 53.544 57.011 ;
     RECT  58.224 56.483 60.504 57.011 ;
     RECT  68.784 53.939 68.808 57.059 ;
     RECT  48.48 55.955 51.432 57.061 ;
     RECT  74.16 56.533 75.912 57.061 ;
     RECT  61.584 56.003 62.232 57.107 ;
     RECT  33.024 56.965 33.048 57.109 ;
     RECT  85.728 56.819 89.544 57.155 ;
     RECT  81.408 56.245 82.2 57.205 ;
     RECT  83.4 55.907 83.88 57.205 ;
     RECT  58.56 57.011 60.504 57.251 ;
     RECT  71.52 55.861 72.912 57.251 ;
     RECT  21.36 56.387 27.816 57.299 ;
     RECT  40.08 56.437 41.832 57.299 ;
     RECT  81.408 57.205 83.88 57.301 ;
     RECT  48.48 57.061 52.248 57.347 ;
     RECT  59.184 57.251 60.504 57.347 ;
     RECT  2.304 56.003 20.088 57.349 ;
     RECT  33.024 57.109 33.816 57.395 ;
     RECT  38.496 57.205 38.52 57.443 ;
     RECT  86.88 57.155 89.544 57.541 ;
     RECT  90.72 57.109 90.744 57.541 ;
     RECT  54.72 56.869 54.84 57.589 ;
     RECT  55.824 56.965 57.24 57.589 ;
     RECT  29.04 57.011 31.848 57.635 ;
     RECT  63.84 56.003 65.256 57.635 ;
     RECT  53.328 57.011 53.544 57.637 ;
     RECT  54.72 57.589 57.24 57.637 ;
     RECT  64.128 57.635 65.256 57.683 ;
     RECT  0.144 55.765 0.552 57.731 ;
     RECT  53.328 57.637 57.24 57.781 ;
     RECT  81.408 57.301 84.744 57.781 ;
     RECT  53.328 57.781 57.336 57.827 ;
     RECT  29.136 57.635 31.848 57.875 ;
     RECT  43.92 56.629 46.488 57.875 ;
     RECT  61.632 57.107 62.232 57.875 ;
     RECT  45.6 57.875 46.488 57.877 ;
     RECT  74.16 57.061 76.152 57.877 ;
     RECT  59.184 57.347 59.208 57.923 ;
     RECT  72.432 57.251 72.912 57.925 ;
     RECT  74.16 57.877 76.488 57.925 ;
     RECT  78 56.389 79.944 57.971 ;
     RECT  81.36 57.781 84.744 57.971 ;
     RECT  85.728 57.155 85.752 57.971 ;
     RECT  86.88 57.541 90.744 57.971 ;
     RECT  21.6 57.299 27.816 58.117 ;
     RECT  54.144 57.827 57.336 58.117 ;
     RECT  72.432 57.925 76.488 58.117 ;
     RECT  78 57.971 79.56 58.117 ;
     RECT  2.304 57.349 20.472 58.163 ;
     RECT  29.136 57.875 30.216 58.163 ;
     RECT  31.2 57.875 31.848 58.163 ;
     RECT  33.024 57.395 33.144 58.163 ;
     RECT  43.92 57.875 44.04 58.259 ;
     RECT  40.08 57.299 41.016 58.357 ;
     RECT  2.4 58.163 20.472 58.501 ;
     RECT  21.6 58.117 27.912 58.501 ;
     RECT  54.144 58.117 57.624 58.547 ;
     RECT  34.8 54.419 35.736 58.597 ;
     RECT  72.432 58.117 79.56 58.643 ;
     RECT  48.48 57.347 51.312 58.645 ;
     RECT  52.704 58.501 52.728 58.645 ;
     RECT  29.136 58.163 29.712 58.691 ;
     RECT  64.128 57.683 65.208 58.691 ;
     RECT  33.12 58.163 33.144 58.693 ;
     RECT  34.8 58.597 36.552 58.739 ;
     RECT  43.92 58.259 43.944 58.787 ;
     RECT  81.36 57.971 83.88 58.789 ;
     RECT  2.4 58.501 27.912 58.931 ;
     RECT  34.8 58.739 35.736 58.931 ;
     RECT  0.144 57.731 0.504 58.979 ;
     RECT  45.6 57.877 46.68 59.029 ;
     RECT  54.144 58.547 56.808 59.075 ;
     RECT  64.128 58.691 64.152 59.173 ;
     RECT  72.432 58.643 73.512 59.219 ;
     RECT  92.88 58.357 92.904 59.219 ;
     RECT  40.08 58.357 41.4 59.221 ;
     RECT  68.928 58.021 68.952 59.221 ;
     RECT  74.544 58.643 79.56 59.221 ;
     RECT  81.12 58.789 83.88 59.221 ;
     RECT  65.184 58.691 65.208 59.267 ;
     RECT  55.68 59.075 56.808 59.315 ;
     RECT  63.408 59.173 64.152 59.315 ;
     RECT  39.312 59.221 41.4 59.459 ;
     RECT  68.688 59.221 68.952 59.459 ;
     RECT  70.128 58.021 70.152 59.459 ;
     RECT  74.544 59.221 83.88 59.507 ;
     RECT  86.88 57.971 89.832 59.507 ;
     RECT  72.432 59.219 73.032 59.509 ;
     RECT  61.632 57.875 62.112 59.603 ;
     RECT  54 59.509 54.024 59.651 ;
     RECT  2.4 58.931 27.816 59.749 ;
     RECT  76.464 59.507 83.88 59.795 ;
     RECT  74.544 59.507 75.288 59.797 ;
     RECT  81.072 59.795 82.2 59.843 ;
     RECT  66.864 55.955 67.512 59.941 ;
     RECT  68.688 59.459 68.712 59.941 ;
     RECT  48.48 58.645 52.728 60.035 ;
     RECT  86.88 59.507 87.72 60.035 ;
     RECT  81.072 59.843 81.144 60.371 ;
     RECT  44.976 59.029 46.68 60.373 ;
     RECT  56.16 59.315 56.808 60.373 ;
     RECT  58.464 59.029 58.488 60.373 ;
     RECT  66.864 59.941 68.712 60.419 ;
     RECT  56.16 60.373 58.488 60.467 ;
     RECT  33.12 58.693 33.288 60.565 ;
     RECT  74.4 59.797 75.288 60.611 ;
     RECT  39.312 59.459 40.512 60.613 ;
     RECT  61.8 59.603 62.112 60.661 ;
     RECT  63.408 59.315 63.432 60.661 ;
     RECT  74.4 60.611 74.664 60.757 ;
     RECT  0.144 58.979 0.456 60.803 ;
     RECT  76.464 59.795 79.848 60.851 ;
     RECT  81.12 60.371 81.144 60.851 ;
     RECT  82.176 59.843 82.2 60.851 ;
     RECT  44.736 60.373 47.352 60.949 ;
     RECT  52.704 60.035 52.728 60.949 ;
     RECT  83.4 59.795 83.88 60.949 ;
     RECT  0.24 60.803 0.456 61.043 ;
     RECT  44.208 60.949 47.352 61.043 ;
     RECT  61.8 60.661 63.432 61.043 ;
     RECT  91.104 60.421 91.128 61.045 ;
     RECT  74.208 60.757 74.664 61.091 ;
     RECT  0.24 61.043 0.264 61.139 ;
     RECT  71.808 59.509 73.032 61.139 ;
     RECT  74.208 61.091 74.424 61.139 ;
     RECT  39.312 60.613 41.016 61.141 ;
     RECT  71.952 61.139 73.032 61.187 ;
     RECT  56.16 60.467 57.528 61.235 ;
     RECT  90.864 61.045 91.128 61.235 ;
     RECT  69.888 59.797 69.912 61.237 ;
     RECT  87.696 60.035 87.72 61.381 ;
     RECT  88.8 59.507 89.832 61.381 ;
     RECT  29.4 58.691 29.712 61.429 ;
     RECT  36.48 60.373 36.504 61.525 ;
     RECT  36.48 61.525 37.08 61.571 ;
     RECT  39.312 61.141 41.064 61.571 ;
     RECT  31.2 58.163 31.224 61.621 ;
     RECT  2.304 59.749 27.816 61.717 ;
     RECT  56.16 61.235 56.808 61.763 ;
     RECT  29.28 61.429 29.712 61.765 ;
     RECT  44.208 61.043 46.488 61.859 ;
     RECT  33.12 60.565 33.768 61.861 ;
     RECT  52.704 60.949 52.968 61.907 ;
     RECT  91.104 61.235 91.128 61.907 ;
     RECT  69.36 61.237 69.912 61.909 ;
     RECT  76.464 60.851 79.56 62.053 ;
     RECT  82.608 60.949 83.88 62.053 ;
     RECT  85.2 58.117 85.224 62.053 ;
     RECT  34.8 58.931 35.256 62.101 ;
     RECT  66.864 60.419 68.232 62.101 ;
     RECT  64.944 61.765 64.968 62.149 ;
     RECT  66.048 62.101 68.232 62.149 ;
     RECT  37.056 61.571 37.08 62.195 ;
     RECT  42.768 60.757 42.792 62.195 ;
     RECT  61.8 61.043 62.904 62.195 ;
     RECT  82.608 62.053 85.224 62.195 ;
     RECT  58.56 61.189 58.584 62.197 ;
     RECT  74.4 61.139 74.424 62.197 ;
     RECT  58.56 62.197 59.496 62.245 ;
     RECT  60.48 57.347 60.504 62.245 ;
     RECT  2.304 61.717 28.296 62.291 ;
     RECT  29.28 61.765 30.168 62.291 ;
     RECT  58.56 62.245 60.504 62.291 ;
     RECT  92.304 61.381 92.328 62.341 ;
     RECT  31.2 61.621 31.56 62.485 ;
     RECT  33.12 61.861 33.816 62.485 ;
     RECT  2.304 62.291 24.552 62.579 ;
     RECT  83.232 62.195 85.224 62.627 ;
     RECT  29.4 62.291 30.168 62.677 ;
     RECT  31.2 62.485 33.816 62.677 ;
     RECT  74.4 62.197 75.048 62.677 ;
     RECT  76.464 62.053 79.656 62.677 ;
     RECT  87.696 61.381 89.832 62.677 ;
     RECT  54.864 60.901 54.888 62.723 ;
     RECT  69.36 61.909 69.96 62.723 ;
     RECT  86.688 62.533 86.712 62.723 ;
     RECT  87.696 62.677 90.456 62.725 ;
     RECT  40.032 61.571 41.064 62.773 ;
     RECT  52.704 61.907 52.728 62.821 ;
     RECT  45.6 61.859 46.488 62.867 ;
     RECT  44.208 61.859 44.232 62.869 ;
     RECT  59.472 62.291 60.504 62.869 ;
     RECT  61.8 62.195 62.472 62.869 ;
     RECT  29.4 62.677 33.816 62.915 ;
     RECT  64.944 62.149 68.232 62.915 ;
     RECT  74.4 62.677 79.656 62.915 ;
     RECT  30.816 62.915 33.816 62.963 ;
     RECT  34.8 62.101 35.544 62.965 ;
     RECT  2.304 62.579 24.504 63.011 ;
     RECT  74.4 62.915 79.56 63.059 ;
     RECT  38.736 61.717 38.76 63.205 ;
     RECT  71.952 61.187 72.912 63.205 ;
     RECT  74.4 63.059 79.416 63.205 ;
     RECT  91.776 62.341 92.328 63.205 ;
     RECT  38.64 63.205 38.76 63.251 ;
     RECT  31.2 62.963 33.816 63.253 ;
     RECT  34.8 62.965 36.024 63.253 ;
     RECT  87.072 62.725 90.456 63.491 ;
     RECT  56.16 61.763 56.712 63.493 ;
     RECT  59.472 62.869 62.472 63.493 ;
     RECT  64.944 62.915 65.4 63.493 ;
     RECT  80.784 62.917 80.808 63.493 ;
     RECT  64.896 63.493 65.4 63.539 ;
     RECT  69.36 62.723 69.384 63.539 ;
     RECT  91.536 63.205 92.328 63.539 ;
     RECT  64.896 63.539 65.064 63.635 ;
     RECT  87.696 63.491 90.456 63.635 ;
     RECT  71.952 63.205 79.416 63.781 ;
     RECT  71.904 63.781 79.416 63.827 ;
     RECT  45.6 62.867 46.296 63.829 ;
     RECT  47.424 63.061 47.448 63.829 ;
     RECT  48.48 60.035 51.312 63.829 ;
     RECT  39.984 62.773 41.064 63.875 ;
     RECT  52.416 62.821 52.728 63.875 ;
     RECT  58.704 63.493 62.472 63.875 ;
     RECT  80.784 63.493 80.904 63.875 ;
     RECT  71.904 63.827 78.312 63.925 ;
     RECT  2.304 63.011 24.408 64.019 ;
     RECT  18.48 64.019 24.408 64.115 ;
     RECT  18.48 64.115 21.336 64.211 ;
     RECT  25.68 62.291 28.296 64.213 ;
     RECT  90.432 63.635 90.456 64.307 ;
     RECT  22.608 64.115 24.408 64.309 ;
     RECT  38.64 63.251 38.664 64.309 ;
     RECT  64.896 63.635 64.968 64.357 ;
     RECT  66.864 62.915 68.232 64.357 ;
     RECT  31.2 63.253 36.024 64.403 ;
     RECT  43.728 62.869 44.232 64.403 ;
     RECT  61.584 63.875 62.472 64.403 ;
     RECT  71.472 63.925 78.312 64.499 ;
     RECT  31.2 64.403 31.272 64.595 ;
     RECT  87.696 63.635 89.352 64.595 ;
     RECT  44.208 64.403 44.232 64.643 ;
     RECT  52.704 63.875 52.728 64.645 ;
     RECT  52.704 64.645 53.016 64.691 ;
     RECT  71.904 64.499 78.312 64.885 ;
     RECT  45.6 63.829 51.312 64.933 ;
     RECT  70.128 63.877 70.152 64.933 ;
     RECT  91.536 63.539 92.136 64.933 ;
     RECT  38.64 64.309 38.808 64.979 ;
     RECT  71.904 64.885 78.408 64.979 ;
     RECT  25.632 64.213 28.296 64.981 ;
     RECT  29.4 62.915 29.712 64.981 ;
     RECT  74.208 64.979 78.408 64.981 ;
     RECT  79.392 63.827 79.416 64.981 ;
     RECT  69.504 64.933 70.152 65.027 ;
     RECT  58.704 63.875 59.496 65.075 ;
     RECT  25.632 64.981 29.712 65.123 ;
     RECT  58.704 65.075 59.448 65.125 ;
     RECT  74.208 64.981 79.416 65.219 ;
     RECT  18.48 64.211 21.288 65.269 ;
     RECT  22.608 64.309 24.456 65.269 ;
     RECT  83.4 62.627 85.224 65.315 ;
     RECT  32.4 64.403 36.024 65.363 ;
     RECT  56.16 63.493 57.096 65.365 ;
     RECT  80.88 63.875 80.904 65.461 ;
     RECT  82.224 64.693 82.248 65.461 ;
     RECT  55.776 65.365 57.096 65.509 ;
     RECT  74.208 65.219 78.84 65.555 ;
     RECT  87.696 64.595 87.768 65.555 ;
     RECT  18.48 65.269 24.456 65.557 ;
     RECT  25.632 65.123 28.2 65.557 ;
     RECT  29.4 65.123 29.712 65.557 ;
     RECT  31.2 64.595 31.224 65.557 ;
     RECT  64.416 64.357 64.968 65.557 ;
     RECT  69.504 65.027 69.528 65.603 ;
     RECT  74.208 65.555 78.312 65.603 ;
     RECT  18.48 65.557 28.2 65.651 ;
     RECT  33.888 65.363 36.024 65.699 ;
     RECT  2.304 64.019 17.496 65.749 ;
     RECT  18.48 65.651 26.088 65.749 ;
     RECT  61.8 64.403 62.472 65.845 ;
     RECT  32.4 65.363 32.904 65.939 ;
     RECT  85.2 65.315 85.224 65.939 ;
     RECT  71.904 64.979 72.912 66.037 ;
     RECT  74.208 65.603 76.968 66.037 ;
     RECT  2.304 65.749 26.088 66.083 ;
     RECT  0.192 65.941 0.216 66.085 ;
     RECT  71.904 66.037 76.968 66.179 ;
     RECT  45.6 64.933 51.72 66.227 ;
     RECT  66.672 64.357 68.232 66.227 ;
     RECT  91.536 64.933 93.048 66.227 ;
     RECT  0.144 66.085 0.216 66.275 ;
     RECT  74.208 66.179 76.968 66.275 ;
     RECT  27.072 65.651 28.2 66.277 ;
     RECT  29.4 65.557 31.224 66.277 ;
     RECT  45.6 66.227 48.84 66.323 ;
     RECT  88.8 64.595 89.352 66.325 ;
     RECT  58.656 65.125 59.448 66.467 ;
     RECT  63.792 65.557 64.968 66.467 ;
     RECT  58.704 66.467 59.448 66.661 ;
     RECT  60.48 63.875 60.504 66.661 ;
     RECT  64.272 66.467 64.968 66.661 ;
     RECT  91.536 66.227 91.8 66.661 ;
     RECT  93.024 66.227 93.048 66.707 ;
     RECT  55.776 65.509 57.48 66.709 ;
     RECT  70.272 66.661 70.296 66.709 ;
     RECT  32.592 65.939 32.904 66.755 ;
     RECT  39.984 63.875 40.512 66.755 ;
     RECT  48.72 66.323 48.84 66.755 ;
     RECT  50.16 66.227 51.72 66.755 ;
     RECT  58.704 66.661 60.504 66.755 ;
     RECT  91.152 66.661 91.8 66.757 ;
     RECT  43.92 66.661 43.944 66.803 ;
     RECT  50.16 66.755 51.312 66.899 ;
     RECT  66.864 66.227 68.232 66.899 ;
     RECT  74.208 66.275 74.424 66.899 ;
     RECT  61.8 65.845 62.568 66.949 ;
     RECT  55.776 66.709 57.624 67.093 ;
     RECT  33.888 65.699 35.112 67.139 ;
     RECT  45.6 66.323 47.64 67.139 ;
     RECT  0.192 66.275 0.216 67.141 ;
     RECT  42.288 63.637 42.312 67.237 ;
     RECT  48.72 66.755 48.744 67.283 ;
     RECT  71.904 66.179 72.912 67.283 ;
     RECT  60.384 66.755 60.504 67.285 ;
     RECT  61.8 66.949 63 67.285 ;
     RECT  27.072 66.277 31.224 67.331 ;
     RECT  41.568 67.237 42.312 67.331 ;
     RECT  55.248 67.093 57.624 67.331 ;
     RECT  60.384 67.285 63 67.331 ;
     RECT  69.984 66.709 70.296 67.331 ;
     RECT  74.208 66.899 74.232 67.427 ;
     RECT  0.192 67.141 0.264 67.429 ;
     RECT  47.616 67.139 47.64 67.475 ;
     RECT  50.208 66.899 51.312 67.523 ;
     RECT  60.48 67.331 63 67.523 ;
     RECT  40.08 66.755 40.512 67.763 ;
     RECT  33.984 67.139 35.112 67.859 ;
     RECT  76.176 66.275 76.968 67.861 ;
     RECT  0.144 67.429 0.264 67.907 ;
     RECT  52.992 64.691 53.016 67.909 ;
     RECT  80.88 65.461 82.248 67.909 ;
     RECT  55.248 67.331 57.48 67.955 ;
     RECT  66.864 66.899 67.944 68.099 ;
     RECT  79.296 66.709 79.32 68.099 ;
     RECT  90.48 66.757 91.8 68.099 ;
     RECT  27.072 67.331 29.712 68.147 ;
     RECT  50.4 67.523 51.312 68.197 ;
     RECT  87.696 65.555 87.72 68.293 ;
     RECT  88.704 66.325 89.352 68.293 ;
     RECT  50.4 68.197 51.432 68.339 ;
     RECT  0.24 67.907 0.264 68.435 ;
     RECT  2.304 66.083 25.848 68.435 ;
     RECT  72.384 67.283 72.912 68.437 ;
     RECT  64.272 66.661 65.592 68.629 ;
     RECT  72.384 68.437 73.464 68.629 ;
     RECT  60.48 67.523 62.28 68.677 ;
     RECT  41.568 67.331 42.216 68.819 ;
     RECT  71.76 68.629 73.464 68.819 ;
     RECT  87.696 68.293 89.352 68.821 ;
     RECT  42.192 68.819 42.216 68.869 ;
     RECT  52.992 67.909 53.496 68.869 ;
     RECT  76.08 67.861 76.968 68.915 ;
     RECT  31.2 67.331 31.224 68.917 ;
     RECT  50.4 68.339 51.312 68.917 ;
     RECT  80.64 67.909 82.248 68.917 ;
     RECT  91.152 68.099 91.8 68.917 ;
     RECT  64.272 68.629 65.784 68.963 ;
     RECT  27.072 68.147 28.2 69.155 ;
     RECT  44.304 67.765 44.328 69.203 ;
     RECT  60.48 68.677 63.24 69.203 ;
     RECT  86.736 68.821 89.352 69.203 ;
     RECT  55.776 67.955 57.48 69.205 ;
     RECT  31.2 68.917 31.32 69.253 ;
     RECT  71.76 68.819 73.416 69.349 ;
     RECT  79.92 68.917 82.248 69.395 ;
     RECT  29.4 68.147 29.712 69.445 ;
     RECT  60.48 69.203 62.28 69.493 ;
     RECT  27.36 69.155 28.2 69.541 ;
     RECT  29.232 69.445 29.712 69.541 ;
     RECT  91.152 68.917 92.376 69.587 ;
     RECT  69.984 67.331 70.152 69.637 ;
     RECT  42.192 68.869 42.552 69.683 ;
     RECT  60.096 69.493 62.28 69.731 ;
     RECT  81.792 69.395 82.248 69.733 ;
     RECT  83.4 65.315 83.88 69.733 ;
     RECT  74.544 69.109 74.568 69.781 ;
     RECT  60.096 69.731 62.232 69.875 ;
     RECT  71.28 69.349 73.416 69.877 ;
     RECT  74.544 69.781 74.616 69.877 ;
     RECT  52.992 68.869 53.64 69.971 ;
     RECT  31.2 69.253 31.368 70.021 ;
     RECT  69.984 69.637 70.248 70.021 ;
     RECT  50.256 68.917 51.312 70.067 ;
     RECT  38.64 64.979 38.664 70.069 ;
     RECT  32.88 66.755 32.904 70.117 ;
     RECT  34.128 67.859 35.112 70.117 ;
     RECT  55.776 69.205 57.624 70.163 ;
     RECT  71.28 69.877 74.616 70.259 ;
     RECT  87.696 69.203 89.352 70.261 ;
     RECT  38.544 70.069 38.664 70.307 ;
     RECT  60.48 69.875 62.232 70.307 ;
     RECT  42.192 69.683 42.216 70.355 ;
     RECT  52.992 69.971 53.496 70.357 ;
     RECT  27.36 69.541 29.712 70.403 ;
     RECT  32.88 70.117 35.112 70.403 ;
     RECT  50.688 70.067 51.312 70.403 ;
     RECT  81.792 69.733 83.88 70.451 ;
     RECT  2.304 68.435 25.8 70.499 ;
     RECT  28.176 70.403 29.712 70.547 ;
     RECT  69.504 70.021 70.248 70.549 ;
     RECT  71.28 70.259 71.304 70.549 ;
     RECT  58.704 66.755 58.728 70.597 ;
     RECT  64.8 68.963 65.784 70.597 ;
     RECT  28.8 70.547 29.712 70.643 ;
     RECT  87.312 70.261 89.352 70.691 ;
     RECT  31.2 70.021 31.896 70.739 ;
     RECT  50.736 70.403 51.312 70.739 ;
     RECT  66.864 68.099 67.704 70.739 ;
     RECT  38.544 70.307 38.568 70.787 ;
     RECT  84.96 69.877 84.984 70.787 ;
     RECT  91.536 69.587 92.376 70.787 ;
     RECT  2.304 70.499 16.2 70.835 ;
     RECT  69.504 70.549 71.304 70.835 ;
     RECT  78 65.603 78.312 70.837 ;
     RECT  76.176 68.915 76.968 70.883 ;
     RECT  79.92 69.395 80.664 70.933 ;
     RECT  81.792 70.451 82.248 70.933 ;
     RECT  37.296 68.101 37.32 71.221 ;
     RECT  37.056 71.221 37.32 71.267 ;
     RECT  43.92 69.685 43.944 71.269 ;
     RECT  64.608 70.597 65.784 71.315 ;
     RECT  76.32 70.883 76.968 71.363 ;
     RECT  58.704 70.597 59.256 71.365 ;
     RECT  60.48 70.307 62.112 71.365 ;
     RECT  43.872 71.269 43.944 71.413 ;
     RECT  34.8 70.403 35.112 71.461 ;
     RECT  78 70.837 78.504 71.461 ;
     RECT  58.704 71.365 62.112 71.507 ;
     RECT  92.352 70.787 92.376 71.507 ;
     RECT  48.816 71.461 48.84 71.509 ;
     RECT  64.992 71.315 65.784 71.555 ;
     RECT  52.608 70.357 53.496 71.557 ;
     RECT  17.616 70.499 25.8 71.605 ;
     RECT  43.296 71.413 43.944 71.651 ;
     RECT  69.504 70.835 70.536 71.651 ;
     RECT  48.816 71.509 48.984 71.699 ;
     RECT  72.384 70.259 74.616 71.795 ;
     RECT  58.704 71.507 59.496 71.843 ;
     RECT  74.544 71.795 74.616 71.843 ;
     RECT  43.872 71.651 43.944 71.891 ;
     RECT  65.76 71.555 65.784 71.891 ;
     RECT  90.576 71.845 90.6 71.987 ;
     RECT  2.4 70.835 16.2 71.989 ;
     RECT  79.92 70.933 82.248 71.989 ;
     RECT  76.944 71.363 76.968 72.037 ;
     RECT  78 71.461 78.648 72.037 ;
     RECT  28.848 70.643 29.712 72.083 ;
     RECT  72.384 71.795 73.032 72.085 ;
     RECT  59.232 71.843 59.496 72.131 ;
     RECT  17.616 71.605 26.04 72.133 ;
     RECT  66.864 70.739 67.512 72.229 ;
     RECT  17.616 72.133 26.28 72.277 ;
     RECT  29.4 72.083 29.712 72.325 ;
     RECT  52.464 71.557 53.496 72.325 ;
     RECT  69.984 71.651 70.536 72.325 ;
     RECT  31.2 70.739 31.224 72.373 ;
     RECT  37.056 71.267 37.08 72.419 ;
     RECT  60.528 71.507 62.112 72.419 ;
     RECT  87.312 70.691 87.72 72.419 ;
     RECT  34.8 71.461 35.208 72.467 ;
     RECT  87.696 72.419 87.72 72.467 ;
     RECT  88.704 70.691 89.352 72.467 ;
     RECT  55.776 70.163 56.712 72.709 ;
     RECT  60.96 72.419 62.112 72.851 ;
     RECT  2.304 71.989 16.2 72.901 ;
     RECT  69.984 72.325 71.304 72.947 ;
     RECT  79.824 71.989 82.248 72.947 ;
     RECT  59.472 72.131 59.496 72.949 ;
     RECT  74.592 71.843 74.616 72.949 ;
     RECT  2.304 72.901 16.296 72.997 ;
     RECT  17.28 72.277 26.28 72.997 ;
     RECT  76.944 72.037 78.648 72.997 ;
     RECT  79.824 72.947 81.816 72.997 ;
     RECT  55.776 72.709 56.808 73.045 ;
     RECT  83.28 70.451 83.88 73.045 ;
     RECT  45.6 67.139 46.44 73.091 ;
     RECT  76.944 72.997 81.816 73.091 ;
     RECT  29.4 72.325 29.832 73.093 ;
     RECT  83.232 73.045 83.88 73.093 ;
     RECT  42.192 72.325 42.216 73.139 ;
     RECT  28.128 72.853 28.152 73.237 ;
     RECT  29.28 73.093 29.832 73.237 ;
     RECT  48.96 71.699 48.984 73.237 ;
     RECT  69.984 72.947 70.536 73.237 ;
     RECT  40.2 67.763 40.512 73.285 ;
     RECT  77.52 73.091 81.816 73.331 ;
     RECT  66.864 72.229 67.848 73.333 ;
     RECT  69.936 73.237 70.536 73.379 ;
     RECT  48.96 73.237 49.416 73.381 ;
     RECT  63.6 72.037 63.624 73.381 ;
     RECT  75.6 72.085 75.624 73.381 ;
     RECT  40.2 73.285 40.632 73.427 ;
     RECT  66.864 73.333 68.808 73.475 ;
     RECT  0.528 73.285 0.552 73.477 ;
     RECT  48.96 73.381 49.464 73.523 ;
     RECT  52.464 72.325 53.592 73.523 ;
     RECT  74.064 72.949 74.616 73.523 ;
     RECT  52.464 73.523 53.496 73.571 ;
     RECT  72.336 72.085 73.032 73.571 ;
     RECT  32.88 70.403 33.48 73.717 ;
     RECT  28.128 73.237 29.832 73.765 ;
     RECT  40.2 73.427 40.512 73.765 ;
     RECT  27.936 73.765 29.832 74.051 ;
     RECT  48.96 73.523 49.416 74.051 ;
     RECT  72.6 73.571 73.032 74.053 ;
     RECT  88.8 72.467 89.352 74.053 ;
     RECT  28.56 74.051 29.832 74.099 ;
     RECT  37.152 72.565 37.176 74.099 ;
     RECT  34.8 72.467 35.112 74.101 ;
     RECT  45.6 73.091 46.2 74.101 ;
     RECT  31.2 72.373 31.608 74.147 ;
     RECT  66.864 73.475 67.848 74.147 ;
     RECT  75.6 73.381 76.344 74.147 ;
     RECT  63.6 73.381 64.056 74.291 ;
     RECT  57.984 72.085 58.008 74.339 ;
     RECT  34.8 74.101 35.88 74.341 ;
     RECT  63.6 74.291 63.624 74.387 ;
     RECT  2.304 72.997 26.28 74.483 ;
     RECT  39.312 73.765 40.512 74.485 ;
     RECT  49.392 74.051 49.416 74.485 ;
     RECT  50.832 70.739 51.312 74.485 ;
     RECT  69.984 73.379 70.536 74.485 ;
     RECT  71.568 74.005 71.592 74.485 ;
     RECT  38.448 74.485 40.512 74.531 ;
     RECT  53.04 73.571 53.496 74.581 ;
     RECT  91.632 71.989 91.656 74.581 ;
     RECT  45.36 74.101 46.2 74.627 ;
     RECT  69.984 74.485 71.592 74.627 ;
     RECT  59.472 72.949 59.88 74.723 ;
     RECT  74.592 73.523 74.616 74.723 ;
     RECT  79.824 73.331 81.816 74.723 ;
     RECT  83.232 73.093 83.928 74.723 ;
     RECT  24 74.483 26.28 74.771 ;
     RECT  34.8 74.341 36.648 74.771 ;
     RECT  49.392 74.485 51.312 74.771 ;
     RECT  61.344 72.851 62.112 74.821 ;
     RECT  71.568 74.627 71.592 74.867 ;
     RECT  77.52 73.331 78.648 74.869 ;
     RECT  76.32 74.147 76.344 74.917 ;
     RECT  77.52 74.869 78.888 74.917 ;
     RECT  43.92 71.891 43.944 75.013 ;
     RECT  88.368 74.053 89.352 75.013 ;
     RECT  0.144 73.477 0.552 75.155 ;
     RECT  58.128 74.917 58.152 75.203 ;
     RECT  34.8 74.771 35.112 75.205 ;
     RECT  36.624 74.771 36.648 75.301 ;
     RECT  32.832 73.717 33.48 75.397 ;
     RECT  31.2 74.147 31.56 75.493 ;
     RECT  32.784 75.397 33.48 75.493 ;
     RECT  31.2 75.493 33.48 75.539 ;
     RECT  59.472 74.723 59.496 75.539 ;
     RECT  2.304 74.483 22.824 75.685 ;
     RECT  24 74.771 25.464 75.685 ;
     RECT  53.04 74.581 53.88 75.731 ;
     RECT  55.776 73.045 56.856 75.733 ;
     RECT  72.6 74.053 73.512 75.733 ;
     RECT  83.28 74.723 83.928 75.779 ;
     RECT  69.984 74.627 70.152 75.781 ;
     RECT  76.32 74.917 78.888 75.781 ;
     RECT  79.92 74.723 81.816 75.781 ;
     RECT  36.624 75.301 37.08 75.827 ;
     RECT  28.56 74.099 29.712 75.829 ;
     RECT  38.448 74.531 38.472 75.829 ;
     RECT  50.016 74.771 51.312 75.875 ;
     RECT  91.632 74.581 91.704 75.875 ;
     RECT  88.368 75.013 89.448 75.877 ;
     RECT  60.96 74.821 62.112 75.923 ;
     RECT  76.32 75.781 81.816 75.923 ;
     RECT  31.2 75.539 31.224 76.019 ;
     RECT  43.68 75.013 43.944 76.019 ;
     RECT  88.368 75.877 90.216 76.067 ;
     RECT  28.416 75.829 29.712 76.069 ;
     RECT  34.704 75.205 35.112 76.115 ;
     RECT  28.416 76.069 29.976 76.165 ;
     RECT  45.6 74.627 46.2 76.165 ;
     RECT  86.352 75.781 86.376 76.211 ;
     RECT  76.32 75.923 80.664 76.259 ;
     RECT  55.776 75.733 57.336 76.309 ;
     RECT  68.928 73.477 68.952 76.355 ;
     RECT  0.144 75.155 0.264 76.357 ;
     RECT  69.936 75.781 70.152 76.403 ;
     RECT  27.696 76.165 29.976 76.499 ;
     RECT  41.616 75.589 41.64 76.499 ;
     RECT  71.76 75.733 73.512 76.499 ;
     RECT  65.28 75.877 65.304 76.549 ;
     RECT  0.144 76.357 0.36 76.595 ;
     RECT  64.848 76.549 65.304 76.691 ;
     RECT  72.096 76.499 73.512 76.691 ;
     RECT  50.88 75.875 51.312 76.883 ;
     RECT  40.2 74.531 40.512 76.885 ;
     RECT  55.776 76.309 57.72 76.885 ;
     RECT  61.68 75.923 62.112 76.885 ;
     RECT  74.88 76.645 74.904 76.885 ;
     RECT  76.32 76.259 76.344 76.885 ;
     RECT  74.88 76.885 76.344 76.931 ;
     RECT  66.864 74.147 67.512 76.933 ;
     RECT  29.088 76.499 29.976 76.979 ;
     RECT  64.992 76.691 65.304 76.979 ;
     RECT  36.624 75.827 36.648 77.029 ;
     RECT  61.68 76.885 63.096 77.029 ;
     RECT  2.304 75.685 25.464 77.077 ;
     RECT  66.864 76.933 68.04 77.123 ;
     RECT  32.496 75.539 33.48 77.173 ;
     RECT  38.448 75.829 38.808 77.173 ;
     RECT  36.624 77.029 37.08 77.219 ;
     RECT  61.008 77.029 63.096 77.363 ;
     RECT  2.304 77.077 25.656 77.461 ;
     RECT  55.2 76.885 57.72 77.555 ;
     RECT  0.192 76.595 0.36 77.603 ;
     RECT  55.344 77.555 57.72 77.603 ;
     RECT  64.992 76.979 65.016 77.651 ;
     RECT  38.112 77.173 38.808 77.653 ;
     RECT  53.136 75.731 53.88 77.653 ;
     RECT  55.344 77.603 57.336 77.699 ;
     RECT  68.496 77.605 68.52 77.891 ;
     RECT  53.136 77.653 53.976 77.989 ;
     RECT  72.096 76.691 73.32 78.037 ;
     RECT  83.28 75.779 83.88 78.037 ;
     RECT  43.92 76.019 43.944 78.085 ;
     RECT  69.936 76.403 70.008 78.131 ;
     RECT  66.864 77.123 67.512 78.275 ;
     RECT  75.84 76.931 76.344 78.371 ;
     RECT  0.24 77.603 0.36 78.421 ;
     RECT  38.112 77.653 39.048 78.469 ;
     RECT  40.2 76.885 40.632 78.469 ;
     RECT  53.136 77.989 54.072 78.469 ;
     RECT  59.232 76.981 59.256 78.469 ;
     RECT  38.112 78.469 40.632 78.611 ;
     RECT  0.24 78.421 0.552 78.613 ;
     RECT  36.624 77.219 36.648 78.613 ;
     RECT  40.2 78.611 40.632 78.613 ;
     RECT  51 76.883 51.312 78.613 ;
     RECT  53.136 78.469 54.36 78.613 ;
     RECT  61.8 77.363 63.096 78.613 ;
     RECT  76.32 78.371 76.344 78.613 ;
     RECT  55.344 77.699 56.808 78.659 ;
     RECT  88.368 76.067 89.352 78.659 ;
     RECT  32.4 77.173 33.48 78.661 ;
     RECT  34.8 76.115 35.112 78.661 ;
     RECT  0.192 78.613 0.552 78.707 ;
     RECT  43.92 78.085 44.568 78.707 ;
     RECT  72.096 78.037 74.328 78.709 ;
     RECT  78 76.259 80.664 78.853 ;
     RECT  0.192 78.707 0.36 78.901 ;
     RECT  76.32 78.613 76.776 79.187 ;
     RECT  29.088 76.979 29.712 79.189 ;
     RECT  83.232 78.037 83.88 79.235 ;
     RECT  59.184 78.469 59.256 79.283 ;
     RECT  60.96 78.613 63.096 79.283 ;
     RECT  29.088 79.189 29.832 79.285 ;
     RECT  30.816 77.029 30.84 79.285 ;
     RECT  32.4 78.661 35.112 79.331 ;
     RECT  61.8 79.283 63.096 79.427 ;
     RECT  34.8 79.331 35.112 79.429 ;
     RECT  36.624 78.613 36.696 79.429 ;
     RECT  38.112 78.611 39.048 79.475 ;
     RECT  45.6 76.165 46.728 79.475 ;
     RECT  76.752 79.187 76.776 79.477 ;
     RECT  77.904 78.853 80.664 79.477 ;
     RECT  34.8 79.429 36.696 79.571 ;
     RECT  72.096 78.709 75.24 79.571 ;
     RECT  32.4 79.331 33.48 79.621 ;
     RECT  66.144 78.853 66.168 79.621 ;
     RECT  67.2 78.275 67.512 79.621 ;
     RECT  0.144 78.901 0.36 79.667 ;
     RECT  76.752 79.477 80.664 79.667 ;
     RECT  69.936 78.131 69.96 79.669 ;
     RECT  52.416 78.613 54.36 79.715 ;
     RECT  72.096 79.571 74.76 79.715 ;
     RECT  0.192 79.667 0.36 79.717 ;
     RECT  27.696 76.499 27.96 79.717 ;
     RECT  50.112 78.613 51.312 79.717 ;
     RECT  52.416 79.715 54.072 79.717 ;
     RECT  64.176 78.037 64.2 79.717 ;
     RECT  83.28 79.235 83.88 79.717 ;
     RECT  85.248 76.837 85.272 79.717 ;
     RECT  40.2 78.613 41.4 79.765 ;
     RECT  42.768 79.141 42.792 79.765 ;
     RECT  43.92 78.707 43.944 79.765 ;
     RECT  26.976 79.717 27.96 79.859 ;
     RECT  36.624 79.571 36.696 79.859 ;
     RECT  38.112 79.475 38.472 79.859 ;
     RECT  2.304 77.461 25.848 80.003 ;
     RECT  20.928 80.003 25.848 80.051 ;
     RECT  78 79.667 80.664 80.101 ;
     RECT  81.792 75.923 81.816 80.101 ;
     RECT  42.768 79.765 43.944 80.149 ;
     RECT  45.6 79.475 46.392 80.149 ;
     RECT  2.304 80.003 19.704 80.291 ;
     RECT  76.752 79.667 76.872 80.291 ;
     RECT  25.824 80.051 25.848 80.341 ;
     RECT  26.976 79.859 27.816 80.341 ;
     RECT  61.8 79.427 62.112 80.341 ;
     RECT  66.144 79.621 67.512 80.341 ;
     RECT  32.064 79.621 33.48 80.387 ;
     RECT  50.112 79.717 54.072 80.387 ;
     RECT  72.48 79.715 74.76 80.387 ;
     RECT  76.848 80.291 76.872 80.387 ;
     RECT  42.768 80.149 46.392 80.435 ;
     RECT  50.112 80.387 53.064 80.483 ;
     RECT  39.552 79.765 41.4 80.579 ;
     RECT  32.4 80.387 33.48 80.675 ;
     RECT  25.824 80.341 27.816 80.819 ;
     RECT  69.936 79.669 70.248 80.821 ;
     RECT  65.376 80.341 67.512 80.867 ;
     RECT  39.552 80.579 40.512 80.869 ;
     RECT  64.176 79.717 64.392 80.869 ;
     RECT  50.688 80.483 53.064 80.915 ;
     RECT  55.344 78.659 56.712 80.917 ;
     RECT  61.008 80.341 62.112 80.963 ;
     RECT  2.304 80.291 15.768 81.011 ;
     RECT  65.376 80.867 65.4 81.011 ;
     RECT  38.112 79.859 38.184 81.013 ;
     RECT  37.968 81.013 38.184 81.059 ;
     RECT  43.728 80.435 46.392 81.061 ;
     RECT  66.624 80.867 67.512 81.061 ;
     RECT  0.192 79.717 0.408 81.107 ;
     RECT  9.792 81.011 15.768 81.107 ;
     RECT  69.168 80.821 70.248 81.107 ;
     RECT  69.168 81.107 69.192 81.203 ;
     RECT  36.624 79.859 36.648 81.253 ;
     RECT  37.968 81.059 37.992 81.253 ;
     RECT  39.504 80.869 40.512 81.253 ;
     RECT  78 80.101 81.816 81.253 ;
     RECT  77.52 81.253 81.816 81.301 ;
     RECT  83.28 79.717 85.272 81.301 ;
     RECT  26.304 80.819 27.816 81.349 ;
     RECT  77.52 81.301 85.272 81.349 ;
     RECT  36.624 81.253 37.992 81.395 ;
     RECT  54.048 80.387 54.072 81.395 ;
     RECT  76.896 81.349 85.272 81.395 ;
     RECT  91.632 75.875 91.656 81.397 ;
     RECT  20.928 80.051 24.6 81.445 ;
     RECT  29.088 79.285 30.84 81.445 ;
     RECT  32.4 80.675 33.24 81.445 ;
     RECT  55.344 80.917 57.336 81.445 ;
     RECT  88.512 78.659 89.352 81.445 ;
     RECT  20.928 81.445 25.128 81.491 ;
     RECT  29.088 81.445 33.24 81.491 ;
     RECT  20.928 81.491 22.392 81.539 ;
     RECT  26.304 81.349 27.912 81.539 ;
     RECT  76.896 81.395 76.92 81.539 ;
     RECT  86.256 80.869 86.28 81.539 ;
     RECT  66.624 81.061 67.8 81.541 ;
     RECT  64.032 80.869 64.392 81.587 ;
     RECT  43.728 81.061 46.776 81.635 ;
     RECT  48 79.189 48.024 81.635 ;
     RECT  55.344 81.445 58.152 81.635 ;
     RECT  23.472 81.491 25.128 81.683 ;
     RECT  16.8 80.291 19.512 81.685 ;
     RECT  43.92 81.635 46.776 81.685 ;
     RECT  59.184 79.283 59.208 81.779 ;
     RECT  16.608 81.685 19.512 81.781 ;
     RECT  20.928 81.539 22.2 81.781 ;
     RECT  49.104 81.205 49.128 81.781 ;
     RECT  66.624 81.541 68.904 81.875 ;
     RECT  16.608 81.781 22.2 81.971 ;
     RECT  29.28 81.491 33.24 82.115 ;
     RECT  53.04 80.915 53.064 82.115 ;
     RECT  64.032 81.587 64.056 82.115 ;
     RECT  23.472 81.683 24.888 82.307 ;
     RECT  88.512 81.445 89.976 82.309 ;
     RECT  55.344 81.635 56.904 82.405 ;
     RECT  55.104 82.405 56.904 82.501 ;
     RECT  36.624 82.405 36.648 82.547 ;
     RECT  65.568 81.829 65.592 82.547 ;
     RECT  29.28 82.115 30.264 82.549 ;
     RECT  2.304 81.011 8.808 82.597 ;
     RECT  58.128 81.635 58.152 82.597 ;
     RECT  49.104 81.781 49.368 82.645 ;
     RECT  50.688 80.915 52.056 82.645 ;
     RECT  91.632 81.397 91.752 82.645 ;
     RECT  9.888 81.107 15.384 82.691 ;
     RECT  29.136 82.549 30.264 82.691 ;
     RECT  87.792 82.309 89.976 82.691 ;
     RECT  91.104 82.645 91.752 82.691 ;
     RECT  0.192 81.107 0.264 82.739 ;
     RECT  29.136 82.691 29.832 82.739 ;
     RECT  58.128 82.597 58.632 82.739 ;
     RECT  70.224 81.107 70.248 82.739 ;
     RECT  31.776 82.115 33.24 82.789 ;
     RECT  31.776 82.789 33.816 82.835 ;
     RECT  16.608 81.971 16.824 82.837 ;
     RECT  2.304 82.597 8.904 82.933 ;
     RECT  9.888 82.691 15.048 82.933 ;
     RECT  0.192 82.739 0.216 82.979 ;
     RECT  29.136 82.739 29.712 82.981 ;
     RECT  16.56 82.837 16.824 83.029 ;
     RECT  18.48 81.971 22.2 83.029 ;
     RECT  43.92 81.685 47.928 83.029 ;
     RECT  49.104 82.645 52.056 83.029 ;
     RECT  60.192 82.933 60.216 83.029 ;
     RECT  16.56 83.029 22.2 83.077 ;
     RECT  23.472 82.307 24.552 83.077 ;
     RECT  26.976 81.539 27.912 83.125 ;
     RECT  29.088 82.981 29.712 83.125 ;
     RECT  43.92 83.029 52.056 83.125 ;
     RECT  86.496 82.597 86.52 83.125 ;
     RECT  60.192 83.029 60.6 83.171 ;
     RECT  39.408 81.253 40.512 83.173 ;
     RECT  42.672 80.533 42.696 83.173 ;
     RECT  43.92 83.125 52.152 83.173 ;
     RECT  53.136 82.309 53.16 83.173 ;
     RECT  60.192 83.171 60.216 83.173 ;
     RECT  16.56 83.077 24.552 83.219 ;
     RECT  91.104 82.691 91.656 83.219 ;
     RECT  72.6 80.387 74.76 83.221 ;
     RECT  2.304 82.933 15.048 83.267 ;
     RECT  26.976 83.125 29.712 83.267 ;
     RECT  37.632 81.395 37.992 83.267 ;
     RECT  67.2 81.875 68.904 83.267 ;
     RECT  72.6 83.221 75.24 83.267 ;
     RECT  78 81.395 85.272 83.267 ;
     RECT  21.12 83.219 24.552 83.269 ;
     RECT  25.872 82.261 25.896 83.269 ;
     RECT  78 83.267 81.864 83.315 ;
     RECT  79.584 83.315 81.864 83.459 ;
     RECT  64.608 82.885 64.632 83.507 ;
     RECT  79.584 83.459 80.568 83.507 ;
     RECT  36.336 83.269 36.36 83.555 ;
     RECT  88.32 82.691 89.976 83.555 ;
     RECT  21.12 83.269 25.896 83.603 ;
     RECT  86.496 83.125 86.952 83.605 ;
     RECT  2.4 83.267 15.048 83.749 ;
     RECT  16.56 83.219 19.896 83.749 ;
     RECT  21.12 83.603 25.08 83.795 ;
     RECT  88.32 83.555 89.352 83.795 ;
     RECT  21.12 83.795 22.344 83.891 ;
     RECT  83.232 83.267 85.272 83.891 ;
     RECT  27.072 83.267 29.712 83.987 ;
     RECT  91.104 83.219 91.464 84.179 ;
     RECT  43.92 83.173 53.16 84.181 ;
     RECT  54.144 82.501 56.904 84.181 ;
     RECT  29.136 83.987 29.712 84.227 ;
     RECT  67.2 83.267 67.8 84.325 ;
     RECT  72.6 83.267 74.04 84.325 ;
     RECT  75.216 83.267 75.24 84.325 ;
     RECT  2.4 83.749 19.896 84.371 ;
     RECT  37.872 83.267 37.992 84.371 ;
     RECT  43.92 84.181 56.904 84.371 ;
     RECT  27.072 83.987 28.152 84.419 ;
     RECT  39.36 83.173 40.512 84.467 ;
     RECT  67.104 84.325 67.8 84.515 ;
     RECT  72.288 84.325 74.04 84.517 ;
     RECT  75.216 84.325 76.056 84.517 ;
     RECT  43.92 84.371 56.808 84.563 ;
     RECT  81.84 83.459 81.864 84.563 ;
     RECT  86.256 83.605 86.952 84.565 ;
     RECT  39.408 84.467 40.512 84.611 ;
     RECT  80.544 83.507 80.568 84.613 ;
     RECT  23.472 83.795 25.08 84.757 ;
     RECT  80.544 84.613 81.72 84.803 ;
     RECT  32.4 82.835 33.816 84.805 ;
     RECT  78 83.315 78.552 84.853 ;
     RECT  86.256 84.565 87.384 84.899 ;
     RECT  78 84.853 78.6 84.901 ;
     RECT  23.472 84.757 25.272 84.947 ;
     RECT  86.256 84.899 86.952 84.947 ;
     RECT  2.4 84.371 19.848 84.995 ;
     RECT  67.104 84.515 67.512 84.995 ;
     RECT  17.136 84.995 19.848 85.091 ;
     RECT  37.872 84.371 37.896 85.091 ;
     RECT  17.52 85.091 19.848 85.139 ;
     RECT  58.464 82.739 58.632 85.139 ;
     RECT  42.672 83.173 42.792 85.141 ;
     RECT  43.92 84.563 43.944 85.141 ;
     RECT  28.128 84.419 28.152 85.187 ;
     RECT  45.264 84.563 56.808 85.187 ;
     RECT  77.328 84.901 78.6 85.187 ;
     RECT  72.288 84.517 76.056 85.331 ;
     RECT  45.504 85.187 56.808 85.333 ;
     RECT  39.792 84.611 40.512 85.381 ;
     RECT  72.288 85.331 74.04 85.427 ;
     RECT  27.072 84.419 27.096 85.429 ;
     RECT  80.544 84.803 80.568 85.429 ;
     RECT  26.016 84.949 26.04 85.475 ;
     RECT  32.256 84.805 33.816 85.475 ;
     RECT  2.4 84.995 16.008 85.477 ;
     RECT  88.608 83.795 89.352 85.477 ;
     RECT  36.432 83.605 36.456 85.571 ;
     RECT  72.288 85.427 73.8 85.571 ;
     RECT  83.4 83.891 85.272 85.715 ;
     RECT  42.672 85.141 43.944 85.717 ;
     RECT  32.256 85.475 33.72 85.763 ;
     RECT  77.328 85.187 78.312 85.859 ;
     RECT  68.592 84.901 68.616 85.955 ;
     RECT  70.128 84.325 70.152 85.955 ;
     RECT  45.504 85.333 57.432 85.957 ;
     RECT  58.464 85.139 58.488 85.957 ;
     RECT  86.928 84.947 86.952 85.957 ;
     RECT  88.608 85.477 90.264 85.957 ;
     RECT  59.808 83.173 60.216 86.005 ;
     RECT  61.8 80.963 62.112 86.005 ;
     RECT  59.808 86.005 62.112 86.051 ;
     RECT  86.928 85.957 90.264 86.053 ;
     RECT  21.648 83.891 22.344 86.099 ;
     RECT  84.768 85.715 85.272 86.099 ;
     RECT  45.504 85.957 58.488 86.149 ;
     RECT  83.4 85.715 83.712 86.197 ;
     RECT  42.528 85.717 43.944 86.245 ;
     RECT  44.928 86.149 58.488 86.245 ;
     RECT  2.304 85.477 16.008 86.341 ;
     RECT  17.52 85.139 19.704 86.341 ;
     RECT  23.472 84.947 24.6 86.341 ;
     RECT  77.52 85.859 78.312 86.341 ;
     RECT  72.288 85.571 73.464 86.435 ;
     RECT  29.28 84.227 29.712 86.485 ;
     RECT  39.792 85.381 40.68 86.581 ;
     RECT  42.528 86.245 58.488 86.581 ;
     RECT  60.192 86.051 62.112 86.581 ;
     RECT  67.2 84.995 67.512 86.581 ;
     RECT  29.232 86.485 29.712 86.627 ;
     RECT  27.072 85.429 27.336 86.675 ;
     RECT  32.256 85.763 32.616 86.675 ;
     RECT  77.52 86.341 78.6 86.723 ;
     RECT  23.472 86.341 24.648 86.771 ;
     RECT  91.44 84.179 91.464 86.771 ;
     RECT  72.6 86.435 73.464 86.917 ;
     RECT  27.072 86.675 27.096 86.965 ;
     RECT  78 86.723 78.6 86.965 ;
     RECT  26.784 86.965 27.096 87.011 ;
     RECT  24 86.771 24.648 87.013 ;
     RECT  2.304 86.341 19.704 87.059 ;
     RECT  24 87.013 24.744 87.155 ;
     RECT  38.736 85.717 38.76 87.157 ;
     RECT  39.792 86.581 58.488 87.157 ;
     RECT  69.552 86.629 69.576 87.203 ;
     RECT  2.304 87.059 9.672 87.299 ;
     RECT  75.216 85.331 76.056 87.299 ;
     RECT  22.32 86.099 22.344 87.301 ;
     RECT  64.56 85.813 64.584 87.301 ;
     RECT  79.824 85.429 80.568 87.301 ;
     RECT  79.728 87.301 80.568 87.493 ;
     RECT  81.696 84.803 81.72 87.493 ;
     RECT  64.56 87.301 65.496 87.587 ;
     RECT  22.32 87.301 22.968 87.589 ;
     RECT  83.232 86.197 83.712 87.635 ;
     RECT  64.896 87.587 65.496 87.685 ;
     RECT  72.6 86.917 73.944 87.731 ;
     RECT  30.864 86.581 30.888 87.779 ;
     RECT  60.192 86.581 62.52 87.781 ;
     RECT  10.8 87.059 19.704 87.827 ;
     RECT  24 87.155 24.648 87.827 ;
     RECT  38.736 87.157 58.488 87.827 ;
     RECT  60.096 87.781 62.52 87.827 ;
     RECT  86.544 86.053 90.264 87.827 ;
     RECT  0.144 86.581 0.168 87.875 ;
     RECT  39.792 87.827 58.488 87.875 ;
     RECT  86.544 87.827 86.952 87.875 ;
     RECT  79.728 87.493 81.72 87.877 ;
     RECT  36.096 87.829 36.12 87.971 ;
     RECT  64.896 87.685 65.544 88.067 ;
     RECT  65.472 88.067 65.544 88.115 ;
     RECT  2.4 87.299 9.672 88.165 ;
     RECT  25.632 87.445 25.656 88.307 ;
     RECT  29.28 86.627 29.712 88.309 ;
     RECT  87.936 87.827 90.264 88.547 ;
     RECT  67.2 86.581 67.752 88.549 ;
     RECT  2.4 88.165 9.72 88.595 ;
     RECT  60.096 87.827 60.216 88.643 ;
     RECT  32.256 86.675 32.424 88.645 ;
     RECT  75.216 87.299 75.576 88.645 ;
     RECT  67.104 88.549 67.752 88.691 ;
     RECT  32.208 88.645 32.424 88.787 ;
     RECT  21.504 87.589 22.968 88.789 ;
     RECT  67.2 88.691 67.752 88.885 ;
     RECT  78 86.965 78.648 88.885 ;
     RECT  21.456 88.789 22.968 88.931 ;
     RECT  65.52 88.115 65.544 88.931 ;
     RECT  79.728 87.877 81.912 88.931 ;
     RECT  39.792 87.875 43.224 88.933 ;
     RECT  88.8 88.547 90.264 88.979 ;
     RECT  61.8 87.827 62.112 89.173 ;
     RECT  29.088 88.309 29.712 89.221 ;
     RECT  61.632 89.173 62.112 89.315 ;
     RECT  10.992 87.827 19.704 89.459 ;
     RECT  29.088 89.221 30.36 89.459 ;
     RECT  39.792 88.933 43.416 89.459 ;
     RECT  26.784 87.011 26.808 89.461 ;
     RECT  83.4 87.635 83.712 89.461 ;
     RECT  84.768 86.099 84.984 89.461 ;
     RECT  12.144 89.459 19.704 89.507 ;
     RECT  24 87.827 24.504 89.555 ;
     RECT  32.256 88.787 32.424 89.557 ;
     RECT  2.4 88.595 9.672 89.603 ;
     RECT  60.192 88.643 60.216 89.701 ;
     RECT  59.952 89.701 60.216 89.747 ;
     RECT  38.736 87.827 38.76 89.749 ;
     RECT  78 88.885 78.744 89.939 ;
     RECT  88.8 88.979 89.784 89.939 ;
     RECT  71.232 88.885 71.256 89.987 ;
     RECT  86.544 87.875 86.616 89.989 ;
     RECT  5.232 89.603 9.672 90.083 ;
     RECT  92.016 88.837 92.04 90.083 ;
     RECT  67.2 88.885 68.616 90.131 ;
     RECT  74.736 88.645 75.576 90.275 ;
     RECT  26.688 89.461 26.808 90.277 ;
     RECT  41.904 89.459 43.416 90.325 ;
     RECT  44.4 87.875 58.488 90.325 ;
     RECT  21.456 88.931 22.824 90.373 ;
     RECT  24 89.555 24.312 90.373 ;
     RECT  63.6 88.933 63.624 90.515 ;
     RECT  10.992 89.459 11.112 90.517 ;
     RECT  12.144 89.507 15.912 90.517 ;
     RECT  21.456 90.373 24.312 90.563 ;
     RECT  67.2 90.131 68.52 90.563 ;
     RECT  2.4 89.603 4.152 90.565 ;
     RECT  5.232 90.083 6.456 90.565 ;
     RECT  16.944 89.507 19.704 90.565 ;
     RECT  94.2 33.107 94.512 90.565 ;
     RECT  78 89.939 78.696 90.611 ;
     RECT  24 90.563 24.312 90.613 ;
     RECT  0.144 89.221 0.168 90.659 ;
     RECT  21.456 90.563 22.872 90.659 ;
     RECT  33.696 85.763 33.72 90.659 ;
     RECT  10.992 90.517 15.912 90.755 ;
     RECT  16.944 90.565 20.04 90.757 ;
     RECT  21.456 90.659 21.528 90.757 ;
     RECT  26.16 90.277 26.808 90.851 ;
     RECT  86.544 89.989 87.288 90.851 ;
     RECT  83.4 89.461 84.984 90.853 ;
     RECT  7.68 90.083 9.672 90.899 ;
     RECT  24 90.613 25.032 90.899 ;
     RECT  83.28 90.853 84.984 90.899 ;
     RECT  87.216 90.851 87.288 91.043 ;
     RECT  67.2 90.563 67.752 91.091 ;
     RECT  29.088 89.459 29.712 91.093 ;
     RECT  11.952 90.755 15.912 91.139 ;
     RECT  34.8 79.571 35.112 91.141 ;
     RECT  93.792 90.565 94.512 91.141 ;
     RECT  15.312 91.139 15.912 91.235 ;
     RECT  80.544 88.931 81.912 91.235 ;
     RECT  69.744 89.461 69.768 91.237 ;
     RECT  2.304 90.565 6.456 91.283 ;
     RECT  69.312 91.237 69.768 91.283 ;
     RECT  15.36 91.235 15.912 91.331 ;
     RECT  80.544 91.235 81.72 91.331 ;
     RECT  32.256 89.557 32.472 91.477 ;
     RECT  38.544 89.749 38.76 91.619 ;
     RECT  41.904 90.325 58.488 91.619 ;
     RECT  22.8 90.659 22.872 91.667 ;
     RECT  38.544 91.619 38.568 91.667 ;
     RECT  16.944 90.757 21.528 91.715 ;
     RECT  15.36 91.331 15.48 91.763 ;
     RECT  17.232 91.715 21.528 91.859 ;
     RECT  83.28 90.899 83.712 91.859 ;
     RECT  59.952 89.747 59.976 91.907 ;
     RECT  84.768 90.899 84.984 91.907 ;
     RECT  61.8 89.315 62.112 92.005 ;
     RECT  76.896 90.661 76.92 92.051 ;
     RECT  87.216 91.043 87.24 92.099 ;
     RECT  84.96 91.907 84.984 92.147 ;
     RECT  10.848 91.141 10.872 92.149 ;
     RECT  11.952 91.139 14.184 92.149 ;
     RECT  7.68 90.899 9.576 92.197 ;
     RECT  28.464 91.093 29.712 92.197 ;
     RECT  15.36 91.763 15.384 92.245 ;
     RECT  10.848 92.149 14.184 92.293 ;
     RECT  34.8 91.141 35.208 92.293 ;
     RECT  69.312 91.283 69.336 92.387 ;
     RECT  21.504 91.859 21.528 92.389 ;
     RECT  6.864 92.197 9.576 92.435 ;
     RECT  39.792 89.459 40.512 92.435 ;
     RECT  41.904 91.619 57 92.437 ;
     RECT  67.2 91.091 67.512 92.437 ;
     RECT  72.6 87.731 73.32 92.437 ;
     RECT  58.464 91.619 58.488 92.483 ;
     RECT  40.2 92.435 40.512 92.581 ;
     RECT  31.872 91.477 32.472 92.629 ;
     RECT  10.656 92.293 14.184 92.675 ;
     RECT  17.232 91.859 20.52 92.675 ;
     RECT  41.856 92.437 57 92.675 ;
     RECT  65.088 89.461 65.112 92.675 ;
     RECT  10.656 92.675 13.704 92.723 ;
     RECT  28.416 92.197 29.712 92.725 ;
     RECT  27.984 92.725 29.712 92.771 ;
     RECT  66.864 92.437 67.512 92.771 ;
     RECT  2.304 91.283 5.832 92.821 ;
     RECT  15.312 92.245 15.384 92.917 ;
     RECT  15.312 92.917 15.96 92.963 ;
     RECT  17.232 92.675 20.184 92.963 ;
     RECT  70.8 92.293 70.824 92.963 ;
     RECT  72.48 92.437 73.32 92.963 ;
     RECT  93.792 91.141 94.92 92.963 ;
     RECT  81.696 91.331 81.72 93.059 ;
     RECT  26.16 90.851 26.184 93.107 ;
     RECT  2.304 92.821 5.88 93.109 ;
     RECT  6.864 92.435 8.112 93.109 ;
     RECT  2.304 93.109 8.112 93.155 ;
     RECT  7.392 93.155 8.112 93.299 ;
     RECT  42.96 92.675 57 93.299 ;
     RECT  75.552 90.275 75.576 93.445 ;
     RECT  34.8 92.293 35.496 93.491 ;
     RECT  2.304 93.155 5.928 93.539 ;
     RECT  10.656 92.723 11.784 93.539 ;
     RECT  17.232 92.963 20.136 93.539 ;
     RECT  44.208 93.299 57 93.539 ;
     RECT  80.544 91.331 80.568 93.539 ;
     RECT  17.232 93.539 17.256 93.587 ;
     RECT  41.856 92.675 41.88 93.635 ;
     RECT  44.256 93.539 56.856 93.635 ;
     RECT  31.872 92.629 33.096 93.685 ;
     RECT  4.176 93.539 5.928 93.731 ;
     RECT  5.28 93.731 5.928 93.827 ;
     RECT  11.376 93.539 11.784 93.877 ;
     RECT  12.768 92.723 13.704 93.877 ;
     RECT  11.376 93.877 13.704 93.923 ;
     RECT  9.216 92.435 9.576 94.019 ;
     RECT  11.76 93.923 13.704 94.019 ;
     RECT  21.504 92.389 21.96 94.019 ;
     RECT  31.872 93.685 33.144 94.019 ;
     RECT  40.2 92.581 40.632 94.021 ;
     RECT  4.176 93.731 4.2 94.115 ;
     RECT  37.536 92.149 37.56 94.115 ;
     RECT  21.504 94.019 21.528 94.163 ;
     RECT  44.256 93.635 55.368 94.163 ;
     RECT  44.832 94.163 55.368 94.211 ;
     RECT  61.056 92.005 62.112 94.307 ;
     RECT  65.52 93.301 65.544 94.307 ;
     RECT  70.08 93.349 70.104 94.307 ;
     RECT  72.6 92.963 73.32 94.307 ;
     RECT  81.648 93.157 81.672 94.307 ;
     RECT  42.96 93.299 42.984 94.309 ;
     RECT  18.6 93.539 20.136 94.355 ;
     RECT  27.984 92.771 28.008 94.355 ;
     RECT  31.872 94.019 31.896 94.355 ;
     RECT  42.96 94.309 43.176 94.355 ;
     RECT  74.592 93.445 75.576 94.355 ;
     RECT  20.112 94.355 20.136 94.403 ;
     RECT  15.936 92.963 15.96 94.405 ;
     RECT  5.28 93.827 5.304 94.547 ;
     RECT  11.76 94.019 12.024 94.547 ;
     RECT  14.784 93.781 14.808 94.547 ;
     RECT  12 94.547 12.024 94.595 ;
     RECT  15.936 94.405 16.008 94.595 ;
     RECT  29.088 92.771 29.712 94.595 ;
     RECT  33.12 94.019 33.144 94.595 ;
     RECT  30.72 94.501 30.744 94.597 ;
     RECT  30.72 94.597 30.84 94.643 ;
     RECT  34.8 93.491 35.448 94.643 ;
     RECT  44.88 94.211 55.368 94.643 ;
     RECT  38.688 94.501 38.712 94.645 ;
     RECT  2.4 93.539 2.904 94.691 ;
     RECT  9.216 94.019 9.24 94.691 ;
     RECT  13.2 94.019 13.608 94.691 ;
     RECT  15.984 94.595 16.008 94.691 ;
     RECT  43.152 94.355 43.176 94.691 ;
     RECT  44.88 94.643 54.984 94.691 ;
     RECT  56.4 93.635 56.856 94.691 ;
     RECT  75.792 94.453 75.816 94.691 ;
     RECT  30.816 94.643 30.84 94.739 ;
     RECT  38.688 94.645 38.808 94.739 ;
     RECT  90.624 94.597 90.648 94.739 ;
     RECT  38.784 94.739 38.808 94.787 ;
     RECT  45.6 94.691 54.984 94.787 ;
     RECT  97.008 94.597 97.032 94.787 ;
     RECT  18.6 94.355 19.032 94.835 ;
     RECT  40.2 94.021 41.496 94.883 ;
     RECT  26.112 93.397 26.136 94.979 ;
     RECT  2.4 94.691 2.712 95.049 ;
     RECT  7.8 93.299 8.112 95.049 ;
     RECT  13.2 94.691 13.512 95.049 ;
     RECT  18.6 94.835 18.912 95.049 ;
     RECT  24 90.899 24.312 95.049 ;
     RECT  29.4 94.595 29.712 95.049 ;
     RECT  34.8 94.643 35.112 95.049 ;
     RECT  40.2 94.883 40.512 95.049 ;
     RECT  56.4 94.691 56.712 95.049 ;
     RECT  61.8 94.307 62.112 95.049 ;
     RECT  67.2 92.771 67.512 95.049 ;
     RECT  72.6 94.307 72.912 95.049 ;
     RECT  78 90.611 78.312 95.049 ;
     RECT  83.4 91.859 83.712 95.049 ;
     RECT  88.8 89.939 89.112 95.049 ;
     RECT  2.4 95.049 2.52 95.063 ;
     RECT  7.8 95.049 7.92 95.063 ;
     RECT  13.2 95.049 13.32 95.063 ;
     RECT  18.6 95.049 18.72 95.063 ;
     RECT  24 95.049 24.12 95.063 ;
     RECT  29.4 95.049 29.52 95.063 ;
     RECT  34.8 95.049 34.92 95.063 ;
     RECT  40.2 95.049 40.32 95.063 ;
     RECT  45.6 94.787 48.84 95.063 ;
     RECT  56.4 95.049 56.52 95.063 ;
     RECT  61.8 95.049 61.92 95.063 ;
     RECT  67.2 95.049 67.32 95.063 ;
     RECT  72.6 95.049 72.72 95.063 ;
     RECT  78 95.049 78.12 95.063 ;
     RECT  83.4 95.049 83.52 95.063 ;
     RECT  88.8 95.049 88.92 95.063 ;
     RECT  94.2 92.963 94.92 95.063 ;
     RECT  94.896 95.063 94.92 95.123 ;
     RECT  45.936 95.063 48.84 96.325 ;
     RECT  50.352 94.787 54.984 96.997 ;
     RECT  45.84 96.325 48.84 97.168 ;
     RECT  50.256 96.997 54.984 97.168 ;
  END
END qkd_kv_grp_ctl_p
END LIBRARY
